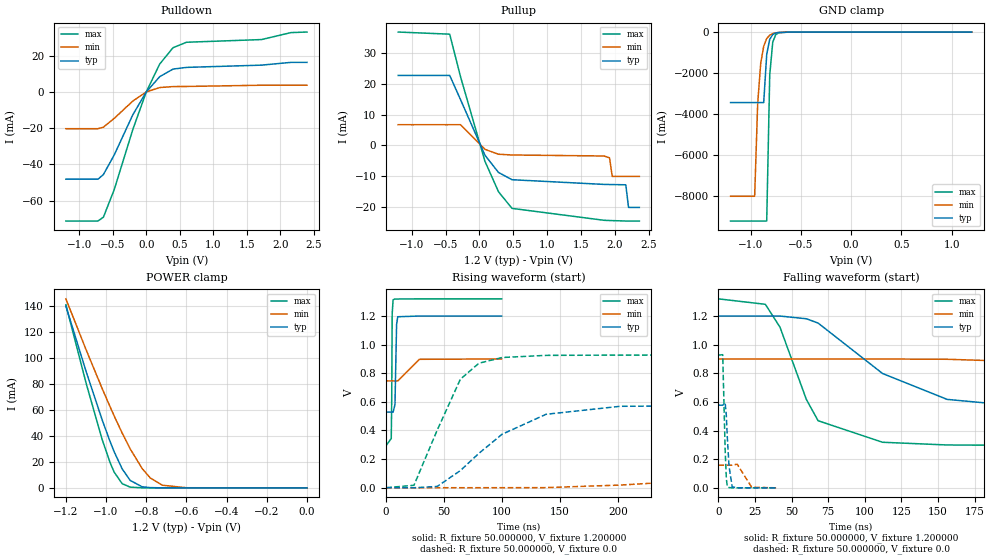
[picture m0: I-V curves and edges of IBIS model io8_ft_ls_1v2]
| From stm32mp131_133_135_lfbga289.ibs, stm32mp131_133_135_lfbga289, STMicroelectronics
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|   Model io8_ft_ls_1v2
[Model]  io8_ft_ls_1v2
Model_type I/O
Polarity   Non-Inverting
Enable   Active-Low
Vinl =   0.360000V
Vinh =   0.840000V
Vmeas =  0.600000V
Cref =   50.000000pF
Rref =   100.000000M
Vref =   0.0V
C_comp   2.961900pF   2.937700pF   2.984500pF
[Temperature Range]   25.000000   0.140000k   -40.000000
[Pullup Reference]   1.200000V   0.900000V   1.320000V
[Pulldown Reference]   0.0V   0.0V   0.0V
[POWER Clamp Reference]   1.200000V   0.900000V   1.320000V
[GND Clamp Reference]   0.0V   0.0V   0.0V
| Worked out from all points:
|   slope of the pulldown table from 0 to 0.18 V, typ, clamps not added: 23.2 ohm
|   slope of the pullup table from 0 to 0.18 V, typ, clamps not added: 28.5 ohm
|   GND clamp passes 1 mA (typ) near -0.47 V on its own axis
|   POWER clamp passes 1 mA (typ) near -0.83 V on its own axis
|   rising waveform, R_fixture 50.000000, V_fixture 1.200000: 20-80 % time 810ps typ, 2.62ns min, 429ps max; typ from 0.529 V to 1.2 V
|   rising waveform, R_fixture 50.000000, V_fixture 0.0: 20-80 % time 55.8ns typ, 161ns min, 28.4ns max; typ from 0 V to 0.577 V
|   falling waveform, R_fixture 50.000000, V_fixture 1.200000: 20-80 % time 58ns typ, 166ns min, 23.4ns max; typ from 1.2 V to 0.529 V
|   falling waveform, R_fixture 50.000000, V_fixture 0.0: 20-80 % time 2.01ns typ, 4.77ns min, 1.41ns max; typ from 0.577 V to 0 V
[Pulldown]
|Voltage   I(typ)   I(min)   I(max)
-1.2V     -48.14mA   -20.28mA   -71.24mA
-720mV    -48.14mA   -20.28mA   -71.24mA
-640mV    -45.58mA   -19.44mA   -69.11mA
-480mV    -34.9mA    -14.62mA   -54.1mA
-200mV    -12.54mA   -4.989mA   -20.65mA
0V        0A         0A         0A
200mV     8.434mA    2.44mA     15.39mA
400mV     12.64mA    2.983mA    24.45mA
600mV     13.57mA    3.041mA    27.45mA
1.72V     14.81mA    3.724mA    28.93mA
2.16V     16.34mA    3.724mA    32.78mA
2.4V      16.34mA    3.724mA    33.09mA
[Pullup]
|Voltage   I(typ)   I(min)   I(max)
-1.2V     22.63mA    6.709mA    36.64mA
-440mV    22.63mA    6.709mA    35.95mA
-280mV    14.81mA    6.709mA    22.2mA
80mV      -3.13mA    -1.249mA   -5.09mA
280mV     -8.709mA   -2.831mA   -14.93mA
480mV     -11.06mA   -3.074mA   -20.32mA
1.84V     -12.58mA   -3.4mA     -24.17mA
1.92V     -12.61mA   -4mA       -24.24mA
1.96V     -12.63mA   -10mA      -24.27mA
2.16V     -12.7mA    -10mA      -24.4mA
2.2V      -20mA      -10mA      -24.4mA
2.36V     -20mA      -10mA      -24.4mA
[GND_clamp]
|Voltage   I(typ)   I(min)   I(max)
-1.2V     -3.45A     -8.037A    -9.248A
-960mV    -3.45A     -8.037A    -9.248A
-930mV    -3.45A     -3.504A    -9.248A
-900mV    -3.45A     -1.544A    -9.248A
-870mV    -3.45A     -693.1mA   -9.248A
-840mV    -1.093A    -319.7mA   -9.248A
-810mV    -355mA     -153mA     -2.104A
-780mV    -122.1mA   -76.47mA   -492.8mA
-750mV    -46.85mA   -40.02mA   -125.6mA
-720mV    -21.41mA   -22.04mA   -38.94mA
-630mV    -6.028mA   -5.668mA   -6.589mA
1.2V      0A         44.19nA    0A
[POWER_clamp]
|Voltage   I(typ)   I(min)   I(max)
-1.2V     139.7mA    145.3mA    140.7mA
-1.1V     89.79mA    106.4mA    80.86mA
-1.02V    52.48mA    76.58mA    37.41mA
-980mV    35.57mA    62.3mA     19.38mA
-960mV    27.85mA    55.39mA    12.18mA
-920mV    14.63mA    42.15mA    3.226mA
-880mV    5.71mA     29.97mA    537.4uA
-820mV    777uA      14.76mA    28.17uA
-780mV    170.8uA    7.604mA    3.856uA
-720mV    16.71uA    2.018mA    195.3nA
-600mV    157.7nA    78.69uA    0A
0V        0A         56.62nA    0A
[Ramp]
| variable   typ   min   max
dV/dt_r  0.34638/55.73551n   95.16562m/0.16077u  0.55615/28.34400n
dV/dt_f  0.40279/57.96058n   92.02200m/0.16561u  0.61499/23.31715n
R_load = 50.000000
[Rising Waveform]
R_fixture= 50.000000
V_fixture= 1.200000
V_fixture_min= 0.900000
V_fixture_max= 1.320000
|time   V(typ)   V(min)   V(max)
0s        528.7mV    746.7mV    295mV
4.404ns   528.7mV    746.7mV    344.3mV
4.805ns   528.7mV    746.7mV    622.8mV
5.205ns   528.7mV    746.7mV    1.216V
6.006ns   528.2mV    746.7mV    1.314V
7.608ns   580.9mV    746.7mV    1.319V
9.009ns   1.141V     746.7mV    1.319V
10.01ns   1.195V     746.7mV    1.319V
28.63ns   1.2V       897.6mV    1.32V
99.7ns    1.2V       900mV      1.32V
[Rising Waveform]
R_fixture= 50.000000
V_fixture= 0.0
V_fixture_min= 0.0
V_fixture_max= 0.0
|time   V(typ)   V(min)   V(max)
0s        2.345nV    636.1nV    922.7pV
24.02ns   -141.1uV   -931.8uV   17.18mV
44.04ns   8.825mV    -31.22uV   401.7mV
64.06ns   119.6mV    -21.33uV   758.1mV
80.08ns   240.1mV    31.02uV    870.2mV
100.1ns   373.8mV    122.6uV    910mV
138.1ns   513.2mV    840.2uV    925.1mV
202.2ns   569.2mV    18.48mV    926.9mV
466.5ns   577.2mV    147.1mV    926.9mV
997ns     577.3mV    158.7mV    926.9mV
[Falling Waveform]
R_fixture= 50.000000
V_fixture= 1.200000
V_fixture_min= 0.900000
V_fixture_max= 1.320000
|time   V(typ)   V(min)   V(max)
0s        1.2V       900mV      1.32V
32.03ns   1.2V       900.3mV    1.282V
42.04ns   1.2V       900mV      1.122V
60.06ns   1.181V     900mV      617.2mV
68.07ns   1.151V     900mV      468.8mV
112.1ns   798.8mV    899.9mV    318.4mV
156.2ns   617.9mV    898.1mV    299.5mV
234.2ns   544mV      872.9mV    295.3mV
442.4ns   528.8mV    767.3mV    295mV
997ns     528.7mV    746.7mV    295mV
[Falling Waveform]
R_fixture= 50.000000
V_fixture= 0.0
V_fixture_min= 0.0
V_fixture_max= 0.0
|time   V(typ)   V(min)   V(max)
0s        577.3mV    158.7mV    926.9mV
2.883ns   577.3mV    158.7mV    930.2mV
4.565ns   592.3mV    158.7mV    263.9mV
5.365ns   503.8mV    158.7mV    65.13mV
6.006ns   356.9mV    158.7mV    8.836mV
7.207ns   150mV      158.7mV    1.805mV
9.369ns   6.488mV    158.6mV    332.5uV
12.81ns   436.3uV    165mV      88.28uV
22.66ns   4.733uV    4.383mV    25.44uV
39.88ns   2.345nV    636.1nV    922.7pV
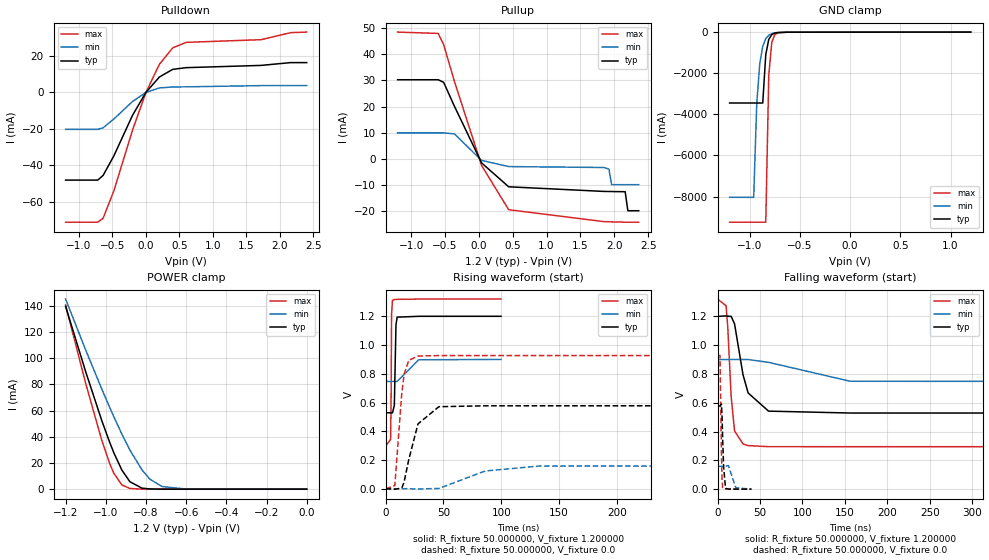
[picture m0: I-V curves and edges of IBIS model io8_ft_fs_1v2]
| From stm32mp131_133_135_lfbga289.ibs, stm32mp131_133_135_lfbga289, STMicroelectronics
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|   Model io8_ft_fs_1v2
[Model]  io8_ft_fs_1v2
Model_type I/O
Polarity   Non-Inverting
Enable   Active-Low
Vinl =   0.360000V
Vinh =   0.840000V
Vmeas =  0.600000V
Cref =   50.000000pF
Rref =   100.000000M
Vref =   0.0V
C_comp   2.961900pF   2.937700pF   2.984500pF
[Temperature Range]   25.000000   0.140000k   -40.000000
[Pullup Reference]   1.200000V   0.900000V   1.320000V
[Pulldown Reference]   0.0V   0.0V   0.0V
[POWER Clamp Reference]   1.200000V   0.900000V   1.320000V
[GND Clamp Reference]   0.0V   0.0V   0.0V
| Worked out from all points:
|   slope of the pulldown table from 0 to 0.18 V, typ, clamps not added: 23.2 ohm
|   slope of the pullup table from 0 to 0.18 V, typ, clamps not added: 28.5 ohm
|   GND clamp passes 1 mA (typ) near -0.47 V on its own axis
|   POWER clamp passes 1 mA (typ) near -0.83 V on its own axis
|   rising waveform, R_fixture 50.000000, V_fixture 1.200000: 20-80 % time 804ps typ, 2.62ns min, 429ps max; typ from 0.529 V to 1.2 V
|   rising waveform, R_fixture 50.000000, V_fixture 0.0: 20-80 % time 10.7ns typ, 29.3ns min, 5.51ns max; typ from 0 V to 0.577 V
|   falling waveform, R_fixture 50.000000, V_fixture 1.200000: 20-80 % time 13.6ns typ, 36.3ns min, 5.59ns max; typ from 1.2 V to 0.529 V
|   falling waveform, R_fixture 50.000000, V_fixture 0.0: 20-80 % time 2.02ns typ, 4.76ns min, 1.41ns max; typ from 0.577 V to 0 V
[Pulldown]
|Voltage   I(typ)   I(min)   I(max)
-1.2V     -48.14mA   -20.28mA   -71.24mA
-720mV    -48.14mA   -20.28mA   -71.24mA
-640mV    -45.58mA   -19.44mA   -69.11mA
-480mV    -34.9mA    -14.62mA   -54.1mA
-200mV    -12.54mA   -4.99mA    -20.65mA
0V        0A         0A         0A
200mV     8.434mA    2.44mA     15.39mA
400mV     12.64mA    2.983mA    24.45mA
600mV     13.57mA    3.042mA    27.45mA
1.72V     14.81mA    3.724mA    28.93mA
2.16V     16.34mA    3.724mA    32.78mA
2.4V      16.34mA    3.724mA    33.09mA
[Pullup]
|Voltage   I(typ)   I(min)   I(max)
-1.2V     30.28mA    9.902mA    48.58mA
-600mV    30.28mA    9.902mA    48.06mA
-520mV    29.3mA     9.902mA    43.76mA
-360mV    20.06mA    9.471mA    29.58mA
40mV      -1.628mA   -670.7uA   -2.623mA
440mV     -10.81mA   -3.051mA   -19.6mA
1.84V     -12.58mA   -3.4mA     -24.17mA
1.92V     -12.61mA   -4mA       -24.24mA
1.96V     -12.63mA   -10mA      -24.27mA
2.16V     -12.7mA    -10mA      -24.4mA
2.2V      -20mA      -10mA      -24.4mA
2.36V     -20mA      -10mA      -24.4mA
[GND_clamp]
|Voltage   I(typ)   I(min)   I(max)
-1.2V     -3.45A     -8.037A    -9.248A
-960mV    -3.45A     -8.037A    -9.248A
-930mV    -3.45A     -3.504A    -9.248A
-900mV    -3.45A     -1.544A    -9.248A
-870mV    -3.45A     -693.1mA   -9.248A
-840mV    -1.093A    -319.7mA   -9.248A
-810mV    -355mA     -153mA     -2.104A
-780mV    -122.1mA   -76.47mA   -492.8mA
-750mV    -46.85mA   -40.02mA   -125.6mA
-720mV    -21.41mA   -22.04mA   -38.94mA
-630mV    -6.028mA   -5.668mA   -6.589mA
1.2V      0A         44.19nA    0A
[POWER_clamp]
|Voltage   I(typ)   I(min)   I(max)
-1.2V     139.7mA    145.3mA    140.7mA
-1.1V     89.79mA    106.4mA    80.86mA
-1.02V    52.48mA    76.58mA    37.41mA
-980mV    35.57mA    62.3mA     19.38mA
-960mV    27.85mA    55.39mA    12.18mA
-920mV    14.63mA    42.15mA    3.226mA
-880mV    5.71mA     29.97mA    537.4uA
-820mV    777uA      14.76mA    28.17uA
-780mV    170.8uA    7.604mA    3.856uA
-720mV    16.71uA    2.018mA    195.3nA
-600mV    157.7nA    78.69uA    0A
0V        0A         56.62nA    0A
[Ramp]
| variable   typ   min   max
dV/dt_r  0.34636/10.60753n   95.23162m/29.26969n 0.55615/5.31109n
dV/dt_f  0.40279/13.54092n   92.01000m/36.22856n 0.61499/5.49395n
R_load = 50.000000
[Rising Waveform]
R_fixture= 50.000000
V_fixture= 1.200000
V_fixture_min= 0.900000
V_fixture_max= 1.320000
|time   V(typ)   V(min)   V(max)
0s        528.7mV    746.6mV    295mV
4.404ns   528.7mV    746.6mV    343.9mV
4.805ns   528.7mV    746.6mV    621.1mV
5.205ns   528.7mV    746.6mV    1.214V
6.006ns   528.2mV    746.6mV    1.312V
7.608ns   580.2mV    746.6mV    1.317V
9.009ns   1.14V      746.6mV    1.317V
10.01ns   1.194V     746.6mV    1.318V
28.63ns   1.2V       897.4mV    1.32V
99.7ns    1.2V       900mV      1.32V
[Rising Waveform]
R_fixture= 50.000000
V_fixture= 0.0
V_fixture_min= 0.0
V_fixture_max= 0.0
|time   V(typ)   V(min)   V(max)
0s        2.345nV    636nV      922.7pV
8.008ns   -2.94mV    635.6nV    21.45mV
14.01ns   4.201mV    699.6nV    661.9mV
16.02ns   46.31mV    -1.753uV   795.9mV
20.02ns   201.4mV    39.92uV    893.2mV
28.03ns   451.2mV    -1.963mV   923.3mV
46.05ns   571mV      2.157mV    926.8mV
86.09ns   577.1mV    123.6mV    926.9mV
132.1ns   577.2mV    157.5mV    926.9mV
997ns     577.3mV    158.7mV    926.9mV
[Falling Waveform]
R_fixture= 50.000000
V_fixture= 1.200000
V_fixture_min= 0.900000
V_fixture_max= 1.320000
|time   V(typ)   V(min)   V(max)
0s        1.2V       900mV      1.32V
10.01ns   1.203V     900mV      1.274V
12.01ns   1.201V     899.9mV    1.129V
16.02ns   1.2V       900.9mV    645.5mV
20.02ns   1.148V     900.7mV    404.1mV
30.03ns   793.9mV    900.4mV    314mV
36.04ns   668.1mV    900.1mV    302.3mV
60.06ns   541.9mV    880.7mV    295.2mV
156.2ns   528.7mV    749.3mV    295mV
997ns     528.7mV    746.6mV    295mV
[Falling Waveform]
R_fixture= 50.000000
V_fixture= 0.0
V_fixture_min= 0.0
V_fixture_max= 0.0
|time   V(typ)   V(min)   V(max)
0s        577.3mV    158.7mV    926.9mV
2.883ns   577.3mV    158.7mV    929mV
4.565ns   590.8mV    158.7mV    262.9mV
5.365ns   502mV      158.7mV    65.1mV
6.006ns   354.9mV    158.7mV    9.849mV
7.207ns   149.3mV    158.7mV    2.954mV
9.449ns   5.48mV     158.6mV    1.574mV
12.81ns   910.6uV    164.1mV    793.1uV
21.54ns   477.6uV    9.491mV    156.6uV
39.88ns   2.345nV    636nV      922.7pV
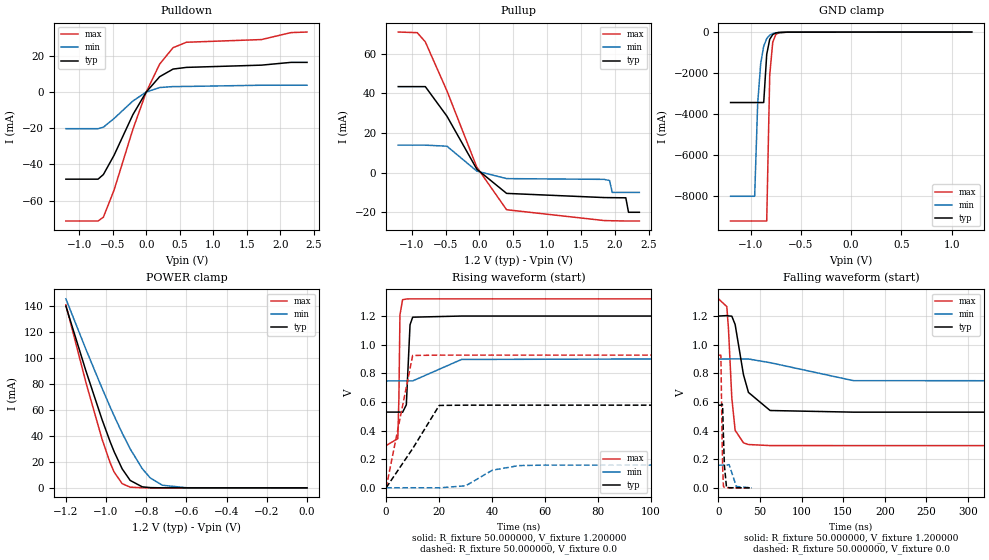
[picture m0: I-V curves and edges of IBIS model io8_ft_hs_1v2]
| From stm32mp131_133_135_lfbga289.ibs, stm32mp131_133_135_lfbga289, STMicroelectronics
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|   Model io8_ft_hs_1v2
[Model]  io8_ft_hs_1v2
Model_type I/O
Polarity   Non-Inverting
Enable   Active-Low
Vinl =   0.360000V
Vinh =   0.840000V
Vmeas =  0.600000V
Cref =   50.000000pF
Rref =   100.000000M
Vref =   0.0V
C_comp   2.961900pF   2.937700pF   2.984500pF
[Temperature Range]   25.000000   0.140000k   -40.000000
[Pullup Reference]   1.200000V   0.900000V   1.320000V
[Pulldown Reference]   0.0V   0.0V   0.0V
[POWER Clamp Reference]   1.200000V   0.900000V   1.320000V
[GND Clamp Reference]   0.0V   0.0V   0.0V
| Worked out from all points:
|   slope of the pulldown table from 0 to 0.18 V, typ, clamps not added: 23.2 ohm
|   slope of the pullup table from 0 to 0.18 V, typ, clamps not added: 28.5 ohm
|   GND clamp passes 1 mA (typ) near -0.47 V on its own axis
|   POWER clamp passes 1 mA (typ) near -0.83 V on its own axis
|   rising waveform, R_fixture 50.000000, V_fixture 1.200000: 20-80 % time 805ps typ, 2.57ns min, 432ps max; typ from 0.529 V to 1.2 V
|   rising waveform, R_fixture 50.000000, V_fixture 0.0: 20-80 % time 12ns typ, 9.76ns min, 6.02ns max; typ from 0 V to 0.577 V
|   falling waveform, R_fixture 50.000000, V_fixture 1.200000: 20-80 % time 13.8ns typ, 36.2ns min, 5.67ns max; typ from 1.2 V to 0.529 V
|   falling waveform, R_fixture 50.000000, V_fixture 0.0: 20-80 % time 2.02ns typ, 4.76ns min, 1.41ns max; typ from 0.577 V to 0 V
[Pulldown]
|Voltage   I(typ)   I(min)   I(max)
-1.2V     -48.14mA   -20.28mA   -71.24mA
-720mV    -48.14mA   -20.28mA   -71.24mA
-640mV    -45.58mA   -19.44mA   -69.11mA
-480mV    -34.9mA    -14.62mA   -54.1mA
-200mV    -12.54mA   -4.99mA    -20.65mA
0V        0A         0A         0A
200mV     8.434mA    2.44mA     15.39mA
400mV     12.64mA    2.983mA    24.45mA
600mV     13.57mA    3.042mA    27.45mA
1.72V     14.81mA    3.724mA    28.93mA
2.16V     16.34mA    3.724mA    32.78mA
2.4V      16.34mA    3.724mA    33.09mA
[Pullup]
|Voltage   I(typ)   I(min)   I(max)
-1.2V     43.36mA    13.85mA    70.88mA
-920mV    43.36mA    13.85mA    70.57mA
-800mV    43.36mA    13.85mA    65.93mA
-480mV    28.42mA    13.32mA    41.16mA
-40mV     1.753mA    765uA      2.773mA
400mV     -10.47mA   -3.023mA   -18.71mA
1.84V     -12.58mA   -3.4mA     -24.17mA
1.92V     -12.61mA   -4mA       -24.24mA
1.96V     -12.63mA   -10mA      -24.27mA
2.16V     -12.7mA    -10mA      -24.4mA
2.2V      -20mA      -10mA      -24.4mA
2.36V     -20mA      -10mA      -24.4mA
[GND_clamp]
|Voltage   I(typ)   I(min)   I(max)
-1.2V     -3.45A     -8.037A    -9.248A
-960mV    -3.45A     -8.037A    -9.248A
-930mV    -3.45A     -3.504A    -9.248A
-900mV    -3.45A     -1.544A    -9.248A
-870mV    -3.45A     -693.1mA   -9.248A
-840mV    -1.093A    -319.7mA   -9.248A
-810mV    -355mA     -153mA     -2.104A
-780mV    -122.1mA   -76.47mA   -492.8mA
-750mV    -46.85mA   -40.02mA   -125.6mA
-720mV    -21.41mA   -22.04mA   -38.94mA
-630mV    -6.028mA   -5.668mA   -6.589mA
1.2V      0A         44.19nA    0A
[POWER_clamp]
|Voltage   I(typ)   I(min)   I(max)
-1.2V     139.7mA    145.3mA    140.7mA
-1.1V     89.79mA    106.4mA    80.86mA
-1.02V    52.48mA    76.58mA    37.41mA
-980mV    35.57mA    62.3mA     19.38mA
-960mV    27.85mA    55.39mA    12.18mA
-920mV    14.63mA    42.15mA    3.226mA
-880mV    5.71mA     29.97mA    537.4uA
-820mV    777uA      14.76mA    28.17uA
-780mV    170.8uA    7.604mA    3.856uA
-720mV    16.71uA    2.018mA    195.3nA
-600mV    157.7nA    78.69uA    0A
0V        0A         56.62nA    0A
[Ramp]
| variable   typ   min   max
dV/dt_r  0.34636/3.33019n   95.23762m/8.95409n  0.55615/1.79980n
dV/dt_f  0.40279/13.72677n   92.01600m/36.09763n 0.61499/5.55050n
R_load = 50.000000
[Rising Waveform]
R_fixture= 50.000000
V_fixture= 1.200000
V_fixture_min= 0.900000
V_fixture_max= 1.320000
|time   V(typ)   V(min)   V(max)
0s        528.7mV    746.6mV    295mV
4.404ns   528.7mV    746.6mV    343.3mV
4.805ns   528.7mV    746.6mV    624.7mV
5.205ns   528.7mV    746.6mV    1.209V
6.206ns   527.4mV    746.6mV    1.314V
7.608ns   579.4mV    746.6mV    1.319V
9.009ns   1.139V     746.6mV    1.32V
10.01ns   1.192V     746.6mV    1.32V
28.43ns   1.2V       896.5mV    1.32V
99.7ns    1.2V       900mV      1.32V
[Rising Waveform]
R_fixture= 50.000000
V_fixture= 0.0
V_fixture_min= 0.0
V_fixture_max= 0.0
|time   V(typ)   V(min)   V(max)
0s        9.363nV    634.2nV    -5.299nV
10.01ns   273.7mV    634.1nV    924.5mV
20.02ns   575.3mV    -702.8uV   926.9mV
30.03ns   577.2mV    13.8mV     926.9mV
40.04ns   577.2mV    122.4mV    926.9mV
50.05ns   577.2mV    155mV      926.9mV
60.06ns   577.2mV    158.3mV    926.9mV
991ns     577.3mV    158.7mV    926.9mV
[Falling Waveform]
R_fixture= 50.000000
V_fixture= 1.200000
V_fixture_min= 0.900000
V_fixture_max= 1.320000
|time   V(typ)   V(min)   V(max)
0s        1.2V       900mV      1.32V
10.01ns   1.203V     900mV      1.266V
12.01ns   1.201V     899.9mV    1.111V
16.02ns   1.199V     900.9mV    628.2mV
20.02ns   1.141V     900.7mV    402.3mV
30.03ns   790.5mV    900.4mV    314.4mV
36.04ns   666.6mV    900.1mV    302.6mV
62.06ns   540.2mV    874.5mV    295.2mV
162.2ns   528.7mV    748.8mV    295mV
997ns     528.7mV    746.6mV    295mV
[Falling Waveform]
R_fixture= 50.000000
V_fixture= 0.0
V_fixture_min= 0.0
V_fixture_max= 0.0
|time   V(typ)   V(min)   V(max)
0s        577.3mV    158.7mV    926.9mV
2.883ns   577.3mV    158.7mV    926.2mV
4.484ns   585mV      158.7mV    282.9mV
4.965ns   574.7mV    158.7mV    149mV
5.926ns   368.9mV    158.7mV    11.45mV
7.127ns   155.5mV    158.7mV    3.08mV
9.61ns    4.03mV     158.6mV    1.538mV
12.81ns   921.9uV    162.2mV    760.2uV
21.46ns   468.3uV    9.586mV    147.5uV
39.88ns   9.363nV    634.2nV    -5.299nV
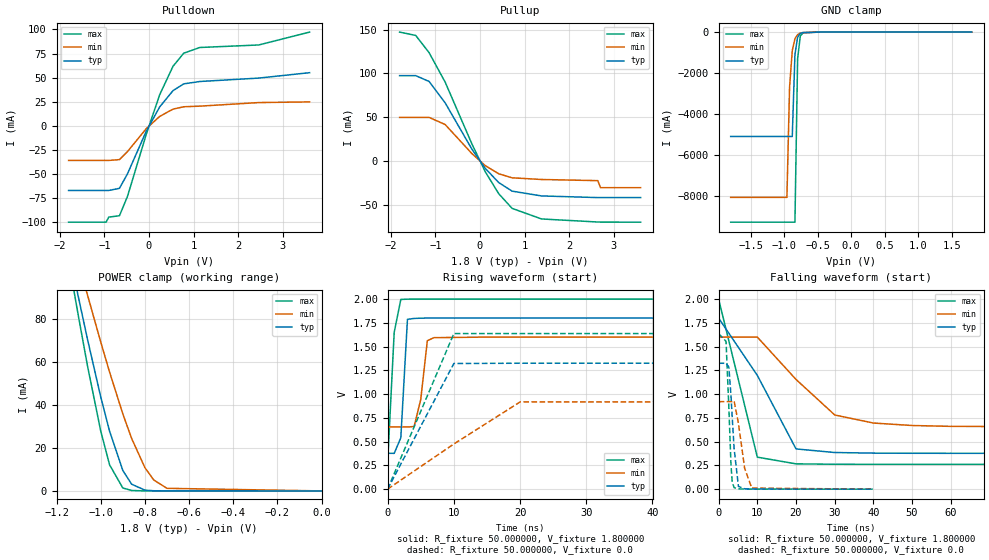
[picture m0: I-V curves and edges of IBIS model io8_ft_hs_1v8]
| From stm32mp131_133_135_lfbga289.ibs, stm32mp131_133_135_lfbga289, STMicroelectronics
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|   Model io8_ft_hs_1v8
[Model]  io8_ft_hs_1v8
Model_type I/O
Polarity   Non-Inverting
Enable   Active-Low
Vinl =   0.540000V
Vinh =   1.260000V
Vmeas =  0.900000V
Cref =   50.000000pF
Rref =   100.000000M
Vref =   0.0V
C_comp   3.181500pF   3.164300pF   3.208900pF
[Temperature Range]   25.000000   0.140000k   -40.000000
[Pullup Reference]   1.800000V   1.600000V   2.000000V
[Pulldown Reference]   0.0V   0.0V   0.0V
[POWER Clamp Reference]   1.800000V   1.600000V   2.000000V
[GND Clamp Reference]   0.0V   0.0V   0.0V
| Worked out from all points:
|   slope of the pulldown table from 0 to 0.27 V, typ, clamps not added: 12.5 ohm
|   slope of the pullup table from 0 to 0.27 V, typ, clamps not added: 16 ohm
|   GND clamp passes 1 mA (typ) near -0.47 V on its own axis
|   POWER clamp passes 1 mA (typ) near -0.83 V on its own axis
|   rising waveform, R_fixture 50.000000, V_fixture 1.800000: 20-80 % time 686ps typ, 1.1ns min, 753ps max; typ from 0.377 V to 1.8 V
|   rising waveform, R_fixture 50.000000, V_fixture 0.0: 20-80 % time 6.02ns typ, 12ns min, 6.01ns max; typ from 0 V to 1.32 V
|   falling waveform, R_fixture 50.000000, V_fixture 1.800000: 20-80 % time 12.2ns typ, 14.1ns min, 6.28ns max; typ from 1.8 V to 0.377 V
|   falling waveform, R_fixture 50.000000, V_fixture 0.0: 20-80 % time 1.22ns typ, 1.91ns min, 860ps max; typ from 1.32 V to 0 V
[Pulldown]
|Voltage   I(typ)   I(min)   I(max)
-1.8V     -67.09mA   -35.91mA   -100mA
-960mV    -67.09mA   -35.91mA   -100mA
-900mV    -67.09mA   -35.91mA   -94.73mA
-660mV    -64.86mA   -35.04mA   -93.29mA
-480mV    -49.73mA   -26.7mA    -73.15mA
-60mV     -5.61mA    -2.937mA   -8.854mA
240mV     19.58mA    9.767mA    32.18mA
540mV     36.57mA    17.36mA    61.85mA
780mV     43.58mA    19.81mA    75.41mA
1.14V     46.02mA    20.44mA    81.32mA
2.46V     49.57mA    24.16mA    83.94mA
3.6V      55.18mA    24.86mA    97.31mA
[Pullup]
|Voltage   I(typ)   I(min)   I(max)
-1.8V     97.52mA    49.96mA    147.1mA
-1.44V    97.52mA    49.96mA    143.3mA
-1.14V    90.93mA    49.96mA    123.7mA
-780mV    66.55mA    41.87mA    90.17mA
-180mV    13.76mA    8.769mA    19.71mA
120mV     -8.082mA   -4.954mA   -11.99mA
420mV     -24.19mA   -14.18mA   -36.87mA
720mV     -33.97mA   -18.78mA   -53.57mA
1.38V     -39.41mA   -20.69mA   -65.63mA
2.64V     -41.3mA    -22mA      -69.09mA
2.7V      -41.3mA    -30mA      -69.18mA
3.6V      -41.3mA    -30mA      -69.3mA
[GND_clamp]
|Voltage   I(typ)   I(min)   I(max)
-1.8V     -5.08A     -8.044A    -9.251A
-960mV    -5.08A     -8.044A    -9.251A
-920mV    -5.08A     -2.669A    -9.251A
-880mV    -5.08A     -908mA     -9.251A
-840mV    -1.096A    -323.6mA   -9.251A
-800mV    -248.9mA   -123.7mA   -1.293A
-760mV    -64.81mA   -51.32mA   -196.6mA
-720mV    -22.13mA   -23.23mA   -39.69mA
-480mV    -1.149mA   -1.898mA   -936.1uA
1.8V      0A         44.33nA    0A
[POWER_clamp]
|Voltage   I(typ)   I(min)   I(max)
-1.8V     460.5mA    392.1mA    526.9mA
-1.12V    99.56mA    114.1mA    92.51mA
-1.1V     89.79mA    106.4mA    80.86mA
-1.06V    70.71mA    91.32mA    58.34mA
-1V       43.82mA    69.37mA    27.91mA
-960mV    27.85mA    55.39mA    12.18mA
-900mV    9.544mA    35.9mA     1.368mA
-860mV    3.133mA    24.42mA    203.6uA
-800mV    367uA      10.84mA    10.43uA
-760mV    78.93uA    5.095mA    1.426uA
-700mV    7.679uA    1.212mA    72.45nA
0V        0A         59.16nA    0A
[Ramp]
| variable   typ   min   max
dV/dt_r  0.79476/1.40432n   0.55240/3.24835n   0.98226/1.21879n
dV/dt_f  0.85363/4.40732n   0.56724/10.96329n   1.04297/2.49732n
R_load = 50.000000
[Rising Waveform]
R_fixture= 50.000000
V_fixture= 1.800000
V_fixture_min= 1.600000
V_fixture_max= 2.000000
|time   V(typ)   V(min)   V(max)
0s        377.3mV    654.6mV    261.4mV
1.001ns   376.7mV    654.6mV    1.651V
2.002ns   541.1mV    654.6mV    1.996V
3.003ns   1.787V     654.4mV    1.999V
4.004ns   1.796V     658.8mV    2V
5.005ns   1.799V     941.3mV    2V
6.006ns   1.8V       1.562V     2V
7.007ns   1.8V       1.594V     2V
15.02ns   1.8V       1.6V       2V
99.1ns    1.8V       1.6V       2V
[Rising Waveform]
R_fixture= 50.000000
V_fixture= 0.0
V_fixture_min= 0.0
V_fixture_max= 0.0
|time   V(typ)   V(min)   V(max)
0s        2.004nV    378.7nV    939.1pV
10.01ns   1.322V     475.6mV    1.637V
20.02ns   1.325V     917.9mV    1.637V
991ns     1.325V     920.7mV    1.637V
[Falling Waveform]
R_fixture= 50.000000
V_fixture= 1.800000
V_fixture_min= 1.600000
V_fixture_max= 2.000000
|time   V(typ)   V(min)   V(max)
0s        1.8V       1.6V       2V
10.01ns   1.197V     1.6V       336.8mV
20.02ns   423.3mV    1.154V     266.3mV
30.03ns   385.6mV    780.4mV    262mV
40.04ns   379.2mV    695.6mV    261.5mV
50.05ns   377.6mV    669.7mV    261.4mV
60.06ns   377.3mV    660.7mV    261.4mV
100.1ns   377.3mV    654.7mV    261.4mV
991ns     377.3mV    654.6mV    261.4mV
[Falling Waveform]
R_fixture= 50.000000
V_fixture= 0.0
V_fixture_min= 0.0
V_fixture_max= 0.0
|time   V(typ)   V(min)   V(max)
0s        1.325V     920.7mV    1.637V
1.922ns   1.324V     920.7mV    1.555V
2.643ns   1.285V     920.7mV    864.4mV
3.203ns   984.3mV    920.6mV    250.4mV
3.524ns   752mV      920.6mV    74.68mV
4.004ns   430mV      928.5mV    15.65mV
5.125ns   29.04mV    693mV      2.947mV
6.727ns   3.66mV     220.1mV    1.091mV
8.569ns   1.652mV    11.47mV    601.8uV
39.88ns   2.004nV    378.7nV    939.1pV
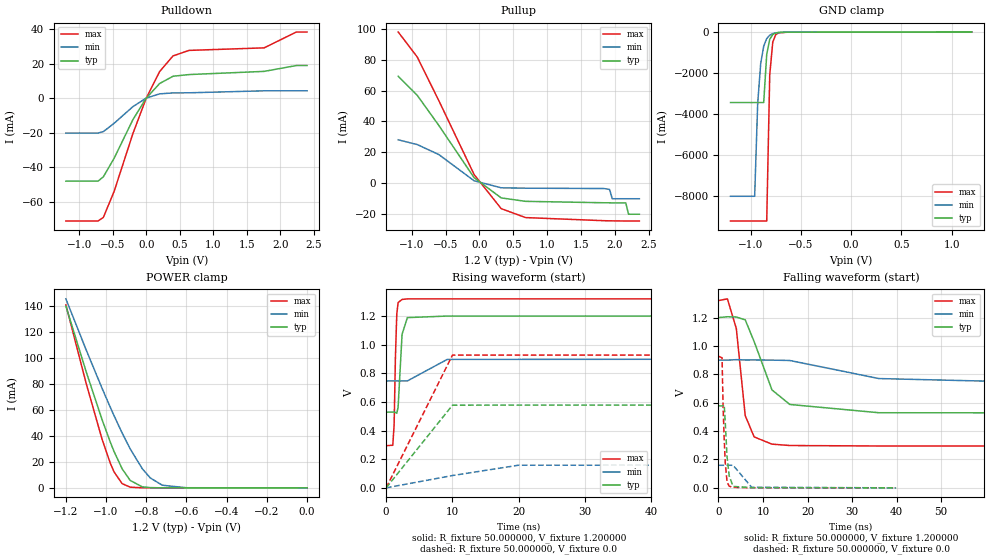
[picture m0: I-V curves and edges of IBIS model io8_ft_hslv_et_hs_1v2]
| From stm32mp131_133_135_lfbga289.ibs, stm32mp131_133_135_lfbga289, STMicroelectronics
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|   Model io8_ft_hslv_et_hs_1v2
[Model]  io8_ft_hslv_et_hs_1v2
Model_type I/O
Polarity   Non-Inverting
Enable   Active-Low
Vinl =   0.360000V
Vinh =   0.840000V
Vmeas =  0.600000V
Cref =   50.000000pF
Rref =   100.000000M
Vref =   0.0V
C_comp   2.961600pF   2.939400pF   2.982700pF
[Temperature Range]   25.000000   0.140000k   -40.000000
[Pullup Reference]   1.200000V   0.900000V   1.320000V
[Pulldown Reference]   0.0V   0.0V   0.0V
[POWER Clamp Reference]   1.200000V   0.900000V   1.320000V
[GND Clamp Reference]   0.0V   0.0V   0.0V
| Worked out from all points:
|   slope of the pulldown table from 0 to 0.18 V, typ, clamps not added: 23.2 ohm
|   slope of the pullup table from 0 to 0.18 V, typ, clamps not added: 28.5 ohm
|   GND clamp passes 1 mA (typ) near -0.47 V on its own axis
|   POWER clamp passes 1 mA (typ) near -0.83 V on its own axis
|   rising waveform, R_fixture 50.000000, V_fixture 1.200000: 20-80 % time 453ps typ, 1.1ns min, 309ps max; typ from 0.529 V to 1.2 V
|   rising waveform, R_fixture 50.000000, V_fixture 0.0: 20-80 % time 6.01ns typ, 12ns min, 6.01ns max; typ from 0 V to 0.578 V
|   falling waveform, R_fixture 50.000000, V_fixture 1.200000: 20-80 % time 5.32ns typ, 13ns min, 2.09ns max; typ from 1.2 V to 0.529 V
|   falling waveform, R_fixture 50.000000, V_fixture 0.0: 20-80 % time 725ps typ, 1.52ns min, 573ps max; typ from 0.578 V to 0 V
[Pulldown]
|Voltage   I(typ)   I(min)   I(max)
-1.2V     -48.14mA   -20.28mA   -71.24mA
-720mV    -48.14mA   -20.28mA   -71.24mA
-640mV    -45.58mA   -19.44mA   -69.11mA
-480mV    -34.9mA    -14.62mA   -54.1mA
-200mV    -12.54mA   -4.989mA   -20.65mA
0V        0A         -5pA       0A
200mV     8.434mA    2.44mA     15.39mA
400mV     12.64mA    2.983mA    24.45mA
640mV     13.62mA    3.049mA    27.62mA
1.76V     15.46mA    4.201mA    29.09mA
2.24V     18.85mA    4.201mA    38.26mA
2.4V      18.85mA    4.201mA    38.26mA
[Pullup]
|Voltage   I(typ)   I(min)   I(max)
-1.2V     69.21mA    28.12mA    97.81mA
-920mV    56.94mA    25.06mA    81.74mA
-600mV    37.38mA    18.57mA    53.39mA
-80mV     3.633mA    1.627mA    5.693mA
320mV     -9.44mA    -2.932mA   -16.39mA
680mV     -11.68mA   -3.162mA   -22.18mA
1.84V     -12.6mA    -3.4mA     -24.2mA
1.92V     -12.63mA   -4mA       -24.27mA
1.96V     -12.65mA   -10mA      -24.3mA
2.16V     -12.7mA    -10mA      -24.4mA
2.2V      -20mA      -10mA      -24.4mA
2.36V     -20mA      -10mA      -24.4mA
[GND_clamp]
|Voltage   I(typ)   I(min)   I(max)
-1.2V     -3.45A     -8.037A    -9.248A
-960mV    -3.45A     -8.037A    -9.248A
-930mV    -3.45A     -3.504A    -9.248A
-900mV    -3.45A     -1.544A    -9.248A
-870mV    -3.45A     -693.1mA   -9.248A
-840mV    -1.093A    -319.7mA   -9.248A
-810mV    -355mA     -153mA     -2.104A
-780mV    -122.1mA   -76.47mA   -492.8mA
-750mV    -46.85mA   -40.02mA   -125.6mA
-720mV    -21.41mA   -22.04mA   -38.94mA
-630mV    -6.028mA   -5.668mA   -6.589mA
1.2V      0A         44.1nA     0A
[POWER_clamp]
|Voltage   I(typ)   I(min)   I(max)
-1.2V     139.7mA    145.3mA    140.7mA
-1.1V     89.79mA    106.4mA    80.86mA
-1.02V    52.48mA    76.58mA    37.41mA
-980mV    35.57mA    62.3mA     19.38mA
-960mV    27.85mA    55.39mA    12.18mA
-920mV    14.63mA    42.15mA    3.226mA
-880mV    5.71mA     29.97mA    537.4uA
-820mV    777uA      14.76mA    28.17uA
-780mV    170.8uA    7.604mA    3.856uA
-720mV    16.71uA    2.018mA    195.3nA
-600mV    157.7nA    78.69uA    0A
0V        0A         56.62nA    0A
[Ramp]
| variable   typ   min   max
dV/dt_r  0.34679/1.24414n   95.42362m/2.80823n  0.55638/1.20868n
dV/dt_f  0.40279/5.10290n   91.98000m/12.94400n 0.61499/2.05624n
R_load = 50.000000
[Rising Waveform]
R_fixture= 50.000000
V_fixture= 1.200000
V_fixture_min= 0.900000
V_fixture_max= 1.320000
|time   V(typ)   V(min)   V(max)
0s        528.7mV    746.7mV    295mV
1.001ns   528.8mV    746.7mV    297.4mV
1.201ns   529.2mV    746.7mV    438.5mV
1.401ns   526.1mV    746.7mV    915.4mV
1.602ns   521.2mV    746.7mV    1.213V
1.802ns   562.7mV    746.7mV    1.294V
2.402ns   1.073V     746.7mV    1.316V
3.203ns   1.189V     746.8mV    1.32V
9.209ns   1.2V       897mV      1.32V
99.7ns    1.2V       900mV      1.32V
[Rising Waveform]
R_fixture= 50.000000
V_fixture= 0.0
V_fixture_min= 0.0
V_fixture_max= 0.0
|time   V(typ)   V(min)   V(max)
0s        2.355nV    640.5nV    922.8pV
10.01ns   577.3mV    85.91mV    927.2mV
20.02ns   578mV      158.4mV    927.3mV
991ns     578mV      159mV      927.3mV
[Falling Waveform]
R_fixture= 50.000000
V_fixture= 1.200000
V_fixture_min= 0.900000
V_fixture_max= 1.320000
|time   V(typ)   V(min)   V(max)
0s        1.2V       900mV      1.32V
2.002ns   1.206V     900mV      1.332V
4.004ns   1.204V     903.5mV    1.123V
6.006ns   1.184V     901.3mV    508.7mV
8.008ns   1.031V     901.5mV    358.9mV
12.01ns   690.3mV    900.3mV    308.1mV
16.02ns   587.7mV    897.7mV    298.3mV
36.04ns   529.4mV    770.3mV    295mV
66.07ns   528.7mV    747.6mV    295mV
997ns     528.7mV    746.7mV    295mV
[Falling Waveform]
R_fixture= 50.000000
V_fixture= 0.0
V_fixture_min= 0.0
V_fixture_max= 0.0
|time   V(typ)   V(min)   V(max)
0s        578mV      159mV      927.3mV
800.8ps   578mV      159mV      917mV
1.041ns   579.4mV    159.1mV    565.3mV
1.281ns   585.9mV    159.1mV    344.1mV
1.522ns   461.3mV    159.1mV    176.3mV
1.922ns   217mV      159mV      42.45mV
2.402ns   84.32mV    159.2mV    11.32mV
3.283ns   9.969mV    158.9mV    3.727mV
7.447ns   1.426mV    4.063mV    424.2uV
39.88ns   2.355nV    640.5nV    922.8pV
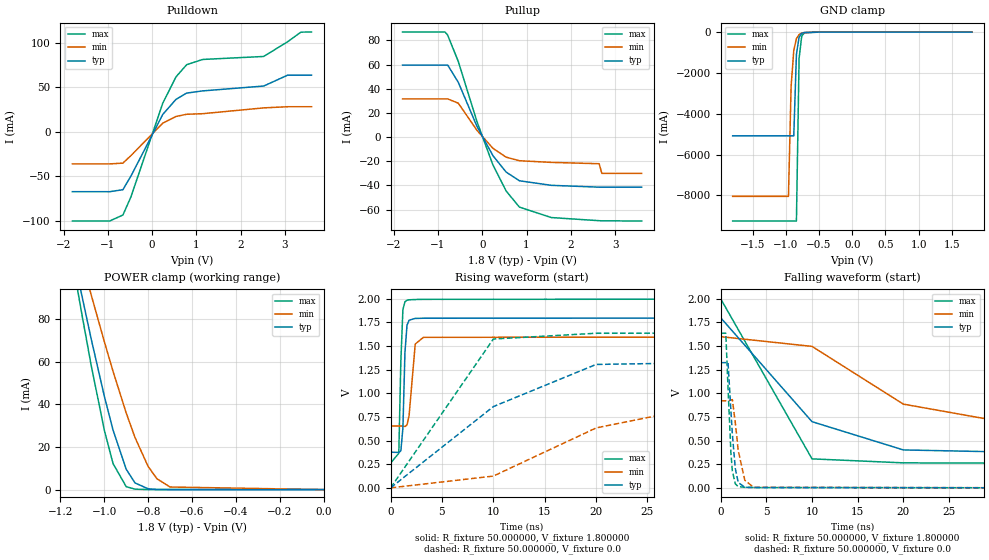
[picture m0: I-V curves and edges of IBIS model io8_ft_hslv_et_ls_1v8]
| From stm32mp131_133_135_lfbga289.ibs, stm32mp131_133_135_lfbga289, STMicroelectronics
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|   Model io8_ft_hslv_et_ls_1v8
[Model]  io8_ft_hslv_et_ls_1v8
Model_type I/O
Polarity   Non-Inverting
Enable   Active-Low
Vinl =   0.540000V
Vinh =   1.260000V
Vmeas =  0.900000V
Cref =   50.000000pF
Rref =   100.000000M
Vref =   0.0V
C_comp   3.177500pF   3.161600pF   3.207000pF
[Temperature Range]   25.000000   0.140000k   -40.000000
[Pullup Reference]   1.800000V   1.600000V   2.000000V
[Pulldown Reference]   0.0V   0.0V   0.0V
[POWER Clamp Reference]   1.800000V   1.600000V   2.000000V
[GND Clamp Reference]   0.0V   0.0V   0.0V
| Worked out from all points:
|   slope of the pulldown table from 0 to 0.27 V, typ, clamps not added: 12.5 ohm
|   slope of the pullup table from 0 to 0.27 V, typ, clamps not added: 16 ohm
|   GND clamp passes 1 mA (typ) near -0.47 V on its own axis
|   POWER clamp passes 1 mA (typ) near -0.83 V on its own axis
|   rising waveform, R_fixture 50.000000, V_fixture 1.800000: 20-80 % time 249ps typ, 396ps min, 264ps max; typ from 0.377 V to 1.8 V
|   rising waveform, R_fixture 50.000000, V_fixture 0.0: 20-80 % time 11.4ns typ, 13.5ns min, 6.24ns max; typ from 0 V to 1.32 V
|   falling waveform, R_fixture 50.000000, V_fixture 1.800000: 20-80 % time 8.7ns typ, 11.1ns min, 6.17ns max; typ from 1.8 V to 0.377 V
|   falling waveform, R_fixture 50.000000, V_fixture 0.0: 20-80 % time 543ps typ, 751ps min, 432ps max; typ from 1.32 V to 0 V
[Pulldown]
|Voltage   I(typ)   I(min)   I(max)
-1.8V     -67.09mA   -35.91mA   -100mA
-960mV    -67.09mA   -35.91mA   -100mA
-660mV    -64.86mA   -35.03mA   -93.29mA
-480mV    -49.73mA   -26.69mA   -73.15mA
240mV     19.58mA    9.766mA    32.18mA
540mV     36.57mA    17.36mA    61.85mA
780mV     43.58mA    19.8mA     75.41mA
1.14V     46.02mA    20.44mA    81.32mA
2.52V     51.5mA     26.97mA    84.69mA
3.06V     63.69mA    28.28mA    101.2mA
3.36V     63.69mA    28.28mA    112mA
3.6V      63.69mA    28.28mA    112.1mA
[Pullup]
|Voltage   I(typ)   I(min)   I(max)
-1.8V     59.6mA     31.64mA    86.95mA
-840mV    59.6mA     31.64mA    86.95mA
-780mV    59.6mA     31.64mA    84.36mA
-540mV    45.31mA    28.05mA    62.52mA
-120mV    8.966mA    5.671mA    12.94mA
240mV     -15.25mA   -9.194mA   -22.88mA
540mV     -28.92mA   -16.59mA   -44.59mA
840mV     -36.11mA   -19.53mA   -57.91mA
1.56V     -39.88mA   -20.9mA    -66.54mA
2.64V     -41.4mA    -22mA      -69.14mA
2.7V      -41.4mA    -30mA      -69.23mA
3.6V      -41.4mA    -30mA      -69.4mA
[GND_clamp]
|Voltage   I(typ)   I(min)   I(max)
-1.8V     -5.08A     -8.044A    -9.251A
-960mV    -5.08A     -8.044A    -9.251A
-920mV    -5.08A     -2.669A    -9.251A
-880mV    -5.08A     -908mA     -9.251A
-840mV    -1.096A    -323.6mA   -9.251A
-800mV    -248.9mA   -123.7mA   -1.293A
-760mV    -64.81mA   -51.32mA   -196.6mA
-720mV    -22.13mA   -23.23mA   -39.69mA
-480mV    -1.149mA   -1.898mA   -936.1uA
1.8V      0A         44.23nA    0A
[POWER_clamp]
|Voltage   I(typ)   I(min)   I(max)
-1.8V     460.5mA    392.1mA    526.9mA
-1.12V    99.56mA    114.1mA    92.51mA
-1.1V     89.79mA    106.4mA    80.86mA
-1.06V    70.71mA    91.32mA    58.34mA
-1V       43.82mA    69.37mA    27.91mA
-960mV    27.85mA    55.39mA    12.18mA
-900mV    9.544mA    35.9mA     1.368mA
-860mV    3.133mA    24.42mA    203.6uA
-800mV    367uA      10.84mA    10.43uA
-760mV    78.93uA    5.095mA    1.426uA
-700mV    7.679uA    1.212mA    72.46nA
0V        0A         59.16nA    0A
[Ramp]
| variable   typ   min   max
dV/dt_r  0.79494/5.26549n   0.55268/11.91215n   0.98232/3.18227n
dV/dt_f  0.85363/4.03858n   0.56721/9.70297n   1.04297/2.30940n
R_load = 50.000000
[Rising Waveform]
R_fixture= 50.000000
V_fixture= 1.800000
V_fixture_min= 1.600000
V_fixture_max= 2.000000
|time   V(typ)   V(min)   V(max)
0s        377.3mV    654.6mV    261.7mV
800.8ps   374.9mV    654.7mV    366mV
1.001ns   391.2mV    654.6mV    1.34V
1.201ns   633.1mV    654.6mV    1.888V
1.401ns   1.435V     648.9mV    1.969V
1.602ns   1.722V     666.6mV    1.986V
1.802ns   1.774V     763.4mV    1.99V
2.402ns   1.793V     1.522V     1.993V
3.203ns   1.795V     1.593V     1.995V
99.7ns    1.8V       1.6V       2V
[Rising Waveform]
R_fixture= 50.000000
V_fixture= 0.0
V_fixture_min= 0.0
V_fixture_max= 0.0
|time   V(typ)   V(min)   V(max)
0s        2.011nV    381.3nV    939.1pV
10.01ns   859.8mV    124.4mV    1.575V
20.02ns   1.306V     633.8mV    1.636V
30.03ns   1.323V     853.8mV    1.637V
40.04ns   1.325V     904.2mV    1.637V
60.06ns   1.325V     919.8mV    1.637V
991ns     1.325V     921.2mV    1.637V
[Falling Waveform]
R_fixture= 50.000000
V_fixture= 1.800000
V_fixture_min= 1.600000
V_fixture_max= 2.000000
|time   V(typ)   V(min)   V(max)
0s        1.8V       1.6V       2V
10.01ns   700.2mV    1.497V     306.7mV
20.02ns   401.3mV    886.1mV    264.4mV
30.03ns   381.6mV    713.9mV    261.9mV
40.04ns   378mV      673.7mV    261.7mV
60.06ns   377.3mV    656.9mV    261.7mV
991ns     377.3mV    654.6mV    261.7mV
[Falling Waveform]
R_fixture= 50.000000
V_fixture= 0.0
V_fixture_min= 0.0
V_fixture_max= 0.0
|time   V(typ)   V(min)   V(max)
0s        1.325V     921.2mV    1.637V
560.6ps   1.325V     921.2mV    1.636V
800.8ps   1.329V     921.4mV    1.065V
1.121ns   814.1mV    929.4mV    368mV
1.281ns   563.3mV    933.8mV    176.3mV
1.602ns   204.6mV    688.5mV    43.04mV
1.922ns   56.44mV    394.4mV    13.32mV
2.643ns   5.492mV    81.07mV    5.267mV
3.604ns   2.831mV    5.351mV    3.795mV
39.88ns   2.011nV    381.3nV    939.1pV
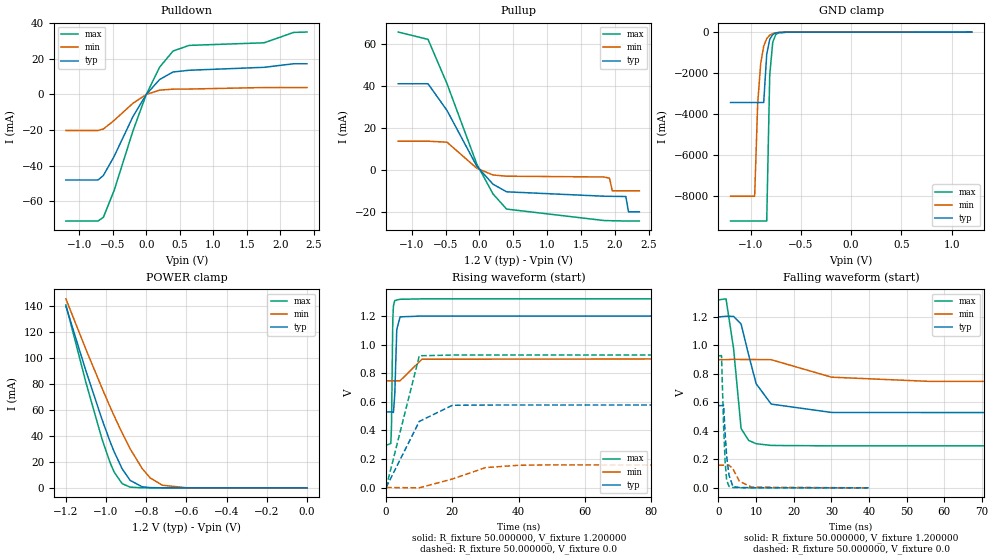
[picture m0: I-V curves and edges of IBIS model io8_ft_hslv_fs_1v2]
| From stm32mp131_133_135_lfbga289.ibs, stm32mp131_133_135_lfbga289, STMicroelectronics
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|   Model io8_ft_hslv_fs_1v2
[Model]  io8_ft_hslv_fs_1v2
Model_type I/O
Polarity   Non-Inverting
Enable   Active-Low
Vinl =   0.360000V
Vinh =   0.840000V
Vmeas =  0.600000V
Cref =   50.000000pF
Rref =   100.000000M
Vref =   0.0V
C_comp   2.940600pF   2.918400pF   2.961700pF
[Temperature Range]   25.000000   0.140000k   -40.000000
[Pullup Reference]   1.200000V   0.900000V   1.320000V
[Pulldown Reference]   0.0V   0.0V   0.0V
[POWER Clamp Reference]   1.200000V   0.900000V   1.320000V
[GND Clamp Reference]   0.0V   0.0V   0.0V
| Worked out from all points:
|   slope of the pulldown table from 0 to 0.18 V, typ, clamps not added: 23.2 ohm
|   slope of the pullup table from 0 to 0.18 V, typ, clamps not added: 28.5 ohm
|   GND clamp passes 1 mA (typ) near -0.47 V on its own axis
|   POWER clamp passes 1 mA (typ) near -0.83 V on its own axis
|   rising waveform, R_fixture 50.000000, V_fixture 1.200000: 20-80 % time 522ps typ, 1.42ns min, 325ps max; typ from 0.529 V to 1.2 V
|   rising waveform, R_fixture 50.000000, V_fixture 0.0: 20-80 % time 7.49ns typ, 13ns min, 6.04ns max; typ from 0 V to 0.577 V
|   falling waveform, R_fixture 50.000000, V_fixture 1.200000: 20-80 % time 4.68ns typ, 11.2ns min, 2.49ns max; typ from 1.2 V to 0.529 V
|   falling waveform, R_fixture 50.000000, V_fixture 0.0: 20-80 % time 1.02ns typ, 2.31ns min, 757ps max; typ from 0.577 V to 0 V
[Pulldown]
|Voltage   I(typ)   I(min)   I(max)
-1.2V     -48.14mA   -20.28mA   -71.24mA
-720mV    -48.14mA   -20.28mA   -71.24mA
-640mV    -45.58mA   -19.44mA   -69.11mA
-480mV    -34.9mA    -14.62mA   -54.1mA
-200mV    -12.54mA   -4.989mA   -20.65mA
0V        0A         -3pA       0A
200mV     8.434mA    2.44mA     15.39mA
400mV     12.64mA    2.983mA    24.45mA
640mV     13.62mA    3.049mA    27.62mA
1.76V     15.28mA    3.9mA      29.08mA
2.2V      17.28mA    3.9mA      34.92mA
2.4V      17.28mA    3.9mA      35.14mA
[Pullup]
|Voltage   I(typ)   I(min)   I(max)
-1.2V     41.06mA    13.67mA    65.73mA
-760mV    41.06mA    13.67mA    62.23mA
-480mV    28.34mA    13.19mA    41.1mA
-40mV     1.753mA    764.9uA    2.773mA
200mV     -6.867mA   -2.447mA   -11.51mA
400mV     -10.47mA   -3.022mA   -18.71mA
1.84V     -12.58mA   -3.4mA     -24.17mA
1.92V     -12.61mA   -4mA       -24.24mA
1.96V     -12.63mA   -10mA      -24.27mA
2.16V     -12.7mA    -10mA      -24.4mA
2.2V      -20mA      -10mA      -24.4mA
2.36V     -20mA      -10mA      -24.4mA
[GND_clamp]
|Voltage   I(typ)   I(min)   I(max)
-1.2V     -3.45A     -8.037A    -9.248A
-960mV    -3.45A     -8.037A    -9.248A
-930mV    -3.45A     -3.504A    -9.248A
-900mV    -3.45A     -1.544A    -9.248A
-870mV    -3.45A     -693.1mA   -9.248A
-840mV    -1.093A    -319.7mA   -9.248A
-810mV    -355mA     -153mA     -2.104A
-780mV    -122.1mA   -76.47mA   -492.8mA
-750mV    -46.85mA   -40.02mA   -125.6mA
-720mV    -21.41mA   -22.04mA   -38.94mA
-630mV    -6.028mA   -5.668mA   -6.589mA
1.2V      0A         44.19nA    0A
[POWER_clamp]
|Voltage   I(typ)   I(min)   I(max)
-1.2V     139.7mA    145.3mA    140.7mA
-1.1V     89.79mA    106.4mA    80.86mA
-1.02V    52.48mA    76.58mA    37.41mA
-980mV    35.57mA    62.3mA     19.38mA
-960mV    27.85mA    55.39mA    12.18mA
-920mV    14.63mA    42.15mA    3.226mA
-880mV    5.71mA     29.97mA    537.4uA
-820mV    777uA      14.76mA    28.17uA
-780mV    170.8uA    7.604mA    3.856uA
-720mV    16.71uA    2.018mA    195.3nA
-600mV    157.7nA    78.69uA    0A
0V        0A         56.62nA    0A
[Ramp]
| variable   typ   min   max
dV/dt_r  0.34636/3.90455n   95.21962m/9.49972n  0.55615/2.13876n
dV/dt_f  0.40279/4.42760n   91.96800m/11.14400n 0.61499/2.00778n
R_load = 50.000000
[Rising Waveform]
R_fixture= 50.000000
V_fixture= 1.200000
V_fixture_min= 0.900000
V_fixture_max= 1.320000
|time   V(typ)   V(min)   V(max)
0s        528.7mV    746.7mV    295mV
1.401ns   529mV      746.7mV    308mV
1.602ns   529mV      746.7mV    416.8mV
2.002ns   526.1mV    746.7mV    1.174V
2.202ns   524.8mV    746.7mV    1.272V
2.603ns   654.1mV    746.7mV    1.308V
3.203ns   1.105V     746.7mV    1.312V
4.204ns   1.194V     746.8mV    1.317V
10.81ns   1.2V       897.6mV    1.32V
99.7ns    1.2V       900mV      1.32V
[Rising Waveform]
R_fixture= 50.000000
V_fixture= 0.0
V_fixture_min= 0.0
V_fixture_max= 0.0
|time   V(typ)   V(min)   V(max)
0s        2.345nV    636.1nV    922.7pV
10.01ns   462.7mV    -2.394mV   921.8mV
20.02ns   575.5mV    59.79mV    926.9mV
30.03ns   577.1mV    139.4mV    926.9mV
40.04ns   577.2mV    155.7mV    926.9mV
50.05ns   577.2mV    158.3mV    926.9mV
991ns     577.3mV    158.7mV    926.9mV
[Falling Waveform]
R_fixture= 50.000000
V_fixture= 1.200000
V_fixture_min= 0.900000
V_fixture_max= 1.320000
|time   V(typ)   V(min)   V(max)
0s        1.2V       900mV      1.32V
2.002ns   1.205V     900mV      1.327V
4.004ns   1.204V     902.5mV    978.9mV
6.006ns   1.15V      901.2mV    416.7mV
8.008ns   933.6mV    901.1mV    333.1mV
10.01ns   730.8mV    901.1mV    310mV
14.01ns   588.1mV    899.8mV    297.7mV
30.03ns   529.4mV    777.1mV    295mV
56.06ns   528.7mV    747.6mV    295mV
997ns     528.7mV    746.7mV    295mV
[Falling Waveform]
R_fixture= 50.000000
V_fixture= 0.0
V_fixture_min= 0.0
V_fixture_max= 0.0
|time   V(typ)   V(min)   V(max)
0s        577.3mV    158.7mV    926.9mV
800.8ps   577.3mV    158.7mV    928.7mV
1.361ns   581.7mV    158.7mV    431.3mV
1.762ns   383.5mV    158.7mV    183.4mV
2.162ns   223.3mV    158.7mV    54.85mV
2.803ns   87.44mV    159mV      9.939mV
3.844ns   9.346mV    133.3mV    2.375mV
5.526ns   2.519mV    47.39mV    830.4uV
8.809ns   742.8uV    4.765mV    185.4uV
39.88ns   2.345nV    636.1nV    922.7pV
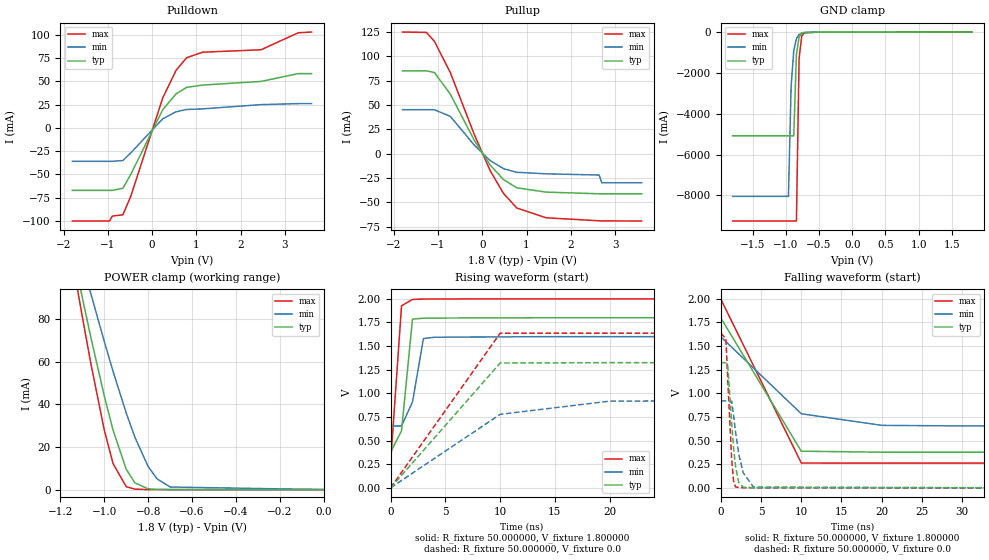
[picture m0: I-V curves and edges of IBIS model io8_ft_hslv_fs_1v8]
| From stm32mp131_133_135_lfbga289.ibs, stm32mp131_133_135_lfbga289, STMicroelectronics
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|   Model io8_ft_hslv_fs_1v8
[Model]  io8_ft_hslv_fs_1v8
Model_type I/O
Polarity   Non-Inverting
Enable   Active-Low
Vinl =   0.540000V
Vinh =   1.260000V
Vmeas =  0.900000V
Cref =   50.000000pF
Rref =   100.000000M
Vref =   0.0V
C_comp   3.156400pF   3.140600pF   3.186200pF
[Temperature Range]   25.000000   0.140000k   -40.000000
[Pullup Reference]   1.800000V   1.600000V   2.000000V
[Pulldown Reference]   0.0V   0.0V   0.0V
[POWER Clamp Reference]   1.800000V   1.600000V   2.000000V
[GND Clamp Reference]   0.0V   0.0V   0.0V
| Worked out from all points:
|   slope of the pulldown table from 0 to 0.27 V, typ, clamps not added: 12.5 ohm
|   slope of the pullup table from 0 to 0.27 V, typ, clamps not added: 16 ohm
|   GND clamp passes 1 mA (typ) near -0.47 V on its own axis
|   POWER clamp passes 1 mA (typ) near -0.83 V on its own axis
|   rising waveform, R_fixture 50.000000, V_fixture 1.800000: 20-80 % time 724ps typ, 1ns min, 627ps max; typ from 0.377 V to 1.8 V
|   rising waveform, R_fixture 50.000000, V_fixture 0.0: 20-80 % time 6.02ns typ, 7.11ns min, 6.01ns max; typ from 0 V to 1.32 V
|   falling waveform, R_fixture 50.000000, V_fixture 1.800000: 20-80 % time 6.05ns typ, 6.96ns min, 6.01ns max; typ from 1.8 V to 0.377 V
|   falling waveform, R_fixture 50.000000, V_fixture 0.0: 20-80 % time 726ps typ, 1.06ns min, 543ps max; typ from 1.32 V to 0 V
[Pulldown]
|Voltage   I(typ)   I(min)   I(max)
-1.8V     -67.09mA   -35.91mA   -100mA
-960mV    -67.09mA   -35.91mA   -100mA
-900mV    -67.09mA   -35.91mA   -94.73mA
-660mV    -64.86mA   -35.04mA   -93.29mA
-480mV    -49.73mA   -26.69mA   -73.15mA
240mV     19.58mA    9.767mA    32.18mA
540mV     36.57mA    17.36mA    61.85mA
780mV     43.58mA    19.81mA    75.41mA
1.14V     46.02mA    20.44mA    81.32mA
2.46V     49.96mA    25.03mA    83.95mA
3.3V      58.34mA    26.11mA    102.2mA
3.6V      58.34mA    26.11mA    103mA
[Pullup]
|Voltage   I(typ)   I(min)   I(max)
-1.8V     85.19mA    45.19mA    125.1mA
-1.26V    85.19mA    45.19mA    124.7mA
-1.08V    83.47mA    45.19mA    115.5mA
-720mV    61.13mA    38.31mA    83.3mA
-180mV    13.76mA    8.769mA    19.71mA
180mV     -11.78mA   -7.161mA   -17.58mA
480mV     -26.67mA   -15.47mA   -40.89mA
780mV     -35.14mA   -19.2mA    -55.89mA
1.44V     -39.57mA   -20.76mA   -65.96mA
2.64V     -41.3mA    -22mA      -69.09mA
2.7V      -41.3mA    -30mA      -69.18mA
3.6V      -41.3mA    -30mA      -69.3mA
[GND_clamp]
|Voltage   I(typ)   I(min)   I(max)
-1.8V     -5.08A     -8.044A    -9.251A
-960mV    -5.08A     -8.044A    -9.251A
-920mV    -5.08A     -2.669A    -9.251A
-880mV    -5.08A     -908mA     -9.251A
-840mV    -1.096A    -323.6mA   -9.251A
-800mV    -248.9mA   -123.7mA   -1.293A
-760mV    -64.81mA   -51.32mA   -196.6mA
-720mV    -22.13mA   -23.23mA   -39.69mA
-480mV    -1.149mA   -1.898mA   -936.1uA
1.8V      0A         44.33nA    0A
[POWER_clamp]
|Voltage   I(typ)   I(min)   I(max)
-1.8V     460.5mA    392.1mA    526.9mA
-1.12V    99.56mA    114.1mA    92.51mA
-1.1V     89.79mA    106.4mA    80.86mA
-1.06V    70.71mA    91.32mA    58.34mA
-1V       43.82mA    69.37mA    27.91mA
-960mV    27.85mA    55.39mA    12.18mA
-900mV    9.544mA    35.9mA     1.368mA
-860mV    3.133mA    24.42mA    203.6uA
-800mV    367uA      10.84mA    10.43uA
-760mV    78.93uA    5.095mA    1.426uA
-700mV    7.679uA    1.212mA    72.45nA
0V        0A         59.16nA    0A
[Ramp]
| variable   typ   min   max
dV/dt_r  0.79476/1.79277n   0.55240/4.11112n   0.98226/1.08997n
dV/dt_f  0.85364/1.78222n   0.56723/3.80370n   1.04297/1.28766n
R_load = 50.000000
[Rising Waveform]
R_fixture= 50.000000
V_fixture= 1.800000
V_fixture_min= 1.600000
V_fixture_max= 2.000000
|time   V(typ)   V(min)   V(max)
0s        377.3mV    654.6mV    261.7mV
1.001ns   604.5mV    654.6mV    1.927V
2.002ns   1.786V     908.3mV    1.994V
3.003ns   1.795V     1.58V      1.998V
4.004ns   1.797V     1.594V     1.999V
14.01ns   1.8V       1.6V       2V
99.1ns    1.8V       1.6V       2V
[Rising Waveform]
R_fixture= 50.000000
V_fixture= 0.0
V_fixture_min= 0.0
V_fixture_max= 0.0
|time   V(typ)   V(min)   V(max)
0s        2.004nV    378.7nV    939.1pV
10.01ns   1.321V     778mV      1.637V
20.02ns   1.325V     917.8mV    1.637V
30.03ns   1.325V     920.5mV    1.637V
991ns     1.325V     920.7mV    1.637V
[Falling Waveform]
R_fixture= 50.000000
V_fixture= 1.800000
V_fixture_min= 1.600000
V_fixture_max= 2.000000
|time   V(typ)   V(min)   V(max)
0s        1.8V       1.6V       2V
10.01ns   387.7mV    783.9mV    262.5mV
20.02ns   377.4mV    661.4mV    261.7mV
30.03ns   377.3mV    655mV      261.7mV
991ns     377.3mV    654.6mV    261.7mV
[Falling Waveform]
R_fixture= 50.000000
V_fixture= 0.0
V_fixture_min= 0.0
V_fixture_max= 0.0
|time   V(typ)   V(min)   V(max)
0s        1.325V     920.7mV    1.637V
640.6ps   1.324V     920.7mV    1.579V
880.9ps   1.289V     920.7mV    1.137V
1.361ns   693.8mV    916.5mV    306.3mV
1.602ns   420.6mV    766.2mV    70.58mV
1.842ns   228.8mV    595mV      9.977mV
2.242ns   53.67mV    357.9mV    3.434mV
2.803ns   6.523mV    157.4mV    1.828mV
4.084ns   1.781mV    8.054mV    847.9uV
39.88ns   2.004nV    378.7nV    939.1pV
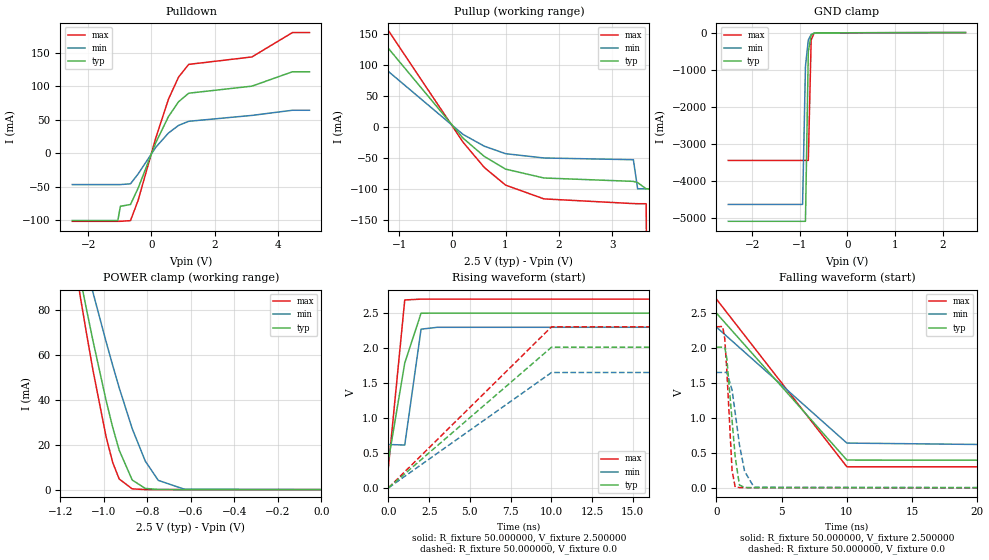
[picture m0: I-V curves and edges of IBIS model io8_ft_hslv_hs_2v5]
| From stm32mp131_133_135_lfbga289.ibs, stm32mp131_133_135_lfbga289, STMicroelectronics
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|   Model io8_ft_hslv_hs_2v5
[Model]  io8_ft_hslv_hs_2v5
Model_type I/O
Polarity   Non-Inverting
Enable   Active-Low
Vinl =   0.750000V
Vinh =   1.750000V
Vmeas =  1.250000V
Cref =   50.000000pF
Rref =   100.000000M
Vref =   0.0V
C_comp   3.247300pF   3.246200pF   3.289300pF
[Temperature Range]   25.000000   0.140000k   -40.000000
[Pullup Reference]   2.500000V   2.300000V   2.700000V
[Pulldown Reference]   0.0V   0.0V   0.0V
[POWER Clamp Reference]   2.500000V   2.300000V   2.700000V
[GND Clamp Reference]   0.0V   0.0V   0.0V
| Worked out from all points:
|   slope of the pulldown table from 0 to 0.375 V, typ, clamps not added: 9.35 ohm
|   slope of the pullup table from 0 to 0.375 V, typ, clamps not added: 11.7 ohm
|   GND clamp passes 1 mA (typ) near -0.47 V on its own axis
|   POWER clamp passes 1 mA (typ) near -0.82 V on its own axis
|   rising waveform, R_fixture 50.000000, V_fixture 2.500000: 20-80 % time 1.11ns typ, 609ps min, 604ps max; typ from 0.396 V to 2.5 V
|   rising waveform, R_fixture 50.000000, V_fixture 0.0: 20-80 % time 6.01ns typ, 6.01ns min, 6.01ns max; typ from 0 V to 2.01 V
|   falling waveform, R_fixture 50.000000, V_fixture 2.500000: 20-80 % time 6.01ns typ, 6.08ns min, 6.01ns max; typ from 2.5 V to 0.396 V
|   falling waveform, R_fixture 50.000000, V_fixture 0.0: 20-80 % time 547ps typ, 788ps min, 386ps max; typ from 2.01 V to 0 V
[Pulldown]
|Voltage   I(typ)   I(min)   I(max)
-2.5V     -100mA     -46.5mA    -101.2mA
-1.06V    -100mA     -46.5mA    -101.2mA
-980mV    -78.83mA   -46.5mA    -101.2mA
-660mV    -76.17mA   -45.35mA   -100.2mA
-420mV    -51.93mA   -30.73mA   -70.08mA
140mV     15.93mA    9.072mA    22.96mA
540mV     54.77mA    30.25mA    80.67mA
860mV     76.84mA    41.64mA    113.6mA
1.18V     89.58mA    47.74mA    132.5mA
3.18V     100.1mA    56.52mA    143.6mA
4.46V     121.5mA    64.18mA    179.9mA
5V        121.5mA    64.18mA    179.9mA
[Pullup]
|Voltage   I(typ)   I(min)   I(max)
-2.5V     230.5mA    157.1mA    272.9mA
-1.72V    176.7mA    122mA      213.1mA
-1.32V    139.3mA    98.34mA    171.2mA
200mV     -18.01mA   -12.03mA   -24.57mA
600mV     -47.71mA   -31.12mA   -65.47mA
1V        -68.18mA   -43.25mA   -94.07mA
1.72V     -82.53mA   -50.18mA   -116.3mA
3.4V      -88mA      -53mA      -123.9mA
3.48V     -90mA      -100mA     -124.1mA
3.64V     -100mA     -100mA     -124.1mA
3.72V     -100mA     -100mA     -1A
4.92V     -100mA     -100mA     -1A
[GND_clamp]
|Voltage   I(typ)   I(min)   I(max)
-2.5V     -5.082A    -4.628A    -3.442A
-940mV    -5.082A    -4.628A    -3.442A
-880mV    -5.082A    -910.9mA   -3.442A
-820mV    -518.2mA   -200mA     -3.442A
-760mV    -65.41mA   -52.42mA   -196.1mA
-700mV    -14.98mA   -16.7mA    -21.53mA
-640mV    -6.913mA   -6.897mA   -7.503mA
2.48V     0A         43.12nA    0A
[POWER_clamp]
|Voltage   I(typ)   I(min)   I(max)
-2.49V    840.6mA    685.1mA    983.2mA
-1.11V    94.66mA    110.3mA    86.66mA
-1.08V    80.16mA    98.83mA    69.45mA
-1.05V    66.06mA    87.6mA     52.92mA
-990mV    39.64mA    65.82mA    23.5mA
-960mV    27.85mA    55.39mA    12.18mA
-930mV    17.59mA    45.37mA    4.744mA
-870mV    4.273mA    27.14mA    331.7uA
-810mV    535.4uA    12.72mA    17.14uA
-750mV    53.58uA    4.101mA    867.4nA
-630mV    505.2nA    181.4uA    0A
0V        0A         61.21nA    0A
[Ramp]
| variable   typ   min   max
dV/dt_r  1.20750/0.62207n   0.99036/0.77007n   1.38252/0.69160n
dV/dt_f  1.26241/1.29366n   1.00776/1.95786n   1.43924/0.67237n
R_load = 50.000000
[Rising Waveform]
R_fixture= 50.000000
V_fixture= 2.500000
V_fixture_min= 2.300000
V_fixture_max= 2.700000
|time   V(typ)   V(min)   V(max)
0s        396mV      620.4mV    301.3mV
1.001ns   1.786V     612.4mV    2.688V
2.002ns   2.498V     2.27V      2.7V
3.003ns   2.5V       2.297V     2.7V
99.1ns    2.5V       2.3V       2.7V
[Rising Waveform]
R_fixture= 50.000000
V_fixture= 0.0
V_fixture_min= 0.0
V_fixture_max= 0.0
|time   V(typ)   V(min)   V(max)
0s        2.072nV    301.7nV    1.128nV
10.01ns   2.012V     1.65V      2.304V
20.02ns   2.012V     1.651V     2.304V
991ns     2.013V     1.651V     2.304V
[Falling Waveform]
R_fixture= 50.000000
V_fixture= 2.500000
V_fixture_min= 2.300000
V_fixture_max= 2.700000
|time   V(typ)   V(min)   V(max)
0s        2.5V       2.3V       2.7V
10.01ns   397.7mV    640.7mV    301.4mV
20.02ns   396mV      620.9mV    301.3mV
30.03ns   396mV      620.4mV    301.3mV
991ns     396mV      620.4mV    301.3mV
[Falling Waveform]
R_fixture= 50.000000
V_fixture= 0.0
V_fixture_min= 0.0
V_fixture_max= 0.0
|time   V(typ)   V(min)   V(max)
0s        2.013V     1.651V     2.304V
480.5ps   2.012V     1.651V     2.309V
640.6ps   2.01V      1.651V     2.132V
800.8ps   1.848V     1.652V     1.67V
1.201ns   960.2mV    1.398V     246mV
1.441ns   443.4mV    1.073V     10.6mV
1.762ns   40.81mV    619.7mV    3.978mV
2.162ns   5.368mV    235.6mV    2.481mV
2.883ns   2.445mV    9.297mV    1.445mV
39.88ns   2.072nV    301.7nV    1.128nV
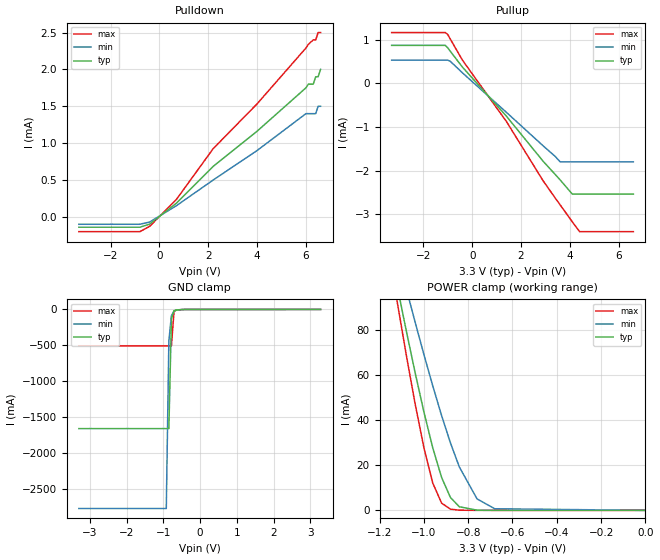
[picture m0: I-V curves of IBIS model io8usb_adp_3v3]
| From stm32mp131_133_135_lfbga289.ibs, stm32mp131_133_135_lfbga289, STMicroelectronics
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|   Model io8usb_adp_3v3
[Model]  io8usb_adp_3v3
Model_type I/O
Polarity   Non-Inverting
Enable   Active-High
Vinl =   0.990000V
Vinh =   2.310000V
Vmeas =  1.650000V
Cref =   50.000000pF
Rref =   100.000000M
Vref =   0.0V
C_comp   3.902700pF   3.901500pF   3.914800pF
[Temperature Range]   25.000000   0.140000k   -40.000000
[Pullup Reference]   3.300000V   2.700000V   3.600000V
[Pulldown Reference]   0.0V   0.0V   0.0V
[POWER Clamp Reference]   3.300000V   2.700000V   3.600000V
[GND Clamp Reference]   0.0V   0.0V   0.0V
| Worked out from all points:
|   slope of the pulldown table from 0 to 0.495 V, typ, clamps not added: 3.87 kohm
|   slope of the pullup table from 0 to 0.495 V, typ, clamps not added: 1.62 kohm
|   GND clamp passes 1 mA (typ) near -0.46 V on its own axis
|   POWER clamp passes 1 mA (typ) near -0.82 V on its own axis
[Pulldown]
|Voltage   I(typ)   I(min)   I(max)
-3.3V     -140uA     -100uA     -200uA
-800mV    -140uA     -100uA     -200uA
-400mV    -97.61uA   -69.55uA   -127.9uA
700mV     187.4uA    152.8uA    238.6uA
2.2V      684.5uA    499.8uA    924.8uA
4V        1.162mA    900uA      1.533mA
6V        1.75mA     1.4mA      2.29mA
6.1V      1.8mA      1.4mA      2.34mA
6.3V      1.8mA      1.4mA      2.4mA
6.4V      1.9mA      1.4mA      2.4mA
6.5V      1.9mA      1.5mA      2.5mA
6.6V      2mA        1.5mA      2.5mA
[Pullup]
|Voltage   I(typ)   I(min)   I(max)
-3.3V     869uA      530uA      1.163mA
-1.1V     869uA      530uA      1.163mA
-1V       811uA      530uA      1.115mA
-900mV    735.2uA    505uA      1.015mA
-400mV    370.4uA    239.5uA    529.8uA
1.4V      -753.1uA   -665.4uA   -875.1uA
2.9V      -1.784mA   -1.431mA   -2.231mA
3.4V      -2.09mA    -1.676mA   -2.63mA
3.6V      -2.213mA   -1.8mA     -2.785mA
4.1V      -2.54mA    -1.8mA     -3.175mA
4.4V      -2.54mA    -1.8mA     -3.4mA
6.6V      -2.54mA    -1.8mA     -3.4mA
[GND_clamp]
|Voltage   I(typ)   I(min)   I(max)
-3.3V     -1.662A    -2.777A    -508.4mA
-920mV    -1.662A    -2.777A    -508.4mA
-850mV    -1.662A    -441.8mA   -508.4mA
-780mV    -129mA     -87.56mA   -508.4mA
-710mV    -18.66mA   -22.27mA   -28.79mA
-640mV    -7.04mA    -7.478mA   -7.491mA
-430mV    -483.3uA   -1.241mA   -292.5uA
3.28V     0A         49.83nA    0A
[POWER_clamp]
|Voltage   I(typ)   I(min)   I(max)
-3.28V    1.28A      1.024A     1.509A
-1.12V    99.56mA    114.1mA    92.51mA
-1.08V    80.16mA    98.83mA    69.45mA
-1.04V    61.47mA    83.9mA     47.62mA
-1V       43.82mA    69.37mA    27.91mA
-960mV    27.85mA    55.39mA    12.18mA
-920mV    14.63mA    42.15mA    3.226mA
-880mV    5.71mA     29.97mA    537.4uA
-840mV    1.599mA    19.32mA    75.95uA
-760mV    78.93uA    5.095mA    1.427uA
-680mV    3.529uA    713.7uA    37.26nA
0V        0A         68.58nA    0A
[Ramp]
| variable   typ   min   max
dV/dt_r  59.05559m/1.33105n  39.05551m/2.09095n  80.42396m/1.12770n
dV/dt_f  25.26000m/1.13433n  16.80000m/1.99722n  34.98000m/1.06193n
R_load = 50.000000
|End [Model] io8usb_adp_3v3
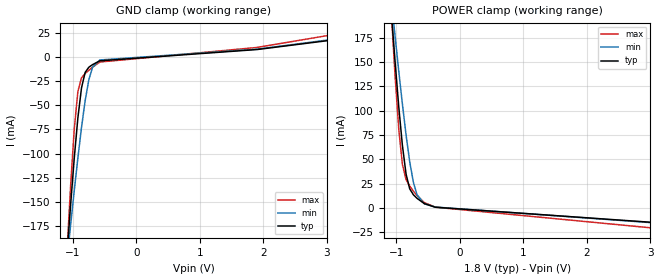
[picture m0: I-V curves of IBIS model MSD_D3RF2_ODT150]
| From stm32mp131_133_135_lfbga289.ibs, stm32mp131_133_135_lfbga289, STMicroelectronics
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[Model] MSD_D3RF2_ODT150
Model_type   Input
C_comp 2.184pF   2.120pF   2.245pF
Vinh = 1.150V
Vinl = 650.000mV
[Temperature Range]   25.000   125.000   -40.000
[Voltage Range]   1.800V   1.700V   1.900V
[GND Clamp Reference]   0.00V   0.00V   0.00V
[POWER Clamp Reference]   1.800V   1.700V   1.900V
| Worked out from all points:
|   GND clamp passes 1 mA (typ) near -0.44 V on its own axis
|   POWER clamp passes 1 mA (typ) near -0.42 V on its own axis
[GND Clamp]
-1.785V   -886mA     -673.5mA   -1.188A
-1.094V   -205.6mA   -211.1mA   -203.8mA
-1.036V   -153.7mA   -174.5mA   -134.3mA
-978.8mV  -105.4mA   -138.9mA   -75.53mA
-921.2mV  -63.28mA   -104.7mA   -35.78mA
-863.6mV  -31.98mA   -72.96mA   -21.63mA
-806.1mV  -16.04mA   -45.17mA   -17.21mA
-748.5mV  -10.72mA   -23.73mA   -13.87mA
-690.9mV  -8.073mA   -10.94mA   -10.78mA
-575.8mV  -4.082mA   -3.213mA   -5.354mA
1.9V      7.59mA     7.98mA     9.75mA
3.57V     21.4mA     22.17mA    28.24mA
[Power Clamp]
-1.77V    862mA      669.2mA    1.131A
-1.079V   199.9mA    212.7mA    199.2mA
-1.021V   150.1mA    176.3mA    135.7mA
-963.6mV  104.2mA    140.8mA    81.44mA
-906.1mV  64.44mA    106.8mA    44.73mA
-848.5mV  34.81mA    75.15mA    29.16mA
-790.9mV  19.59mA    47.54mA    22.5mA
-733.3mV  13.54mA    26.36mA    17.28mA
-675.8mV  9.828mA    13.43mA    12.69mA
-560.6mV  4.37mA     4.255mA    5.461mA
-387.9mV  658.6uA    871.8uA    714.1uA
3.585V    -17.41mA   -17.91mA   -24.11mA
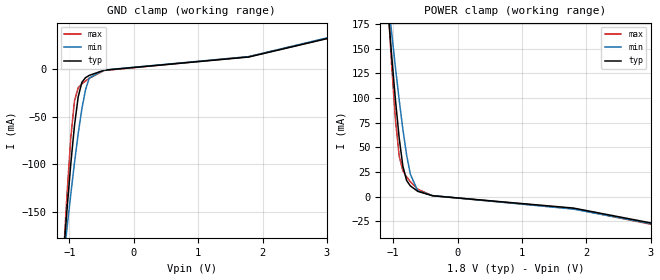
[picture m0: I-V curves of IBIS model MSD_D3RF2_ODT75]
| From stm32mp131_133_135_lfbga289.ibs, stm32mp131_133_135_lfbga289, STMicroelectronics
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[Model] MSD_D3RF2_ODT75
Model_type   Input
C_comp 2.159pF   2.096pF   2.219pF
Vinh = 1.150V
Vinl = 650.000mV
[Temperature Range]   25.000   125.000   -40.000
[Voltage Range]   1.800V   1.700V   1.900V
[GND Clamp Reference]   0.00V   0.00V   0.00V
[POWER Clamp Reference]   1.800V   1.700V   1.900V
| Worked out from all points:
|   GND clamp passes 1 mA (typ) near -0.47 V on its own axis
|   POWER clamp passes 1 mA (typ) near -0.41 V on its own axis
[GND Clamp]
-1.785V   -871.6mA   -659.5mA   -1.177A
-1.094V   -197.4mA   -202.5mA   -198.6mA
-1.036V   -146.7mA   -166.5mA   -130.3mA
-978.8mV  -99.68mA   -131.6mA   -72.47mA
-921.2mV  -59.18mA   -98.39mA   -33.21mA
-863.6mV  -28.96mA   -67.74mA   -19.37mA
-806.1mV  -13.58mA   -41.25mA   -15.21mA
-748.5mV  -8.619mA   -21.05mA   -12.13mA
-690.9mV  -6.301mA   -9.112mA   -9.288mA
-460.6mV  -827.3uA   -671.7uA   -1.158mA
1.785V    13.02mA    13.44mA    13.36mA
3.57V     41.43mA    42.41mA    41.61mA
[Power Clamp]
-1.77V    842.9mA    650.5mA    1.117A
-1.079V   189.4mA    200.6mA    193.7mA
-1.021V   141.4mA    165.1mA    131mA
-963.6mV  97.56mA    130.6mA    77.34mA
-906.1mV  59.35mA    97.94mA    41.2mA
-848.5mV  30.74mA    67.95mA    26.18mA
-790.9mV  16.29mA    42.22mA    19.99mA
-733.3mV  10.89mA    22.79mA    15.22mA
-618.2mV  5.338mA    5.765mA    7.499mA
-387.9mV  848.6uA    1.035mA    831.1uA
1.8V      -11.65mA   -12.68mA   -12.23mA
3.585V    -34.02mA   -34.69mA   -35.71mA
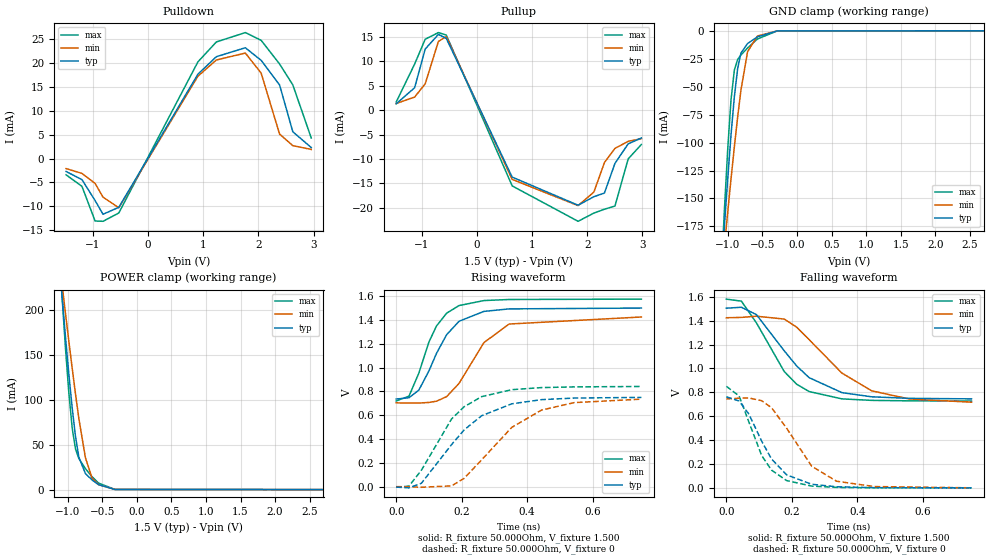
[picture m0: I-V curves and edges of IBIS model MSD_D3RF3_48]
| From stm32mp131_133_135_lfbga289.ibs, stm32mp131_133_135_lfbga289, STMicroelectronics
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[Model] MSD_D3RF3_48
Model_type   I/O
C_comp 2.240pF   2.160pF   2.357pF
Vinh = 925.000mV
Vinl = 575.000mV
Vmeas = 750.000mV
Vref = 750.000mV
[Model Spec]
Vinh   925.000mV   888.000mV   963.000mV
Vinl   575.000mV   538.000mV   613.000mV
Vmeas   750.000mV   713.000mV   788.000mV
Vref   750.000mV   713.000mV   788.000mV
[Temperature Range]   25.000   125.000   -40.000
[Voltage Range]   1.500V   1.425V   1.575V
[GND Clamp Reference]   0.00V   0.00V   0.00V
[Pulldown Reference]   0.00V   0.00V   0.00V
[POWER Clamp Reference]   1.500V   1.425V   1.575V
[Pullup Reference]   1.500V   1.425V   1.575V
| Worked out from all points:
|   slope of the pulldown table from 0 to 0.225 V, typ, clamps not added: 44.1 ohm
|   slope of the pullup table from 0 to 0.225 V, typ, clamps not added: 37.5 ohm
|   GND clamp passes 1 mA (typ) near -0.40 V on its own axis
|   POWER clamp passes 1 mA (typ) near -0.41 V on its own axis
|   rising waveform, R_fixture 50.000Ohm, V_fixture 1.500: 20-80 % time 88.8ps typ, 105ps min, 74.8ps max; typ from 0.736 V to 1.5 V
|   rising waveform, R_fixture 50.000Ohm, V_fixture 0: 20-80 % time 147ps typ, 164ps min, 126ps max; typ from -0.003 V to 0.75 V
|   falling waveform, R_fixture 50.000Ohm, V_fixture 1.500: 20-80 % time 143ps typ, 168ps min, 116ps max; typ from 1.5 V to 0.745 V
|   falling waveform, R_fixture 50.000Ohm, V_fixture 0: 20-80 % time 94.9ps typ, 112ps min, 78.4ps max; typ from 0.762 V to 0 V
[GND Clamp]
-1.48V    -593.9mA   -479.7mA   -763.1mA
-1.098V   -218.2mA   -223.3mA   -220.2mA
-1.05V    -174.1mA   -192.4mA   -159.6mA
-1.002V   -131.9mA   -161.9mA   -105.2mA
-954.6mV  -92.83mA   -132.3mA   -61.52mA
-906.8mV  -59.01mA   -103.9mA   -35.13mA
-859.1mV  -33.79mA   -77.16mA   -25.62mA
-811.4mV  -19.9mA    -53.07mA   -21.61mA
-715.9mV  -11.4mA    -18.73mA   -15.39mA
-572.7mV  -5.41mA    -4.631mA   -7.313mA
-286.4mV  -67.53uA   -115uA     -52.79uA
2.959V    27.81nA    447.4nA    3.163nA
[Power Clamp]
-1.459V   577.6mA    479.2mA    722.9mA
-1.077V   211mA      225.5mA    210.2mA
-1.03V    168.2mA    194.7mA    155.6mA
-981.8mV  127.5mA    164.3mA    106.7mA
-934.1mV  90.48mA    134.7mA    68.25mA
-886.4mV  59mA       106.2mA    45.16mA
-838.6mV  36.16mA    79.4mA     34.6mA
-743.2mV  17.85mA    35.54mA    23.3mA
-647.7mV  10.74mA    12.83mA    14.33mA
-552.3mV  5.472mA    5.424mA    7.214mA
-313.6mV  99.23uA    231.1uA    112.6uA
2.98V     -43.92nA   -827nA     -4.179nA
[Pulldown]
-1.48V    -2.7mA     -2.1mA     -3.4mA
-1.193V   -4.4mA     -3.1mA     -5.8mA
-954.6mV  -8.77mA    -5.2mA     -13.05mA
-811.4mV  -11.64mA   -8.06mA    -13.11mA
-525mV    -10.19mA   -10.28mA   -11.37mA
906.8mV   17.62mA    17.2mA     20.19mA
1.241V    21.28mA    20.59mA    24.36mA
1.766V    23.15mA    22.04mA    26.32mA
2.052V    20.52mA    17.85mA    24.7mA
2.386V    15.37mA    5.1mA      19.75mA
2.625V    5.6mA      2.7mA      15.4mA
2.959V    2.3mA      1.9mA      4.3mA
[Pullup]
-1.459V   1.3mA      1.357mA    1.671mA
-1.125V   4.6mA      2.686mA    9.443mA
-934.1mV  12.52mA    5.386mA    14.53mA
-695.5mV  15.51mA    14.06mA    15.89mA
-552.3mV  14.7mA     15.08mA    15.38mA
640.9mV   -13.71mA   -14.18mA   -15.51mA
1.834V    -19.47mA   -19.55mA   -22.76mA
2.12V     -17.72mA   -16.78mA   -21.08mA
2.311V    -16.98mA   -10.74mA   -20.29mA
2.502V    -10.9mA    -7.829mA   -19.63mA
2.741V    -6.9mA     -6.386mA   -9.986mA
2.98V     -5.7mA     -5.843mA   -7.029mA
[Ramp]
R_load=50.000Ohm
dV/dt_r   452.340mV/118.000ps  436.349mV/136.000ps  507.300mV/101.000ps
dV/dt_f   452.340mV/119.000ps  436.319mV/142.500ps  507.300mV/97.500ps
[Rising waveform]
R_fixture=50.000Ohm
V_fixture=1.500
V_fixture_min=1.425
V_fixture_max=1.575
0s        736mV      704.2mV    720mV
39ps      747.1mV    702.1mV    760.3mV
69ps      810.5mV    702.3mV    952.7mV
100ps     972.5mV    707.5mV    1.215V
123ps     1.119V     717.9mV    1.349V
154ps     1.276V     756.3mV    1.457V
192ps     1.389V     867.7mV    1.521V
268ps     1.472V     1.21V      1.563V
345ps     1.493V     1.366V     1.572V
749ps     1.5V       1.425V     1.575V
[Rising waveform]
R_fixture=50.000Ohm
V_fixture=0
0s        -3.363mV   687.5uV    -4.135mV
39ps      -9.696mV   -900.1uV   4.885mV
77ps      28.92mV    -4.775mV   138.7mV
169ps     352.9mV    6.854mV    568.2mV
207ps     475.4mV    68.99mV    670.6mV
261ps     596mV      225.6mV    756.3mV
353ps     695.9mV    498.1mV    814.7mV
444ps     731mV      643.5mV    832.2mV
544ps     744.4mV    706.1mV    838.2mV
749ps     749.9mV    735.2mV    841.5mV
[Falling waveform]
R_fixture=50.000Ohm
V_fixture=1.500
V_fixture_min=1.425
V_fixture_max=1.575
0s        1.504V     1.424V     1.58V
46ps      1.512V     1.427V     1.563V
92ps      1.45V      1.437V     1.381V
177ps     1.147V     1.413V     973.5mV
215ps     1.02V      1.345V     867.5mV
253ps     922.5mV    1.241V     806.3mV
353ps     797.4mV    961mV      745mV
444ps     762.3mV    812.5mV    732.4mV
559ps     749.3mV    743.9mV    728.5mV
749ps     745.1mV    717.3mV    726.7mV
[Falling waveform]
R_fixture=50.000Ohm
V_fixture=0
0s        762.4mV    744.6mV    850.2mV
39ps      727.3mV    751mV      769.6mV
69ps      616.8mV    752.3mV    550.4mV
108ps     391mV      729.8mV    270.6mV
138ps     242mV      671.4mV    148.9mV
184ps     109.4mV    500.1mV    60.98mV
261ps     30mV       180.5mV    14.76mV
337ps     9.138mV    55.31mV    3.746mV
452ps     1.61mV     10.97mV    580.1uV
749ps     44.65uV    315.2uV    25.64uV
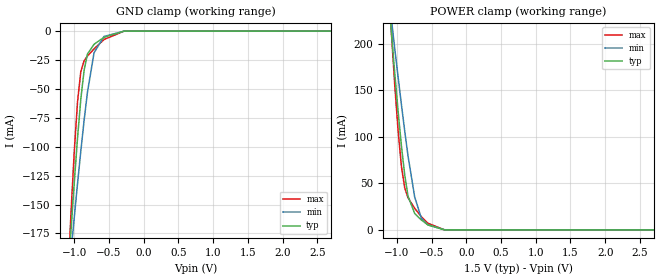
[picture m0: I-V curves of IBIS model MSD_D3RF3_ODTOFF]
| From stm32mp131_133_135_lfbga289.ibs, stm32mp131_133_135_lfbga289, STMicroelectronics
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[Model] MSD_D3RF3_ODTOFF
Model_type   Input
C_comp 2.240pF   2.160pF   2.357pF
Vinh = 925.000mV
Vinl = 575.000mV
[Temperature Range]   25.000   125.000   -40.000
[Voltage Range]   1.500V   1.425V   1.575V
[GND Clamp Reference]   0.00V   0.00V   0.00V
[POWER Clamp Reference]   1.500V   1.425V   1.575V
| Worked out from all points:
|   GND clamp passes 1 mA (typ) near -0.40 V on its own axis
|   POWER clamp passes 1 mA (typ) near -0.41 V on its own axis
[GND Clamp]
-1.48V    -593.9mA   -479.7mA   -763.1mA
-1.098V   -218.2mA   -223.3mA   -220.2mA
-1.05V    -174.1mA   -192.4mA   -159.6mA
-1.002V   -131.9mA   -161.9mA   -105.2mA
-954.6mV  -92.83mA   -132.3mA   -61.52mA
-906.8mV  -59.01mA   -103.9mA   -35.13mA
-859.1mV  -33.79mA   -77.16mA   -25.62mA
-811.4mV  -19.9mA    -53.07mA   -21.61mA
-715.9mV  -11.4mA    -18.73mA   -15.39mA
-572.7mV  -5.41mA    -4.631mA   -7.313mA
-286.4mV  -67.53uA   -115uA     -52.79uA
2.959V    27.81nA    447.4nA    3.16nA
[Power Clamp]
-1.459V   577.6mA    479.2mA    722.9mA
-1.077V   211mA      225.5mA    210.2mA
-1.03V    168.2mA    194.7mA    155.6mA
-981.8mV  127.5mA    164.3mA    106.7mA
-934.1mV  90.48mA    134.7mA    68.25mA
-886.4mV  59mA       106.2mA    45.16mA
-838.6mV  36.16mA    79.4mA     34.6mA
-743.2mV  17.85mA    35.54mA    23.3mA
-647.7mV  10.74mA    12.83mA    14.33mA
-552.3mV  5.472mA    5.424mA    7.214mA
-313.6mV  99.23uA    231.1uA    112.6uA
2.98V     -43.92nA   -827.1nA   -4.177nA
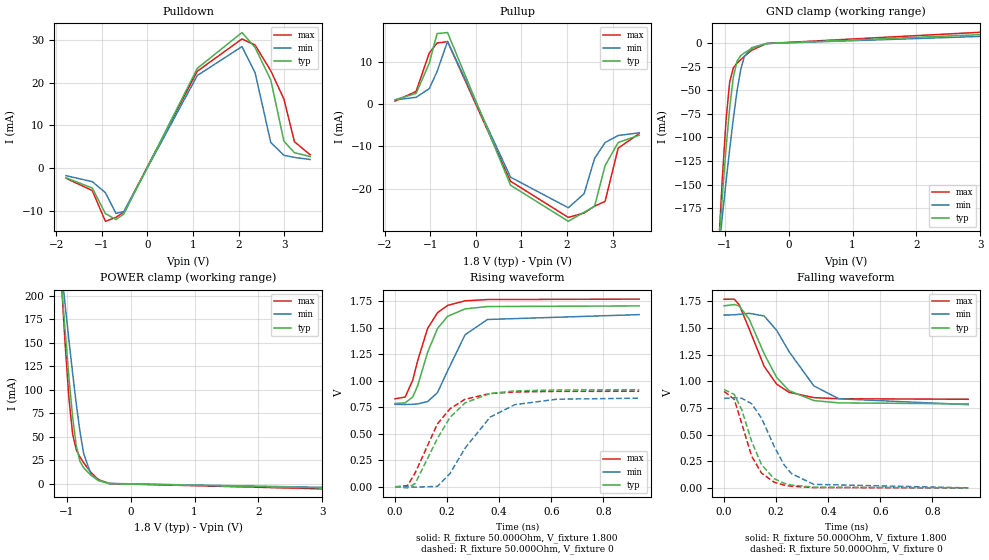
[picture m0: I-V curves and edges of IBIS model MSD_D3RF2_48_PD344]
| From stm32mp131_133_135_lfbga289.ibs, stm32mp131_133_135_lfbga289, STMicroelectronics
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[Model] MSD_D3RF2_48_PD344
Model_type   I/O
C_comp 2.313pF   2.232pF   2.432pF
Vinh = 1.150V
Vinl = 650.000mV
Vmeas = 900.000mV
Vref = 900.000mV
[Model Spec]
Vinh   1.150V   1.100V   1.200V
Vinl   650.000mV   600.000mV   700.000mV
Vmeas   900.000mV   850.000mV   950.000mV
Vref   900.000mV   850.000mV   950.000mV
[Temperature Range]   25.000   125.000   -40.000
[Voltage Range]   1.800V   1.700V   1.900V
[GND Clamp Reference]   0.00V   0.00V   0.00V
[Pulldown Reference]   0.00V   0.00V   0.00V
[POWER Clamp Reference]   1.800V   1.700V   1.900V
[Pullup Reference]   1.800V   1.700V   1.900V
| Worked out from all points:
|   slope of the pulldown table from 0 to 0.27 V, typ, clamps not added: 41 ohm
|   slope of the pullup table from 0 to 0.27 V, typ, clamps not added: 32.3 ohm
|   GND clamp passes 1 mA (typ) near -0.41 V on its own axis
|   POWER clamp passes 1 mA (typ) near -0.41 V on its own axis
|   rising waveform, R_fixture 50.000Ohm, V_fixture 1.800: 20-80 % time 81.5ps typ, 99.9ps min, 74.8ps max; typ from 0.784 V to 1.7 V
|   rising waveform, R_fixture 50.000Ohm, V_fixture 0: 20-80 % time 127ps typ, 150ps min, 119ps max; typ from -0.002 V to 0.914 V
|   falling waveform, R_fixture 50.000Ohm, V_fixture 1.800: 20-80 % time 115ps typ, 141ps min, 102ps max; typ from 1.71 V to 0.788 V
|   falling waveform, R_fixture 50.000Ohm, V_fixture 0: 20-80 % time 85.3ps typ, 106ps min, 76.4ps max; typ from 0.923 V to 0 V
[GND Clamp]
-1.785V   -901.2mA   -688.6mA   -1.21A
-1.094V   -214.7mA   -220.8mA   -215.3mA
-1.036V   -161.8mA   -183.6mA   -143.3mA
-978.8mV  -112.1mA   -147.2mA   -82.01mA
-921.2mV  -68.48mA   -112.4mA   -40.94mA
-863.6mV  -35.72mA   -79.61mA   -26.14mA
-806.1mV  -18.98mA   -50.62mA   -21.23mA
-748.5mV  -13.21mA   -27.8mA    -17.43mA
-690.9mV  -10.21mA   -13.8mA    -13.87mA
-575.8mV  -5.52mA    -4.739mA   -7.464mA
-345.4mV  -312.6uA   -378.8uA   -329uA
3.57V     10.68mA    8.508mA    13.66mA
[Power Clamp]
-1.77V    882.5mA    689.6mA    1.159A
-1.079V   212.4mA    226.4mA    212.1mA
-1.021V   160.9mA    189.3mA    146.7mA
-963.6mV  112.9mA    152.9mA    90.87mA
-906.1mV  71.13mA    117.8mA    52.88mA
-848.5mV  39.99mA    84.73mA    36.14mA
-790.9mV  23.76mA    55.38mA    28.45mA
-733.3mV  16.95mA    32.18mA    22.29mA
-618.2mV  8.932mA    9.702mA    11.91mA
-503mV    3.404mA    3.492mA    4.434mA
-330.3mV  151.6uA    319.4uA    178.5uA
3.585V    -5.406mA   -4.594mA   -6.496mA
[Pulldown]
-1.785V   -2.3mA     -1.8mA     -2.4mA
-1.209V   -4.7mA     -3.2mA     -5.3mA
-921.2mV  -10.71mA   -5.8mA     -12.52mA
-690.9mV  -12.11mA   -10.65mA   -11.59mA
-518.2mV  -10.81mA   -10.24mA   -10.35mA
1.094V    23.43mA    21.74mA    22.75mA
2.073V    31.84mA    28.54mA    30.34mA
2.361V    28.33mA    22.42mA    28.91mA
2.706V    20.69mA    6mA        22.85mA
2.994V    6.3mA      3mA        16.2mA
3.224V    3.6mA      2.5mA      6.2mA
3.57V     2.7mA      2mA        3.1mA
[Pullup]
-1.77V    1mA        973.7uA    673.7uA
-1.309V   2.5mA      1.574mA    2.963mA
-1.021V   9.6mA      3.616mA    12.02mA
-848.5mV  16.65mA    7.666mA    14.42mA
-618.2mV  16.89mA    14.81mA    14.74mA
763.6mV   -19.22mA   -17.31mA   -18.28mA
2.03V     -27.75mA   -24.55mA   -26.83mA
2.376V    -25.6mA    -21.23mA   -25.8mA
2.606V    -24.21mA   -12.89mA   -24.15mA
2.836V    -14.6mA    -9.132mA   -23.06mA
3.124V    -9.1mA     -7.453mA   -10.44mA
3.585V    -7.4mA     -6.826mA   -7mA
[Ramp]
R_load=50.000Ohm
dV/dt_r   549.090mV/104.500ps  503.159mV/126.000ps  550.830mV/98.000ps
dV/dt_f   549.090mV/100.000ps  503.159mV/124.000ps  550.830mV/89.500ps
[Rising waveform]
R_fixture=50.000Ohm
V_fixture=1.800
V_fixture_min=1.700
V_fixture_max=1.900
0s        784.1mV    775.7mV    828.3mV
39ps      790.4mV    774.9mV    845.4mV
68ps      845.8mV    776.7mV    1.005V
87ps      952.8mV    780.6mV    1.189V
125ps     1.266V     802.2mV    1.491V
163ps     1.491V     886.6mV    1.64V
202ps     1.606V     1.093V     1.709V
269ps     1.676V     1.432V     1.752V
355ps     1.698V     1.576V     1.764V
938ps     1.704V     1.622V     1.768V
[Rising waveform]
R_fixture=50.000Ohm
V_fixture=0
0s        -1.683mV   581.1uV    -1.622mV
48ps      -10.96mV   -1.132mV   10.5mV
77ps      29.02mV    -4.326mV   128.8mV
163ps     455.7mV    3.251mV    593.2mV
211ps     653mV      124.1mV    734.4mV
269ps     790.2mV    364mV      824.5mV
365ps     878.5mV    655.2mV    877.7mV
460ps     903mV      773.3mV    892.8mV
623ps     912mV      825.1mV    898.5mV
938ps     914.4mV    834.2mV    899.6mV
[Falling waveform]
R_fixture=50.000Ohm
V_fixture=1.800
V_fixture_min=1.700
V_fixture_max=1.900
0s        1.708V     1.621V     1.77V
39ps      1.72V      1.624V     1.771V
58ps      1.707V     1.628V     1.719V
96ps      1.585V     1.638V     1.494V
154ps     1.258V     1.613V     1.14V
202ps     1.036V     1.478V     973.2mV
250ps     911.5mV    1.277V     896.3mV
345ps     819mV      956.5mV    846.6mV
441ps     797.5mV    835.7mV    836.4mV
938ps     788.1mV    780.5mV    831.3mV
[Falling waveform]
R_fixture=50.000Ohm
V_fixture=0
0s        922.7mV    839.5mV    905mV
39ps      877.1mV    845.2mV    831.3mV
68ps      732mV      840.7mV    603mV
106ps     435.8mV    789.1mV    296.5mV
144ps     217mV      654mV      137.9mV
192ps     87.07mV    391.6mV    53.75mV
230ps     43.41mV    217.9mV    25.97mV
259ps     26.08mV    133.6mV    15.04mV
345ps     6.166mV    32.64mV    3.094mV
938ps     2.43uV     28.08uV    0V
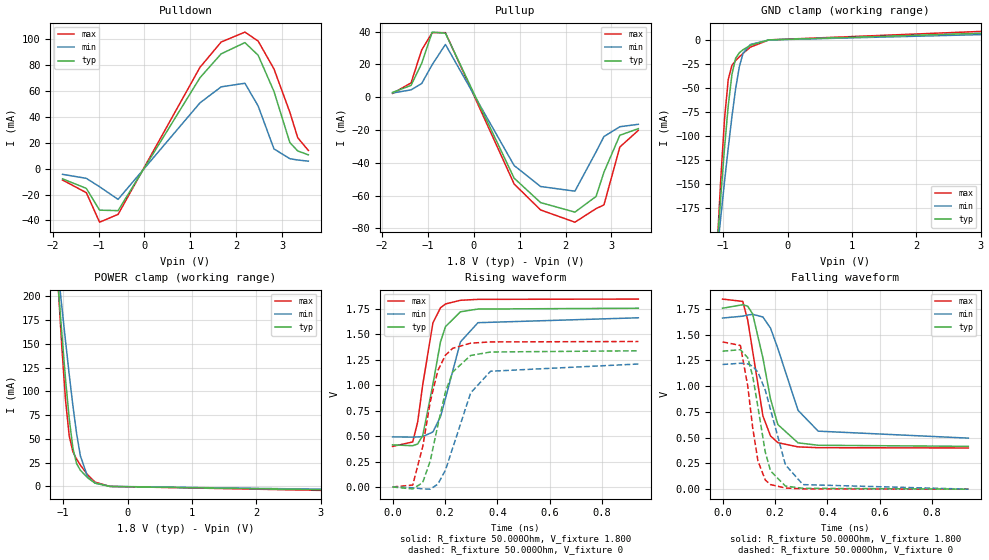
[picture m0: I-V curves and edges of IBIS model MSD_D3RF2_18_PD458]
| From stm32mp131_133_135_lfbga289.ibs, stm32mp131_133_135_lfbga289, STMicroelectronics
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[Model] MSD_D3RF2_18_PD458
Model_type   I/O
C_comp 2.372pF   2.291pF   2.493pF
Vinh = 1.150V
Vinl = 650.000mV
Vmeas = 900.000mV
Vref = 900.000mV
[Model Spec]
Vinh   1.150V   1.100V   1.200V
Vinl   650.000mV   600.000mV   700.000mV
Vmeas   900.000mV   850.000mV   950.000mV
Vref   900.000mV   850.000mV   950.000mV
[Temperature Range]   25.000   125.000   -40.000
[Voltage Range]   1.800V   1.700V   1.900V
[GND Clamp Reference]   0.00V   0.00V   0.00V
[Pulldown Reference]   0.00V   0.00V   0.00V
[POWER Clamp Reference]   1.800V   1.700V   1.900V
[Pullup Reference]   1.800V   1.700V   1.900V
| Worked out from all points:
|   slope of the pulldown table from 0 to 0.27 V, typ, clamps not added: 15.3 ohm
|   slope of the pullup table from 0 to 0.27 V, typ, clamps not added: 14.6 ohm
|   GND clamp passes 1 mA (typ) near -0.40 V on its own axis
|   POWER clamp passes 1 mA (typ) near -0.41 V on its own axis
|   rising waveform, R_fixture 50.000Ohm, V_fixture 1.800: 20-80 % time 57ps typ, 72.6ps min, 49.8ps max; typ from 0.415 V to 1.76 V
|   rising waveform, R_fixture 50.000Ohm, V_fixture 0: 20-80 % time 74.6ps typ, 94ps min, 65.8ps max; typ from 0.001 V to 1.34 V
|   falling waveform, R_fixture 50.000Ohm, V_fixture 1.800: 20-80 % time 65.1ps typ, 92.7ps min, 54.6ps max; typ from 1.76 V to 0.416 V
|   falling waveform, R_fixture 50.000Ohm, V_fixture 0: 20-80 % time 54.9ps typ, 77ps min, 45.7ps max; typ from 1.34 V to 0 V
[GND Clamp]
-1.785V   -902mA     -689.4mA   -1.211A
-1.094V   -215mA     -221.2mA   -215.8mA
-1.036V   -162.1mA   -183.9mA   -143.8mA
-978.8mV  -112.5mA   -147.5mA   -82.44mA
-921.2mV  -68.78mA   -112.6mA   -41.33mA
-863.6mV  -35.99mA   -79.83mA   -26.49mA
-806.1mV  -19.21mA   -50.81mA   -21.54mA
-748.5mV  -13.41mA   -27.96mA   -17.69mA
-690.9mV  -10.37mA   -13.94mA   -14.08mA
-575.8mV  -5.623mA   -4.825mA   -7.6mA
-287.9mV  -74.28uA   -124.4uA   -59.6uA
3.57V     8.01mA     6.376mA    10.24mA
[Power Clamp]
-1.77V    883.4mA    690.5mA    1.16A
-1.079V   212.7mA    226.7mA    212.7mA
-1.021V   161.3mA    189.6mA    147.2mA
-963.6mV  113.3mA    153.2mA    91.32mA
-906.1mV  71.44mA    118mA      53.27mA
-848.5mV  40.26mA    84.97mA    36.49mA
-790.9mV  24mA       55.59mA    28.76mA
-733.3mV  17.15mA    32.36mA    22.54mA
-618.2mV  9.062mA    9.82mA     12.07mA
-503mV    3.471mA    3.563mA    4.523mA
-272.7mV  29uA       101.1uA    30.42uA
3.585V    -4.055mA   -3.446mA   -4.875mA
[Pulldown]
-1.785V   -7.9mA     -4.4mA     -8.8mA
-1.267V   -15.3mA    -7.5mA     -18.6mA
-978.8mV  -32.1mA    -14mA      -41.43mA
-575.8mV  -32.49mA   -23.76mA   -35.4mA
1.209V    70.38mA    50.93mA    78.43mA
1.67V     88.85mA    63.32mA    97.99mA
2.188V    97.56mA    66.1mA     105.7mA
2.476V    87.8mA     48.52mA    98.76mA
2.821V    59.8mA     15.3mA     77.2mA
3.167V    20.2mA     7.7mA      43.7mA
3.339V    13.7mA     6.7mA      23.9mA
3.57V     10.7mA     5.8mA      14.1mA
[Pullup]
-1.77V    2.9mA      2.547mA    2.253mA
-1.367V   7.2mA      4.468mA    8.716mA
-1.136V   20.6mA     8.305mA    28.74mA
-906.1mV  39.68mA    19.85mA    39.39mA
-618.2mV  38.98mA    32.14mA    39.33mA
878.8mV   -49.38mA   -41.66mA   -52.89mA
1.455V    -64.25mA   -54.44mA   -68.74mA
2.203V    -70.07mA   -57.29mA   -76.2mA
2.664V    -60.5mA    -33.33mA   -67.94mA
2.836V    -45.7mA    -23.98mA   -65.64mA
3.182V    -23.2mA    -18.01mA   -30.38mA
3.585V    -19.2mA    -16.53mA   -20.22mA
[Ramp]
R_load=50.000Ohm
dV/dt_r   804.420mV/66.500ps  713.159mV/84.000ps  862.980mV/58.500ps
dV/dt_f   804.420mV/61.000ps  713.159mV/85.500ps  862.980mV/51.500ps
[Rising waveform]
R_fixture=50.000Ohm
V_fixture=1.800
V_fixture_min=1.700
V_fixture_max=1.900
0s        414.8mV    492.8mV    399.6mV
77ps      406.3mV    491.1mV    443.6mV
96ps      423.7mV    492.3mV    641.8mV
115ps     506.2mV    496.1mV    1.003V
154ps     1.01V      541.3mV    1.613V
183ps     1.427V     691.5mV    1.761V
202ps     1.576V     871.4mV    1.799V
259ps     1.722V     1.426V     1.835V
326ps     1.749V     1.615V     1.844V
938ps     1.757V     1.663V     1.847V
[Rising waveform]
R_fixture=50.000Ohm
V_fixture=0
0s        1.117mV    984.1uV    967.1uV
77ps      -18.12mV   -6.45mV    20.21mV
115ps     43.96mV    -17.88mV   396.8mV
144ps     258.8mV    -20.4mV    839.7mV
173ps     610.1mV    29.43mV    1.146V
202ps     937.7mV    167.8mV    1.296V
230ps     1.132V     387.8mV    1.364V
298ps     1.293V     925.1mV    1.414V
374ps     1.327V     1.138V     1.426V
938ps     1.339V     1.209V     1.43V
[Falling waveform]
R_fixture=50.000Ohm
V_fixture=1.800
V_fixture_min=1.700
V_fixture_max=1.900
0s        1.756V     1.661V     1.845V
77ps      1.79V      1.679V     1.822V
96ps      1.776V     1.69V      1.641V
115ps     1.699V     1.697V     1.337V
154ps     1.273V     1.671V     710.4mV
183ps     875mV      1.563V     517.1mV
211ps     627mV      1.365V     451mV
288ps     449.5mV    765.2mV    410.5mV
365ps     426.1mV    563mV      402.5mV
938ps     415.5mV    495.4mV    399.8mV
[Falling waveform]
R_fixture=50.000Ohm
V_fixture=0
0s        1.339V     1.21V      1.429V
68ps      1.354V     1.222V     1.395V
96ps      1.276V     1.216V     1.002V
115ps     1.097V     1.193V     596.2mV
135ps     796.1mV    1.135V     274.2mV
163ps     360.4mV    960.8mV    88.86mV
183ps     177.1mV    773.1mV    44.57mV
240ps     29.71mV    235.7mV    11.09mV
307ps     8.543mV    44.17mV    2.935mV
938ps     1.826uV    24.95uV    0V
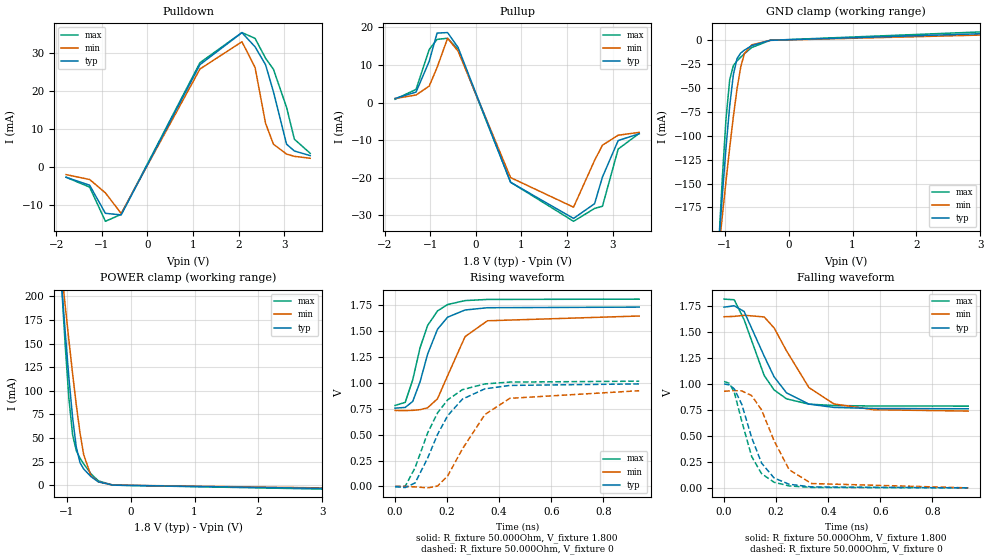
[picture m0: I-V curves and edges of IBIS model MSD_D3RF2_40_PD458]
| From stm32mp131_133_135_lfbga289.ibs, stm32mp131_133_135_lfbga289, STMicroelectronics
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[Model] MSD_D3RF2_40_PD458
Model_type   I/O
C_comp 2.372pF   2.291pF   2.493pF
Vinh = 1.150V
Vinl = 650.000mV
Vmeas = 900.000mV
Vref = 900.000mV
[Model Spec]
Vinh   1.150V   1.100V   1.200V
Vinl   650.000mV   600.000mV   700.000mV
Vmeas   900.000mV   850.000mV   950.000mV
Vref   900.000mV   850.000mV   950.000mV
[Temperature Range]   25.000   125.000   -40.000
[Voltage Range]   1.800V   1.700V   1.900V
[GND Clamp Reference]   0.00V   0.00V   0.00V
[Pulldown Reference]   0.00V   0.00V   0.00V
[POWER Clamp Reference]   1.800V   1.700V   1.900V
[Pullup Reference]   1.800V   1.700V   1.900V
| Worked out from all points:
|   slope of the pulldown table from 0 to 0.27 V, typ, clamps not added: 37.2 ohm
|   slope of the pullup table from 0 to 0.27 V, typ, clamps not added: 29.4 ohm
|   GND clamp passes 1 mA (typ) near -0.40 V on its own axis
|   POWER clamp passes 1 mA (typ) near -0.41 V on its own axis
|   rising waveform, R_fixture 50.000Ohm, V_fixture 1.800: 20-80 % time 78.8ps typ, 96.6ps min, 71.2ps max; typ from 0.756 V to 1.73 V
|   rising waveform, R_fixture 50.000Ohm, V_fixture 0: 20-80 % time 124ps typ, 142ps min, 113ps max; typ from -0.002 V to 0.99 V
|   falling waveform, R_fixture 50.000Ohm, V_fixture 1.800: 20-80 % time 114ps typ, 134ps min, 97.9ps max; typ from 1.74 V to 0.76 V
|   falling waveform, R_fixture 50.000Ohm, V_fixture 0: 20-80 % time 85ps typ, 101ps min, 73.3ps max; typ from 0.998 V to 0 V
[GND Clamp]
-1.785V   -902mA     -689.4mA   -1.211A
-1.094V   -215mA     -221.2mA   -215.8mA
-1.036V   -162.1mA   -183.9mA   -143.8mA
-978.8mV  -112.5mA   -147.5mA   -82.44mA
-921.2mV  -68.78mA   -112.6mA   -41.33mA
-863.6mV  -35.99mA   -79.83mA   -26.49mA
-806.1mV  -19.21mA   -50.81mA   -21.54mA
-748.5mV  -13.41mA   -27.96mA   -17.69mA
-690.9mV  -10.37mA   -13.94mA   -14.08mA
-575.8mV  -5.623mA   -4.825mA   -7.6mA
-287.9mV  -74.28uA   -124.4uA   -59.6uA
3.57V     8.01mA     6.376mA    10.24mA
[Power Clamp]
-1.77V    883.4mA    690.5mA    1.16A
-1.079V   212.7mA    226.7mA    212.7mA
-1.021V   161.3mA    189.6mA    147.2mA
-963.6mV  113.3mA    153.2mA    91.32mA
-906.1mV  71.44mA    118mA      53.27mA
-848.5mV  40.26mA    84.97mA    36.49mA
-790.9mV  24mA       55.59mA    28.76mA
-733.3mV  17.15mA    32.36mA    22.54mA
-618.2mV  9.062mA    9.82mA     12.07mA
-503mV    3.471mA    3.563mA    4.523mA
-272.7mV  29uA       101.1uA    30.42uA
3.585V    -4.055mA   -3.446mA   -4.875mA
[Pulldown]
-1.785V   -2.7mA     -2mA       -2.7mA
-1.267V   -4.8mA     -3.3mA     -5.3mA
-921.2mV  -12.19mA   -6.8mA     -14.29mA
-575.8mV  -12.6mA    -12.24mA   -12.47mA
1.152V    26.93mA    25.78mA    27.43mA
2.073V    35.35mA    32.95mA    35.37mA
2.361V    31.62mA    26.21mA    33.85mA
2.591V    26.91mA    11.5mA     28.62mA
2.764V    19.8mA     6mA        25.71mA
3.052V    6mA        3.4mA      15.7mA
3.224V    4.2mA      2.8mA      7.3mA
3.57V     3mA        2.3mA      3.6mA
[Pullup]
-1.77V    1.1mA      1.074mA    873.7uA
-1.309V   2.8mA      2.021mA    3.516mA
-1.021V   11mA       4.389mA    14.14mA
-848.5mV  18.5mA     9.339mA    16.82mA
-618.2mV  18.64mA    17.11mA    17.13mA
-387.9mV  14.68mA    13.71mA    14.13mA
763.6mV   -21.21mA   -19.96mA   -21.19mA
2.145V    -30.84mA   -27.84mA   -31.6mA
2.606V    -26.92mA   -15.4mA    -28.18mA
2.779V    -19.8mA    -11.34mA   -27.59mA
3.124V    -10.1mA    -8.679mA   -12.36mA
3.585V    -8.3mA     -7.926mA   -8.2mA
[Ramp]
R_load=50.000Ohm
dV/dt_r   588.420mV/102.000ps  549.869mV/120.000ps  611.520mV/93.000ps
dV/dt_f   588.420mV/99.500ps  549.869mV/118.500ps  611.520mV/86.500ps
[Rising waveform]
R_fixture=50.000Ohm
V_fixture=1.800
V_fixture_min=1.700
V_fixture_max=1.900
0s        755.6mV    733.1mV    781.7mV
39ps      762.2mV    732.4mV    811.3mV
68ps      820.9mV    734.1mV    1.03V
96ps      1.009V     740.6mV    1.338V
125ps     1.276V     758.9mV    1.553V
163ps     1.517V     845.6mV    1.694V
202ps     1.634V     1.069V     1.756V
269ps     1.703V     1.446V     1.794V
355ps     1.725V     1.599V     1.805V
938ps     1.731V     1.645V     1.808V
[Rising waveform]
R_fixture=50.000Ohm
V_fixture=0
0s        -2.078mV   648.8uV    -2.628mV
39ps      -11.37mV   -518uV     1.164mV
77ps      33.32mV    -4.628mV   180.2mV
125ps     272.2mV    -14.14mV   514.8mV
163ps     500.6mV    2.898mV    709mV
202ps     682.5mV    100.4mV    835.1mV
259ps     843mV      362.8mV    934.2mV
345ps     941.9mV    693.6mV    989.4mV
441ps     974.8mV    850.3mV    1.007V
938ps     989.7mV    923.8mV    1.016V
[Falling waveform]
R_fixture=50.000Ohm
V_fixture=1.800
V_fixture_min=1.700
V_fixture_max=1.900
0s        1.736V     1.644V     1.813V
39ps      1.749V     1.647V     1.807V
77ps      1.694V     1.658V     1.615V
154ps     1.266V     1.642V     1.08V
192ps     1.067V     1.537V     941.3mV
240ps     912.4mV    1.316V     855.1mV
326ps     804.4mV    963.3mV    804.1mV
422ps     772.7mV    806.2mV    791.2mV
575ps     762.6mV    750.4mV    786.2mV
938ps     759.7mV    737.7mV    785.3mV
[Falling waveform]
R_fixture=50.000Ohm
V_fixture=0
0s        997.8mV    928mV      1.022V
20ps      989.6mV    931.1mV    1.005V
39ps      952mV      933.7mV    920.8mV
68ps      802.2mV    931.5mV    639.9mV
106ps     482.8mV    886.1mV    301.4mV
144ps     238.1mV    749mV      136.4mV
192ps     95.31mV    453.2mV    53.72mV
250ps     34.53mV    174.4mV    18.63mV
336ps     8.87mV     41.54mV    4.122mV
938ps     17.76uV    45.91uV    -1.231uV
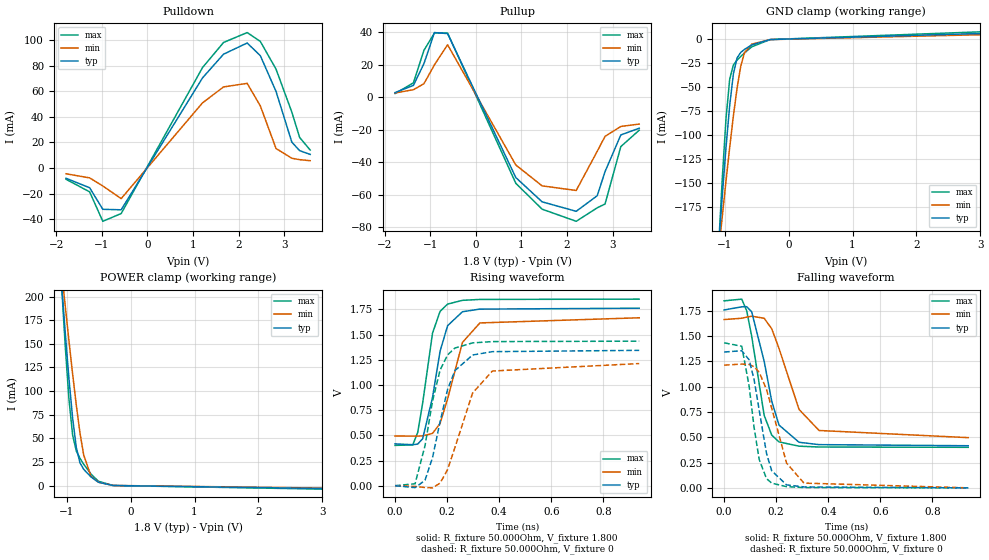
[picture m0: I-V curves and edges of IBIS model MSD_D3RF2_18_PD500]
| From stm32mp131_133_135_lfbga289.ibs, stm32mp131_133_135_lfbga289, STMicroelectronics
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[Model] MSD_D3RF2_18_PD500
Model_type   I/O
C_comp 2.389pF   2.307pF   2.511pF
Vinh = 1.150V
Vinl = 650.000mV
Vmeas = 900.000mV
Vref = 900.000mV
[Model Spec]
Vinh   1.150V   1.100V   1.200V
Vinl   650.000mV   600.000mV   700.000mV
Vmeas   900.000mV   850.000mV   950.000mV
Vref   900.000mV   850.000mV   950.000mV
[Temperature Range]   25.000   125.000   -40.000
[Voltage Range]   1.800V   1.700V   1.900V
[GND Clamp Reference]   0.00V   0.00V   0.00V
[Pulldown Reference]   0.00V   0.00V   0.00V
[POWER Clamp Reference]   1.800V   1.700V   1.900V
[Pullup Reference]   1.800V   1.700V   1.900V
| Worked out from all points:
|   slope of the pulldown table from 0 to 0.27 V, typ, clamps not added: 15.3 ohm
|   slope of the pullup table from 0 to 0.27 V, typ, clamps not added: 14.6 ohm
|   GND clamp passes 1 mA (typ) near -0.40 V on its own axis
|   POWER clamp passes 1 mA (typ) near -0.41 V on its own axis
|   rising waveform, R_fixture 50.000Ohm, V_fixture 1.800: 20-80 % time 57.5ps typ, 72.8ps min, 49.9ps max; typ from 0.416 V to 1.76 V
|   rising waveform, R_fixture 50.000Ohm, V_fixture 0: 20-80 % time 75ps typ, 94.3ps min, 66ps max; typ from 0.001 V to 1.34 V
|   falling waveform, R_fixture 50.000Ohm, V_fixture 1.800: 20-80 % time 65.4ps typ, 93ps min, 54.9ps max; typ from 1.76 V to 0.416 V
|   falling waveform, R_fixture 50.000Ohm, V_fixture 0: 20-80 % time 55.2ps typ, 77.2ps min, 45.9ps max; typ from 1.34 V to 0 V
[GND Clamp]
-1.785V   -902.3mA   -689.6mA   -1.211A
-1.094V   -215.1mA   -221.3mA   -215.9mA
-1.036V   -162.2mA   -184mA     -144mA
-978.8mV  -112.6mA   -147.7mA   -82.55mA
-921.2mV  -68.85mA   -112.7mA   -41.43mA
-863.6mV  -36.05mA   -79.88mA   -26.58mA
-806.1mV  -19.27mA   -50.85mA   -21.61mA
-748.5mV  -13.46mA   -28mA      -17.75mA
-690.9mV  -10.41mA   -13.96mA   -14.14mA
-575.8mV  -5.648mA   -4.846mA   -7.634mA
-287.9mV  -74.98uA   -125.3uA   -60.3uA
3.57V     7.346mA    5.855mA    9.39mA
[Power Clamp]
-1.77V    883.7mA    690.7mA    1.16A
-1.079V   212.9mA    226.9mA    212.8mA
-1.021V   161.3mA    189.7mA    147.3mA
-963.6mV  113.3mA    153.3mA    91.41mA
-906.1mV  71.51mA    118.1mA    53.37mA
-848.5mV  40.33mA    85.03mA    36.57mA
-790.9mV  24.05mA    55.63mA    28.83mA
-733.3mV  17.2mA     32.4mA     22.61mA
-618.2mV  9.094mA    9.85mA     12.12mA
-503mV    3.487mA    3.577mA    4.547mA
-272.7mV  29uA       100.4uA    30.26uA
3.585V    -3.718mA   -3.159mA   -4.469mA
[Pulldown]
-1.785V   -7.9mA     -4.4mA     -8.7mA
-1.267V   -15.3mA    -7.6mA     -18.5mA
-978.8mV  -32.1mA    -13.9mA    -41.45mA
-575.8mV  -32.49mA   -23.76mA   -35.41mA
1.209V    70.38mA    50.93mA    78.43mA
1.67V     88.85mA    63.32mA    97.99mA
2.188V    97.56mA    66.1mA     105.7mA
2.476V    87.72mA    48.54mA    98.81mA
2.821V    59.8mA     15.3mA     77.17mA
3.167V    20.3mA     7.7mA      43.7mA
3.339V    13.6mA     6.6mA      23.9mA
3.57V     10.7mA     5.8mA      14.1mA
[Pullup]
-1.77V    2.8mA      2.547mA    2.153mA
-1.367V   7.2mA      4.542mA    8.789mA
-1.136V   20.6mA     8.232mA    28.74mA
-906.1mV  39.61mA    19.82mA    39.37mA
-618.2mV  38.98mA    32.14mA    39.32mA
878.8mV   -49.37mA   -41.65mA   -52.89mA
1.455V    -64.25mA   -54.45mA   -68.75mA
2.203V    -70.07mA   -57.29mA   -76.2mA
2.664V    -60.51mA   -33.26mA   -67.94mA
2.836V    -45.7mA    -24.05mA   -65.58mA
3.182V    -23.2mA    -18.01mA   -30.35mA
3.585V    -19.1mA    -16.53mA   -20.3mA
[Ramp]
R_load=50.000Ohm
dV/dt_r   806.160mV/66.500ps  714.509mV/84.000ps  865.200mV/58.500ps
dV/dt_f   806.160mV/61.000ps  714.509mV/86.000ps  865.200mV/51.000ps
[Rising waveform]
R_fixture=50.000Ohm
V_fixture=1.800
V_fixture_min=1.700
V_fixture_max=1.900
0s        415.6mV    494mV      400.6mV
68ps      407.3mV    492.2mV    405mV
87ps      413.6mV    492.6mV    528.4mV
106ps     466.1mV    494.8mV    818.7mV
144ps     877mV      519.6mV    1.514V
173ps     1.335V     618.1mV    1.73V
202ps     1.588V     862.5mV    1.802V
259ps     1.726V     1.422V     1.839V
326ps     1.752V     1.615V     1.848V
938ps     1.761V     1.666V     1.851V
[Rising waveform]
R_fixture=50.000Ohm
V_fixture=0
0s        1.094mV    993.7uV    967.6uV
77ps      -18.75mV   -6.223mV   20.2mV
115ps     53.92mV    -17.53mV   396.9mV
144ps     279.7mV    -20.7mV    840.2mV
173ps     635.5mV    26.26mV    1.147V
202ps     957mV      161.3mV    1.298V
230ps     1.142V     378.9mV    1.366V
298ps     1.297V     920.6mV    1.417V
374ps     1.33V      1.138V     1.43V
938ps     1.343V     1.212V     1.434V
[Falling waveform]
R_fixture=50.000Ohm
V_fixture=1.800
V_fixture_min=1.700
V_fixture_max=1.900
0s        1.759V     1.664V     1.849V
68ps      1.79V      1.677V     1.866V
87ps      1.791V     1.688V     1.75V
106ps     1.741V     1.697V     1.5V
154ps     1.252V     1.677V     717.6mV
183ps     857.8mV    1.573V     521.7mV
211ps     621.2mV    1.379V     454.4mV
288ps     450.6mV    775.6mV    412.2mV
365ps     427.4mV    567.2mV    403.8mV
938ps     416.5mV    496.5mV    400.9mV
[Falling waveform]
R_fixture=50.000Ohm
V_fixture=0
0s        1.343V     1.213V     1.434V
68ps      1.356V     1.224V     1.4V
96ps      1.267V     1.22V      1.009V
115ps     1.075V     1.198V     602.8mV
135ps     768mV      1.143V     279.2mV
163ps     341mV      973.3mV    91.87mV
183ps     168.6mV    787.8mV    46.7mV
240ps     29.77mV    245.3mV    11.99mV
307ps     8.948mV    46.89mV    3.275mV
938ps     2.334uV    30.04uV    0V
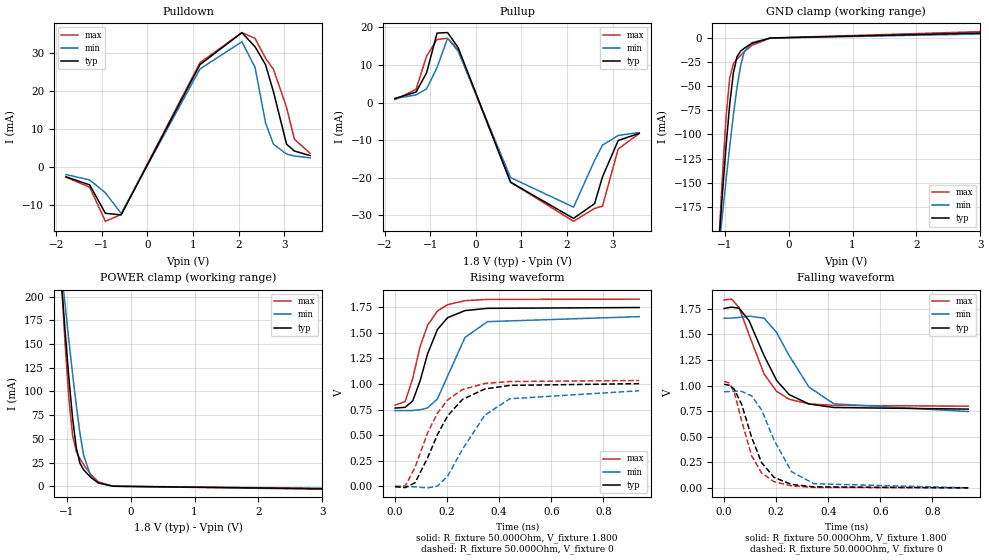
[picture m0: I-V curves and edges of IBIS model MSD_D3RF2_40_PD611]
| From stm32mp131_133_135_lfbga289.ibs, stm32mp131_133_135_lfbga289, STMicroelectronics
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[Model] MSD_D3RF2_40_PD611
Model_type   I/O
C_comp 2.419pF   2.337pF   2.541pF
Vinh = 1.150V
Vinl = 650.000mV
Vmeas = 900.000mV
Vref = 900.000mV
[Model Spec]
Vinh   1.150V   1.100V   1.200V
Vinl   650.000mV   600.000mV   700.000mV
Vmeas   900.000mV   850.000mV   950.000mV
Vref   900.000mV   850.000mV   950.000mV
[Temperature Range]   25.000   125.000   -40.000
[Voltage Range]   1.800V   1.700V   1.900V
[GND Clamp Reference]   0.00V   0.00V   0.00V
[Pulldown Reference]   0.00V   0.00V   0.00V
[POWER Clamp Reference]   1.800V   1.700V   1.900V
[Pullup Reference]   1.800V   1.700V   1.900V
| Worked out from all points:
|   slope of the pulldown table from 0 to 0.27 V, typ, clamps not added: 37.2 ohm
|   slope of the pullup table from 0 to 0.27 V, typ, clamps not added: 29.4 ohm
|   GND clamp passes 1 mA (typ) near -0.40 V on its own axis
|   POWER clamp passes 1 mA (typ) near -0.41 V on its own axis
|   rising waveform, R_fixture 50.000Ohm, V_fixture 1.800: 20-80 % time 79.5ps typ, 97.4ps min, 72.1ps max; typ from 0.765 V to 1.75 V
|   rising waveform, R_fixture 50.000Ohm, V_fixture 0: 20-80 % time 126ps typ, 144ps min, 116ps max; typ from -0.002 V to 1 V
|   falling waveform, R_fixture 50.000Ohm, V_fixture 1.800: 20-80 % time 117ps typ, 137ps min, 101ps max; typ from 1.75 V to 0.77 V
|   falling waveform, R_fixture 50.000Ohm, V_fixture 0: 20-80 % time 86.6ps typ, 103ps min, 75.3ps max; typ from 1.01 V to 0 V
[GND Clamp]
-1.785V   -902.8mA   -690.1mA   -1.212A
-1.094V   -215.3mA   -221.5mA   -216.2mA
-1.036V   -162.4mA   -184.2mA   -144.2mA
-978.8mV  -112.7mA   -147.8mA   -82.77mA
-921.2mV  -69.01mA   -112.7mA   -41.62mA
-863.6mV  -36.19mA   -80mA      -26.75mA
-806.1mV  -19.39mA   -50.94mA   -21.76mA
-748.5mV  -13.55mA   -28.08mA   -17.89mA
-690.9mV  -10.49mA   -14.03mA   -14.25mA
-575.8mV  -5.7mA     -4.889mA   -7.701mA
-287.9mV  -76.48uA   -127.3uA   -62uA
3.57V     6.005mA    4.786mA    7.679mA
[Power Clamp]
-1.77V    884.1mA    691.1mA    1.161A
-1.079V   213.2mA    227.1mA    213.1mA
-1.021V   161.5mA    189.8mA    147.5mA
-963.6mV  113.5mA    153.4mA    91.67mA
-906.1mV  71.67mA    118.2mA    53.57mA
-848.5mV  40.47mA    85.14mA    36.75mA
-790.9mV  24.17mA    55.75mA    28.98mA
-733.3mV  17.3mA     32.49mA    22.73mA
-618.2mV  9.163mA    9.916mA    12.2mA
-503mV    3.524mA    3.614mA    4.591mA
-272.7mV  32uA       104.5uA    32.1uA
3.585V    -3.042mA   -2.585mA   -3.657mA
[Pulldown]
-1.785V   -2.6mA     -2mA       -2.7mA
-1.267V   -4.7mA     -3.4mA     -5.3mA
-921.2mV  -12.19mA   -6.8mA     -14.29mA
-575.8mV  -12.6mA    -12.24mA   -12.47mA
1.152V    26.93mA    25.78mA    27.43mA
2.073V    35.36mA    32.95mA    35.37mA
2.361V    31.62mA    26.21mA    33.85mA
2.591V    26.91mA    11.6mA     28.61mA
2.764V    19.8mA     6mA        25.7mA
3.052V    6mA        3.4mA      15.7mA
3.224V    4.2mA      2.9mA      7.3mA
3.57V     3mA        2.4mA      3.6mA
[Pullup]
-1.77V    1.1mA      1.074mA    800uA
-1.309V   2.8mA      2.047mA    3.516mA
-1.079V   7.9mA      3.642mA    12.35mA
-848.5mV  18.5mA     9.339mA    16.82mA
-618.2mV  18.64mA    17.11mA    17.13mA
-387.9mV  14.68mA    13.71mA    14.14mA
763.6mV   -21.21mA   -19.96mA   -21.19mA
2.145V    -30.84mA   -27.84mA   -31.61mA
2.606V    -26.91mA   -15.4mA    -28.18mA
2.779V    -19.8mA    -11.34mA   -27.6mA
3.124V    -10.1mA    -8.753mA   -12.36mA
3.585V    -8.2mA     -7.974mA   -8.247mA
[Ramp]
R_load=50.000Ohm
dV/dt_r   594.840mV/103.500ps  554.759mV/121.000ps  620.220mV/95.000ps
dV/dt_f   594.840mV/102.500ps  554.759mV/121.000ps  620.220mV/88.500ps
[Rising waveform]
R_fixture=50.000Ohm
V_fixture=1.800
V_fixture_min=1.700
V_fixture_max=1.900
0s        765.4mV    740.9mV    794.4mV
39ps      772.8mV    740.2mV    828.8mV
68ps      836.2mV    741.9mV    1.057V
96ps      1.03V      748.6mV    1.364V
125ps     1.296V     767.4mV    1.575V
163ps     1.534V     855.3mV    1.714V
202ps     1.649V     1.08V      1.776V
269ps     1.718V     1.456V     1.815V
355ps     1.74V      1.61V      1.827V
938ps     1.748V     1.659V     1.83V
[Rising waveform]
R_fixture=50.000Ohm
V_fixture=0
0s        -2.222mV   650.8uV    -2.862mV
39ps      -11.59mV   -515.2uV   3.374mV
77ps      36.21mV    -4.627mV   187.2mV
125ps     278.8mV    -14.15mV   522.6mV
163ps     507.1mV    2.861mV    717mV
202ps     689.3mV    100.4mV    844.8mV
259ps     850.7mV    363.2mV    946.5mV
345ps     952.1mV    696.4mV    1.006V
441ps     987.1mV    856.3mV    1.025V
938ps     1.004V     934.6mV    1.035V
[Falling waveform]
R_fixture=50.000Ohm
V_fixture=1.800
V_fixture_min=1.700
V_fixture_max=1.900
0s        1.753V     1.657V     1.836V
29ps      1.766V     1.659V     1.844V
58ps      1.755V     1.665V     1.76V
96ps      1.633V     1.678V     1.496V
154ps     1.29V      1.658V     1.111V
202ps     1.049V     1.517V     942.8mV
250ps     911.7mV    1.292V     866mV
326ps     819.3mV    984.9mV    820.5mV
422ps     784.9mV    820.9mV    805.3mV
938ps     769.5mV    745.7mV    798.1mV
[Falling waveform]
R_fixture=50.000Ohm
V_fixture=0
0s        1.012V     938.7mV    1.041V
20ps      1.003V     941.8mV    1.024V
39ps      964.8mV    944.5mV    935.7mV
68ps      812.5mV    942.5mV    651.7mV
106ps     492.2mV    898.1mV    313.1mV
144ps     247.5mV    762.5mV    146mV
192ps     102.3mV    467.2mV    60.22mV
259ps     33.83mV    158.6mV    19.02mV
345ps     9.484mV    40.55mV    4.615mV
938ps     -8.116uV   50.5uV     6.367uV
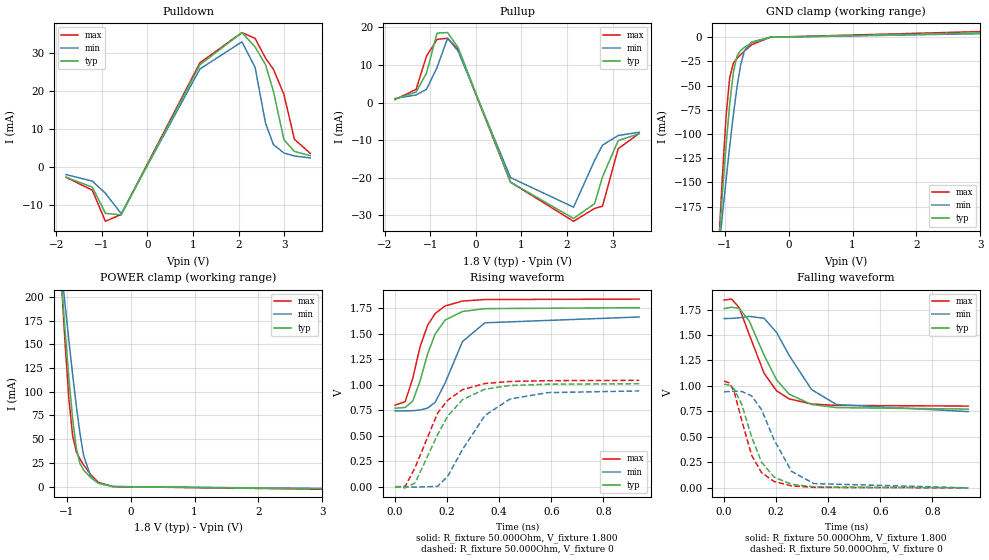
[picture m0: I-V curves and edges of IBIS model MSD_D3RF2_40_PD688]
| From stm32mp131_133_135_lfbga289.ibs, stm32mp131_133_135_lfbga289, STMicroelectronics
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[Model] MSD_D3RF2_40_PD688
Model_type   I/O
C_comp 2.432pF   2.349pF   2.554pF
Vinh = 1.150V
Vinl = 650.000mV
Vmeas = 900.000mV
Vref = 900.000mV
[Model Spec]
Vinh   1.150V   1.100V   1.200V
Vinl   650.000mV   600.000mV   700.000mV
Vmeas   900.000mV   850.000mV   950.000mV
Vref   900.000mV   850.000mV   950.000mV
[Temperature Range]   25.000   125.000   -40.000
[Voltage Range]   1.800V   1.700V   1.900V
[GND Clamp Reference]   0.00V   0.00V   0.00V
[Pulldown Reference]   0.00V   0.00V   0.00V
[POWER Clamp Reference]   1.800V   1.700V   1.900V
[Pullup Reference]   1.800V   1.700V   1.900V
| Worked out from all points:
|   slope of the pulldown table from 0 to 0.27 V, typ, clamps not added: 37.2 ohm
|   slope of the pullup table from 0 to 0.27 V, typ, clamps not added: 29.4 ohm
|   GND clamp passes 1 mA (typ) near -0.40 V on its own axis
|   POWER clamp passes 1 mA (typ) near -0.41 V on its own axis
|   rising waveform, R_fixture 50.000Ohm, V_fixture 1.800: 20-80 % time 79.8ps typ, 97.7ps min, 72.6ps max; typ from 0.769 V to 1.75 V
|   rising waveform, R_fixture 50.000Ohm, V_fixture 0: 20-80 % time 127ps typ, 144ps min, 117ps max; typ from -0.002 V to 1.01 V
|   falling waveform, R_fixture 50.000Ohm, V_fixture 1.800: 20-80 % time 118ps typ, 138ps min, 102ps max; typ from 1.76 V to 0.773 V
|   falling waveform, R_fixture 50.000Ohm, V_fixture 0: 20-80 % time 87.3ps typ, 104ps min, 76ps max; typ from 1.02 V to 0 V
[GND Clamp]
-1.785V   -902.9mA   -690.2mA   -1.212A
-1.094V   -215.4mA   -221.6mA   -216.3mA
-1.036V   -162.5mA   -184.2mA   -144.3mA
-978.8mV  -112.8mA   -147.8mA   -82.88mA
-921.2mV  -69.08mA   -112.8mA   -41.72mA
-863.6mV  -36.25mA   -80.05mA   -26.83mA
-806.1mV  -19.45mA   -51mA      -21.84mA
-748.5mV  -13.61mA   -28.13mA   -17.96mA
-690.9mV  -10.53mA   -14.07mA   -14.3mA
-575.8mV  -5.725mA   -4.911mA   -7.736mA
-287.9mV  -77.18uA   -128.3uA   -62.8uA
3.57V     5.336mA    4.258mA    6.829mA
[Power Clamp]
-1.77V    884.4mA    691.3mA    1.161A
-1.079V   213.2mA    227.2mA    213.2mA
-1.021V   161.7mA    189.9mA    147.7mA
-963.6mV  113.6mA    153.5mA    91.76mA
-906.1mV  71.75mA    118.3mA    53.67mA
-848.5mV  40.54mA    85.21mA    36.83mA
-790.9mV  24.24mA    55.8mA     29.06mA
-733.3mV  17.36mA    32.54mA    22.8mA
-618.2mV  9.196mA    9.941mA    12.25mA
-503mV    3.543mA    3.631mA    4.61mA
-272.7mV  33uA       105.9uA    31.94uA
3.585V    -2.704mA   -2.298mA   -3.251mA
[Pulldown]
-1.785V   -2.7mA     -2mA       -2.7mA
-1.209V   -5.3mA     -3.7mA     -6.1mA
-921.2mV  -12.19mA   -6.9mA     -14.28mA
-575.8mV  -12.6mA    -12.25mA   -12.47mA
1.152V    26.92mA    25.79mA    27.43mA
2.073V    35.36mA    32.94mA    35.37mA
2.361V    31.62mA    26.22mA    33.85mA
2.591V    26.91mA    11.5mA     28.62mA
2.764V    19.9mA     5.9mA      25.7mA
2.994V    7.2mA      3.7mA      19.1mA
3.224V    4.1mA      2.9mA      7.3mA
3.57V     3mA        2.4mA      3.6mA
[Pullup]
-1.77V    1mA        1.1mA      800uA
-1.309V   2.8mA      2.021mA    3.516mA
-1.079V   7.9mA      3.568mA    12.4mA
-848.5mV  18.49mA    9.346mA    16.82mA
-618.2mV  18.64mA    17.12mA    17.12mA
-387.9mV  14.68mA    13.72mA    14.14mA
763.6mV   -21.2mA    -19.96mA   -21.19mA
2.145V    -30.84mA   -27.84mA   -31.6mA
2.606V    -26.91mA   -15.4mA    -28.18mA
2.779V    -19.8mA    -11.34mA   -27.59mA
3.124V    -10.1mA    -8.753mA   -12.28mA
3.585V    -8.3mA     -7.9mA     -8.2mA
[Ramp]
R_load=50.000Ohm
dV/dt_r   597.000mV/104.000ps  556.439mV/121.500ps  623.160mV/95.500ps
dV/dt_f   597.000mV/102.500ps  556.439mV/121.500ps  623.160mV/90.000ps
[Rising waveform]
R_fixture=50.000Ohm
V_fixture=1.800
V_fixture_min=1.700
V_fixture_max=1.900
0s        768.7mV    743.6mV    798.8mV
39ps      776.3mV    742.8mV    833.4mV
68ps      839.9mV    744.6mV    1.062V
96ps      1.034V     751.3mV    1.37V
125ps     1.301V     770.2mV    1.581V
154ps     1.496V     826.3mV    1.697V
192ps     1.632V     1.015V     1.771V
259ps     1.717V     1.422V     1.819V
345ps     1.745V     1.606V     1.834V
938ps     1.754V     1.663V     1.838V
[Rising waveform]
R_fixture=50.000Ohm
V_fixture=0
0s        -2.222mV   651.5uV    -2.862mV
39ps      -11.6mV    -514.1uV   3.367mV
77ps      36.2mV     -4.627mV   187.2mV
163ps     507.6mV    2.847mV    718.6mV
202ps     690.4mV    100.4mV    847.5mV
259ps     852.8mV    363.4mV    950.7mV
345ps     955.6mV    697.4mV    1.011V
441ps     991.3mV    858.5mV    1.031V
585ps     1.004V     921.7mV    1.039V
938ps     1.009V     938.2mV    1.042V
[Falling waveform]
R_fixture=50.000Ohm
V_fixture=1.800
V_fixture_min=1.700
V_fixture_max=1.900
0s        1.759V     1.662V     1.843V
29ps      1.772V     1.663V     1.852V
58ps      1.761V     1.669V     1.769V
96ps      1.641V     1.683V     1.509V
154ps     1.3V       1.664V     1.123V
202ps     1.059V     1.524V     951.5mV
250ps     919.1mV    1.3V       873.2mV
336ps     818.7mV    964.9mV    823mV
432ps     787.4mV    817.7mV    809.2mV
938ps     772.9mV    748.4mV    802.5mV
[Falling waveform]
R_fixture=50.000Ohm
V_fixture=0
0s        1.017V     942.4mV    1.048V
20ps      1.008V     945.5mV    1.03V
39ps      970.1mV    948.1mV    943mV
68ps      818.4mV    946.2mV    659.4mV
106ps     498.1mV    902.2mV    319.2mV
144ps     252mV      767.1mV    150.1mV
192ps     105.2mV    472.2mV    62.52mV
259ps     35.19mV    162.3mV    20.01mV
345ps     9.966mV    42.1mV     4.94mV
938ps     -8.778uV   62.32uV    5.678uV
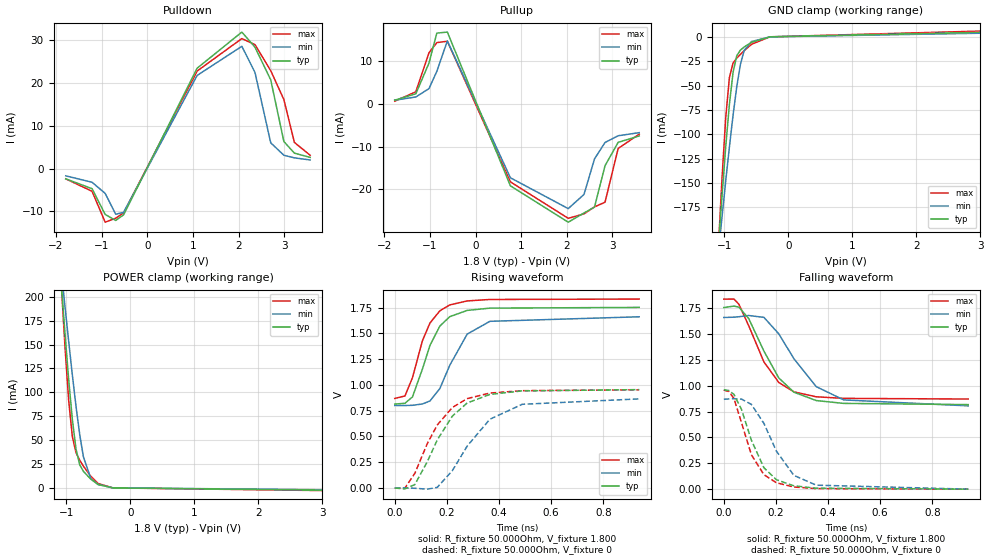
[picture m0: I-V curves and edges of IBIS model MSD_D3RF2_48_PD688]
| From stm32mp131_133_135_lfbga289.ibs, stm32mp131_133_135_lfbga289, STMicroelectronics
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[Model] MSD_D3RF2_48_PD688
Model_type   I/O
C_comp 2.432pF   2.349pF   2.554pF
Vinh = 1.150V
Vinl = 650.000mV
Vmeas = 900.000mV
Vref = 900.000mV
[Model Spec]
Vinh   1.150V   1.100V   1.200V
Vinl   650.000mV   600.000mV   700.000mV
Vmeas   900.000mV   850.000mV   950.000mV
Vref   900.000mV   850.000mV   950.000mV
[Temperature Range]   25.000   125.000   -40.000
[Voltage Range]   1.800V   1.700V   1.900V
[GND Clamp Reference]   0.00V   0.00V   0.00V
[Pulldown Reference]   0.00V   0.00V   0.00V
[POWER Clamp Reference]   1.800V   1.700V   1.900V
[Pullup Reference]   1.800V   1.700V   1.900V
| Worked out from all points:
|   slope of the pulldown table from 0 to 0.27 V, typ, clamps not added: 41 ohm
|   slope of the pullup table from 0 to 0.27 V, typ, clamps not added: 32.3 ohm
|   GND clamp passes 1 mA (typ) near -0.40 V on its own axis
|   POWER clamp passes 1 mA (typ) near -0.41 V on its own axis
|   rising waveform, R_fixture 50.000Ohm, V_fixture 1.800: 20-80 % time 83.5ps typ, 102ps min, 77.7ps max; typ from 0.813 V to 1.75 V
|   rising waveform, R_fixture 50.000Ohm, V_fixture 0: 20-80 % time 133ps typ, 156ps min, 127ps max; typ from -0.002 V to 0.953 V
|   falling waveform, R_fixture 50.000Ohm, V_fixture 1.800: 20-80 % time 123ps typ, 148ps min, 113ps max; typ from 1.75 V to 0.817 V
|   falling waveform, R_fixture 50.000Ohm, V_fixture 0: 20-80 % time 90.2ps typ, 110ps min, 82.1ps max; typ from 0.961 V to 0 V
[GND Clamp]
-1.785V   -902.9mA   -690.2mA   -1.212A
-1.094V   -215.4mA   -221.6mA   -216.3mA
-1.036V   -162.5mA   -184.2mA   -144.3mA
-978.8mV  -112.8mA   -147.8mA   -82.88mA
-921.2mV  -69.08mA   -112.8mA   -41.72mA
-863.6mV  -36.25mA   -80.05mA   -26.83mA
-806.1mV  -19.45mA   -51mA      -21.84mA
-748.5mV  -13.61mA   -28.13mA   -17.96mA
-690.9mV  -10.53mA   -14.07mA   -14.3mA
-575.8mV  -5.725mA   -4.911mA   -7.736mA
-287.9mV  -77.18uA   -128.3uA   -62.8uA
3.57V     5.336mA    4.258mA    6.829mA
[Power Clamp]
-1.77V    884.4mA    691.3mA    1.161A
-1.079V   213.2mA    227.2mA    213.2mA
-1.021V   161.7mA    189.9mA    147.7mA
-963.6mV  113.6mA    153.5mA    91.76mA
-906.1mV  71.75mA    118.3mA    53.67mA
-848.5mV  40.54mA    85.21mA    36.83mA
-790.9mV  24.24mA    55.8mA     29.06mA
-733.3mV  17.36mA    32.54mA    22.8mA
-618.2mV  9.196mA    9.941mA    12.25mA
-503mV    3.543mA    3.631mA    4.61mA
-272.7mV  33uA       105.9uA    31.94uA
3.585V    -2.704mA   -2.298mA   -3.251mA
[Pulldown]
-1.785V   -2.4mA     -1.7mA     -2.4mA
-1.209V   -4.7mA     -3.2mA     -5.3mA
-921.2mV  -10.71mA   -5.8mA     -12.52mA
-690.9mV  -12.11mA   -10.66mA   -11.59mA
-518.2mV  -10.81mA   -10.23mA   -10.35mA
1.094V    23.43mA    21.74mA    22.76mA
2.073V    31.85mA    28.53mA    30.34mA
2.361V    28.32mA    22.42mA    28.91mA
2.706V    20.7mA     6mA        22.85mA
2.994V    6.3mA      3.1mA      16.1mA
3.224V    3.6mA      2.5mA      6.1mA
3.57V     2.6mA      2mA        3.1mA
[Pullup]
-1.77V    900uA      900uA      673.7uA
-1.309V   2.4mA      1.647mA    2.863mA
-1.021V   9.6mA      3.616mA    12.02mA
-848.5mV  16.65mA    7.674mA    14.42mA
-618.2mV  16.89mA    14.82mA    14.74mA
763.6mV   -19.21mA   -17.32mA   -18.28mA
2.03V     -27.75mA   -24.56mA   -26.84mA
2.376V    -25.59mA   -21.23mA   -25.8mA
2.606V    -24.2mA    -12.89mA   -24.15mA
2.836V    -14.5mA    -9.032mA   -23.07mA
3.124V    -9mA       -7.453mA   -10.44mA
3.585V    -7.5mA     -6.726mA   -7.074mA
[Ramp]
R_load=50.000Ohm
dV/dt_r   566.190mV/109.000ps  516.359mV/129.500ps  573.900mV/103.500ps
dV/dt_f   566.190mV/107.000ps  516.359mV/130.000ps  573.900mV/97.500ps
[Rising waveform]
R_fixture=50.000Ohm
V_fixture=1.800
V_fixture_min=1.700
V_fixture_max=1.900
0s        812.9mV    799.5mV    867.6mV
39ps      820.6mV    798.8mV    891.4mV
68ps      882.2mV    800.9mV    1.069V
106ps     1.152V     813.7mV    1.427V
135ps     1.382V     842.6mV    1.599V
173ps     1.57V      963.7mV    1.718V
211ps     1.661V     1.189V     1.775V
278ps     1.722V     1.492V     1.814V
365ps     1.744V     1.616V     1.828V
938ps     1.751V     1.66V      1.832V
[Rising waveform]
R_fixture=50.000Ohm
V_fixture=0
0s        -1.816mV   577.3uV    -1.965mV
39ps      -10.62mV   -570.2uV   -1.59mV
77ps      31.62mV    -4.463mV   140.1mV
125ps     254.6mV    -13.05mV   430.3mV
163ps     464.1mV    4.539mV    610mV
221ps     696.1mV    166.4mV    779.9mV
278ps     823.7mV    405.7mV    865.8mV
365ps     906.5mV    665.7mV    919.9mV
489ps     940.7mV    810.6mV    942.9mV
938ps     953.1mV    863.1mV    951.1mV
[Falling waveform]
R_fixture=50.000Ohm
V_fixture=1.800
V_fixture_min=1.700
V_fixture_max=1.900
0s        1.755V     1.659V     1.836V
39ps      1.769V     1.662V     1.837V
58ps      1.759V     1.666V     1.787V
96ps      1.647V     1.678V     1.577V
154ps     1.334V     1.66V      1.23V
211ps     1.075V     1.501V     1.031V
269ps     937mV      1.261V     940.3mV
355ps     856.1mV    990.5mV    892.5mV
460ps     828.8mV    862.5mV    877.4mV
938ps     817.1mV    805mV      870.9mV
[Falling waveform]
R_fixture=50.000Ohm
V_fixture=0
0s        961.1mV    868.8mV    956.5mV
20ps      952.9mV    872mV      943mV
39ps      915.8mV    874.3mV    876.1mV
68ps      770.3mV    870mV      642mV
106ps     472.6mV    819.1mV    332.1mV
154ps     206.9mV    635.4mV    139.7mV
202ps     91.16mV    367.3mV    61.75mV
269ps     32.18mV    132.9mV    20.84mV
355ps     9.412mV    38.44mV    5.484mV
938ps     -10.08uV   75.71uV    -20.42uV
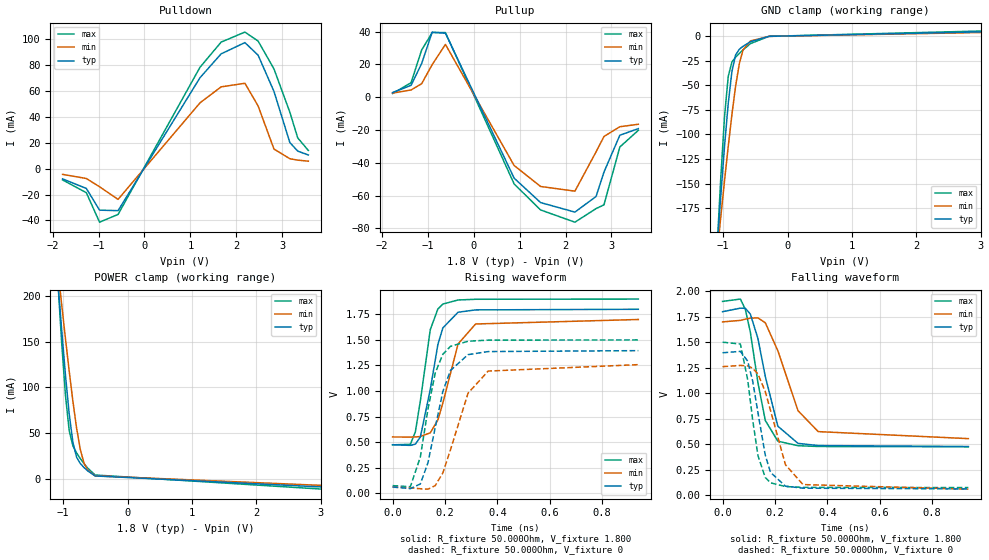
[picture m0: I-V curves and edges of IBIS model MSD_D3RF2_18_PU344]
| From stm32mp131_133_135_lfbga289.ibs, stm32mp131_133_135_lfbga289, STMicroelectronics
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[Model] MSD_D3RF2_18_PU344
Model_type   I/O
C_comp 2.316pF   2.235pF   2.435pF
Vinh = 1.150V
Vinl = 650.000mV
Vmeas = 900.000mV
Vref = 900.000mV
[Model Spec]
Vinh   1.150V   1.100V   1.200V
Vinl   650.000mV   600.000mV   700.000mV
Vmeas   900.000mV   850.000mV   950.000mV
Vref   900.000mV   850.000mV   950.000mV
[Temperature Range]   25.000   125.000   -40.000
[Voltage Range]   1.800V   1.700V   1.900V
[GND Clamp Reference]   0.00V   0.00V   0.00V
[Pulldown Reference]   0.00V   0.00V   0.00V
[POWER Clamp Reference]   1.800V   1.700V   1.900V
[Pullup Reference]   1.800V   1.700V   1.900V
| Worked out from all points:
|   slope of the pulldown table from 0 to 0.27 V, typ, clamps not added: 15.3 ohm
|   slope of the pullup table from 0 to 0.27 V, typ, clamps not added: 14.6 ohm
|   GND clamp passes 1 mA (typ) near -0.41 V on its own axis
|   POWER clamp passes 1 mA (typ) near -0.41 V on its own axis
|   rising waveform, R_fixture 50.000Ohm, V_fixture 1.800: 20-80 % time 55ps typ, 70.6ps min, 47.3ps max; typ from 0.474 V to 1.8 V
|   rising waveform, R_fixture 50.000Ohm, V_fixture 0: 20-80 % time 70.4ps typ, 89.8ps min, 61.3ps max; typ from 0.06 V to 1.4 V
|   falling waveform, R_fixture 50.000Ohm, V_fixture 1.800: 20-80 % time 65.8ps typ, 93.1ps min, 55.7ps max; typ from 1.8 V to 0.475 V
|   falling waveform, R_fixture 50.000Ohm, V_fixture 0: 20-80 % time 55.5ps typ, 77.4ps min, 46.5ps max; typ from 1.4 V to 0.06 V
[GND Clamp]
-1.785V   -901.1mA   -688.6mA   -1.21A
-1.094V   -214.7mA   -220.8mA   -215.3mA
-1.036V   -161.7mA   -183.5mA   -143.3mA
-978.8mV  -112.2mA   -147.2mA   -81.99mA
-921.2mV  -68.46mA   -112.3mA   -40.92mA
-863.6mV  -35.71mA   -79.59mA   -26.13mA
-806.1mV  -18.97mA   -50.59mA   -21.23mA
-748.5mV  -13.2mA    -27.78mA   -17.42mA
-690.9mV  -10.2mA    -13.78mA   -13.86mA
-575.8mV  -5.513mA   -4.723mA   -7.459mA
-287.9mV  -68.99uA   -116uA     -52.99uA
3.57V     5.268mA    4.537mA    6.293mA
[Power Clamp]
-1.77V    882.6mA    689.9mA    1.159A
-1.079V   212.4mA    226.5mA    212.1mA
-1.021V   160.9mA    189.3mA    146.7mA
-963.6mV  112.9mA    152.9mA    90.9mA
-906.1mV  71.15mA    117.8mA    52.89mA
-848.5mV  40.01mA    84.77mA    36.16mA
-790.9mV  23.78mA    55.42mA    28.47mA
-733.3mV  16.97mA    32.21mA    22.3mA
-675.8mV  12.59mA    17.37mA    16.79mA
-618.2mV  8.95mA     9.729mA    11.92mA
-503mV    3.412mA    3.511mA    4.443mA
3.585V    -10.57mA   -8.572mA   -13.43mA
[Pulldown]
-1.785V   -7.9mA     -4.4mA     -8.7mA
-1.267V   -15.3mA    -7.6mA     -18.6mA
-978.8mV  -32.1mA    -14mA      -41.42mA
-575.8mV  -32.49mA   -23.76mA   -35.4mA
1.209V    70.38mA    50.93mA    78.44mA
1.67V     88.85mA    63.31mA    97.95mA
2.188V    97.57mA    66.1mA     105.7mA
2.476V    87.8mA     48.51mA    98.73mA
2.821V    59.8mA     15.2mA     77.22mA
3.167V    20.2mA     7.7mA      43.7mA
3.339V    13.6mA     6.6mA      23.8mA
3.57V     10.6mA     5.8mA      14.1mA
[Pullup]
-1.77V    2.8mA      2.474mA    2.179mA
-1.367V   7.2mA      4.368mA    8.789mA
-1.136V   20.5mA     8.205mA    28.74mA
-906.1mV  39.65mA    19.85mA    39.33mA
-618.2mV  38.98mA    32.13mA    39.33mA
878.8mV   -49.38mA   -41.66mA   -52.89mA
1.455V    -64.25mA   -54.44mA   -68.74mA
2.203V    -70.07mA   -57.29mA   -76.21mA
2.664V    -60.53mA   -33.33mA   -67.93mA
2.836V    -45.7mA    -23.98mA   -65.63mA
3.182V    -23.2mA    -18.03mA   -30.38mA
3.585V    -19.2mA    -16.53mA   -20.22mA
[Ramp]
R_load=50.000Ohm
dV/dt_r   797.940mV/63.000ps  704.436mV/80.500ps  856.173mV/55.000ps
dV/dt_f   797.940mV/61.000ps  704.436mV/86.000ps  856.173mV/52.000ps
[Rising waveform]
R_fixture=50.000Ohm
V_fixture=1.800
V_fixture_min=1.700
V_fixture_max=1.900
0s        474.1mV    549.8mV    472.9mV
68ps      467.5mV    548.8mV    477.9mV
87ps      479.5mV    550.2mV    600.4mV
106ps     548.7mV    554.2mV    901.8mV
144ps     1.016V     590.7mV    1.601V
173ps     1.456V     716.5mV    1.803V
192ps     1.618V     882.9mV    1.851V
250ps     1.771V     1.461V     1.891V
317ps     1.794V     1.656V     1.898V
938ps     1.8V       1.7V       1.9V
[Rising waveform]
R_fixture=50.000Ohm
V_fixture=0
0s        60.38mV    57.89mV    73.51mV
68ps      44.28mV    52.25mV    63.02mV
106ps     90.18mV    42.97mV    353.9mV
135ps     296.4mV    38.84mV    821.5mV
163ps     645.6mV    74.32mV    1.178V
192ps     996.5mV    198.4mV    1.36V
221ps     1.201V     423.8mV    1.437V
288ps     1.356V     978.3mV    1.487V
365ps     1.386V     1.195V     1.498V
938ps     1.395V     1.258V     1.5V
[Falling waveform]
R_fixture=50.000Ohm
V_fixture=1.800
V_fixture_min=1.700
V_fixture_max=1.900
0s        1.798V     1.698V     1.899V
68ps      1.833V     1.713V     1.922V
87ps      1.831V     1.725V     1.821V
106ps     1.775V     1.735V     1.597V
135ps     1.535V     1.737V     1.102V
163ps     1.164V     1.69V      731.8mV
211ps     674.8mV    1.415V     527.8mV
288ps     506.5mV    827mV      483.6mV
365ps     485mV      621.8mV    475.9mV
938ps     475.4mV    553mV      473.3mV
[Falling waveform]
R_fixture=50.000Ohm
V_fixture=0
0s        1.395V     1.259V     1.499V
68ps      1.409V     1.271V     1.481V
96ps      1.313V     1.266V     1.13V
115ps     1.117V     1.244V     734.3mV
135ps     809.4mV    1.187V     387.3mV
163ps     390.8mV    1.015V     171.9mV
183ps     222.4mV    829mV      119.5mV
240ps     86.82mV    297.1mV    83.04mV
307ps     66.97mV    102.3mV    75.25mV
938ps     59.6mV     57.29mV    72.69mV
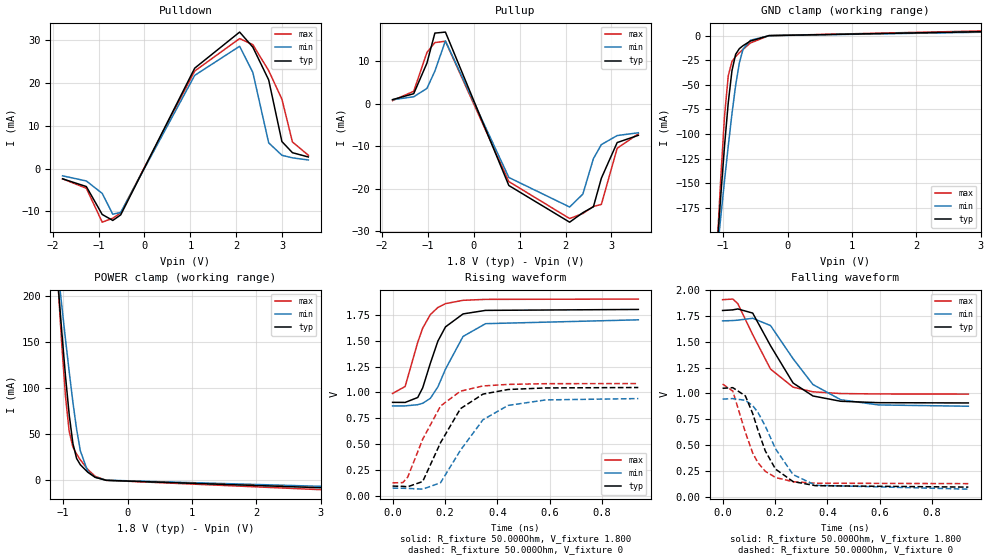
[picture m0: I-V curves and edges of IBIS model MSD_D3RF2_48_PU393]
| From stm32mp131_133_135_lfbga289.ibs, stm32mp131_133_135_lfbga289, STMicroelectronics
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[Model] MSD_D3RF2_48_PU393
Model_type   I/O
C_comp 2.345pF   2.264pF   2.466pF
Vinh = 1.150V
Vinl = 650.000mV
Vmeas = 900.000mV
Vref = 900.000mV
[Model Spec]
Vinh   1.150V   1.100V   1.200V
Vinl   650.000mV   600.000mV   700.000mV
Vmeas   900.000mV   850.000mV   950.000mV
Vref   900.000mV   850.000mV   950.000mV
[Temperature Range]   25.000   125.000   -40.000
[Voltage Range]   1.800V   1.700V   1.900V
[GND Clamp Reference]   0.00V   0.00V   0.00V
[Pulldown Reference]   0.00V   0.00V   0.00V
[POWER Clamp Reference]   1.800V   1.700V   1.900V
[Pullup Reference]   1.800V   1.700V   1.900V
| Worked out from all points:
|   slope of the pulldown table from 0 to 0.27 V, typ, clamps not added: 41 ohm
|   slope of the pullup table from 0 to 0.27 V, typ, clamps not added: 32.3 ohm
|   GND clamp passes 1 mA (typ) near -0.41 V on its own axis
|   POWER clamp passes 1 mA (typ) near -0.41 V on its own axis
|   rising waveform, R_fixture 50.000Ohm, V_fixture 1.800: 20-80 % time 78.8ps typ, 97.9ps min, 71.5ps max; typ from 0.905 V to 1.8 V
|   rising waveform, R_fixture 50.000Ohm, V_fixture 0: 20-80 % time 119ps typ, 143ps min, 111ps max; typ from 0.099 V to 1.05 V
|   falling waveform, R_fixture 50.000Ohm, V_fixture 1.800: 20-80 % time 122ps typ, 147ps min, 113ps max; typ from 1.8 V to 0.909 V
|   falling waveform, R_fixture 50.000Ohm, V_fixture 0: 20-80 % time 89.6ps typ, 110ps min, 80.7ps max; typ from 1.05 V to 0.098 V
[GND Clamp]
-1.785V   -901.6mA   -689mA     -1.21A
-1.094V   -214.8mA   -221mA     -215.5mA
-1.036V   -162mA     -183.8mA   -143.6mA
-978.8mV  -112.3mA   -147.4mA   -82.21mA
-921.2mV  -68.61mA   -112.4mA   -41.12mA
-863.6mV  -35.84mA   -79.69mA   -26.31mA
-806.1mV  -19.09mA   -50.68mA   -21.38mA
-748.5mV  -13.3mA    -27.86mA   -17.56mA
-690.9mV  -10.28mA   -13.84mA   -13.97mA
-575.8mV  -5.56mA    -4.768mA   -7.53mA
-287.9mV  -69.99uA   -117uA     -56.99uA
3.57V     4.61mA     3.97mA     5.507mA
[Power Clamp]
-1.77V    883mA      690.2mA    1.159A
-1.079V   212.6mA    226.6mA    212.4mA
-1.021V   161mA      189.5mA    146.9mA
-963.6mV  113.1mA    153.1mA    91.15mA
-906.1mV  71.31mA    117.9mA    53.09mA
-848.5mV  40.15mA    84.87mA    36.33mA
-790.9mV  23.9mA     55.52mA    28.61mA
-733.3mV  17.07mA    32.3mA     22.42mA
-618.2mV  9.01mA     9.784mA    12.01mA
-503mV    3.446mA    3.544mA    4.486mA
-330.3mV  160.6uA    336.1uA    187.2uA
3.585V    -9.248mA   -7.505mA   -11.75mA
[Pulldown]
-1.785V   -2.4mA     -1.7mA     -2.4mA
-1.267V   -4.2mA     -2.9mA     -4.6mA
-921.2mV  -10.72mA   -5.8mA     -12.52mA
-690.9mV  -12.11mA   -10.66mA   -11.59mA
-518.2mV  -10.81mA   -10.23mA   -10.35mA
1.094V    23.43mA    21.75mA    22.76mA
2.073V    31.85mA    28.54mA    30.34mA
2.361V    28.33mA    22.42mA    28.91mA
2.706V    20.69mA    6mA        22.85mA
2.994V    6.3mA      3.1mA      16.2mA
3.224V    3.7mA      2.5mA      6.2mA
3.57V     2.7mA      2mA        3.1mA
[Pullup]
-1.77V    1mA        973.7uA    773.7uA
-1.309V   2.4mA      1.674mA    2.963mA
-1.021V   9.6mA      3.642mA    12.09mA
-848.5mV  16.65mA    7.7mA      14.42mA
-618.2mV  16.89mA    14.82mA    14.74mA
763.6mV   -19.21mA   -17.32mA   -18.28mA
2.088V    -27.84mA   -24.27mA   -26.98mA
2.376V    -25.6mA    -21.23mA   -25.8mA
2.606V    -24.21mA   -12.89mA   -24.14mA
2.779V    -17.5mA    -9.584mA   -23.66mA
3.124V    -9.1mA     -7.453mA   -10.44mA
3.585V    -7.4mA     -6.8mA     -7.047mA
[Ramp]
R_load=50.000Ohm
dV/dt_r   552.645mV/100.000ps  506.274mV/121.000ps  558.120mV/91.500ps
dV/dt_f   552.645mV/106.500ps  506.274mV/129.500ps  558.120mV/97.500ps
[Rising waveform]
R_fixture=50.000Ohm
V_fixture=1.800
V_fixture_min=1.700
V_fixture_max=1.900
0s        905.1mV    871.1mV    990.6mV
48ps      904.3mV    870.9mV    1.058V
96ps      951.9mV    882.6mV    1.483V
115ps     1.045V     896.2mV    1.62V
144ps     1.28V      943.4mV    1.75V
173ps     1.495V     1.054V     1.819V
202ps     1.632V     1.225V     1.856V
269ps     1.757V     1.54V      1.888V
355ps     1.791V     1.663V     1.897V
938ps     1.8V       1.7V       1.9V
[Rising waveform]
R_fixture=50.000Ohm
V_fixture=0
0s        98.65mV    78.78mV    129.6mV
39ps      95.85mV    77.66mV    132mV
58ps      92.24mV    76.3mV     185.9mV
115ps     142.5mV    68.85mV    550.3mV
183ps     516.2mV    130.6mV    869.3mV
259ps     844mV      443.3mV    1.013V
345ps     984.5mV    737.6mV    1.063V
441ps     1.029V     875.7mV    1.078V
585ps     1.044V     928.7mV    1.085V
938ps     1.048V     941.4mV    1.086V
[Falling waveform]
R_fixture=50.000Ohm
V_fixture=1.800
V_fixture_min=1.700
V_fixture_max=1.900
0s        1.799V     1.699V     1.903V
39ps      1.805V     1.702V     1.909V
58ps      1.814V     1.706V     1.866V
115ps     1.774V     1.724V     1.566V
183ps     1.46V      1.654V     1.235V
269ps     1.101V     1.335V     1.061V
345ps     975.9mV    1.086V     1.016V
451ps     924.9mV    939.7mV    999.3mV
595ps     911.4mV    889.6mV    995.1mV
938ps     908.6mV    877mV      994.3mV
[Falling waveform]
R_fixture=50.000Ohm
V_fixture=0
0s        1.05V      945.5mV    1.091V
39ps      1.056V     950.7mV    1.023V
87ps      976.9mV    934.2mV    626.4mV
115ps     806.7mV    882.7mV    426.3mV
135ps     647.9mV    817.7mV    333.3mV
163ps     447mV      686.2mV    251mV
202ps     271.9mV    467.8mV    191mV
269ps     151.7mV    218.6mV    150.3mV
355ps     112mV      116.2mV    136mV
938ps     98.28mV    78.56mV    131.7mV
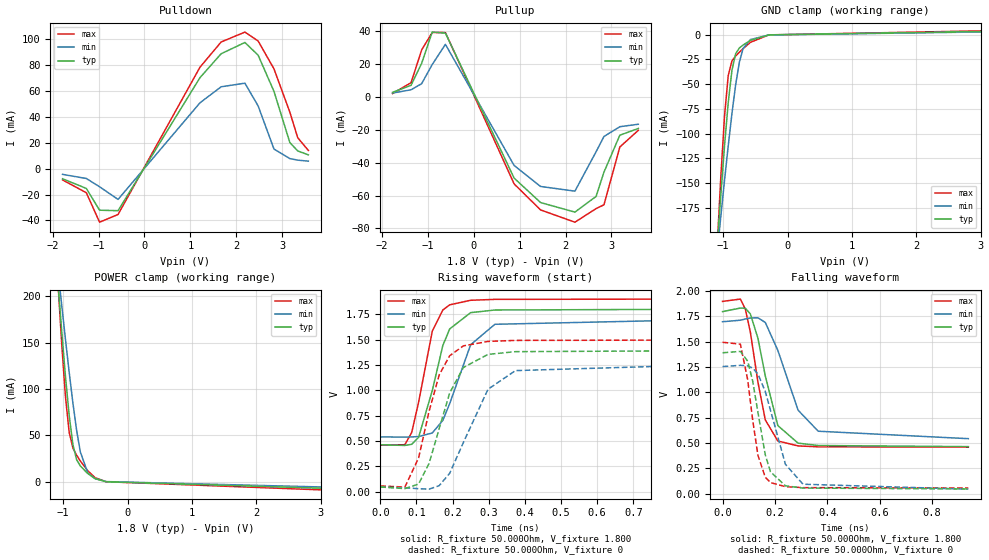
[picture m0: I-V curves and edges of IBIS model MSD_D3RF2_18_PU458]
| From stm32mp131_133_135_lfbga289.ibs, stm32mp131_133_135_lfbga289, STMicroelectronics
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[Model] MSD_D3RF2_18_PU458
Model_type   I/O
C_comp 2.374pF   2.292pF   2.496pF
Vinh = 1.150V
Vinl = 650.000mV
Vmeas = 900.000mV
Vref = 900.000mV
[Model Spec]
Vinh   1.150V   1.100V   1.200V
Vinl   650.000mV   600.000mV   700.000mV
Vmeas   900.000mV   850.000mV   950.000mV
Vref   900.000mV   850.000mV   950.000mV
[Temperature Range]   25.000   125.000   -40.000
[Voltage Range]   1.800V   1.700V   1.900V
[GND Clamp Reference]   0.00V   0.00V   0.00V
[Pulldown Reference]   0.00V   0.00V   0.00V
[POWER Clamp Reference]   1.800V   1.700V   1.900V
[Pullup Reference]   1.800V   1.700V   1.900V
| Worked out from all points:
|   slope of the pulldown table from 0 to 0.27 V, typ, clamps not added: 15.3 ohm
|   slope of the pullup table from 0 to 0.27 V, typ, clamps not added: 14.6 ohm
|   GND clamp passes 1 mA (typ) near -0.40 V on its own axis
|   POWER clamp passes 1 mA (typ) near -0.41 V on its own axis
|   rising waveform, R_fixture 50.000Ohm, V_fixture 1.800: 20-80 % time 55.7ps typ, 71.5ps min, 48.2ps max; typ from 0.462 V to 1.8 V
|   rising waveform, R_fixture 50.000Ohm, V_fixture 0: 20-80 % time 71.9ps typ, 91.3ps min, 63.1ps max; typ from 0.046 V to 1.39 V
|   falling waveform, R_fixture 50.000Ohm, V_fixture 1.800: 20-80 % time 66.4ps typ, 94.1ps min, 56.2ps max; typ from 1.8 V to 0.464 V
|   falling waveform, R_fixture 50.000Ohm, V_fixture 0: 20-80 % time 55.9ps typ, 78ps min, 47.1ps max; typ from 1.39 V to 0.045 V
[GND Clamp]
-1.785V   -902.1mA   -689.3mA   -1.211A
-1.094V   -215mA     -221.2mA   -215.8mA
-1.036V   -162.1mA   -183.9mA   -143.7mA
-978.8mV  -112.5mA   -147.5mA   -82.43mA
-921.2mV  -68.76mA   -112.6mA   -41.32mA
-863.6mV  -35.98mA   -79.81mA   -26.48mA
-806.1mV  -19.2mA    -50.78mA   -21.53mA
-748.5mV  -13.39mA   -27.95mA   -17.68mA
-690.9mV  -10.36mA   -13.92mA   -14.07mA
-575.8mV  -5.615mA   -4.814mA   -7.598mA
-287.9mV  -70.99uA   -120uA     -56.99uA
3.57V     3.952mA    3.403mA    4.721mA
[Power Clamp]
-1.77V    883.4mA    690.7mA    1.16A
-1.079V   212.8mA    226.9mA    212.7mA
-1.021V   161.2mA    189.6mA    147.2mA
-963.6mV  113.2mA    153.2mA    91.32mA
-906.1mV  71.46mA    118mA      53.29mA
-848.5mV  40.28mA    85mA       36.5mA
-790.9mV  24.01mA    55.62mA    28.77mA
-733.3mV  17.16mA    32.39mA    22.55mA
-618.2mV  9.07mA     9.843mA    12.09mA
-503mV    3.48mA     3.576mA    4.528mA
-330.3mV  164.3uA    342.2uA    191.7uA
3.585V    -7.932mA   -6.431mA   -10.07mA
[Pulldown]
-1.785V   -7.8mA     -4.4mA     -8.7mA
-1.267V   -15.3mA    -7.6mA     -18.6mA
-978.8mV  -32.1mA    -14mA      -41.38mA
-575.8mV  -32.49mA   -23.76mA   -35.4mA
1.209V    70.38mA    50.93mA    78.43mA
1.67V     88.85mA    63.31mA    97.95mA
2.188V    97.57mA    66.1mA     105.6mA
2.476V    87.74mA    48.5mA     98.73mA
2.821V    59.8mA     15.2mA     77.18mA
3.167V    20.2mA     7.8mA      43.7mA
3.339V    13.7mA     6.6mA      23.9mA
3.57V     10.7mA     5.8mA      14.1mA
[Pullup]
-1.77V    2.9mA      2.474mA    2.153mA
-1.367V   7.2mA      4.468mA    8.789mA
-1.136V   20.6mA     8.205mA    28.74mA
-906.1mV  39.62mA    19.85mA    39.38mA
-618.2mV  38.99mA    32.14mA    39.32mA
878.8mV   -49.37mA   -41.66mA   -52.88mA
1.455V    -64.25mA   -54.44mA   -68.74mA
2.203V    -70.07mA   -57.29mA   -76.21mA
2.664V    -60.52mA   -33.33mA   -67.93mA
2.836V    -45.7mA    -23.98mA   -65.61mA
3.182V    -23.2mA    -18.03mA   -30.38mA
3.585V    -19.1mA    -16.53mA   -20.22mA
[Ramp]
R_load=50.000Ohm
dV/dt_r   804.708mV/65.000ps  710.673mV/82.000ps  864.573mV/56.500ps
dV/dt_f   804.708mV/61.500ps  710.673mV/87.000ps  864.573mV/51.500ps
[Rising waveform]
R_fixture=50.000Ohm
V_fixture=1.800
V_fixture_min=1.700
V_fixture_max=1.900
0s        462.4mV    539.3mV    458.2mV
68ps      455.4mV    538.1mV    462.5mV
87ps      467mV      539.4mV    583.5mV
106ps     535.4mV    543.2mV    881mV
144ps     998.7mV    578.6mV    1.585V
173ps     1.441V     702.6mV    1.792V
192ps     1.605V     867.6mV    1.843V
250ps     1.766V     1.449V     1.888V
317ps     1.792V     1.651V     1.897V
938ps     1.8V       1.7V       1.9V
[Rising waveform]
R_fixture=50.000Ohm
V_fixture=0
0s        45.88mV    43.99mV    55.86mV
68ps      29.51mV    38.24mV    44.84mV
106ps     74.43mV    28.62mV    331.2mV
135ps     277.8mV    23.93mV    791.6mV
163ps     621.7mV    58.5mV     1.151V
192ps     973.1mV    180.5mV    1.341V
230ps     1.225V     484.9mV    1.438V
298ps     1.354V     1.01V      1.482V
374ps     1.381V     1.194V     1.492V
938ps     1.391V     1.254V     1.496V
[Falling waveform]
R_fixture=50.000Ohm
V_fixture=1.800
V_fixture_min=1.700
V_fixture_max=1.900
0s        1.798V     1.698V     1.899V
68ps      1.833V     1.713V     1.922V
87ps      1.831V     1.725V     1.821V
106ps     1.775V     1.735V     1.597V
135ps     1.535V     1.737V     1.101V
163ps     1.164V     1.691V     728mV
211ps     671.5mV    1.415V     519.4mV
288ps     498.4mV    824.7mV    470.9mV
365ps     474.7mV    615.9mV    461.8mV
938ps     463.7mV    542.4mV    458.6mV
[Falling waveform]
R_fixture=50.000Ohm
V_fixture=0
0s        1.391V     1.255V     1.495V
68ps      1.405V     1.267V     1.476V
96ps      1.308V     1.262V     1.123V
115ps     1.111V     1.24V      725.8mV
135ps     802.2mV    1.182V     378.3mV
163ps     382.8mV    1.009V     161mV
183ps     214.4mV    821.7mV    108.1mV
240ps     76.28mV    288.5mV    67.94mV
307ps     54.17mV    92.26mV    58.44mV
938ps     45.05mV    43.31mV    54.99mV
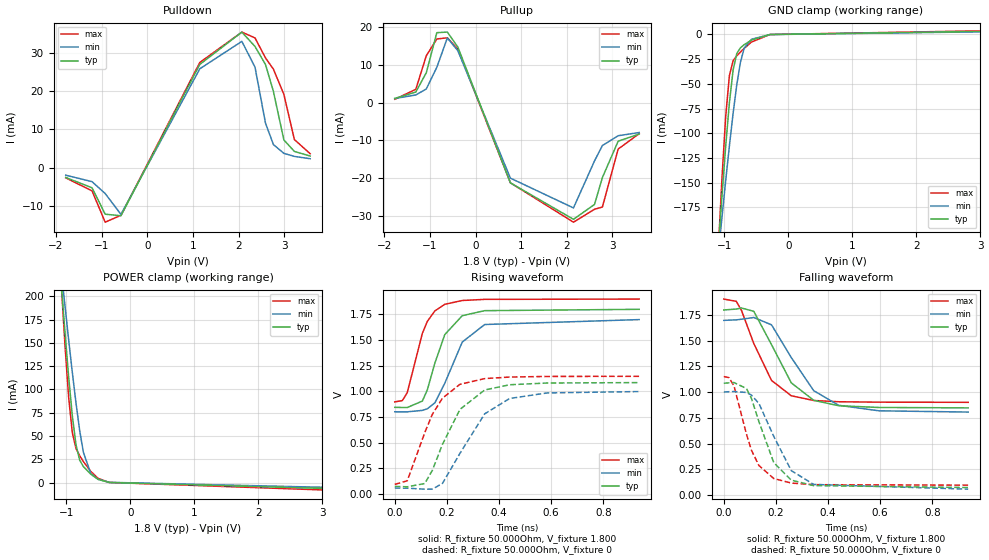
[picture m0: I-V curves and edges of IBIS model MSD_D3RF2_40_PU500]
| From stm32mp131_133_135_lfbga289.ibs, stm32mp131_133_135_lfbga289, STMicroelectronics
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[Model] MSD_D3RF2_40_PU500
Model_type   I/O
C_comp 2.391pF   2.309pF   2.512pF
Vinh = 1.150V
Vinl = 650.000mV
Vmeas = 900.000mV
Vref = 900.000mV
[Model Spec]
Vinh   1.150V   1.100V   1.200V
Vinl   650.000mV   600.000mV   700.000mV
Vmeas   900.000mV   850.000mV   950.000mV
Vref   900.000mV   850.000mV   950.000mV
[Temperature Range]   25.000   125.000   -40.000
[Voltage Range]   1.800V   1.700V   1.900V
[GND Clamp Reference]   0.00V   0.00V   0.00V
[Pulldown Reference]   0.00V   0.00V   0.00V
[POWER Clamp Reference]   1.800V   1.700V   1.900V
[Pullup Reference]   1.800V   1.700V   1.900V
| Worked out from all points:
|   slope of the pulldown table from 0 to 0.27 V, typ, clamps not added: 37.2 ohm
|   slope of the pullup table from 0 to 0.27 V, typ, clamps not added: 29.4 ohm
|   GND clamp passes 1 mA (typ) near -0.40 V on its own axis
|   POWER clamp passes 1 mA (typ) near -0.41 V on its own axis
|   rising waveform, R_fixture 50.000Ohm, V_fixture 1.800: 20-80 % time 76.7ps typ, 94.6ps min, 68.5ps max; typ from 0.845 V to 1.8 V
|   rising waveform, R_fixture 50.000Ohm, V_fixture 0: 20-80 % time 117ps typ, 136ps min, 106ps max; typ from 0.075 V to 1.09 V
|   falling waveform, R_fixture 50.000Ohm, V_fixture 1.800: 20-80 % time 119ps typ, 139ps min, 105ps max; typ from 1.8 V to 0.848 V
|   falling waveform, R_fixture 50.000Ohm, V_fixture 0: 20-80 % time 87.6ps typ, 104ps min, 76.6ps max; typ from 1.09 V to 0.074 V
[GND Clamp]
-1.785V   -902.2mA   -689.6mA   -1.211A
-1.094V   -215.1mA   -221.3mA   -215.9mA
-1.036V   -162.2mA   -184mA     -143.9mA
-978.8mV  -112.6mA   -147.6mA   -82.55mA
-921.2mV  -68.85mA   -112.6mA   -41.42mA
-863.6mV  -36.04mA   -79.87mA   -26.57mA
-806.1mV  -19.26mA   -50.83mA   -21.61mA
-748.5mV  -13.45mA   -27.99mA   -17.76mA
-690.9mV  -10.4mA    -13.95mA   -14.13mA
-575.8mV  -5.644mA   -4.836mA   -7.63mA
-287.9mV  -71.99uA   -121uA     -59.99uA
3.57V     3.622mA    3.119mA    4.327mA
[Power Clamp]
-1.77V    883.7mA    690.8mA    1.16A
-1.079V   212.9mA    226.9mA    212.8mA
-1.021V   161.4mA    189.7mA    147.3mA
-963.6mV  113.3mA    153.2mA    91.44mA
-906.1mV  71.54mA    118.1mA    53.38mA
-848.5mV  40.35mA    85.05mA    36.59mA
-790.9mV  24.07mA    55.67mA    28.84mA
-733.3mV  17.21mA    32.43mA    22.61mA
-618.2mV  9.105mA    9.871mA    12.13mA
-503mV    3.496mA    3.593mA    4.55mA
-330.3mV  166.1uA    345.1uA    193.6uA
3.585V    -7.27mA    -5.895mA   -9.227mA
[Pulldown]
-1.785V   -2.6mA     -2mA       -2.7mA
-1.209V   -5.3mA     -3.7mA     -6.1mA
-921.2mV  -12.19mA   -6.8mA     -14.28mA
-575.8mV  -12.6mA    -12.24mA   -12.47mA
1.152V    26.93mA    25.78mA    27.43mA
2.073V    35.36mA    32.95mA    35.37mA
2.361V    31.62mA    26.22mA    33.85mA
2.591V    26.91mA    11.6mA     28.62mA
2.764V    19.9mA     6mA        25.7mA
2.994V    7.2mA      3.7mA      19.1mA
3.224V    4.2mA      2.9mA      7.3mA
3.57V     3mA        2.3mA      3.6mA
[Pullup]
-1.77V    1.1mA      1.074mA    873.7uA
-1.309V   2.8mA      2.021mA    3.516mA
-1.079V   7.9mA      3.616mA    12.4mA
-848.5mV  18.49mA    9.339mA    16.82mA
-618.2mV  18.64mA    17.11mA    17.13mA
-387.9mV  14.68mA    13.71mA    14.14mA
763.6mV   -21.21mA   -19.96mA   -21.19mA
2.145V    -30.84mA   -27.83mA   -31.6mA
2.606V    -26.91mA   -15.41mA   -28.18mA
2.779V    -19.8mA    -11.34mA   -27.59mA
3.124V    -10.2mA    -8.753mA   -12.28mA
3.585V    -8.3mA     -7.9mA     -8.2mA
[Ramp]
R_load=50.000Ohm
dV/dt_r   589.380mV/97.500ps  550.491mV/116.000ps  614.469mV/88.000ps
dV/dt_f   589.380mV/104.000ps  550.491mV/122.500ps  614.469mV/91.000ps
[Rising waveform]
R_fixture=50.000Ohm
V_fixture=1.800
V_fixture_min=1.700
V_fixture_max=1.900
0s        845.1mV    801.7mV    897.9mV
29ps      843.5mV    800.8mV    910.6mV
48ps      843.4mV    801.1mV    988.8mV
106ps     906.2mV    815.4mV    1.567V
125ps     1.016V     831mV      1.683V
154ps     1.277V     889.2mV    1.785V
192ps     1.554V     1.08V      1.849V
259ps     1.738V     1.481V     1.886V
345ps     1.787V     1.652V     1.897V
938ps     1.8V       1.7V       1.9V
[Rising waveform]
R_fixture=50.000Ohm
V_fixture=0
0s        74.51mV    58.55mV    94.15mV
48ps      70.66mV    56.95mV    129.3mV
115ps     102.7mV    47.56mV    597.3mV
144ps     229.5mV    47.92mV    775.7mV
183ps     483.6mV    103.1mV    934.7mV
250ps     824.8mV    395.8mV    1.069V
345ps     1.014V     781.5mV    1.125V
441ps     1.065V     931.4mV    1.14V
585ps     1.082V     985.4mV    1.146V
938ps     1.086V     998.8mV    1.147V
[Falling waveform]
R_fixture=50.000Ohm
V_fixture=1.800
V_fixture_min=1.700
V_fixture_max=1.900
0s        1.799V     1.698V     1.905V
48ps      1.808V     1.703V     1.883V
68ps      1.818V     1.709V     1.794V
115ps     1.786V     1.726V     1.474V
183ps     1.463V     1.655V     1.115V
259ps     1.091V     1.337V     965.7mV
345ps     921.6mV    1.015V     919.7mV
441ps     868.6mV    872.8mV    907.5mV
595ps     851.9mV    819.5mV    903.3mV
938ps     847.9mV    807.2mV    901.9mV
[Falling waveform]
R_fixture=50.000Ohm
V_fixture=0
0s        1.087V     1.002V     1.153V
20ps      1.091V     1.005V     1.141V
39ps      1.094V     1.007V     1.062V
87ps      1.036V     997.4mV    592mV
106ps     940.6mV    972.3mV    436.6mV
135ps     712.4mV    890.3mV    287.2mV
192ps     314.8mV    569.8mV    161.5mV
259ps     145.8mV    238.5mV    117.2mV
345ps     92.5mV     104mV      101.8mV
938ps     74.02mV    58.19mV    97.08mV
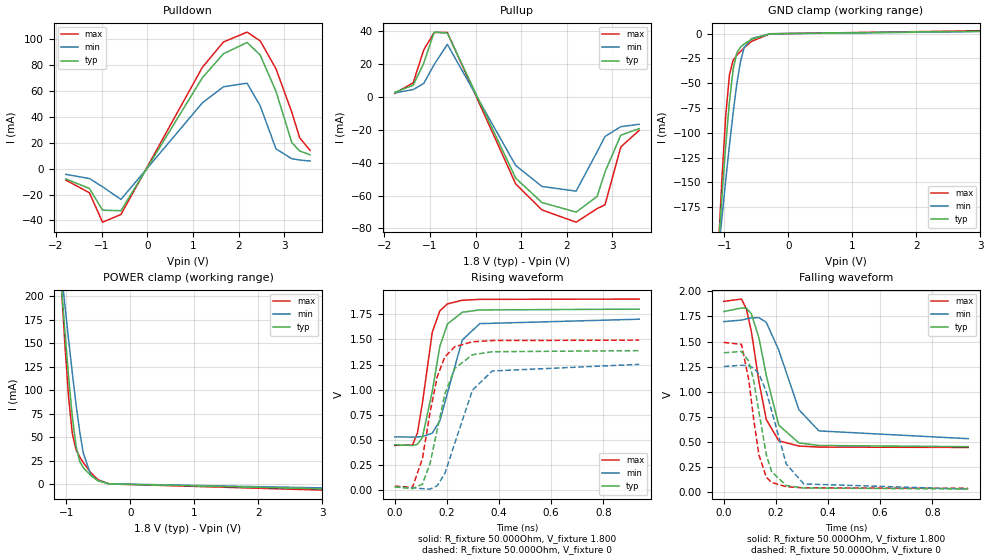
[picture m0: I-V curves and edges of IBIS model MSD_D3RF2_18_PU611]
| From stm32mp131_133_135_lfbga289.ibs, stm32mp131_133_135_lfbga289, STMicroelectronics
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[Model] MSD_D3RF2_18_PU611
Model_type   I/O
C_comp 2.420pF   2.338pF   2.542pF
Vinh = 1.150V
Vinl = 650.000mV
Vmeas = 900.000mV
Vref = 900.000mV
[Model Spec]
Vinh   1.150V   1.100V   1.200V
Vinl   650.000mV   600.000mV   700.000mV
Vmeas   900.000mV   850.000mV   950.000mV
Vref   900.000mV   850.000mV   950.000mV
[Temperature Range]   25.000   125.000   -40.000
[Voltage Range]   1.800V   1.700V   1.900V
[GND Clamp Reference]   0.00V   0.00V   0.00V
[Pulldown Reference]   0.00V   0.00V   0.00V
[POWER Clamp Reference]   1.800V   1.700V   1.900V
[Pullup Reference]   1.800V   1.700V   1.900V
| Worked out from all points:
|   slope of the pulldown table from 0 to 0.27 V, typ, clamps not added: 15.3 ohm
|   slope of the pullup table from 0 to 0.27 V, typ, clamps not added: 14.6 ohm
|   GND clamp passes 1 mA (typ) near -0.40 V on its own axis
|   POWER clamp passes 1 mA (typ) near -0.41 V on its own axis
|   rising waveform, R_fixture 50.000Ohm, V_fixture 1.800: 20-80 % time 56.2ps typ, 72.1ps min, 48.9ps max; typ from 0.454 V to 1.8 V
|   rising waveform, R_fixture 50.000Ohm, V_fixture 0: 20-80 % time 73.2ps typ, 92.9ps min, 64.2ps max; typ from 0.035 V to 1.39 V
|   falling waveform, R_fixture 50.000Ohm, V_fixture 1.800: 20-80 % time 67ps typ, 95ps min, 56.7ps max; typ from 1.8 V to 0.455 V
|   falling waveform, R_fixture 50.000Ohm, V_fixture 0: 20-80 % time 56.2ps typ, 78.5ps min, 47.5ps max; typ from 1.39 V to 0.034 V
[GND Clamp]
-1.785V   -902.7mA   -689.9mA   -1.212A
-1.094V   -215.4mA   -221.4mA   -216.2mA
-1.036V   -162.5mA   -184.1mA   -144.1mA
-978.8mV  -112.8mA   -147.7mA   -82.76mA
-921.2mV  -69mA      -112.8mA   -41.61mA
-863.6mV  -36.18mA   -79.97mA   -26.74mA
-806.1mV  -19.38mA   -50.93mA   -21.76mA
-748.5mV  -13.55mA   -28.08mA   -17.89mA
-690.9mV  -10.49mA   -14.02mA   -14.25mA
-575.8mV  -5.695mA   -4.879mA   -7.699mA
-287.9mV  -74.99uA   -123uA     -60.99uA
3.57V     2.964mA    2.553mA    3.541mA
[Power Clamp]
-1.77V    884.1mA    691.2mA    1.161A
-1.079V   213.1mA    227.1mA    213mA
-1.021V   161.6mA    189.9mA    147.5mA
-963.6mV  113.5mA    153.4mA    91.69mA
-906.1mV  71.69mA    118.2mA    53.58mA
-848.5mV  40.49mA    85.18mA    36.76mA
-790.9mV  24.18mA    55.77mA    28.99mA
-733.3mV  17.31mA    32.52mA    22.74mA
-618.2mV  9.175mA    9.93mA     12.21mA
-503mV    3.531mA    3.626mA    4.592mA
-330.3mV  169.7uA    350.8uA    198.1uA
3.585V    -5.947mA   -4.827mA   -7.552mA
[Pulldown]
-1.785V   -7.9mA     -4.4mA     -8.8mA
-1.267V   -15.3mA    -7.6mA     -18.6mA
-978.8mV  -32.1mA    -14mA      -41.37mA
-575.8mV  -32.5mA    -23.76mA   -35.41mA
1.209V    70.38mA    50.93mA    78.43mA
1.67V     88.85mA    63.32mA    97.95mA
2.188V    97.57mA    66.1mA     105.6mA
2.476V    87.8mA     48.51mA    98.74mA
2.821V    59.8mA     15.3mA     77.23mA
3.167V    20.2mA     7.7mA      43.7mA
3.339V    13.7mA     6.7mA      23.9mA
3.57V     10.7mA     5.9mA      14.1mA
[Pullup]
-1.77V    2.9mA      2.574mA    2.179mA
-1.367V   7.2mA      4.568mA    8.716mA
-1.136V   20.6mA     8.279mA    28.69mA
-906.1mV  39.59mA    19.85mA    39.37mA
-618.2mV  38.98mA    32.14mA    39.33mA
878.8mV   -49.37mA   -41.65mA   -52.89mA
1.455V    -64.25mA   -54.44mA   -68.74mA
2.203V    -70.07mA   -57.29mA   -76.21mA
2.664V    -60.5mA    -33.33mA   -67.93mA
2.836V    -45.6mA    -23.98mA   -65.6mA
3.182V    -23.2mA    -18.03mA   -30.38mA
3.585V    -19.2mA    -16.55mA   -20.27mA
[Ramp]
R_load=50.000Ohm
dV/dt_r   809.829mV/65.000ps  715.395mV/83.000ps  870.957mV/57.000ps
dV/dt_f   809.829mV/62.500ps  715.395mV/87.500ps  870.957mV/52.500ps
[Rising waveform]
R_fixture=50.000Ohm
V_fixture=1.800
V_fixture_min=1.700
V_fixture_max=1.900
0s        453.5mV    531.3mV    447mV
68ps      446.3mV    530mV      450.7mV
87ps      457.5mV    531.2mV    570.7mV
106ps     525.4mV    534.8mV    865.3mV
144ps     985.2mV    569.5mV    1.572V
173ps     1.43V      692mV      1.783V
202ps     1.652V     964.2mV    1.852V
259ps     1.769V     1.493V     1.888V
326ps     1.792V     1.656V     1.897V
938ps     1.8V       1.7V       1.9V
[Rising waveform]
R_fixture=50.000Ohm
V_fixture=0
0s        34.86mV    33.41mV    42.41mV
68ps      18.27mV    27.59mV    30.99mV
106ps     62.45mV    17.71mV    314mV
135ps     263.6mV    12.6mV     767.9mV
163ps     603.5mV    46.48mV    1.13V
192ps     954.7mV    167mV      1.324V
230ps     1.21V      467.8mV    1.427V
298ps     1.347V     995.3mV    1.476V
374ps     1.377V     1.186V     1.488V
938ps     1.388V     1.252V     1.492V
[Falling waveform]
R_fixture=50.000Ohm
V_fixture=1.800
V_fixture_min=1.700
V_fixture_max=1.900
0s        1.798V     1.698V     1.899V
68ps      1.833V     1.713V     1.922V
87ps      1.831V     1.725V     1.821V
106ps     1.775V     1.735V     1.597V
135ps     1.535V     1.737V     1.1V
163ps     1.163V     1.691V     725.3mV
211ps     669mV      1.415V     513.1mV
288ps     492.5mV    823.1mV    461.3mV
365ps     467mV      611.6mV    451.1mV
938ps     454.7mV    534.4mV    447.4mV
[Falling waveform]
R_fixture=50.000Ohm
V_fixture=0
0s        1.388V     1.252V     1.491V
68ps      1.401V     1.264V     1.472V
96ps      1.305V     1.259V     1.118V
115ps     1.107V     1.236V     719.3mV
135ps     796.8mV    1.178V     371.5mV
163ps     377mV      1.004V     153.3mV
183ps     208.3mV    816.2mV    99.29mV
240ps     68.4mV     282mV      56.62mV
307ps     44.58mV    84.64mV    45.76mV
938ps     33.97mV    32.68mV    41.51mV
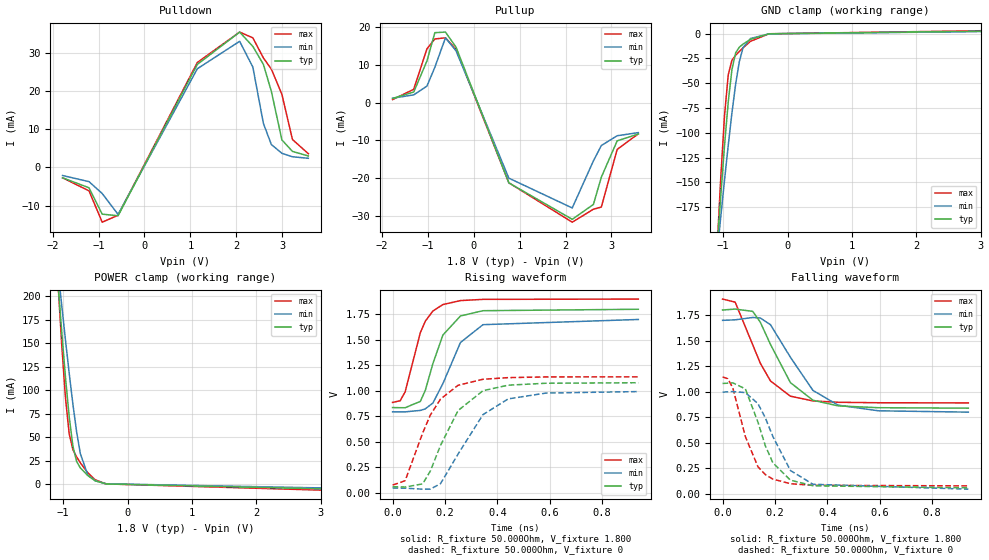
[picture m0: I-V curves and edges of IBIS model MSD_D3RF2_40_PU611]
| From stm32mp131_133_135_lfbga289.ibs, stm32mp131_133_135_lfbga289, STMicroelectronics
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[Model] MSD_D3RF2_40_PU611
Model_type   I/O
C_comp 2.420pF   2.338pF   2.542pF
Vinh = 1.150V
Vinl = 650.000mV
Vmeas = 900.000mV
Vref = 900.000mV
[Model Spec]
Vinh   1.150V   1.100V   1.200V
Vinl   650.000mV   600.000mV   700.000mV
Vmeas   900.000mV   850.000mV   950.000mV
Vref   900.000mV   850.000mV   950.000mV
[Temperature Range]   25.000   125.000   -40.000
[Voltage Range]   1.800V   1.700V   1.900V
[GND Clamp Reference]   0.00V   0.00V   0.00V
[Pulldown Reference]   0.00V   0.00V   0.00V
[POWER Clamp Reference]   1.800V   1.700V   1.900V
[Pullup Reference]   1.800V   1.700V   1.900V
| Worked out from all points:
|   slope of the pulldown table from 0 to 0.27 V, typ, clamps not added: 37.2 ohm
|   slope of the pullup table from 0 to 0.27 V, typ, clamps not added: 29.4 ohm
|   GND clamp passes 1 mA (typ) near -0.40 V on its own axis
|   POWER clamp passes 1 mA (typ) near -0.41 V on its own axis
|   rising waveform, R_fixture 50.000Ohm, V_fixture 1.800: 20-80 % time 77.6ps typ, 95.6ps min, 69.6ps max; typ from 0.837 V to 1.8 V
|   rising waveform, R_fixture 50.000Ohm, V_fixture 0: 20-80 % time 120ps typ, 139ps min, 109ps max; typ from 0.061 V to 1.08 V
|   falling waveform, R_fixture 50.000Ohm, V_fixture 1.800: 20-80 % time 120ps typ, 140ps min, 106ps max; typ from 1.8 V to 0.84 V
|   falling waveform, R_fixture 50.000Ohm, V_fixture 0: 20-80 % time 88.4ps typ, 105ps min, 77.3ps max; typ from 1.08 V to 0.061 V
[GND Clamp]
-1.785V   -902.7mA   -689.9mA   -1.212A
-1.094V   -215.4mA   -221.4mA   -216.2mA
-1.036V   -162.5mA   -184.1mA   -144.1mA
-978.8mV  -112.8mA   -147.7mA   -82.76mA
-921.2mV  -69mA      -112.8mA   -41.61mA
-863.6mV  -36.18mA   -79.97mA   -26.74mA
-806.1mV  -19.38mA   -50.93mA   -21.76mA
-748.5mV  -13.55mA   -28.08mA   -17.89mA
-690.9mV  -10.49mA   -14.02mA   -14.25mA
-575.8mV  -5.695mA   -4.879mA   -7.699mA
-287.9mV  -74.99uA   -123uA     -60.99uA
3.57V     2.964mA    2.553mA    3.541mA
[Power Clamp]
-1.77V    884.1mA    691.2mA    1.161A
-1.079V   213.1mA    227.1mA    213mA
-1.021V   161.6mA    189.9mA    147.5mA
-963.6mV  113.5mA    153.4mA    91.69mA
-906.1mV  71.69mA    118.2mA    53.58mA
-848.5mV  40.49mA    85.18mA    36.76mA
-790.9mV  24.18mA    55.77mA    28.99mA
-733.3mV  17.31mA    32.52mA    22.74mA
-618.2mV  9.175mA    9.93mA     12.21mA
-503mV    3.531mA    3.626mA    4.592mA
-330.3mV  169.7uA    350.8uA    198.1uA
3.585V    -5.947mA   -4.827mA   -7.552mA
[Pulldown]
-1.785V   -2.7mA     -2.1mA     -2.7mA
-1.209V   -5.3mA     -3.7mA     -6.1mA
-921.2mV  -12.19mA   -6.8mA     -14.29mA
-575.8mV  -12.61mA   -12.25mA   -12.47mA
1.152V    26.93mA    25.79mA    27.43mA
2.073V    35.36mA    32.95mA    35.36mA
2.361V    31.62mA    26.22mA    33.86mA
2.591V    26.91mA    11.5mA     28.61mA
2.764V    19.9mA     6mA        25.7mA
2.994V    7.2mA      3.7mA      19.1mA
3.224V    4.2mA      2.8mA      7.3mA
3.57V     3mA        2.4mA      3.6mA
[Pullup]
-1.77V    1.1mA      1.174mA    800uA
-1.309V   2.8mA      2.047mA    3.516mA
-1.021V   11mA       4.363mA    14.22mA
-848.5mV  18.49mA    9.339mA    16.82mA
-618.2mV  18.64mA    17.11mA    17.13mA
-387.9mV  14.68mA    13.71mA    14.13mA
763.6mV   -21.21mA   -19.96mA   -21.19mA
2.145V    -30.84mA   -27.84mA   -31.6mA
2.606V    -26.91mA   -15.4mA    -28.17mA
2.779V    -19.7mA    -11.34mA   -27.6mA
3.124V    -10.1mA    -8.753mA   -12.36mA
3.585V    -8.3mA     -7.926mA   -8.247mA
[Ramp]
R_load=50.000Ohm
dV/dt_r   593.835mV/99.500ps  553.971mV/118.000ps  620.223mV/90.000ps
dV/dt_f   593.835mV/105.500ps  553.971mV/122.500ps  620.223mV/91.500ps
[Rising waveform]
R_fixture=50.000Ohm
V_fixture=1.800
V_fixture_min=1.700
V_fixture_max=1.900
0s        836.9mV    795.3mV    887mV
29ps      835.3mV    794.4mV    903.5mV
48ps      835.2mV    794.7mV    990.7mV
106ps     897mV      808.7mV    1.571V
125ps     1.006V     824.1mV    1.683V
154ps     1.268V     881.6mV    1.783V
192ps     1.547V     1.071V     1.846V
259ps     1.734V     1.474V     1.885V
345ps     1.786V     1.649V     1.897V
938ps     1.8V       1.7V       1.9V
[Rising waveform]
R_fixture=50.000Ohm
V_fixture=0
0s        61.49mV    48.29mV    76.73mV
48ps      57.63mV    46.68mV    119.6mV
115ps     88.94mV    37.02mV    588mV
144ps     214.3mV    37.03mV    762.2mV
183ps     465.5mV    91.26mV    920mV
250ps     807.1mV    380.7mV    1.055V
345ps     1.002V     767.3mV    1.114V
441ps     1.056V     921.5mV    1.13V
585ps     1.075V     978.7mV    1.137V
938ps     1.08V      993.5mV    1.138V
[Falling waveform]
R_fixture=50.000Ohm
V_fixture=1.800
V_fixture_min=1.700
V_fixture_max=1.900
0s        1.799V     1.698V     1.906V
48ps      1.808V     1.703V     1.876V
115ps     1.786V     1.726V     1.46V
144ps     1.68V      1.721V     1.279V
183ps     1.462V     1.655V     1.105V
259ps     1.089V     1.337V     956.8mV
345ps     916.9mV    1.013V     910.2mV
441ps     861.9mV    869mV      897.1mV
595ps     844.1mV    813.9mV    892.5mV
938ps     839.6mV    800.8mV    891mV
[Falling waveform]
R_fixture=50.000Ohm
V_fixture=0
0s        1.081V     996.6mV    1.145V
20ps      1.084V     999.4mV    1.127V
39ps      1.087V     1.002V     1.039V
87ps      1.028V     992mV      561.5mV
135ps     703.5mV    883.8mV    267.3mV
163ps     473.7mV    746.4mV    190.7mV
192ps     305.8mV    562mV      146.1mV
259ps     135.8mV    230.7mV    101.3mV
345ps     80.93mV    95.64mV    85.29mV
938ps     60.98mV    47.9mV     80.07mV
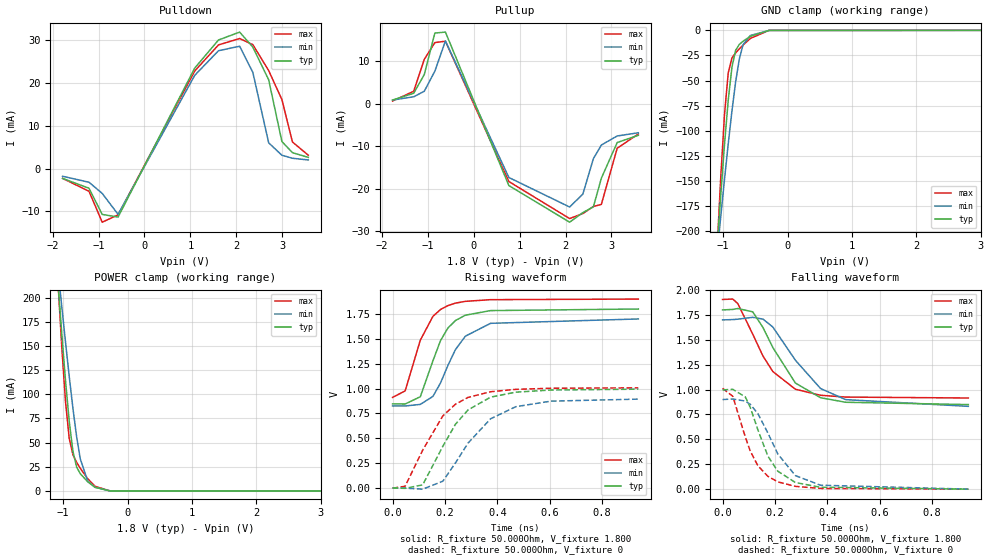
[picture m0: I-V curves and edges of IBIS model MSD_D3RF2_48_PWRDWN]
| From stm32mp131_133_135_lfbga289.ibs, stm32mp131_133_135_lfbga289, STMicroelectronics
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[Model] MSD_D3RF2_48_PWRDWN
Model_type   I/O
C_comp 2.550pF   2.465pF   2.675pF
Vinh = 1.150V
Vinl = 650.000mV
Vmeas = 900.000mV
Vref = 900.000mV
[Model Spec]
Vinh   1.150V   1.100V   1.200V
Vinl   650.000mV   600.000mV   700.000mV
Vmeas   900.000mV   850.000mV   950.000mV
Vref   900.000mV   850.000mV   950.000mV
[Temperature Range]   25.000   125.000   -40.000
[Voltage Range]   1.800V   1.700V   1.900V
[GND Clamp Reference]   0.00V   0.00V   0.00V
[Pulldown Reference]   0.00V   0.00V   0.00V
[POWER Clamp Reference]   1.800V   1.700V   1.900V
[Pullup Reference]   1.800V   1.700V   1.900V
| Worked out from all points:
|   slope of the pulldown table from 0 to 0.27 V, typ, clamps not added: 41 ohm
|   slope of the pullup table from 0 to 0.27 V, typ, clamps not added: 32.3 ohm
|   GND clamp passes 1 mA (typ) near -0.40 V on its own axis
|   POWER clamp passes 1 mA (typ) near -0.40 V on its own axis
|   rising waveform, R_fixture 50.000Ohm, V_fixture 1.800: 20-80 % time 85.9ps typ, 105ps min, 81.1ps max; typ from 0.846 V to 1.8 V
|   rising waveform, R_fixture 50.000Ohm, V_fixture 0: 20-80 % time 139ps typ, 162ps min, 136ps max; typ from 0.001 V to 0.994 V
|   falling waveform, R_fixture 50.000Ohm, V_fixture 1.800: 20-80 % time 132ps typ, 157ps min, 125ps max; typ from 1.8 V to 0.849 V
|   falling waveform, R_fixture 50.000Ohm, V_fixture 0: 20-80 % time 95.6ps typ, 115ps min, 88.4ps max; typ from 0.996 V to 0 V
[GND Clamp]
-1.785V   -904.7mA   -691.7mA   -1.214A
-1.094V   -216.3mA   -222.2mA   -217.4mA
-1.036V   -163.3mA   -184.8mA   -145.2mA
-978.8mV  -113.5mA   -148.4mA   -83.76mA
-921.2mV  -69.69mA   -113.3mA   -42.51mA
-863.6mV  -36.79mA   -80.49mA   -27.53mA
-806.1mV  -19.91mA   -51.37mA   -22.45mA
-748.5mV  -14mA      -28.45mA   -18.47mA
-690.9mV  -10.87mA   -14.34mA   -14.73mA
-575.8mV  -5.929mA   -5.08mA    -8.007mA
-287.9mV  -82.85uA   -135.6uA   -69.2uA
3.57V     41.7nA     685.7nA    4.362nA
[Power Clamp]
-1.77V    886.2mA    693mA      1.163A
-1.079V   214.1mA    227.9mA    214.3mA
-1.021V   162.4mA    190.6mA    148.6mA
-963.6mV  114.3mA    154.1mA    92.64mA
-906.1mV  72.38mA    118.8mA    54.46mA
-848.5mV  41.09mA    85.68mA    37.53mA
-790.9mV  24.71mA    56.22mA    29.66mA
-733.3mV  17.76mA    32.9mA     23.31mA
-618.2mV  9.462mA    10.19mA    12.58mA
-503mV    3.682mA    3.772mA    4.784mA
-272.7mV  36.6uA     118.7uA    36.53uA
3.585V    -62.58nA   -1.1uA     -6.985nA
[Pulldown]
-1.785V   -2.3mA     -1.8mA     -2.3mA
-1.209V   -4.6mA     -3.2mA     -5.3mA
-921.2mV  -10.71mA   -5.8mA     -12.52mA
-575.8mV  -11.32mA   -10.69mA   -10.82mA
1.094V    23.43mA    21.74mA    22.76mA
1.612V    29.99mA    27.49mA    28.84mA
2.073V    31.84mA    28.54mA    30.34mA
2.361V    28.33mA    22.42mA    28.91mA
2.706V    20.7mA     6mA        22.85mA
2.994V    6.3mA      3.1mA      16.1mA
3.224V    3.7mA      2.4mA      6.2mA
3.57V     2.6mA      2mA        3.1mA
[Pullup]
-1.77V    900uA      900uA      673.7uA
-1.309V   2.5mA      1.674mA    2.963mA
-1.079V   6.9mA      2.968mA    10.47mA
-848.5mV  16.66mA    7.7mA      14.42mA
-618.2mV  16.89mA    14.81mA    14.74mA
763.6mV   -19.22mA   -17.32mA   -18.27mA
2.088V    -27.84mA   -24.27mA   -26.99mA
2.376V    -25.59mA   -21.23mA   -25.8mA
2.606V    -24.21mA   -12.89mA   -24.15mA
2.779V    -17.5mA    -9.684mA   -23.66mA
3.124V    -9.1mA     -7.553mA   -10.44mA
3.585V    -7.4mA     -6.8mA     -7.074mA
[Ramp]
R_load=50.000Ohm
dV/dt_r   583.800mV/114.000ps  529.888mV/134.500ps  597.810mV/109.000ps
dV/dt_f   583.800mV/114.500ps  529.888mV/136.500ps  597.810mV/107.500ps
[Rising waveform]
R_fixture=50.000Ohm
V_fixture=1.800
V_fixture_min=1.700
V_fixture_max=1.900
0s        845.9mV    824.9mV    911.4mV
48ps      844.5mV    824.7mV    976.2mV
106ps     917.9mV    840.8mV    1.487V
154ps     1.279V     921.2mV    1.726V
183ps     1.482V     1.056V     1.795V
211ps     1.608V     1.231V     1.834V
240ps     1.684V     1.392V     1.859V
278ps     1.738V     1.527V     1.877V
374ps     1.784V     1.656V     1.894V
938ps     1.8V       1.7V       1.9V
[Rising waveform]
R_fixture=50.000Ohm
V_fixture=0
0s        651.6uV    581.3uV    -2.133mV
48ps      -3.541mV   -1.296mV   18.01mV
115ps     31.56mV    -11.78mV   381mV
192ps     420mV      68.54mV    725.8mV
240ps     641mV      252.4mV    842.4mV
288ps     785.1mV    451.2mV    910.9mV
374ps     913.4mV    695.8mV    968mV
470ps     963.8mV    817.4mV    992mV
604ps     985.2mV    873.5mV    1.003V
938ps     993.9mV    893.7mV    1.007V
[Falling waveform]
R_fixture=50.000Ohm
V_fixture=1.800
V_fixture_min=1.700
V_fixture_max=1.900
0s        1.799V     1.699V     1.904V
39ps      1.804V     1.702V     1.908V
58ps      1.813V     1.706V     1.863V
115ps     1.78V      1.725V     1.557V
154ps     1.624V     1.707V     1.337V
192ps     1.421V     1.627V     1.18V
278ps     1.065V     1.294V     1.003V
374ps     917.8mV    1.01V      942.3mV
470ps     872.2mV    898.6mV    924.2mV
938ps     848.9mV    831.2mV    915mV
[Falling waveform]
R_fixture=50.000Ohm
V_fixture=0
0s        996.3mV    899.6mV    1.012V
39ps      1.002V     905mV      932mV
87ps      925.1mV    884.2mV    521.9mV
106ps     819.1mV    850.7mV    380mV
135ps     593.8mV    757.4mV    234.6mV
173ps     331.3mV    563.3mV    128.9mV
211ps     179.9mV    352.1mV    73.18mV
278ps     66.92mV    136.1mV    27.99mV
374ps     18.99mV    39.68mV    7.366mV
938ps     -2.041uV   123.4uV    19.72uV
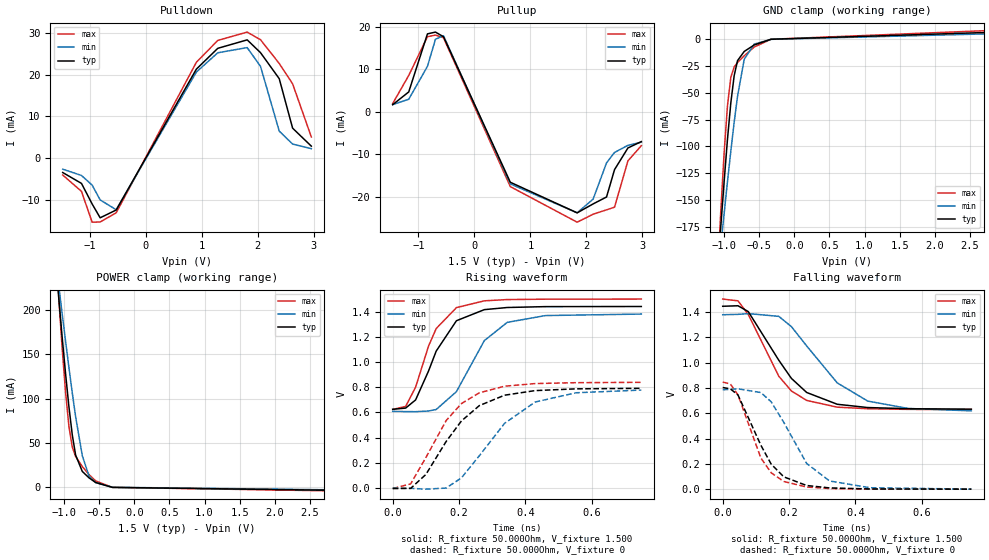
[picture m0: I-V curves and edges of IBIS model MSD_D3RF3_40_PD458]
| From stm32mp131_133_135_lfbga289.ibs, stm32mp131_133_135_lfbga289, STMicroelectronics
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[Model] MSD_D3RF3_40_PD458
Model_type   I/O
C_comp 2.385pF   2.303pF   2.507pF
Vinh = 925.000mV
Vinl = 575.000mV
Vmeas = 750.000mV
Vref = 750.000mV
[Model Spec]
Vinh   925.000mV   888.000mV   963.000mV
Vinl   575.000mV   538.000mV   613.000mV
Vmeas   750.000mV   713.000mV   788.000mV
Vref   750.000mV   713.000mV   788.000mV
[Temperature Range]   25.000   125.000   -40.000
[Voltage Range]   1.500V   1.425V   1.575V
[GND Clamp Reference]   0.00V   0.00V   0.00V
[Pulldown Reference]   0.00V   0.00V   0.00V
[POWER Clamp Reference]   1.500V   1.425V   1.575V
[Pullup Reference]   1.500V   1.425V   1.575V
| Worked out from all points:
|   slope of the pulldown table from 0 to 0.225 V, typ, clamps not added: 36.6 ohm
|   slope of the pullup table from 0 to 0.225 V, typ, clamps not added: 31.2 ohm
|   GND clamp passes 1 mA (typ) near -0.40 V on its own axis
|   POWER clamp passes 1 mA (typ) near -0.41 V on its own axis
|   rising waveform, R_fixture 50.000Ohm, V_fixture 1.500: 20-80 % time 85.9ps typ, 103ps min, 76.1ps max; typ from 0.625 V to 1.44 V
|   rising waveform, R_fixture 50.000Ohm, V_fixture 0: 20-80 % time 137ps typ, 154ps min, 122ps max; typ from -0.004 V to 0.792 V
|   falling waveform, R_fixture 50.000Ohm, V_fixture 1.500: 20-80 % time 126ps typ, 152ps min, 109ps max; typ from 1.45 V to 0.633 V
|   falling waveform, R_fixture 50.000Ohm, V_fixture 0: 20-80 % time 88.8ps typ, 106ps min, 77ps max; typ from 0.804 V to 0 V
[GND Clamp]
-1.48V    -594.6mA   -480.3mA   -764mA
-1.098V   -218.6mA   -223.7mA   -220.8mA
-1.05V    -174.4mA   -192.7mA   -160.1mA
-1.002V   -132.3mA   -162.2mA   -105.6mA
-954.6mV  -93.15mA   -132.6mA   -61.94mA
-906.8mV  -59.31mA   -104.2mA   -35.51mA
-859.1mV  -34.06mA   -77.39mA   -25.96mA
-811.4mV  -20.13mA   -53.27mA   -21.92mA
-715.9mV  -11.58mA   -18.88mA   -15.63mA
-572.7mV  -5.513mA   -4.72mA    -7.447mA
-334.1mV  -249.6uA   -317.8uA   -254.1uA
2.959V    6.512mA    5.126mA    8.372mA
[Power Clamp]
-1.459V   578.2mA    479.5mA    723.7mA
-1.077V   211.3mA    225.7mA    210.8mA
-1.03V    168.5mA    194.9mA    156mA
-981.8mV  127.8mA    164.6mA    107.1mA
-934.1mV  90.77mA    134.9mA    68.64mA
-886.4mV  59.26mA    106.4mA    45.51mA
-838.6mV  36.4mA     79.58mA    34.92mA
-743.2mV  18.03mA    35.67mA    23.54mA
-647.7mV  10.86mA    12.93mA    14.5mA
-552.3mV  5.551mA    5.488mA    7.32mA
-313.6mV  97.21uA    230.9uA    114.2uA
2.98V     -3.313mA   -2.778mA   -4.023mA
[Pulldown]
-1.48V    -3.4mA     -2.6mA     -4mA
-1.145V   -6mA       -4.1mA     -7.9mA
-954.6mV  -10.91mA   -6.4mA     -15.27mA
-811.4mV  -14.22mA   -9.94mA    -15.22mA
-525mV    -12.36mA   -12.3mA    -13.03mA
906.8mV   21.31mA    20.61mA    22.95mA
1.289V    26.28mA    25.22mA    28.17mA
1.814V    28.3mA     26.45mA    30.16mA
2.052V    25.24mA    21.96mA    28.33mA
2.386V    19.03mA    6.5mA      22.66mA
2.625V    7.2mA      3.4mA      17.8mA
2.959V    2.9mA      2.3mA      5.1mA
[Pullup]
-1.459V   1.7mA      1.714mA    1.971mA
-1.173V   4.7mA      2.971mA    8.571mA
-838.6mV  18.38mA    10.73mA    17.71mA
-695.5mV  18.8mA     17.12mA    18.09mA
-552.3mV  17.7mA     17.94mA    17.47mA
640.9mV   -16.58mA   -16.97mA   -17.61mA
1.834V    -23.79mA   -23.78mA   -25.99mA
2.12V     -21.68mA   -20.55mA   -24.11mA
2.359V    -20.05mA   -12.01mA   -23.08mA
2.502V    -13.6mA    -9.557mA   -22.45mA
2.741V    -8.5mA     -7.886mA   -11.54mA
2.98V     -7mA       -7.143mA   -7.971mA
[Ramp]
R_load=50.000Ohm
dV/dt_r   480.660mV/112.000ps  464.519mV/129.500ps  512.850mV/99.500ps
dV/dt_f   480.660mV/108.000ps  464.519mV/131.000ps  512.850mV/93.500ps
[Rising waveform]
R_fixture=50.000Ohm
V_fixture=1.500
V_fixture_min=1.425
V_fixture_max=1.575
0s        624.9mV    608.9mV    624mV
39ps      634.7mV    606.7mV    647.8mV
69ps      699.6mV    606.2mV    800.7mV
108ps     929.3mV    611.5mV    1.127V
131ps     1.087V     623.3mV    1.266V
192ps     1.328V     765.1mV    1.432V
276ps     1.416V     1.17V      1.486V
345ps     1.433V     1.315V     1.496V
460ps     1.44V      1.369V     1.499V
749ps     1.441V     1.381V     1.5V
[Rising waveform]
R_fixture=50.000Ohm
V_fixture=0
0s        -4.122mV   752.5uV    -3.718mV
54ps      -2.762mV   -2.226mV   32.83mV
100ps     107.9mV    -8.948mV   242.1mV
161ps     369.7mV    -76.28uV   535.7mV
207ps     532.2mV    80.56mV    670.1mV
261ps     654.3mV    256.3mV    756mV
337ps     736.9mV    513.5mV    808.3mV
429ps     773.4mV    682.7mV    829.2mV
552ps     787.3mV    756.2mV    836.3mV
749ps     791.5mV    777.8mV    839.1mV
[Falling waveform]
R_fixture=50.000Ohm
V_fixture=1.500
V_fixture_min=1.425
V_fixture_max=1.575
0s        1.447V     1.38V      1.504V
46ps      1.451V     1.383V     1.49V
77ps      1.405V     1.389V     1.382V
169ps     1.02V      1.367V     893.4mV
207ps     876.3mV    1.286V     776.9mV
253ps     765mV      1.133V     702mV
345ps     671.7mV    841mV      648.8mV
437ps     645.7mV    696.8mV    636.3mV
559ps     636.5mV    638.6mV    631.3mV
749ps     632.9mV    619.5mV    629.8mV
[Falling waveform]
R_fixture=50.000Ohm
V_fixture=0
0s        804.1mV    786.1mV    847.5mV
23ps      793.6mV    789.8mV    832.1mV
46ps      745.2mV    793.6mV    745.9mV
115ps     347.3mV    764.4mV    246.3mV
146ps     198.3mV    691.2mV    129.8mV
184ps     97.42mV    528.3mV    60.88mV
253ps     28.99mV    203mV      16.95mV
322ps     9.955mV    64.81mV    5.027mV
444ps     1.705mV    11.36mV    702.4uV
749ps     53.48uV    351.7uV    30.12uV
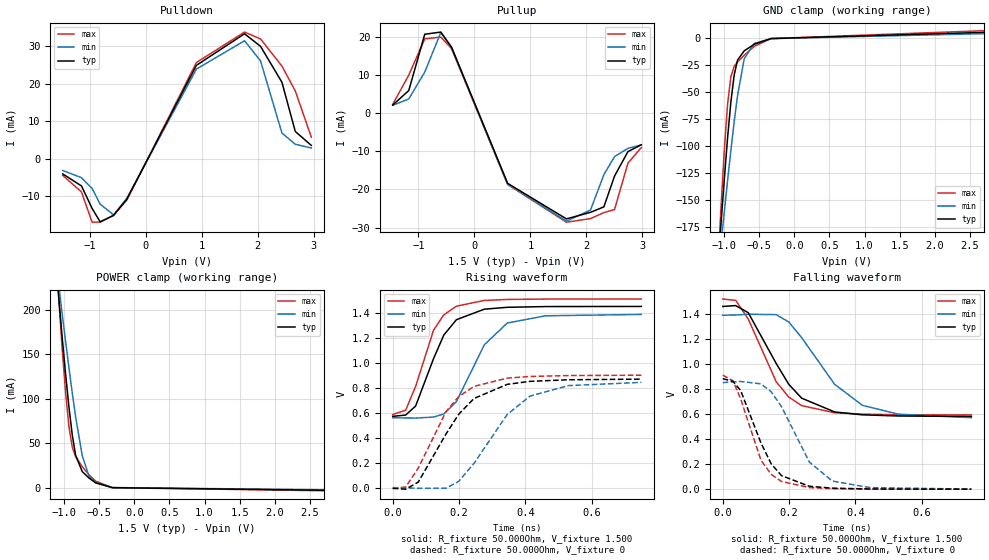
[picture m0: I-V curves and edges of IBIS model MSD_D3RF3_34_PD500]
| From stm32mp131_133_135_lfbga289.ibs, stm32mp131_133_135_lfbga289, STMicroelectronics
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[Model] MSD_D3RF3_34_PD500
Model_type   I/O
C_comp 2.402pF   2.320pF   2.524pF
Vinh = 925.000mV
Vinl = 575.000mV
Vmeas = 750.000mV
Vref = 750.000mV
[Model Spec]
Vinh   925.000mV   888.000mV   963.000mV
Vinl   575.000mV   538.000mV   613.000mV
Vmeas   750.000mV   713.000mV   788.000mV
Vref   750.000mV   713.000mV   788.000mV
[Temperature Range]   25.000   125.000   -40.000
[Voltage Range]   1.500V   1.425V   1.575V
[GND Clamp Reference]   0.00V   0.00V   0.00V
[Pulldown Reference]   0.00V   0.00V   0.00V
[POWER Clamp Reference]   1.500V   1.425V   1.575V
[Pullup Reference]   1.500V   1.425V   1.575V
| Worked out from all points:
|   slope of the pulldown table from 0 to 0.225 V, typ, clamps not added: 31.5 ohm
|   slope of the pullup table from 0 to 0.225 V, typ, clamps not added: 26.9 ohm
|   GND clamp passes 1 mA (typ) near -0.40 V on its own axis
|   POWER clamp passes 1 mA (typ) near -0.41 V on its own axis
|   rising waveform, R_fixture 50.000Ohm, V_fixture 1.500: 20-80 % time 81.3ps typ, 97.3ps min, 72.3ps max; typ from 0.571 V to 1.45 V
|   rising waveform, R_fixture 50.000Ohm, V_fixture 0: 20-80 % time 127ps typ, 142ps min, 115ps max; typ from -0.005 V to 0.869 V
|   falling waveform, R_fixture 50.000Ohm, V_fixture 1.500: 20-80 % time 117ps typ, 145ps min, 102ps max; typ from 1.46 V to 0.579 V
|   falling waveform, R_fixture 50.000Ohm, V_fixture 0: 20-80 % time 84.1ps typ, 103ps min, 73.3ps max; typ from 0.881 V to 0 V
[GND Clamp]
-1.48V    -594.8mA   -480.4mA   -764.2mA
-1.098V   -218.7mA   -223.8mA   -220.9mA
-1.05V    -174.5mA   -192.8mA   -160.2mA
-1.002V   -132.3mA   -162.4mA   -105.8mA
-954.6mV  -93.23mA   -132.6mA   -62.04mA
-906.8mV  -59.38mA   -104.2mA   -35.61mA
-859.1mV  -34.13mA   -77.43mA   -26.05mA
-811.4mV  -20.2mA    -53.31mA   -21.99mA
-715.9mV  -11.62mA   -18.92mA   -15.69mA
-572.7mV  -5.538mA   -4.741mA   -7.48mA
-334.1mV  -251.7uA   -319.9uA   -256.8uA
2.959V    5.967mA    4.7mA      7.668mA
[Power Clamp]
-1.459V   578.3mA    479.7mA    723.9mA
-1.077V   211.5mA    225.8mA    210.9mA
-1.03V    168.6mA    195mA      156.1mA
-981.8mV  128mA      164.6mA    107.2mA
-934.1mV  90.86mA    134.9mA    68.75mA
-886.4mV  59.34mA    106.4mA    45.62mA
-838.6mV  36.47mA    79.64mA    35mA
-743.2mV  18.09mA    35.72mA    23.61mA
-647.7mV  10.91mA    12.96mA    14.55mA
-552.3mV  5.576mA    5.511mA    7.355mA
-313.6mV  99.81uA    233.7uA    118uA
2.98V     -3.037mA   -2.547mA   -3.688mA
[Pulldown]
-1.48V    -4mA       -3.1mA     -4.4mA
-1.145V   -7.2mA     -5mA       -8.8mA
-954.6mV  -13.21mA   -7.9mA     -16.87mA
-811.4mV  -16.78mA   -12.05mA   -16.85mA
-572.7mV  -15.07mA   -14.91mA   -15.04mA
-334.1mV  -10.72mA   -10.48mA   -10.95mA
906.8mV   24.93mA    23.93mA    25.68mA
1.766V    33.35mA    31.49mA    33.8mA
2.052V    30.01mA    26.14mA    31.98mA
2.434V    20.43mA    6.9mA      24.74mA
2.673V    7.3mA      3.9mA      18.1mA
2.959V    3.6mA      2.9mA      5.8mA
[Pullup]
-1.459V   2.1mA      2.057mA    2.271mA
-1.173V   5.9mA      3.686mA    9.943mA
-886.4mV  20.67mA    10.76mA    19.45mA
-600mV    21.23mA    21.13mA    19.92mA
-409.1mV  17.29mA    17.18mA    16.91mA
593.2mV   -18.41mA   -18.64mA   -18.71mA
1.643V    -27.73mA   -28.33mA   -28.59mA
2.073V    -26mA      -25.4mA    -27.65mA
2.311V    -24.58mA   -16.14mA   -26.08mA
2.502V    -16.5mA    -11.4mA    -25.27mA
2.741V    -10.1mA    -9.229mA   -13.11mA
2.98V     -8.3mA     -8.343mA   -9.029mA
[Ramp]
R_load=50.000Ohm
dV/dt_r   522.570mV/104.500ps  500.909mV/121.000ps  545.730mV/93.500ps
dV/dt_f   522.570mV/101.000ps  500.909mV/126.000ps  545.730mV/88.500ps
[Rising waveform]
R_fixture=50.000Ohm
V_fixture=1.500
V_fixture_min=1.425
V_fixture_max=1.575
0s        571.1mV    560.4mV    585.6mV
39ps      581.6mV    558.2mV    620.2mV
69ps      653.7mV    557.4mV    810.7mV
123ps     1.033V     565.4mV    1.261V
154ps     1.222V     590.4mV    1.384V
192ps     1.345V     689.8mV    1.453V
276ps     1.429V     1.144V     1.499V
345ps     1.444V     1.318V     1.507V
460ps     1.45V      1.376V     1.51V
749ps     1.451V     1.387V     1.51V
[Rising waveform]
R_fixture=50.000Ohm
V_fixture=0
0s        -4.988mV   862.6uV    -4.846mV
39ps      -11.59mV   -714.8uV   5.714mV
77ps      45.07mV    -4.814mV   157.3mV
161ps     432mV      -4.376mV   610.9mV
199ps     588.7mV    51.35mV    729.6mV
245ps     714.3mV    195.2mV    811.1mV
345ps     827.4mV    586.2mV    877.2mV
414ps     851.3mV    733.5mV    890.3mV
529ps     864.1mV    817.2mV    897.7mV
749ps     869.2mV    843.3mV    900.6mV
[Falling waveform]
R_fixture=50.000Ohm
V_fixture=1.500
V_fixture_min=1.425
V_fixture_max=1.575
0s        1.457V     1.387V     1.516V
39ps      1.464V     1.389V     1.506V
77ps      1.407V     1.395V     1.356V
161ps     1.003V     1.392V     857.5mV
199ps     836.3mV    1.333V     734.2mV
238ps     725.5mV    1.208V     666.3mV
337ps     615.9mV    836.9mV    609.3mV
421ps     592.8mV    668.3mV    598.3mV
529ps     583.7mV    598mV      593.6mV
749ps     579.4mV    570.4mV    592.1mV
[Falling waveform]
R_fixture=50.000Ohm
V_fixture=0
0s        881.4mV    850mV      909.6mV
31ps      859.6mV    854.9mV    864.3mV
54ps      787.3mV    858.7mV    720.6mV
115ps     370mV      839.9mV    232.1mV
146ps     202.3mV    777.2mV    118mV
177ps     108.1mV    658.2mV    61.65mV
261ps     23.22mV    216.5mV    12.83mV
330ps     8.091mV    64.96mV    3.843mV
444ps     1.602mV    12.25mV    607.3uV
749ps     49.07uV    402.5uV    25.71uV
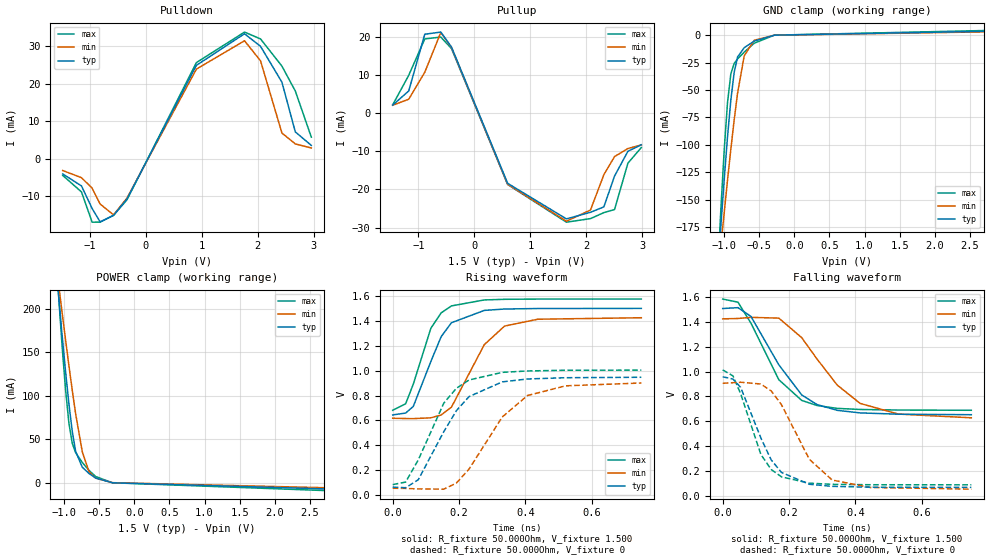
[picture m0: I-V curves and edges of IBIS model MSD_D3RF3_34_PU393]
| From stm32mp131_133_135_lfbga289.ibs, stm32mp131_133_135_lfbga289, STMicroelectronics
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[Model] MSD_D3RF3_34_PU393
Model_type   I/O
C_comp 2.359pF   2.276pF   2.481pF
Vinh = 925.000mV
Vinl = 575.000mV
Vmeas = 750.000mV
Vref = 750.000mV
[Model Spec]
Vinh   925.000mV   888.000mV   963.000mV
Vinl   575.000mV   538.000mV   613.000mV
Vmeas   750.000mV   713.000mV   788.000mV
Vref   750.000mV   713.000mV   788.000mV
[Temperature Range]   25.000   125.000   -40.000
[Voltage Range]   1.500V   1.425V   1.575V
[GND Clamp Reference]   0.00V   0.00V   0.00V
[Pulldown Reference]   0.00V   0.00V   0.00V
[POWER Clamp Reference]   1.500V   1.425V   1.575V
[Pullup Reference]   1.500V   1.425V   1.575V
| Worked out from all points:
|   slope of the pulldown table from 0 to 0.225 V, typ, clamps not added: 31.5 ohm
|   slope of the pullup table from 0 to 0.225 V, typ, clamps not added: 26.9 ohm
|   GND clamp passes 1 mA (typ) near -0.40 V on its own axis
|   POWER clamp passes 1 mA (typ) near -0.41 V on its own axis
|   rising waveform, R_fixture 50.000Ohm, V_fixture 1.500: 20-80 % time 77.7ps typ, 95.5ps min, 68.3ps max; typ from 0.644 V to 1.5 V
|   rising waveform, R_fixture 50.000Ohm, V_fixture 0: 20-80 % time 116ps typ, 134ps min, 103ps max; typ from 0.064 V to 0.947 V
|   falling waveform, R_fixture 50.000Ohm, V_fixture 1.500: 20-80 % time 121ps typ, 148ps min, 107ps max; typ from 1.51 V to 0.653 V
|   falling waveform, R_fixture 50.000Ohm, V_fixture 0: 20-80 % time 85.8ps typ, 105ps min, 74.7ps max; typ from 0.958 V to 0.069 V
[GND Clamp]
-1.48V    -594.2mA   -479.9mA   -763.5mA
-1.098V   -218.3mA   -223.5mA   -220.5mA
-1.05V    -174.3mA   -192.5mA   -159.8mA
-1.002V   -132.1mA   -162.1mA   -105.4mA
-954.6mV  -92.96mA   -132.4mA   -61.7mA
-906.8mV  -59.13mA   -103.9mA   -35.31mA
-859.1mV  -33.9mA    -77.24mA   -25.77mA
-811.4mV  -19.99mA   -53.14mA   -21.74mA
-715.9mV  -11.47mA   -18.78mA   -15.5mA
-572.7mV  -5.45mA    -4.659mA   -7.371mA
-286.4mV  -66.01uA   -113.6uA   -51.62uA
2.959V    3.738mA    3.188mA    4.51mA
[Power Clamp]
-1.459V   578mA      479.5mA    723.4mA
-1.077V   211.2mA    225.7mA    210.5mA
-1.03V    168.4mA    194.9mA    155.8mA
-981.8mV  127.8mA    164.4mA    106.9mA
-934.1mV  90.66mA    134.8mA    68.47mA
-886.4mV  59.16mA    106.3mA    45.36mA
-838.6mV  36.3mA     79.53mA    34.78mA
-743.2mV  17.97mA    35.64mA    23.43mA
-647.7mV  10.82mA    12.9mA     14.42mA
-552.3mV  5.524mA    5.475mA    7.277mA
-313.6mV  104.1uA    239.3uA    117uA
2.98V     -7.53mA    -6.065mA   -9.612mA
[Pulldown]
-1.48V    -4mA       -3.1mA     -4.4mA
-1.145V   -7.2mA     -5mA       -8.8mA
-954.6mV  -13.23mA   -7.8mA     -16.87mA
-811.4mV  -16.78mA   -12.04mA   -16.85mA
-572.7mV  -15.06mA   -14.91mA   -15.03mA
-334.1mV  -10.72mA   -10.48mA   -10.94mA
906.8mV   24.93mA    23.93mA    25.67mA
1.766V    33.35mA    31.49mA    33.8mA
2.052V    30.01mA    26.15mA    31.98mA
2.434V    20.45mA    6.9mA      24.73mA
2.673V    7.2mA      4mA        18.1mA
2.959V    3.6mA      2.9mA      5.8mA
[Pullup]
-1.459V   2.1mA      2.057mA    2.171mA
-1.173V   5.8mA      3.643mA    9.9mA
-886.4mV  20.67mA    10.7mA     19.44mA
-600mV    21.23mA    21.13mA    19.92mA
-409.1mV  17.29mA    17.18mA    16.91mA
593.2mV   -18.4mA    -18.64mA   -18.71mA
1.643V    -27.73mA   -28.33mA   -28.59mA
2.073V    -25.99mA   -25.39mA   -27.65mA
2.311V    -24.58mA   -16.14mA   -26.08mA
2.502V    -16.5mA    -11.4mA    -25.27mA
2.741V    -10mA      -9.286mA   -13.11mA
2.98V     -8.3mA     -8.343mA   -9.029mA
[Ramp]
R_load=50.000Ohm
dV/dt_r   517.623mV/97.000ps  495.300mV/116.000ps  540.243mV/85.500ps
dV/dt_f   517.623mV/103.500ps  495.300mV/127.500ps  540.243mV/91.000ps
[Rising waveform]
R_fixture=50.000Ohm
V_fixture=1.500
V_fixture_min=1.425
V_fixture_max=1.575
0s        644.1mV    617.3mV    681.6mV
39ps      659mV      615mV      733.7mV
62ps      712.5mV    614.3mV    891.4mV
115ps     1.074V     620.9mV    1.341V
146ps     1.273V     643.4mV    1.464V
177ps     1.385V     706.7mV    1.52V
276ps     1.484V     1.209V     1.568V
337ps     1.495V     1.358V     1.573V
437ps     1.499V     1.413V     1.575V
749ps     1.5V       1.425V     1.575V
[Rising waveform]
R_fixture=50.000Ohm
V_fixture=0
0s        63.76mV    54.98mV    84.17mV
39ps      59.22mV    53.36mV    104.5mV
77ps      123.2mV    49.51mV    282.3mV
154ps     510.1mV    47.56mV    739mV
192ps     678.8mV    97.22mV    858.4mV
230ps     791.2mV    209.3mV    924.8mV
330ps     909.6mV    627.4mV    986mV
406ps     932.9mV    800mV      997.3mV
521ps     943mV      877.9mV    1.003V
749ps     946.7mV    900.6mV    1.004V
[Falling waveform]
R_fixture=50.000Ohm
V_fixture=1.500
V_fixture_min=1.425
V_fixture_max=1.575
0s        1.506V     1.423V     1.582V
46ps      1.513V     1.426V     1.557V
85ps      1.443V     1.435V     1.389V
169ps     1.054V     1.429V     934.5mV
238ps     811.9mV    1.272V     767.8mV
284ps     734.7mV    1.101V     727mV
345ps     688.3mV    891.1mV    704mV
414ps     667.6mV    743.9mV    695.1mV
529ps     657.2mV    658.2mV    690.6mV
749ps     653.1mV    628.2mV    688.6mV
[Falling waveform]
R_fixture=50.000Ohm
V_fixture=0
0s        957.8mV    905.7mV    1.013V
31ps      939.5mV    910.1mV    964.7mV
54ps      872.6mV    913.8mV    821.6mV
115ps     466mV      899.6mV    333.8mV
146ps     290.4mV    844mV      213.3mV
177ps     189.3mV    733.4mV    153.9mV
261ps     94.22mV    294.9mV    103.1mV
330ps     77.8mV     128.2mV    93.81mV
444ps     70.86mV    68.6mV     90.55mV
749ps     69.24mV    54.99mV    90.02mV
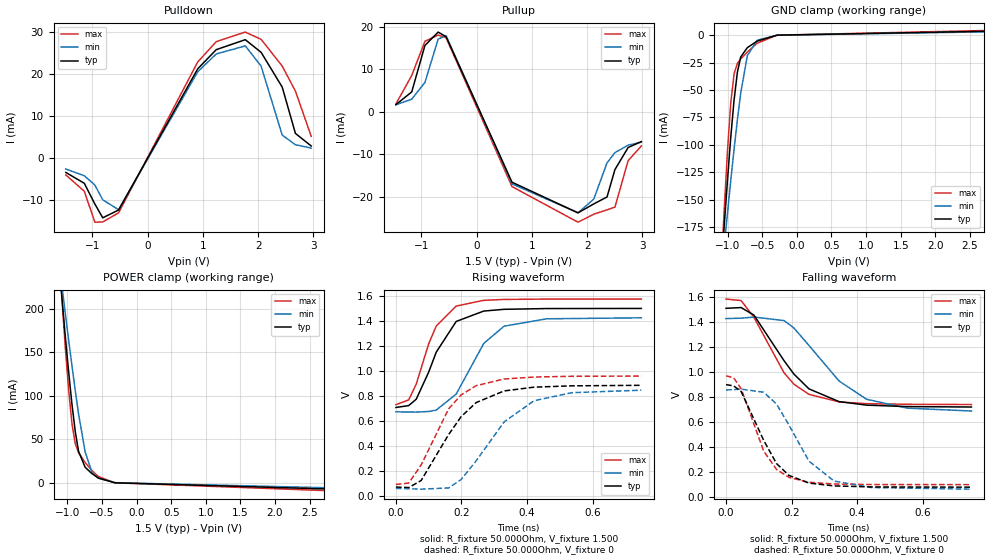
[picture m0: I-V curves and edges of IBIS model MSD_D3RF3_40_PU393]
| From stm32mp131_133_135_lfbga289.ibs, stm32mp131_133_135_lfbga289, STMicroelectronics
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[Model] MSD_D3RF3_40_PU393
Model_type   I/O
C_comp 2.359pF   2.276pF   2.481pF
Vinh = 925.000mV
Vinl = 575.000mV
Vmeas = 750.000mV
Vref = 750.000mV
[Model Spec]
Vinh   925.000mV   888.000mV   963.000mV
Vinl   575.000mV   538.000mV   613.000mV
Vmeas   750.000mV   713.000mV   788.000mV
Vref   750.000mV   713.000mV   788.000mV
[Temperature Range]   25.000   125.000   -40.000
[Voltage Range]   1.500V   1.425V   1.575V
[GND Clamp Reference]   0.00V   0.00V   0.00V
[Pulldown Reference]   0.00V   0.00V   0.00V
[POWER Clamp Reference]   1.500V   1.425V   1.575V
[Pullup Reference]   1.500V   1.425V   1.575V
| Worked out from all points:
|   slope of the pulldown table from 0 to 0.225 V, typ, clamps not added: 36.6 ohm
|   slope of the pullup table from 0 to 0.225 V, typ, clamps not added: 31.2 ohm
|   GND clamp passes 1 mA (typ) near -0.40 V on its own axis
|   POWER clamp passes 1 mA (typ) near -0.41 V on its own axis
|   rising waveform, R_fixture 50.000Ohm, V_fixture 1.500: 20-80 % time 82.2ps typ, 99.8ps min, 71.7ps max; typ from 0.707 V to 1.5 V
|   rising waveform, R_fixture 50.000Ohm, V_fixture 0: 20-80 % time 126ps typ, 144ps min, 110ps max; typ from 0.071 V to 0.885 V
|   falling waveform, R_fixture 50.000Ohm, V_fixture 1.500: 20-80 % time 132ps typ, 157ps min, 115ps max; typ from 1.51 V to 0.717 V
|   falling waveform, R_fixture 50.000Ohm, V_fixture 0: 20-80 % time 91.2ps typ, 109ps min, 79.7ps max; typ from 0.896 V to 0.076 V
[GND Clamp]
-1.48V    -594.2mA   -479.9mA   -763.5mA
-1.098V   -218.3mA   -223.5mA   -220.5mA
-1.05V    -174.3mA   -192.5mA   -159.8mA
-1.002V   -132.1mA   -162.1mA   -105.4mA
-954.6mV  -92.96mA   -132.4mA   -61.7mA
-906.8mV  -59.13mA   -103.9mA   -35.31mA
-859.1mV  -33.9mA    -77.24mA   -25.77mA
-811.4mV  -19.99mA   -53.14mA   -21.74mA
-715.9mV  -11.47mA   -18.78mA   -15.5mA
-572.7mV  -5.45mA    -4.659mA   -7.371mA
-286.4mV  -66.01uA   -113.6uA   -51.62uA
2.959V    3.738mA    3.188mA    4.51mA
[Power Clamp]
-1.459V   578mA      479.5mA    723.4mA
-1.077V   211.2mA    225.7mA    210.5mA
-1.03V    168.4mA    194.9mA    155.8mA
-981.8mV  127.8mA    164.4mA    106.9mA
-934.1mV  90.66mA    134.8mA    68.47mA
-886.4mV  59.16mA    106.3mA    45.36mA
-838.6mV  36.3mA     79.53mA    34.78mA
-743.2mV  17.97mA    35.64mA    23.43mA
-647.7mV  10.82mA    12.9mA     14.42mA
-552.3mV  5.524mA    5.475mA    7.277mA
-313.6mV  104.1uA    239.3uA    117uA
2.98V     -7.53mA    -6.065mA   -9.612mA
[Pulldown]
-1.48V    -3.4mA     -2.6mA     -4mA
-1.145V   -6mA       -4.2mA     -7.9mA
-954.6mV  -10.93mA   -6.4mA     -15.27mA
-811.4mV  -14.23mA   -9.94mA    -15.22mA
-525mV    -12.36mA   -12.3mA    -13.03mA
906.8mV   21.31mA    20.61mA    22.95mA
1.241V    25.87mA    24.84mA    27.78mA
1.766V    28.25mA    26.77mA    30.06mA
2.052V    25.24mA    21.96mA    28.34mA
2.434V    16.95mA    5.5mA      21.96mA
2.673V    5.9mA      3.2mA      16mA
2.959V    2.9mA      2.4mA      5.2mA
[Pullup]
-1.459V   1.7mA      1.657mA    1.871mA
-1.173V   4.7mA      2.986mA    8.571mA
-934.1mV  15.65mA    6.943mA    16.63mA
-695.5mV  18.79mA    17.13mA    18.09mA
-552.3mV  17.7mA     17.94mA    17.47mA
640.9mV   -16.58mA   -16.97mA   -17.61mA
1.834V    -23.79mA   -23.78mA   -25.99mA
2.12V     -21.68mA   -20.55mA   -24.11mA
2.359V    -20.05mA   -12.01mA   -23.08mA
2.502V    -13.6mA    -9.614mA   -22.45mA
2.741V    -8.4mA     -7.843mA   -11.5mA
2.98V     -7mA       -7.143mA   -8.029mA
[Ramp]
R_load=50.000Ohm
dV/dt_r   478.326mV/104.500ps  460.707mV/122.500ps  510.582mV/91.000ps
dV/dt_f   478.326mV/111.500ps  460.707mV/135.500ps  510.582mV/98.000ps
[Rising waveform]
R_fixture=50.000Ohm
V_fixture=1.500
V_fixture_min=1.425
V_fixture_max=1.575
0s        707.4mV    672.9mV    729.7mV
39ps      722.5mV    670.6mV    768mV
62ps      773.7mV    670.4mV    894.7mV
100ps     990.6mV    675.4mV    1.217V
123ps     1.15V      686.4mV    1.359V
184ps     1.396V     814.7mV    1.519V
268ps     1.479V     1.22V      1.565V
330ps     1.493V     1.358V     1.572V
460ps     1.499V     1.417V     1.575V
749ps     1.5V       1.425V     1.575V
[Rising waveform]
R_fixture=50.000Ohm
V_fixture=0
0s        70.75mV    59.44mV    91.27mV
39ps      66.56mV    57.66mV    102.5mV
77ps      123mV      53.67mV    247.2mV
161ps     491.4mV    63.58mV    697mV
199ps     633.9mV    130.6mV    808mV
245ps     746.7mV    281mV      882mV
330ps     839.8mV    591.2mV    935.4mV
421ps     869.9mV    760.7mV    950.9mV
536ps     880.5mV    825.7mV    957mV
749ps     884.8mV    845.7mV    958.8mV
[Falling waveform]
R_fixture=50.000Ohm
V_fixture=1.500
V_fixture_min=1.425
V_fixture_max=1.575
0s        1.506V     1.424V     1.58V
46ps      1.512V     1.427V     1.568V
85ps      1.452V     1.436V     1.434V
177ps     1.087V     1.408V     990.3mV
207ps     980.5mV    1.349V     899.4mV
253ps     861.8mV    1.209V     817.8mV
345ps     759.6mV    924.4mV    757.6mV
429ps     731.7mV    778.6mV    743.4mV
552ps     720.1mV    707.8mV    738.4mV
749ps     716.6mV    684.5mV    736.5mV
[Falling waveform]
R_fixture=50.000Ohm
V_fixture=0
0s        895.6mV    852.5mV    966.3mV
23ps      885.8mV    855.9mV    950.8mV
46ps      841mV      859.5mV    863.6mV
115ps     449.3mV    834.8mV    363.5mV
154ps     264.4mV    740.9mV    217.7mV
192ps     169.5mV    572.3mV    153.6mV
253ps     108.2mV    283.8mV    114.9mV
330ps     85.65mV    123.8mV    100.8mV
444ps     77.47mV    72.66mV    96.61mV
749ps     75.53mV    59.58mV    95.88mV
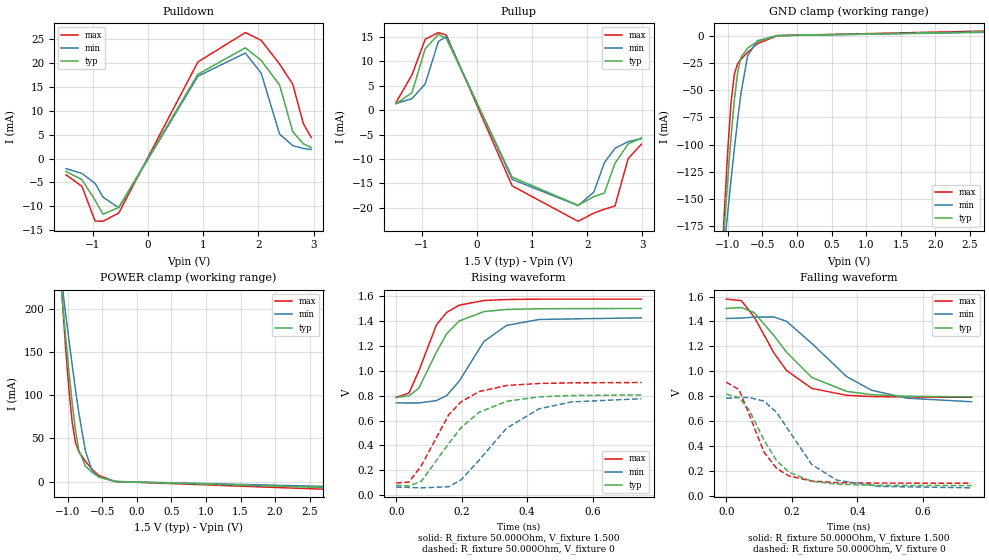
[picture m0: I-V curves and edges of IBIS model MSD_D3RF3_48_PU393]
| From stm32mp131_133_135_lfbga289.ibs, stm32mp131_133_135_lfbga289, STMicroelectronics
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[Model] MSD_D3RF3_48_PU393
Model_type   I/O
C_comp 2.359pF   2.276pF   2.481pF
Vinh = 925.000mV
Vinl = 575.000mV
Vmeas = 750.000mV
Vref = 750.000mV
[Model Spec]
Vinh   925.000mV   888.000mV   963.000mV
Vinl   575.000mV   538.000mV   613.000mV
Vmeas   750.000mV   713.000mV   788.000mV
Vref   750.000mV   713.000mV   788.000mV
[Temperature Range]   25.000   125.000   -40.000
[Voltage Range]   1.500V   1.425V   1.575V
[GND Clamp Reference]   0.00V   0.00V   0.00V
[Pulldown Reference]   0.00V   0.00V   0.00V
[POWER Clamp Reference]   1.500V   1.425V   1.575V
[Pullup Reference]   1.500V   1.425V   1.575V
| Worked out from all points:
|   slope of the pulldown table from 0 to 0.225 V, typ, clamps not added: 44.1 ohm
|   slope of the pullup table from 0 to 0.225 V, typ, clamps not added: 37.5 ohm
|   GND clamp passes 1 mA (typ) near -0.40 V on its own axis
|   POWER clamp passes 1 mA (typ) near -0.41 V on its own axis
|   rising waveform, R_fixture 50.000Ohm, V_fixture 1.500: 20-80 % time 88.8ps typ, 106ps min, 73.7ps max; typ from 0.786 V to 1.5 V
|   rising waveform, R_fixture 50.000Ohm, V_fixture 0: 20-80 % time 136ps typ, 156ps min, 115ps max; typ from 0.08 V to 0.806 V
|   falling waveform, R_fixture 50.000Ohm, V_fixture 1.500: 20-80 % time 146ps typ, 172ps min, 118ps max; typ from 1.5 V to 0.795 V
|   falling waveform, R_fixture 50.000Ohm, V_fixture 0: 20-80 % time 98.7ps typ, 117ps min, 81.1ps max; typ from 0.817 V to 0.083 V
[GND Clamp]
-1.48V    -594.2mA   -479.9mA   -763.5mA
-1.098V   -218.3mA   -223.5mA   -220.5mA
-1.05V    -174.3mA   -192.5mA   -159.8mA
-1.002V   -132.1mA   -162.1mA   -105.4mA
-954.6mV  -92.96mA   -132.4mA   -61.7mA
-906.8mV  -59.13mA   -103.9mA   -35.31mA
-859.1mV  -33.9mA    -77.24mA   -25.77mA
-811.4mV  -19.99mA   -53.14mA   -21.74mA
-715.9mV  -11.47mA   -18.78mA   -15.5mA
-572.7mV  -5.45mA    -4.659mA   -7.371mA
-286.4mV  -66.01uA   -113.6uA   -51.62uA
2.959V    3.738mA    3.188mA    4.51mA
[Power Clamp]
-1.459V   578mA      479.5mA    723.4mA
-1.077V   211.2mA    225.7mA    210.5mA
-1.03V    168.4mA    194.9mA    155.8mA
-981.8mV  127.8mA    164.4mA    106.9mA
-934.1mV  90.66mA    134.8mA    68.47mA
-886.4mV  59.16mA    106.3mA    45.36mA
-838.6mV  36.3mA     79.53mA    34.78mA
-743.2mV  17.97mA    35.64mA    23.43mA
-647.7mV  10.82mA    12.9mA     14.42mA
-552.3mV  5.524mA    5.475mA    7.277mA
-313.6mV  104.1uA    239.3uA    117uA
2.98V     -7.53mA    -6.065mA   -9.612mA
[Pulldown]
-1.48V    -2.7mA     -2.1mA     -3.4mA
-1.193V   -4.4mA     -3.1mA     -5.8mA
-954.6mV  -8.73mA    -5.2mA     -13.05mA
-811.4mV  -11.64mA   -8.07mA    -13.11mA
-525mV    -10.19mA   -10.29mA   -11.37mA
906.8mV   17.62mA    17.2mA     20.18mA
1.766V    23.14mA    22.04mA    26.32mA
2.052V    20.52mA    17.86mA    24.7mA
2.386V    15.37mA    5.1mA      19.75mA
2.625V    5.6mA      2.7mA      15.5mA
2.816V    3.1mA      2.1mA      7.3mA
2.959V    2.3mA      1.9mA      4.4mA
[Pullup]
-1.459V   1.3mA      1.357mA    1.629mA
-1.173V   3.6mA      2.371mA    7.243mA
-934.1mV  12.55mA    5.372mA    14.52mA
-695.5mV  15.51mA    14.06mA    15.89mA
-552.3mV  14.69mA    15.08mA    15.38mA
640.9mV   -13.71mA   -14.18mA   -15.51mA
1.834V    -19.47mA   -19.55mA   -22.76mA
2.12V     -17.72mA   -16.78mA   -21.08mA
2.311V    -16.99mA   -10.74mA   -20.29mA
2.502V    -10.9mA    -7.814mA   -19.63mA
2.741V    -6.9mA     -6.443mA   -9.928mA
2.98V     -5.7mA     -5.843mA   -6.971mA
[Ramp]
R_load=50.000Ohm
dV/dt_r   429.093mV/112.500ps  417.111mV/132.500ps  475.890mV/95.500ps
dV/dt_f   429.093mV/122.500ps  417.078mV/146.500ps  475.890mV/100.500ps
[Rising waveform]
R_fixture=50.000Ohm
V_fixture=1.500
V_fixture_min=1.425
V_fixture_max=1.575
0s        786.1mV    742.7mV    785.8mV
39ps      798.2mV    740.7mV    821.2mV
69ps      860mV      741.4mV    998.1mV
123ps     1.15V      760.6mV    1.369V
154ps     1.296V     800.2mV    1.468V
192ps     1.399V     914.6mV    1.526V
268ps     1.475V     1.235V     1.564V
337ps     1.492V     1.364V     1.572V
437ps     1.498V     1.412V     1.575V
749ps     1.5V       1.425V     1.575V
[Rising waveform]
R_fixture=50.000Ohm
V_fixture=0
0s        79.94mV    65.05mV    99.18mV
39ps      75.28mV    63.42mV    106.1mV
77ps      114.1mV    59.94mV    238.8mV
161ps     417.6mV    69.04mV    648.9mV
199ps     545.2mV    126.2mV    752.2mV
253ps     666.5mV    282mV      832.6mV
337ps     755mV      538.2mV    881.6mV
437ps     790.5mV    695.2mV    898mV
536ps     801.2mV    750mV      903.1mV
749ps     806mV      775.6mV    905.7mV
[Falling waveform]
R_fixture=50.000Ohm
V_fixture=1.500
V_fixture_min=1.425
V_fixture_max=1.575
0s        1.504V     1.424V     1.579V
46ps      1.512V     1.427V     1.567V
85ps      1.471V     1.435V     1.436V
146ps     1.285V     1.436V     1.145V
184ps     1.153V     1.401V     1.007V
261ps     950.9mV    1.224V     863.2mV
368ps     838.9mV    956.7mV    807.6mV
444ps     813.1mV    848.1mV    797.9mV
552ps     799.9mV    784.6mV    793.8mV
749ps     794.9mV    755.9mV    792.6mV
[Falling waveform]
R_fixture=50.000Ohm
V_fixture=0
0s        816.8mV    783.8mV    913mV
39ps      789.8mV    789.5mV    852.5mV
69ps      693.9mV    790.9mV    659.1mV
115ps     448.7mV    760.6mV    352.3mV
154ps     281.9mV    670.1mV    220.2mV
192ps     189.3mV    520.5mV    160.7mV
261ps     118.7mV    253.2mV    120.2mV
337ps     95.01mV    127.3mV    107.5mV
467ps     85.21mV    76.74mV    103.4mV
749ps     83.37mV    65.38mV    102.8mV
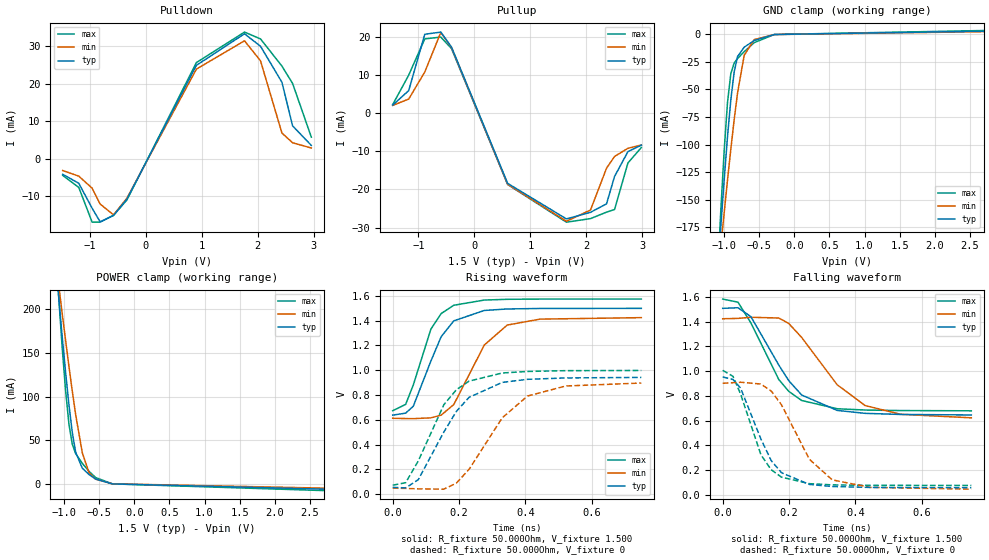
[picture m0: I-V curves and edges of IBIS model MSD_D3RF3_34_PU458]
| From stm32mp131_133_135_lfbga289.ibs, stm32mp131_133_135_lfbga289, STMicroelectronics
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[Model] MSD_D3RF3_34_PU458
Model_type   I/O
C_comp 2.387pF   2.305pF   2.510pF
Vinh = 925.000mV
Vinl = 575.000mV
Vmeas = 750.000mV
Vref = 750.000mV
[Model Spec]
Vinh   925.000mV   888.000mV   963.000mV
Vinl   575.000mV   538.000mV   613.000mV
Vmeas   750.000mV   713.000mV   788.000mV
Vref   750.000mV   713.000mV   788.000mV
[Temperature Range]   25.000   125.000   -40.000
[Voltage Range]   1.500V   1.425V   1.575V
[GND Clamp Reference]   0.00V   0.00V   0.00V
[Pulldown Reference]   0.00V   0.00V   0.00V
[POWER Clamp Reference]   1.500V   1.425V   1.575V
[Pullup Reference]   1.500V   1.425V   1.575V
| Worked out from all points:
|   slope of the pulldown table from 0 to 0.225 V, typ, clamps not added: 31.5 ohm
|   slope of the pullup table from 0 to 0.225 V, typ, clamps not added: 26.9 ohm
|   GND clamp passes 1 mA (typ) near -0.40 V on its own axis
|   POWER clamp passes 1 mA (typ) near -0.41 V on its own axis
|   rising waveform, R_fixture 50.000Ohm, V_fixture 1.500: 20-80 % time 78.5ps typ, 96ps min, 69.1ps max; typ from 0.638 V to 1.5 V
|   rising waveform, R_fixture 50.000Ohm, V_fixture 0: 20-80 % time 118ps typ, 136ps min, 105ps max; typ from 0.054 V to 0.942 V
|   falling waveform, R_fixture 50.000Ohm, V_fixture 1.500: 20-80 % time 122ps typ, 148ps min, 108ps max; typ from 1.51 V to 0.646 V
|   falling waveform, R_fixture 50.000Ohm, V_fixture 0: 20-80 % time 86.2ps typ, 105ps min, 75.3ps max; typ from 0.953 V to 0.06 V
[GND Clamp]
-1.48V    -594.4mA   -480.1mA   -764mA
-1.098V   -218.6mA   -223.6mA   -220.7mA
-1.05V    -174.5mA   -192.7mA   -160.1mA
-1.002V   -132.2mA   -162.2mA   -105.7mA
-954.6mV  -93.12mA   -132.5mA   -61.92mA
-906.8mV  -59.28mA   -104.1mA   -35.5mA
-859.1mV  -34.03mA   -77.35mA   -25.95mA
-811.4mV  -20.11mA   -53.24mA   -21.91mA
-715.9mV  -11.56mA   -18.86mA   -15.62mA
-572.7mV  -5.498mA   -4.705mA   -7.443mA
-286.4mV  -67.01uA   -116.4uA   -54.62uA
2.959V    3.204mA    2.733mA    3.866mA
[Power Clamp]
-1.459V   578.3mA    479.7mA    723.8mA
-1.077V   211.4mA    225.9mA    210.8mA
-1.03V    168.5mA    195mA      156.1mA
-981.8mV  127.9mA    164.6mA    107.2mA
-934.1mV  90.82mA    134.9mA    68.67mA
-886.4mV  59.31mA    106.4mA    45.54mA
-838.6mV  36.44mA    79.64mA    34.94mA
-743.2mV  18.07mA    35.72mA    23.56mA
-647.7mV  10.89mA    12.97mA    14.52mA
-552.3mV  5.57mA     5.518mA    7.336mA
-313.6mV  106.2uA    243.6uA    119.9uA
2.98V     -6.459mA   -5.197mA   -8.237mA
[Pulldown]
-1.48V    -4.1mA     -3.1mA     -4.4mA
-1.193V   -6.5mA     -4.6mA     -7.6mA
-954.6mV  -13.15mA   -7.8mA     -16.87mA
-811.4mV  -16.78mA   -12.04mA   -16.84mA
-572.7mV  -15.07mA   -14.91mA   -15.03mA
-334.1mV  -10.73mA   -10.48mA   -10.95mA
906.8mV   24.93mA    23.93mA    25.67mA
1.766V    33.35mA    31.48mA    33.8mA
2.052V    30.02mA    26.14mA    31.98mA
2.434V    20.43mA    6.9mA      24.74mA
2.625V    8.8mA      4.3mA      20.1mA
2.959V    3.6mA      2.9mA      5.8mA
[Pullup]
-1.459V   2.1mA      2.014mA    2.229mA
-1.173V   5.9mA      3.686mA    9.957mA
-886.4mV  20.66mA    10.76mA    19.45mA
-600mV    21.23mA    21.13mA    19.92mA
-409.1mV  17.29mA    17.18mA    16.91mA
593.2mV   -18.41mA   -18.64mA   -18.71mA
1.643V    -27.73mA   -28.34mA   -28.59mA
2.073V    -26mA      -25.4mA    -27.65mA
2.359V    -23.78mA   -14.44mA   -25.96mA
2.502V    -16.6mA    -11.36mA   -25.27mA
2.741V    -10.1mA    -9.229mA   -13.07mA
2.98V     -8.4mA     -8.343mA   -9.029mA
[Ramp]
R_load=50.000Ohm
dV/dt_r   521.085mV/98.500ps  498.138mV/117.000ps  544.713mV/87.500ps
dV/dt_f   521.085mV/104.500ps  498.138mV/129.000ps  544.713mV/91.500ps
[Rising waveform]
R_fixture=50.000Ohm
V_fixture=1.500
V_fixture_min=1.425
V_fixture_max=1.575
0s        637.6mV    612.2mV    673mV
39ps      653.6mV    609.9mV    724.5mV
62ps      709.3mV    609.2mV    881.1mV
115ps     1.074V     615.6mV    1.332V
146ps     1.271V     637.8mV    1.458V
184ps     1.399V     722.9mV    1.525V
276ps     1.483V     1.204V     1.567V
345ps     1.495V     1.365V     1.573V
444ps     1.499V     1.413V     1.575V
749ps     1.5V       1.425V     1.575V
[Rising waveform]
R_fixture=50.000Ohm
V_fixture=0
0s        54.02mV    47.48mV    71.88mV
39ps      49.99mV    45.86mV    91.81mV
77ps      116.1mV    41.97mV    267.4mV
154ps     501mV      39.63mV    721.6mV
192ps     668.5mV    88.8mV     843.3mV
230ps     781mV      199.9mV    912.3mV
330ps     902mV      616mV      977.9mV
406ps     926.8mV    791.6mV    990.4mV
521ps     937.9mV    872.8mV    996.7mV
749ps     942.2mV    896.9mV    998.2mV
[Falling waveform]
R_fixture=50.000Ohm
V_fixture=1.500
V_fixture_min=1.425
V_fixture_max=1.575
0s        1.507V     1.423V     1.582V
46ps      1.512V     1.426V     1.557V
85ps      1.44V      1.435V     1.389V
169ps     1.049V     1.429V     932.3mV
199ps     923.1mV    1.385V     837mV
238ps     807.3mV    1.272V     763.1mV
345ps     683.1mV    889.9mV    696.7mV
429ps     659.4mV    722.5mV    686.1mV
536ps     650.6mV    651.9mV    682mV
749ps     646.5mV    623.3mV    680mV
[Falling waveform]
R_fixture=50.000Ohm
V_fixture=0
0s        953.3mV    902.4mV    1.007V
31ps      933mV      906.8mV    958.2mV
54ps      863mV      910.5mV    814.3mV
115ps     452.4mV    896.1mV    325.5mV
146ps     279.1mV    840.1mV    204.6mV
177ps     180.1mV    728.8mV    144.5mV
261ps     85.75mV    289.3mV    91.95mV
330ps     68.87mV    122.4mV    81.99mV
444ps     61.49mV    61.76mV    78.31mV
749ps     59.71mV    47.46mV    77.68mV
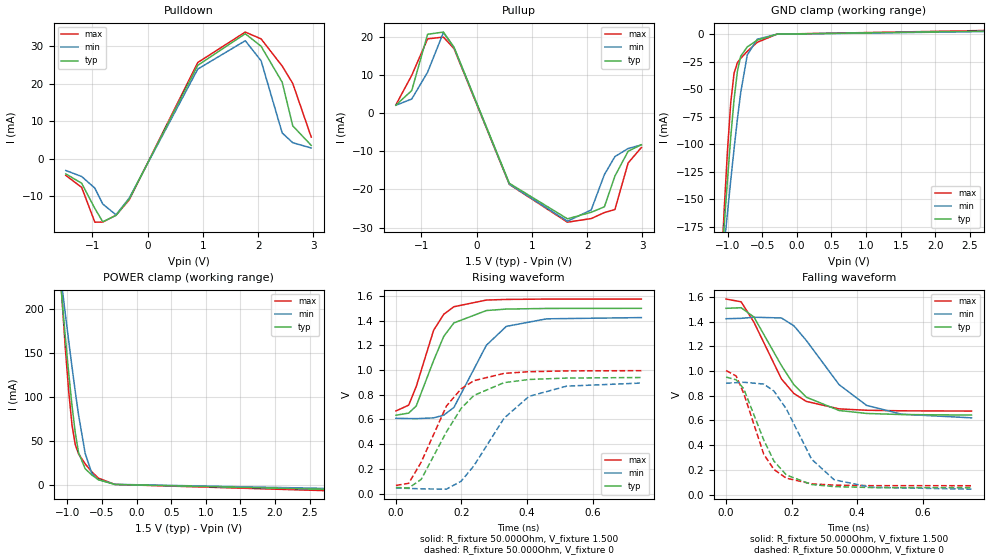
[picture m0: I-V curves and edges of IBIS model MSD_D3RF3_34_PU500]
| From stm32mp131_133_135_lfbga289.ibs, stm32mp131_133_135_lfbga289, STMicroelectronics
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[Model] MSD_D3RF3_34_PU500
Model_type   I/O
C_comp 2.404pF   2.322pF   2.527pF
Vinh = 925.000mV
Vinl = 575.000mV
Vmeas = 750.000mV
Vref = 750.000mV
[Model Spec]
Vinh   925.000mV   888.000mV   963.000mV
Vinl   575.000mV   538.000mV   613.000mV
Vmeas   750.000mV   713.000mV   788.000mV
Vref   750.000mV   713.000mV   788.000mV
[Temperature Range]   25.000   125.000   -40.000
[Voltage Range]   1.500V   1.425V   1.575V
[GND Clamp Reference]   0.00V   0.00V   0.00V
[Pulldown Reference]   0.00V   0.00V   0.00V
[POWER Clamp Reference]   1.500V   1.425V   1.575V
[Pullup Reference]   1.500V   1.425V   1.575V
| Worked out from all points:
|   slope of the pulldown table from 0 to 0.225 V, typ, clamps not added: 31.5 ohm
|   slope of the pullup table from 0 to 0.225 V, typ, clamps not added: 26.9 ohm
|   GND clamp passes 1 mA (typ) near -0.40 V on its own axis
|   POWER clamp passes 1 mA (typ) near -0.41 V on its own axis
|   rising waveform, R_fixture 50.000Ohm, V_fixture 1.500: 20-80 % time 78.8ps typ, 96.5ps min, 69.6ps max; typ from 0.634 V to 1.5 V
|   rising waveform, R_fixture 50.000Ohm, V_fixture 0: 20-80 % time 119ps typ, 136ps min, 106ps max; typ from 0.049 V to 0.94 V
|   falling waveform, R_fixture 50.000Ohm, V_fixture 1.500: 20-80 % time 123ps typ, 149ps min, 108ps max; typ from 1.51 V to 0.643 V
|   falling waveform, R_fixture 50.000Ohm, V_fixture 0: 20-80 % time 86.5ps typ, 106ps min, 75.5ps max; typ from 0.951 V to 0.055 V
[GND Clamp]
-1.48V    -594.7mA   -480.3mA   -764.2mA
-1.098V   -218.6mA   -223.8mA   -220.9mA
-1.05V    -174.5mA   -192.7mA   -160.2mA
-1.002V   -132.3mA   -162.3mA   -105.8mA
-954.6mV  -93.21mA   -132.7mA   -62.02mA
-906.8mV  -59.35mA   -104.2mA   -35.59mA
-859.1mV  -34.1mA    -77.4mA    -26.03mA
-811.4mV  -20.17mA   -53.28mA   -21.97mA
-715.9mV  -11.61mA   -18.89mA   -15.68mA
-572.7mV  -5.526mA   -4.722mA   -7.477mA
-286.4mV  -67.61uA   -115uA     -54.41uA
2.959V    2.938mA    2.505mA    3.545mA
[Power Clamp]
-1.459V   578.5mA    479.9mA    724mA
-1.077V   211.5mA    225.9mA    210.9mA
-1.03V    168.6mA    195.1mA    156.2mA
-981.8mV  128mA      164.7mA    107.3mA
-934.1mV  90.9mA     135mA      68.78mA
-886.4mV  59.39mA    106.5mA    45.64mA
-838.6mV  36.5mA     79.7mA     35.03mA
-743.2mV  18.11mA    35.77mA    23.62mA
-647.7mV  10.93mA    13mA       14.56mA
-552.3mV  5.593mA    5.539mA    7.365mA
-313.6mV  107.3uA    245.7uA    121uA
2.98V     -5.92mA    -4.774mA   -7.555mA
[Pulldown]
-1.48V    -4mA       -3.1mA     -4.4mA
-1.193V   -6.5mA     -4.7mA     -7.6mA
-954.6mV  -13.21mA   -7.8mA     -16.88mA
-811.4mV  -16.78mA   -12.04mA   -16.85mA
-572.7mV  -15.07mA   -14.91mA   -15.03mA
-334.1mV  -10.73mA   -10.49mA   -10.95mA
906.8mV   24.93mA    23.93mA    25.68mA
1.766V    33.35mA    31.49mA    33.79mA
2.052V    30.02mA    26.15mA    31.98mA
2.434V    20.42mA    6.9mA      24.73mA
2.625V    8.8mA      4.3mA      20.1mA
2.959V    3.6mA      2.9mA      5.8mA
[Pullup]
-1.459V   2.1mA      2.057mA    2.171mA
-1.173V   5.9mA      3.686mA    9.9mA
-886.4mV  20.66mA    10.7mA     19.45mA
-600mV    21.23mA    21.13mA    19.92mA
-409.1mV  17.28mA    17.18mA    16.91mA
593.2mV   -18.41mA   -18.64mA   -18.71mA
1.643V    -27.72mA   -28.34mA   -28.6mA
2.073V    -26mA      -25.39mA   -27.65mA
2.311V    -24.58mA   -16.14mA   -26.08mA
2.502V    -16.5mA    -11.4mA    -25.27mA
2.741V    -10mA      -9.286mA   -13.07mA
2.98V     -8.3mA     -8.343mA   -9.029mA
[Ramp]
R_load=50.000Ohm
dV/dt_r   522.828mV/99.000ps  499.551mV/117.500ps  546.999mV/88.500ps
dV/dt_f   522.828mV/105.000ps  499.551mV/129.500ps  546.999mV/92.500ps
[Rising waveform]
R_fixture=50.000Ohm
V_fixture=1.500
V_fixture_min=1.425
V_fixture_max=1.575
0s        634.3mV    609.7mV    668.7mV
39ps      651.6mV    607.4mV    716.1mV
62ps      709.7mV    606.6mV    867mV
115ps     1.077V     612.9mV    1.322V
146ps     1.273V     635mV      1.452V
177ps     1.382V     697.6mV    1.513V
276ps     1.482V     1.201V     1.567V
337ps     1.494V     1.354V     1.572V
460ps     1.499V     1.415V     1.575V
749ps     1.5V       1.425V     1.575V
[Rising waveform]
R_fixture=50.000Ohm
V_fixture=0
0s        49mV       43.69mV    65.95mV
39ps      45.58mV    42.08mV    83.25mV
77ps      114.1mV    38.18mV    253.6mV
154ps     499mV      35.64mV    708.3mV
199ps     690mV      99.88mV    848.6mV
238ps     794.8mV    225.1mV    914.2mV
330ps     898.4mV    610.3mV    973.3mV
406ps     923.8mV    786.9mV    986.7mV
521ps     935.3mV    869.9mV    993.4mV
749ps     939.8mV    895mV      995.2mV
[Falling waveform]
R_fixture=50.000Ohm
V_fixture=1.500
V_fixture_min=1.425
V_fixture_max=1.575
0s        1.507V     1.423V     1.582V
46ps      1.512V     1.426V     1.56V
85ps      1.437V     1.435V     1.395V
169ps     1.044V     1.429V     935.7mV
207ps     888.9mV    1.366V     818mV
245ps     787.8mV    1.247V     753.8mV
345ps     680.3mV    889.4mV    693.3mV
429ps     656.4mV    721.3mV    682.1mV
536ps     647.5mV    650.1mV    677.7mV
749ps     643.2mV    620.9mV    675.7mV
[Falling waveform]
R_fixture=50.000Ohm
V_fixture=0
0s        951mV      900.7mV    1.004V
31ps      928.3mV    905.2mV    958.9mV
54ps      856mV      908.8mV    818.6mV
115ps     442mV      894.3mV    326.4mV
146ps     271.8mV    838.1mV    203.2mV
184ps     158.5mV    693mV      132.5mV
261ps     81.36mV    286.5mV    86.71mV
330ps     64.38mV    119.5mV    76.17mV
444ps     56.8mV     58.37mV    72.21mV
749ps     54.9mV     43.69mV    71.5mV
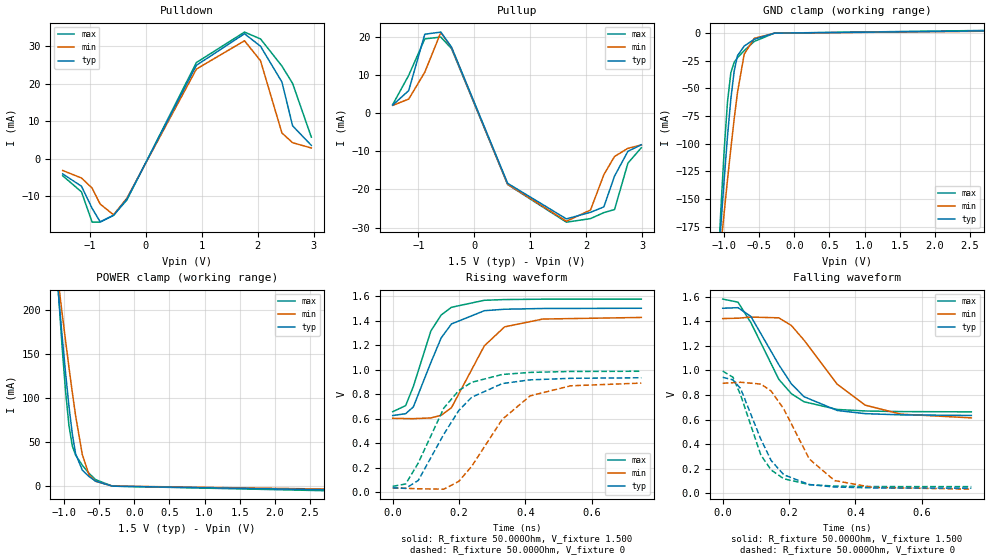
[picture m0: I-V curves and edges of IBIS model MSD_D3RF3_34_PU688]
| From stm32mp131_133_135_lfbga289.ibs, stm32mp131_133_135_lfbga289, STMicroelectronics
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[Model] MSD_D3RF3_34_PU688
Model_type   I/O
C_comp 2.446pF   2.363pF   2.570pF
Vinh = 925.000mV
Vinl = 575.000mV
Vmeas = 750.000mV
Vref = 750.000mV
[Model Spec]
Vinh   925.000mV   888.000mV   963.000mV
Vinl   575.000mV   538.000mV   613.000mV
Vmeas   750.000mV   713.000mV   788.000mV
Vref   750.000mV   713.000mV   788.000mV
[Temperature Range]   25.000   125.000   -40.000
[Voltage Range]   1.500V   1.425V   1.575V
[GND Clamp Reference]   0.00V   0.00V   0.00V
[Pulldown Reference]   0.00V   0.00V   0.00V
[POWER Clamp Reference]   1.500V   1.425V   1.575V
[Pullup Reference]   1.500V   1.425V   1.575V
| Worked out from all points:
|   slope of the pulldown table from 0 to 0.225 V, typ, clamps not added: 31.5 ohm
|   slope of the pullup table from 0 to 0.225 V, typ, clamps not added: 26.9 ohm
|   GND clamp passes 1 mA (typ) near -0.40 V on its own axis
|   POWER clamp passes 1 mA (typ) near -0.41 V on its own axis
|   rising waveform, R_fixture 50.000Ohm, V_fixture 1.500: 20-80 % time 80.1ps typ, 97.5ps min, 71.1ps max; typ from 0.624 V to 1.5 V
|   rising waveform, R_fixture 50.000Ohm, V_fixture 0: 20-80 % time 123ps typ, 139ps min, 111ps max; typ from 0.035 V to 0.933 V
|   falling waveform, R_fixture 50.000Ohm, V_fixture 1.500: 20-80 % time 124ps typ, 150ps min, 110ps max; typ from 1.51 V to 0.633 V
|   falling waveform, R_fixture 50.000Ohm, V_fixture 0: 20-80 % time 87.6ps typ, 106ps min, 77.1ps max; typ from 0.944 V to 0.04 V
[GND Clamp]
-1.48V    -595.2mA   -480.7mA   -764.8mA
-1.098V   -219mA     -224mA     -221.3mA
-1.05V    -174.8mA   -193mA     -160.7mA
-1.002V   -132.6mA   -162.5mA   -106.1mA
-954.6mV  -93.46mA   -132.8mA   -62.34mA
-906.8mV  -59.58mA   -104.4mA   -35.89mA
-859.1mV  -34.31mA   -77.57mA   -26.3mA
-811.4mV  -20.36mA   -53.44mA   -22.21mA
-715.9mV  -11.74mA   -19.01mA   -15.85mA
-572.7mV  -5.607mA   -4.792mA   -7.572mA
-286.4mV  -72.41uA   -119.8uA   -57.21uA
2.959V    2.137mA    1.823mA    2.578mA
[Power Clamp]
-1.459V   579mA      480.3mA    724.6mA
-1.077V   211.8mA    226.2mA    211.3mA
-1.03V    169mA      195.3mA    156.5mA
-981.8mV  128.3mA    164.9mA    107.6mA
-934.1mV  91.14mA    135.2mA    69.08mA
-886.4mV  59.6mA     106.7mA    45.92mA
-838.6mV  36.69mA    79.86mA    35.27mA
-743.2mV  18.26mA    35.9mA     23.82mA
-647.7mV  11.03mA    13.1mA     14.7mA
-552.3mV  5.662mA    5.603mA    7.453mA
-313.6mV  110.5uA    252uA      124.9uA
2.98V     -4.304mA   -3.47mA    -5.498mA
[Pulldown]
-1.48V    -4mA       -3.1mA     -4.5mA
-1.145V   -7.3mA     -5.1mA     -8.8mA
-954.6mV  -13.19mA   -7.8mA     -16.88mA
-811.4mV  -16.78mA   -12.04mA   -16.85mA
-572.7mV  -15.06mA   -14.9mA    -15.04mA
-334.1mV  -10.73mA   -10.48mA   -10.95mA
906.8mV   24.93mA    23.93mA    25.67mA
1.766V    33.35mA    31.48mA    33.79mA
2.052V    30.02mA    26.15mA    31.97mA
2.434V    20.49mA    6.9mA      24.74mA
2.625V    8.8mA      4.3mA      20.1mA
2.959V    3.6mA      2.9mA      5.8mA
[Pullup]
-1.459V   2.1mA      2.014mA    2.229mA
-1.173V   5.9mA      3.686mA    9.9mA
-886.4mV  20.67mA    10.71mA    19.45mA
-600mV    21.23mA    21.13mA    19.92mA
-409.1mV  17.29mA    17.18mA    16.91mA
593.2mV   -18.4mA    -18.64mA   -18.71mA
1.643V    -27.73mA   -28.34mA   -28.59mA
2.073V    -25.99mA   -25.39mA   -27.65mA
2.311V    -24.58mA   -16.14mA   -26.08mA
2.502V    -16.5mA    -11.36mA   -25.27mA
2.741V    -10mA      -9.229mA   -13.11mA
2.98V     -8.3mA     -8.343mA   -9.071mA
[Ramp]
R_load=50.000Ohm
dV/dt_r   528.111mV/102.000ps  503.793mV/119.500ps  553.875mV/91.000ps
dV/dt_f   528.111mV/106.500ps  503.793mV/130.000ps  553.875mV/94.000ps
[Rising waveform]
R_fixture=50.000Ohm
V_fixture=1.500
V_fixture_min=1.425
V_fixture_max=1.575
0s        624.3mV    601.9mV    655.5mV
39ps      639.6mV    599.6mV    705.5mV
62ps      694.3mV    598.9mV    860mV
115ps     1.057V     604.9mV    1.315V
146ps     1.258V     626.5mV    1.445V
177ps     1.372V     688.4mV    1.508V
276ps     1.48V      1.193V     1.565V
337ps     1.492V     1.348V     1.571V
452ps     1.498V     1.412V     1.574V
749ps     1.5V       1.425V     1.575V
[Rising waveform]
R_fixture=50.000Ohm
V_fixture=0
0s        34.66mV    32.24mV    46.76mV
39ps      30.17mV    30.64mV    65.87mV
77ps      94.93mV    26.68mV    237.3mV
154ps     472mV      23.55mV    685.6mV
199ps     665.3mV    86.84mV    828.3mV
238ps     773.6mV    210.3mV    895.8mV
330ps     885.5mV    593.2mV    959.7mV
414ps     915.5mV    784.8mV    976.4mV
536ps     928.2mV    867.1mV    984.1mV
749ps     932.7mV    889.4mV    985.9mV
[Falling waveform]
R_fixture=50.000Ohm
V_fixture=1.500
V_fixture_min=1.425
V_fixture_max=1.575
0s        1.507V     1.423V     1.582V
46ps      1.512V     1.426V     1.557V
85ps      1.44V      1.435V     1.389V
169ps     1.047V     1.429V     927.9mV
207ps     890.2mV    1.366V     810.2mV
245ps     785.9mV    1.247V     744.8mV
345ps     673.6mV    887.7mV    682mV
429ps     647.9mV    717.4mV    669.7mV
536ps     638mV      644mV      664.7mV
749ps     633.2mV    613.4mV    662.5mV
[Falling waveform]
R_fixture=50.000Ohm
V_fixture=0
0s        944.1mV    895.6mV    994.7mV
31ps      923.1mV    900.1mV    944.8mV
54ps      852.1mV    903.8mV    799.1mV
115ps     438.5mV    888.9mV    309.7mV
146ps     265.7mV    832mV      188.5mV
184ps     149.7mV    685.8mV    117mV
261ps     69.38mV    277.9mV    69.32mV
337ps     49.97mV    102.3mV    57.3mV
452ps     42.27mV    46.25mV    53.36mV
749ps     40.31mV    32.2mV     52.58mV
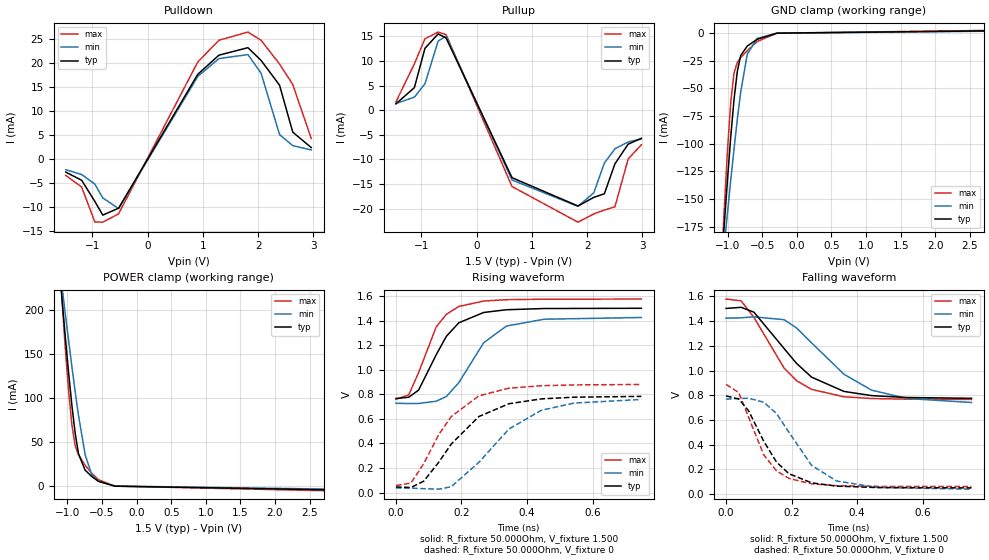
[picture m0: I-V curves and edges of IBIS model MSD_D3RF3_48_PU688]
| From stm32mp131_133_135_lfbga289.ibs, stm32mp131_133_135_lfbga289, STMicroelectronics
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[Model] MSD_D3RF3_48_PU688
Model_type   I/O
C_comp 2.446pF   2.363pF   2.570pF
Vinh = 925.000mV
Vinl = 575.000mV
Vmeas = 750.000mV
Vref = 750.000mV
[Model Spec]
Vinh   925.000mV   888.000mV   963.000mV
Vinl   575.000mV   538.000mV   613.000mV
Vmeas   750.000mV   713.000mV   788.000mV
Vref   750.000mV   713.000mV   788.000mV
[Temperature Range]   25.000   125.000   -40.000
[Voltage Range]   1.500V   1.425V   1.575V
[GND Clamp Reference]   0.00V   0.00V   0.00V
[Pulldown Reference]   0.00V   0.00V   0.00V
[POWER Clamp Reference]   1.500V   1.425V   1.575V
[Pullup Reference]   1.500V   1.425V   1.575V
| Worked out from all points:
|   slope of the pulldown table from 0 to 0.225 V, typ, clamps not added: 44.1 ohm
|   slope of the pullup table from 0 to 0.225 V, typ, clamps not added: 37.5 ohm
|   GND clamp passes 1 mA (typ) near -0.40 V on its own axis
|   POWER clamp passes 1 mA (typ) near -0.41 V on its own axis
|   rising waveform, R_fixture 50.000Ohm, V_fixture 1.500: 20-80 % time 92.1ps typ, 109ps min, 77.5ps max; typ from 0.766 V to 1.5 V
|   rising waveform, R_fixture 50.000Ohm, V_fixture 0: 20-80 % time 146ps typ, 164ps min, 125ps max; typ from 0.046 V to 0.783 V
|   falling waveform, R_fixture 50.000Ohm, V_fixture 1.500: 20-80 % time 150ps typ, 175ps min, 122ps max; typ from 1.5 V to 0.775 V
|   falling waveform, R_fixture 50.000Ohm, V_fixture 0: 20-80 % time 101ps typ, 118ps min, 83.5ps max; typ from 0.794 V to 0.049 V
[GND Clamp]
-1.48V    -595.2mA   -480.7mA   -764.8mA
-1.098V   -219mA     -224mA     -221.3mA
-1.05V    -174.8mA   -193mA     -160.7mA
-1.002V   -132.6mA   -162.5mA   -106.1mA
-954.6mV  -93.46mA   -132.8mA   -62.34mA
-906.8mV  -59.58mA   -104.4mA   -35.89mA
-859.1mV  -34.31mA   -77.57mA   -26.3mA
-811.4mV  -20.36mA   -53.44mA   -22.21mA
-715.9mV  -11.74mA   -19.01mA   -15.85mA
-572.7mV  -5.607mA   -4.792mA   -7.572mA
-286.4mV  -72.41uA   -119.8uA   -57.21uA
2.959V    2.137mA    1.823mA    2.578mA
[Power Clamp]
-1.459V   579mA      480.3mA    724.6mA
-1.077V   211.8mA    226.2mA    211.3mA
-1.03V    169mA      195.3mA    156.5mA
-981.8mV  128.3mA    164.9mA    107.6mA
-934.1mV  91.14mA    135.2mA    69.08mA
-886.4mV  59.6mA     106.7mA    45.92mA
-838.6mV  36.69mA    79.86mA    35.27mA
-743.2mV  18.26mA    35.9mA     23.82mA
-647.7mV  11.03mA    13.1mA     14.7mA
-552.3mV  5.662mA    5.603mA    7.453mA
-313.6mV  110.5uA    252uA      124.9uA
2.98V     -4.304mA   -3.47mA    -5.498mA
[Pulldown]
-1.48V    -2.7mA     -2.2mA     -3.4mA
-1.193V   -4.4mA     -3.2mA     -5.8mA
-954.6mV  -8.79mA    -5.2mA     -13.05mA
-811.4mV  -11.64mA   -8.06mA    -13.11mA
-525mV    -10.2mA    -10.28mA   -11.37mA
906.8mV   17.62mA    17.19mA    20.18mA
1.289V    21.6mA     20.89mA    24.7mA
1.814V    23.16mA    21.73mA    26.4mA
2.052V    20.52mA    17.85mA    24.7mA
2.386V    15.37mA    5.1mA      19.76mA
2.625V    5.6mA      2.8mA      15.5mA
2.959V    2.4mA      1.9mA      4.3mA
[Pullup]
-1.459V   1.3mA      1.357mA    1.686mA
-1.125V   4.6mA      2.671mA    9.443mA
-934.1mV  12.59mA    5.372mA    14.53mA
-695.5mV  15.52mA    14.06mA    15.89mA
-552.3mV  14.7mA     15.08mA    15.38mA
640.9mV   -13.71mA   -14.18mA   -15.51mA
1.834V    -19.47mA   -19.54mA   -22.76mA
2.12V     -17.71mA   -16.78mA   -21.08mA
2.311V    -16.98mA   -10.74mA   -20.29mA
2.502V    -10.9mA    -7.829mA   -19.63mA
2.741V    -6.9mA     -6.443mA   -9.928mA
2.98V     -5.7mA     -5.843mA   -7.014mA
[Ramp]
R_load=50.000Ohm
dV/dt_r   438.927mV/120.000ps  425.253mV/138.000ps  489.093mV/102.500ps
dV/dt_f   438.927mV/126.000ps  425.223mV/149.500ps  489.093mV/103.500ps
[Rising waveform]
R_fixture=50.000Ohm
V_fixture=1.500
V_fixture_min=1.425
V_fixture_max=1.575
0s        765.5mV    726.7mV    758.8mV
39ps      776mV      724.7mV    795.6mV
69ps      833.4mV    725.3mV    974.7mV
123ps     1.122V     743.5mV    1.349V
154ps     1.272V     782mV      1.451V
192ps     1.382V     894.9mV    1.515V
268ps     1.466V     1.22V      1.559V
337ps     1.488V     1.355V     1.57V
452ps     1.498V     1.411V     1.574V
749ps     1.5V       1.425V     1.575V
[Rising waveform]
R_fixture=50.000Ohm
V_fixture=0
0s        45.55mV    38.08mV    56.49mV
46ps      41.32mV    35.97mV    77.89mV
85ps      93.17mV    31.82mV    236.2mV
131ps     248mV      27.73mV    473.8mV
169ps     395.6mV    48.08mV    619.1mV
253ps     618.7mV    245.8mV    787.5mV
345ps     723.1mV    517.6mV    849.6mV
444ps     762.6mV    670.2mV    869.6mV
544ps     776.4mV    728.6mV    876.1mV
749ps     782.9mV    757.9mV    879.9mV
[Falling waveform]
R_fixture=50.000Ohm
V_fixture=1.500
V_fixture_min=1.425
V_fixture_max=1.575
0s        1.503V     1.424V     1.579V
46ps      1.512V     1.427V     1.565V
85ps      1.473V     1.435V     1.431V
177ps     1.179V     1.412V     1.02V
215ps     1.058V     1.345V     917.9mV
261ps     946.2mV    1.224V     847mV
360ps     830.5mV    969.5mV    786.9mV
444ps     796.7mV    840.8mV    773mV
552ps     781mV      773.3mV    767.8mV
749ps     774.7mV    740.8mV    765.7mV
[Falling waveform]
R_fixture=50.000Ohm
V_fixture=0
0s        794.4mV    767.7mV    887.6mV
39ps      768.3mV    773.5mV    820.5mV
69ps      673mV      774.8mV    620.5mV
115ps     426.4mV    743.4mV    316.3mV
154ps     257.9mV    650.9mV    186.2mV
192ps     163.6mV    499.3mV    125.6mV
261ps     89.71mV    231.6mV    81.65mV
337ps     63.19mV    104.9mV    66.68mV
460ps     51.55mV    52.65mV    61.29mV
749ps     48.75mV    38.39mV    60.25mV
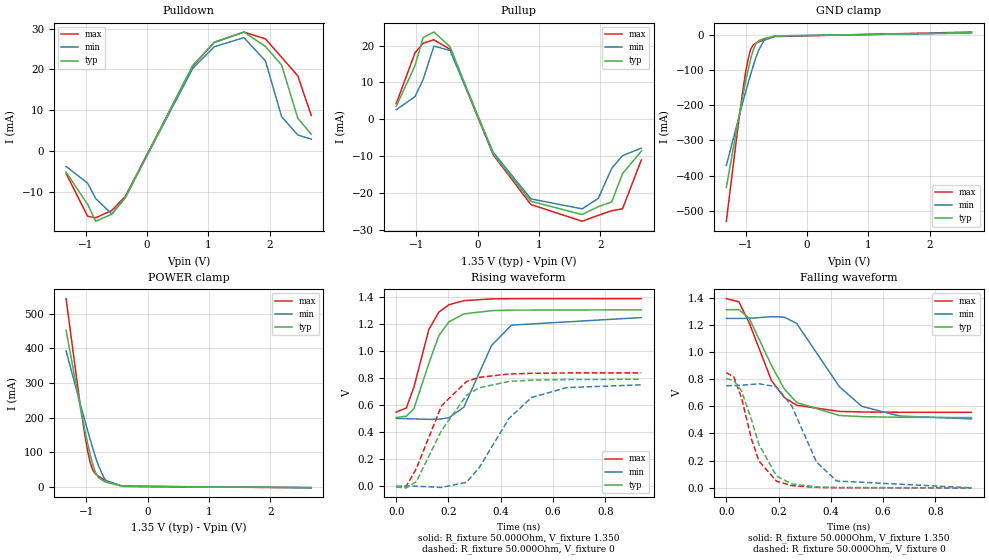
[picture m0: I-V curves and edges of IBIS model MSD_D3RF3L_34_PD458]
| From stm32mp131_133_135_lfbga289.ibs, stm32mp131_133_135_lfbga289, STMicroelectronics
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[Model] MSD_D3RF3L_34_PD458
Model_type   I/O
C_comp 2.393pF   2.308pF   2.516pF
Vinh = 810.000mV
Vinl = 540.000mV
Vmeas = 675.000mV
Vref = 675.000mV
[Model Spec]
Vinh   810.000mV   777.000mV   860.000mV
Vinl   540.000mV   507.000mV   590.000mV
Vmeas   675.000mV   642.000mV   725.000mV
Vref   675.000mV   642.000mV   725.000mV
[Receiver Thresholds]
Vth   =  0.675V
Vth_min  =  0.6615V
Vth_max  =  0.6885V
Vinh_ac  =  0.160V
Vinh_dc  =  0.090V
Vinl_ac  = -0.160V
Vinl_dc  = -0.090V
Tslew_ac =  5.000ns |Not specified, so set to high value
Threshold_sensitivity = 0.50
Reference_supply Pullup_ref
[Temperature Range]   25.000   125.000   -40.000
[Voltage Range]   1.350V   1.283V   1.450V
[GND Clamp Reference]   0.00V   0.00V   0.00V
[Pulldown Reference]   0.00V   0.00V   0.00V
[POWER Clamp Reference]   1.350V   1.283V   1.450V
[Pullup Reference]   1.350V   1.283V   1.450V
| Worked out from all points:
|   slope of the pulldown table from 0 to 0.203 V, typ, clamps not added: 31 ohm
|   slope of the pullup table from 0 to 0.203 V, typ, clamps not added: 26.2 ohm
|   GND clamp passes 1 mA (typ) near -0.40 V on its own axis
|   POWER clamp passes 1 mA (typ) near -0.41 V on its own axis
|   rising waveform, R_fixture 50.000Ohm, V_fixture 1.350: 20-80 % time 83.7ps typ, 105ps min, 74ps max; typ from 0.507 V to 1.3 V
|   rising waveform, R_fixture 50.000Ohm, V_fixture 0: 20-80 % time 132ps typ, 156ps min, 116ps max; typ from -0.006 V to 0.79 V
|   falling waveform, R_fixture 50.000Ohm, V_fixture 1.350: 20-80 % time 128ps typ, 160ps min, 109ps max; typ from 1.31 V to 0.517 V
|   falling waveform, R_fixture 50.000Ohm, V_fixture 0: 20-80 % time 88.1ps typ, 108ps min, 76.3ps max; typ from 0.804 V to 0 V
[GND Clamp]
-1.318V   -433.4mA   -370.8mA   -529.5mA
-1.142V   -261.1mA   -253.1mA   -280.7mA
-1.055V   -178.6mA   -195.6mA   -165.7mA
-1.011V   -139.5mA   -167.5mA   -114.5mA
-966.7mV  -102.7mA   -140mA     -71.69mA
-922.7mV  -69.83mA   -113.5mA   -42.04mA
-878.8mV  -43.2mA    -88.17mA   -28.64mA
-834.9mV  -25.59mA   -64.74mA   -23.69mA
-790.9mV  -17.08mA   -44.07mA   -20.49mA
-703mV    -10.94mA   -16.13mA   -14.83mA
-527.3mV  -3.964mA   -3.359mA   -5.286mA
2.68V     5.803mA    4.518mA    7.521mA
[Power Clamp]
-1.33V    452.5mA    393mA      544.4mA
-1.111V   242.2mA    247.4mA    251.2mA
-1.023V   162.6mA    190.5mA    148.3mA
-978.8mV  125.4mA    162.5mA    103.8mA
-934.9mV  91.31mA    135.3mA    68.32mA
-890.9mV  61.93mA    108.9mA    46.71mA
-847mV    39.6mA     84.01mA    36.22mA
-803mV    26.26mA    61.23mA    30.15mA
-715.1mV  15.61mA    26.48mA    20.68mA
-671.2mV  12.4mA     16.4mA     16.54mA
-407.6mV  894uA      1.169mA    1.092mA
2.668V    -2.917mA   -2.431mA   -3.468mA
[Pulldown]
-1.318V   -5.2mA     -3.8mA     -5.5mA
-966.7mV  -13.1mA    -7.9mA     -16.02mA
-834.9mV  -17.24mA   -11.68mA   -16.39mA
-571.2mV  -15.5mA    -15.46mA   -14.56mA
-351.5mV  -11.48mA   -11.33mA   -11.11mA
747mV     20.95mA    20.22mA    20.78mA
1.098V    26.62mA    25.53mA    26.62mA
1.582V    29.14mA    27.77mA    29.12mA
1.933V    25.61mA    22.08mA    27.47mA
2.197V    21.04mA    8.4mA      22.95mA
2.461V    8mA        3.9mA      18.4mA
2.68V     4.1mA      2.9mA      8.7mA
[Pullup]
-1.33V    3.5mA      2.605mA    4.252mA
-1.023V   14.6mA     6.177mA    18.04mA
-890.9mV  22.16mA    10.8mA     20.65mA
-715.1mV  23.67mA    19.86mA    21.56mA
-451.5mV  19.67mA    18.67mA    18.99mA
251.5mV   -9.374mA   -8.925mA   -9.6mA
866.7mV   -22.22mA   -21.57mA   -23.09mA
1.702V    -25.8mA    -24.26mA   -27.63mA
1.965V    -23.67mA   -21.43mA   -26.01mA
2.185V    -22.4mA    -13.26mA   -24.77mA
2.361V    -14.7mA    -9.838mA   -24.24mA
2.668V    -8.6mA     -7.795mA   -10.98mA
[Ramp]
R_load=50.000Ohm
dV/dt_r   473.100mV/108.000ps  448.409mV/131.500ps  500.790mV/95.500ps
dV/dt_f   473.100mV/108.000ps  448.409mV/136.000ps  500.790mV/93.000ps
[Rising waveform]
R_fixture=50.000Ohm
V_fixture=1.350
V_fixture_min=1.283
V_fixture_max=1.450
0s        507.3mV    501.5mV    548.1mV
39ps      518mV      499.5mV    579.1mV
68ps      574.7mV    497.8mV    734.6mV
125ps     908.7mV    494.6mV    1.159V
163ps     1.113V     495.5mV    1.287V
202ps     1.216V     506mV      1.342V
259ps     1.274V     584.9mV    1.372V
365ps     1.298V     1.041V     1.385V
441ps     1.302V     1.191V     1.386V
938ps     1.304V     1.247V     1.387V
[Rising waveform]
R_fixture=50.000Ohm
V_fixture=0
0s        -6.202mV   878.3uV    -5.494mV
39ps      -11.77mV   964.8uV    1.576mV
77ps      33.84mV    332.3uV    130.2mV
173ps     411.1mV    -9.093mV   593.6mV
269ps     672.6mV    29.28mV    774.4mV
317ps     727.4mV    136.1mV    804.9mV
432ps     775.1mV    502.5mV    829.8mV
518ps     784.3mV    656.2mV    834.7mV
652ps     788.7mV    729.1mV    837.4mV
938ps     790.5mV    749.6mV    838mV
[Falling waveform]
R_fixture=50.000Ohm
V_fixture=1.350
V_fixture_min=1.283
V_fixture_max=1.450
0s        1.31V      1.246V     1.392V
48ps      1.311V     1.246V     1.369V
87ps      1.249V     1.247V     1.216V
173ps     899.6mV    1.259V     788.1mV
221ps     729.4mV    1.256V     665.9mV
269ps     628.1mV    1.21V      607.6mV
432ps     532.4mV    745.4mV    562.1mV
518ps     523.8mV    599.8mV    558mV
662ps     518.9mV    528.5mV    556mV
938ps     517.2mV    506.9mV    555.6mV
[Falling waveform]
R_fixture=50.000Ohm
V_fixture=0
0s        804.3mV    751mV      847.4mV
29ps      788.8mV    752.2mV    815.6mV
58ps      713.2mV    755mV      663.2mV
96ps      501.8mV    760.8mV    359.4mV
125ps     318mV      765.3mV    196.3mV
192ps     86.5mV     743.6mV    48.67mV
250ps     29.05mV    603.2mV    16.47mV
345ps     6.713mV    189.9mV    3.123mV
422ps     2.314mV    50.33mV    828.5uV
938ps     9.541uV    146uV      5.773uV
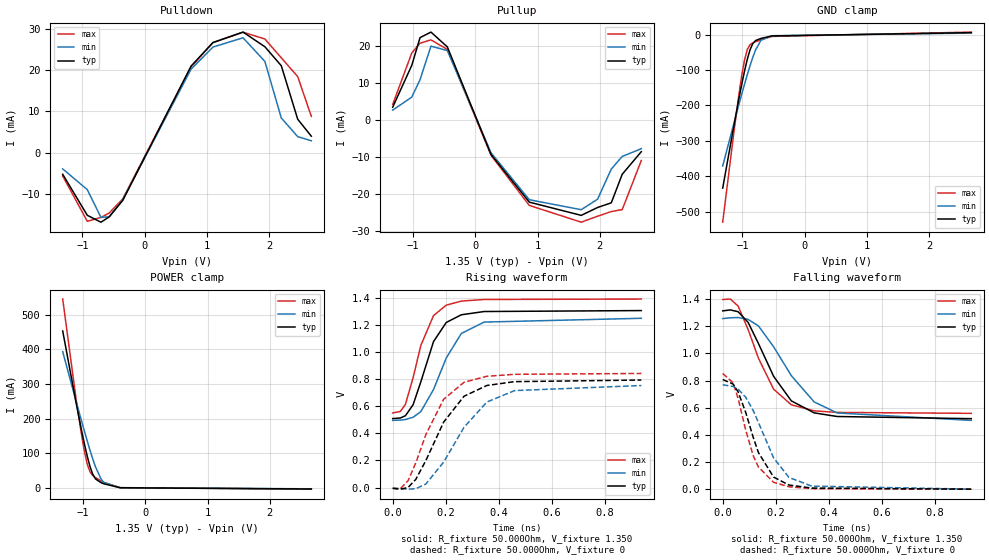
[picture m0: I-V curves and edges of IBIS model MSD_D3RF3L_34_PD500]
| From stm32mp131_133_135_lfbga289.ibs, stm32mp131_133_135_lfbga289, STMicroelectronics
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[Model] MSD_D3RF3L_34_PD500
Model_type   I/O
C_comp 2.410pF   2.326pF   2.533pF
Vinh = 810.000mV
Vinl = 540.000mV
Vmeas = 675.000mV
Vref = 675.000mV
[Model Spec]
Vinh   810.000mV   777.000mV   860.000mV
Vinl   540.000mV   507.000mV   590.000mV
Vmeas   675.000mV   642.000mV   725.000mV
Vref   675.000mV   642.000mV   725.000mV
[Receiver Thresholds]
Vth   =  0.675V
Vth_min  =  0.6615V
Vth_max  =  0.6885V
Vinh_ac  =  0.160V
Vinh_dc  =  0.090V
Vinl_ac  = -0.160V
Vinl_dc  = -0.090V
Tslew_ac =  5.000ns |Not specified, so set to high value
Threshold_sensitivity = 0.50
Reference_supply Pullup_ref
[Temperature Range]   25.000   125.000   -40.000
[Voltage Range]   1.350V   1.283V   1.450V
[GND Clamp Reference]   0.00V   0.00V   0.00V
[Pulldown Reference]   0.00V   0.00V   0.00V
[POWER Clamp Reference]   1.350V   1.283V   1.450V
[Pullup Reference]   1.350V   1.283V   1.450V
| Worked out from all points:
|   slope of the pulldown table from 0 to 0.203 V, typ, clamps not added: 31 ohm
|   slope of the pullup table from 0 to 0.203 V, typ, clamps not added: 26.2 ohm
|   GND clamp passes 1 mA (typ) near -0.40 V on its own axis
|   POWER clamp passes 1 mA (typ) near -0.41 V on its own axis
|   rising waveform, R_fixture 50.000Ohm, V_fixture 1.350: 20-80 % time 83.7ps typ, 106ps min, 74.1ps max; typ from 0.509 V to 1.31 V
|   rising waveform, R_fixture 50.000Ohm, V_fixture 0: 20-80 % time 133ps typ, 157ps min, 117ps max; typ from -0.006 V to 0.794 V
|   falling waveform, R_fixture 50.000Ohm, V_fixture 1.350: 20-80 % time 129ps typ, 163ps min, 110ps max; typ from 1.31 V to 0.519 V
|   falling waveform, R_fixture 50.000Ohm, V_fixture 0: 20-80 % time 88.6ps typ, 111ps min, 76.8ps max; typ from 0.808 V to 0 V
[GND Clamp]
-1.318V   -433.5mA   -370.9mA   -529.7mA
-1.142V   -261.2mA   -253.2mA   -280.9mA
-1.055V   -178.7mA   -195.7mA   -165.8mA
-1.011V   -139.6mA   -167.6mA   -114.7mA
-966.7mV  -102.7mA   -140.1mA   -71.8mA
-922.7mV  -69.9mA    -113.5mA   -42.14mA
-878.8mV  -43.27mA   -88.23mA   -28.74mA
-834.9mV  -25.65mA   -64.79mA   -23.77mA
-790.9mV  -17.14mA   -44.12mA   -20.57mA
-703mV    -10.99mA   -16.17mA   -14.89mA
-527.3mV  -3.983mA   -3.376mA   -5.312mA
2.68V     5.315mA    4.144mA    6.889mA
[Power Clamp]
-1.33V    452.7mA    393.1mA    544.7mA
-1.111V   242.2mA    247.6mA    251.3mA
-1.023V   162.6mA    190.6mA    148.4mA
-978.8mV  125.5mA    162.7mA    103.9mA
-934.9mV  91.39mA    135.4mA    68.44mA
-890.9mV  62.01mA    109mA      46.81mA
-847mV    39.69mA    84.09mA    36.32mA
-803mV    26.33mA    61.28mA    30.23mA
-715.1mV  15.66mA    26.52mA    20.75mA
-671.2mV  12.45mA    16.44mA    16.6mA
-407.6mV  904uA      1.178mA    1.103mA
2.668V    -2.674mA   -2.229mA   -3.179mA
[Pulldown]
-1.318V   -5.2mA     -3.9mA     -5.6mA
-922.7mV  -15.11mA   -8.9mA     -16.55mA
-703mV    -16.77mA   -15.62mA   -15.62mA
-571.2mV  -15.5mA    -15.46mA   -14.56mA
-351.5mV  -11.48mA   -11.33mA   -11.11mA
747mV     20.94mA    20.22mA    20.78mA
1.098V    26.62mA    25.53mA    26.62mA
1.582V    29.15mA    27.77mA    29.12mA
1.933V    25.61mA    22.07mA    27.48mA
2.197V    21.03mA    8.4mA      22.94mA
2.461V    8.1mA      3.9mA      18.4mA
2.68V     4mA        2.9mA      8.8mA
[Pullup]
-1.33V    3.4mA      2.605mA    4.152mA
-1.023V   14.7mA     6.125mA    18.04mA
-890.9mV  22.16mA    10.8mA     20.66mA
-715.1mV  23.66mA    19.86mA    21.56mA
-451.5mV  19.66mA    18.67mA    18.99mA
251.5mV   -9.374mA   -8.925mA   -9.6mA
866.7mV   -22.22mA   -21.57mA   -23.1mA
1.702V    -25.79mA   -24.26mA   -27.63mA
1.965V    -23.66mA   -21.42mA   -26.01mA
2.185V    -22.41mA   -13.3mA    -24.76mA
2.361V    -14.7mA    -9.89mA    -24.24mA
2.668V    -8.6mA     -7.795mA   -10.98mA
[Ramp]
R_load=50.000Ohm
dV/dt_r   474.660mV/108.500ps  449.579mV/131.500ps  502.920mV/96.000ps
dV/dt_f   474.660mV/109.000ps  449.579mV/136.500ps  502.920mV/94.000ps
[Rising waveform]
R_fixture=50.000Ohm
V_fixture=1.350
V_fixture_min=1.283
V_fixture_max=1.450
0s        509.3mV    496mV      550.9mV
29ps      513.6mV    498mV      562.1mV
48ps      530.5mV    502.3mV    614.3mV
77ps      611.8mV    519.2mV    811.5mV
106ps     780.1mV    560.7mV    1.049V
154ps     1.078V     723.5mV    1.27V
202ps     1.219V     956.9mV    1.347V
259ps     1.276V     1.138V     1.377V
345ps     1.3V       1.222V     1.389V
938ps     1.307V     1.25V      1.392V
[Rising waveform]
R_fixture=50.000Ohm
V_fixture=0
0s        -6.201mV   -4.709mV   -5.494mV
29ps      -12.04mV   -8.805mV   -8.389mV
58ps      163.9uV    -12.11mV   50.62mV
87ps      60.05mV    -8.686mV   181.6mV
125ps     199.2mV    25.88mV    390.9mV
192ps     482.6mV    187.4mV    651.5mV
269ps     674mV      444.7mV    777.2mV
355ps     753.7mV    631.1mV    821.6mV
460ps     782.1mV    716mV      836.2mV
938ps     793.9mV    753.4mV    842.6mV
[Falling waveform]
R_fixture=50.000Ohm
V_fixture=1.350
V_fixture_min=1.283
V_fixture_max=1.450
0s        1.313V     1.256V     1.397V
29ps      1.32V      1.262V     1.4V
58ps      1.307V     1.264V     1.349V
96ps      1.228V     1.25V      1.175V
135ps     1.072V     1.202V     963.5mV
192ps     831.2mV    1.049V     736.5mV
259ps     650.1mV    835.6mV    621.3mV
345ps     561.9mV    642.4mV    576.9mV
432ps     535.1mV    561.2mV    565.2mV
938ps     519.2mV    506.5mV    558.4mV
[Falling waveform]
R_fixture=50.000Ohm
V_fixture=0
0s        807.6mV    768.9mV    852mV
39ps      774.5mV    756.5mV    783.8mV
58ps      717.1mV    736.3mV    668.8mV
87ps      564mV      676.4mV    433.4mV
115ps     382.2mV    579.1mV    247.4mV
135ps     268.8mV    490.4mV    162.3mV
192ps     88.92mV    230.2mV    50.79mV
250ps     30.39mV    86.24mV    17.56mV
336ps     8.189mV    22.49mV    4.022mV
938ps     -1.69uV    41.44uV    6.577uV
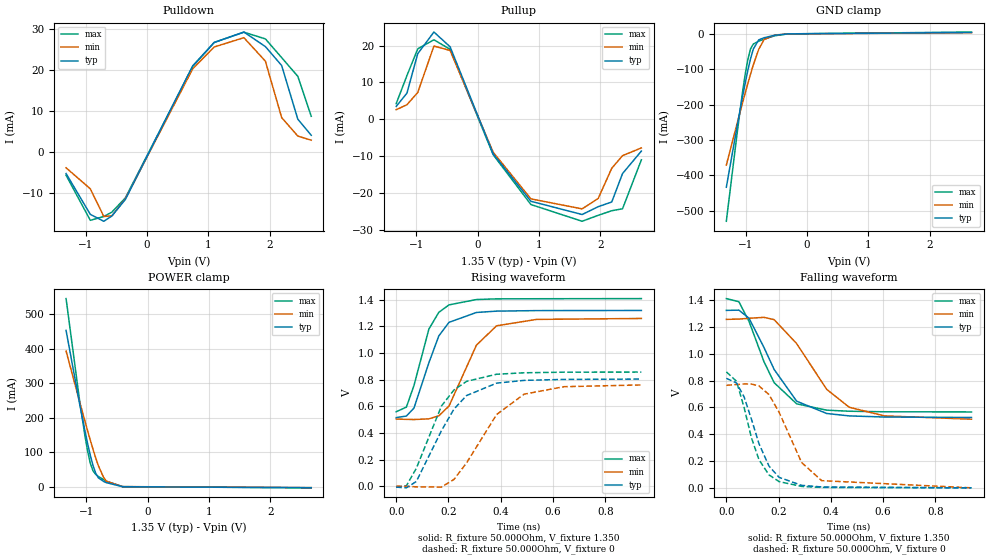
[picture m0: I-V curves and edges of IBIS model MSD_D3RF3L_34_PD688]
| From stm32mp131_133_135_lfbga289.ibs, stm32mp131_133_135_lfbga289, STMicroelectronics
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[Model] MSD_D3RF3L_34_PD688
Model_type   I/O
C_comp 2.452pF   2.367pF   2.576pF
Vinh = 810.000mV
Vinl = 540.000mV
Vmeas = 675.000mV
Vref = 675.000mV
[Model Spec]
Vinh   810.000mV   777.000mV   860.000mV
Vinl   540.000mV   507.000mV   590.000mV
Vmeas   675.000mV   642.000mV   725.000mV
Vref   675.000mV   642.000mV   725.000mV
[Receiver Thresholds]
Vth   =  0.675V
Vth_min  =  0.6615V
Vth_max  =  0.6885V
Vinh_ac  =  0.160V
Vinh_dc  =  0.090V
Vinl_ac  = -0.160V
Vinl_dc  = -0.090V
Tslew_ac =  5.000ns |Not specified, so set to high value
Threshold_sensitivity = 0.50
Reference_supply Pullup_ref
[Temperature Range]   25.000   125.000   -40.000
[Voltage Range]   1.350V   1.283V   1.450V
[GND Clamp Reference]   0.00V   0.00V   0.00V
[Pulldown Reference]   0.00V   0.00V   0.00V
[POWER Clamp Reference]   1.350V   1.283V   1.450V
[Pullup Reference]   1.350V   1.283V   1.450V
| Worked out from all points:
|   slope of the pulldown table from 0 to 0.203 V, typ, clamps not added: 31 ohm
|   slope of the pullup table from 0 to 0.203 V, typ, clamps not added: 26.2 ohm
|   GND clamp passes 1 mA (typ) near -0.40 V on its own axis
|   POWER clamp passes 1 mA (typ) near -0.41 V on its own axis
|   rising waveform, R_fixture 50.000Ohm, V_fixture 1.350: 20-80 % time 84.6ps typ, 106ps min, 75.1ps max; typ from 0.515 V to 1.32 V
|   rising waveform, R_fixture 50.000Ohm, V_fixture 0: 20-80 % time 134ps typ, 158ps min, 119ps max; typ from -0.006 V to 0.804 V
|   falling waveform, R_fixture 50.000Ohm, V_fixture 1.350: 20-80 % time 132ps typ, 164ps min, 113ps max; typ from 1.32 V to 0.525 V
|   falling waveform, R_fixture 50.000Ohm, V_fixture 0: 20-80 % time 90.2ps typ, 111ps min, 78.6ps max; typ from 0.818 V to 0 V
[GND Clamp]
-1.318V   -434mA     -371.3mA   -530.2mA
-1.142V   -261.5mA   -253.5mA   -281.3mA
-1.055V   -179mA     -196mA     -166.2mA
-1.011V   -139.8mA   -167.8mA   -115.1mA
-966.7mV  -103mA     -140.4mA   -72.11mA
-922.7mV  -70.13mA   -113.7mA   -42.44mA
-878.8mV  -43.47mA   -88.39mA   -29mA
-790.9mV  -17.29mA   -44.25mA   -20.79mA
-703mV    -11.11mA   -16.27mA   -15.06mA
-527.3mV  -4.042mA   -3.425mA   -5.39mA
-307.6mV  -133.2uA   -195.4uA   -121.4uA
2.68V     3.865mA    3.009mA    5.016mA
[Power Clamp]
-1.33V    453.1mA    393.5mA    545.2mA
-1.111V   242.6mA    247.9mA    251.8mA
-1.023V   163mA      190.9mA    148.8mA
-978.8mV  125.7mA    162.9mA    104.3mA
-934.9mV  91.65mA    135.6mA    68.75mA
-890.9mV  62.25mA    109.3mA    47.1mA
-847mV    39.9mA     84.29mA    36.58mA
-803mV    26.52mA    61.46mA    30.46mA
-715.1mV  15.81mA    26.66mA    20.93mA
-671.2mV  12.58mA    16.56mA    16.75mA
-407.6mV  927uA      1.209mA    1.127mA
2.668V    -1.945mA   -1.621mA   -2.312mA
[Pulldown]
-1.318V   -5.2mA     -3.8mA     -5.6mA
-922.7mV  -15.11mA   -8.9mA     -16.55mA
-703mV    -16.78mA   -15.62mA   -15.62mA
-571.2mV  -15.5mA    -15.46mA   -14.56mA
-351.5mV  -11.48mA   -11.33mA   -11.11mA
747mV     20.95mA    20.23mA    20.78mA
1.098V    26.63mA    25.53mA    26.63mA
1.582V    29.15mA    27.78mA    29.12mA
1.933V    25.61mA    22.07mA    27.48mA
2.197V    21.04mA    8.4mA      22.95mA
2.461V    8mA        3.9mA      18.4mA
2.68V     4.1mA      2.9mA      8.7mA
[Pullup]
-1.33V    3.5mA      2.605mA    4.252mA
-1.155V   7.1mA      3.962mA    11.86mA
-978.8mV  17.8mA     7.282mA    19.11mA
-715.1mV  23.66mA    19.86mA    21.56mA
-451.5mV  19.67mA    18.67mA    18.99mA
251.5mV   -9.374mA   -8.925mA   -9.6mA
866.7mV   -22.21mA   -21.56mA   -23.09mA
1.702V    -25.8mA    -24.27mA   -27.63mA
1.965V    -23.67mA   -21.43mA   -26.01mA
2.185V    -22.4mA    -13.26mA   -24.77mA
2.361V    -14.7mA    -9.838mA   -24.24mA
2.668V    -8.6mA     -7.748mA   -10.98mA
[Ramp]
R_load=50.000Ohm
dV/dt_r   479.400mV/110.000ps  453.119mV/133.000ps  509.280mV/97.000ps
dV/dt_f   479.400mV/111.500ps  453.119mV/139.000ps  509.280mV/96.000ps
[Rising waveform]
R_fixture=50.000Ohm
V_fixture=1.350
V_fixture_min=1.283
V_fixture_max=1.450
0s        515.3mV    504.4mV    559.2mV
39ps      527mV      502mV      594.1mV
68ps      586.7mV    500.8mV    756.2mV
125ps     926.6mV    505.8mV    1.179V
163ps     1.128V     528.5mV    1.305V
202ps     1.23V      601.8mV    1.361V
307ps     1.304V     1.059V     1.401V
384ps     1.314V     1.204V     1.406V
537ps     1.318V     1.252V     1.407V
938ps     1.319V     1.259V     1.408V
[Rising waveform]
R_fixture=50.000Ohm
V_fixture=0
0s        -6.425mV   755.1uV    -5.776mV
39ps      -11.69mV   -719uV     3.316mV
77ps      36.08mV    -4.229mV   135.1mV
173ps     416.6mV    -5.985mV   601.7mV
221ps     579.3mV    51.31mV    722.9mV
269ps     680.3mV    175mV      787.1mV
384ps     773.9mV    538mV      840.5mV
489ps     794.5mV    690.8mV    851.5mV
642ps     801.9mV    747.1mV    856mV
938ps     804.2mV    760.3mV    856.8mV
[Falling waveform]
R_fixture=50.000Ohm
V_fixture=1.350
V_fixture_min=1.283
V_fixture_max=1.450
0s        1.325V     1.258V     1.413V
48ps      1.327V     1.26V      1.39V
87ps      1.266V     1.266V     1.242V
144ps     1.048V     1.273V     942mV
183ps     883.8mV    1.256V     785.1mV
269ps     647.2mV    1.077V     627.3mV
384ps     555.1mV    735.5mV    580mV
470ps     537.2mV    601.9mV    572mV
604ps     528.8mV    537.3mV    567.9mV
938ps     525.3mV    512.5mV    566.8mV
[Falling waveform]
R_fixture=50.000Ohm
V_fixture=0
0s        817.7mV    765.4mV    866.1mV
39ps      783.1mV    771.4mV    795.5mV
68ps      679.3mV    775.7mV    599.6mV
96ps      512.9mV    775.1mV    374.3mV
125ps     329.1mV    760.5mV    209.4mV
163ps     163mV      696.9mV    96.96mV
202ps     78.12mV    563.8mV    46.35mV
288ps     18.62mV    189.1mV    10.67mV
365ps     6.379mV    53.51mV    3.025mV
938ps     10.44uV    101uV      -2.578uV
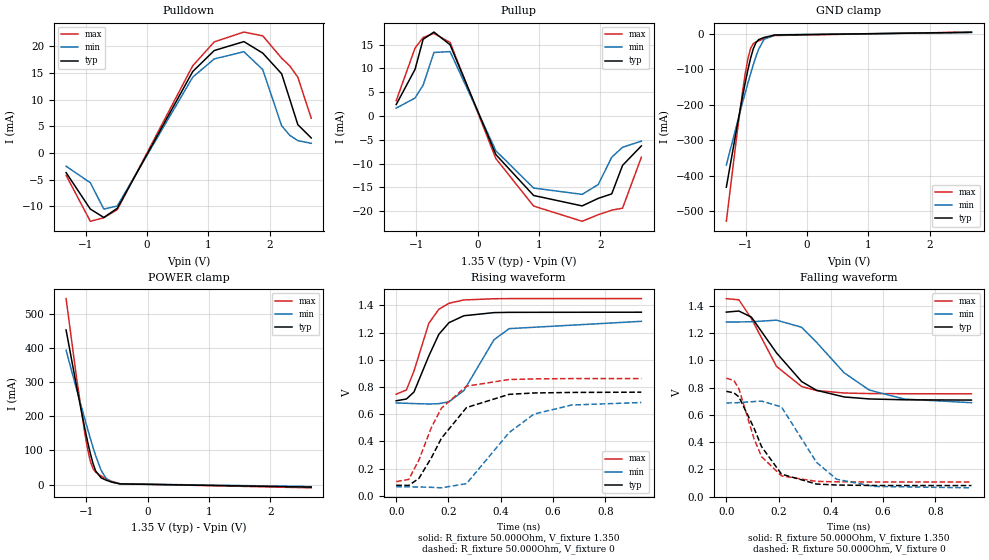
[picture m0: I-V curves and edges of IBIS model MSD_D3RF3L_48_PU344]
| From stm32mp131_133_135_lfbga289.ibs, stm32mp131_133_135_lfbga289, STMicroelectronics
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[Model] MSD_D3RF3L_48_PU344
Model_type   I/O
C_comp 2.337pF   2.253pF   2.460pF
Vinh = 810.000mV
Vinl = 540.000mV
Vmeas = 675.000mV
Vref = 675.000mV
[Model Spec]
Vinh   810.000mV   777.000mV   860.000mV
Vinl   540.000mV   507.000mV   590.000mV
Vmeas   675.000mV   642.000mV   725.000mV
Vref   675.000mV   642.000mV   725.000mV
[Receiver Thresholds]
Vth   =  0.675V
Vth_min  =  0.6615V
Vth_max  =  0.6885V
Vinh_ac  =  0.160V
Vinh_dc  =  0.090V
Vinl_ac  = -0.160V
Vinl_dc  = -0.090V
Tslew_ac =  5.000ns |Not specified, so set to high value
Threshold_sensitivity = 0.50
Reference_supply Pullup_ref
[Temperature Range]   25.000   125.000   -40.000
[Voltage Range]   1.350V   1.283V   1.450V
[GND Clamp Reference]   0.00V   0.00V   0.00V
[Pulldown Reference]   0.00V   0.00V   0.00V
[POWER Clamp Reference]   1.350V   1.283V   1.450V
[Pullup Reference]   1.350V   1.283V   1.450V
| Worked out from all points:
|   slope of the pulldown table from 0 to 0.203 V, typ, clamps not added: 42.2 ohm
|   slope of the pullup table from 0 to 0.203 V, typ, clamps not added: 34.5 ohm
|   GND clamp passes 1 mA (typ) near -0.41 V on its own axis
|   POWER clamp passes 1 mA (typ) near -0.41 V on its own axis
|   rising waveform, R_fixture 50.000Ohm, V_fixture 1.350: 20-80 % time 89.2ps typ, 113ps min, 73.7ps max; typ from 0.699 V to 1.35 V
|   rising waveform, R_fixture 50.000Ohm, V_fixture 0: 20-80 % time 137ps typ, 169ps min, 114ps max; typ from 0.077 V to 0.762 V
|   falling waveform, R_fixture 50.000Ohm, V_fixture 1.350: 20-80 % time 158ps typ, 190ps min, 125ps max; typ from 1.35 V to 0.709 V
|   falling waveform, R_fixture 50.000Ohm, V_fixture 0: 20-80 % time 103ps typ, 122ps min, 84.1ps max; typ from 0.773 V to 0.082 V
[GND Clamp]
-1.318V   -432.7mA   -370.2mA   -528.8mA
-1.142V   -260.6mA   -252.7mA   -280.1mA
-1.055V   -178.2mA   -195.2mA   -165.1mA
-1.011V   -139mA     -167.2mA   -114.1mA
-966.7mV  -102.3mA   -139.7mA   -71.22mA
-922.7mV  -69.47mA   -113.2mA   -41.62mA
-878.8mV  -42.87mA   -87.88mA   -28.25mA
-834.9mV  -25.29mA   -64.47mA   -23.34mA
-790.9mV  -16.82mA   -43.84mA   -20.18mA
-703mV    -10.74mA   -15.95mA   -14.58mA
-527.3mV  -3.867mA   -3.267mA   -5.173mA
2.68V     3.846mA    3.267mA    4.549mA
[Power Clamp]
-1.33V    452.1mA    392.8mA    543.8mA
-1.155V   283.1mA    276.1mA    306.4mA
-1.023V   162.2mA    190.3mA    147.9mA
-978.8mV  125.1mA    162.4mA    103.4mA
-934.9mV  91.05mA    135.1mA    67.96mA
-890.9mV  61.71mA    108.8mA    46.37mA
-847mV    39.4mA     83.89mA    35.92mA
-759.1mV  19.48mA    41.52mA    24.95mA
-671.2mV  12.28mA    16.32mA    16.36mA
-583.3mV  7.022mA    7.054mA    9.286mA
-451.5mV  1.801mA    2.042mA    2.252mA
2.668V    -7.581mA   -6.072mA   -9.749mA
[Pulldown]
-1.318V   -3.7mA     -2.5mA     -4.2mA
-922.7mV  -10.54mA   -5.6mA     -12.83mA
-703mV    -12.11mA   -10.54mA   -12.17mA
-483.3mV  -10.4mA    -9.967mA   -10.65mA
747mV     15.26mA    14.2mA     16.34mA
1.098V    19.2mA     17.63mA    20.82mA
1.582V    20.88mA    18.98mA    22.67mA
1.889V    18.72mA    15.63mA    21.96mA
2.197V    14.84mA    5.1mA      17.77mA
2.329V    10.1mA     3.3mA      16.33mA
2.461V    5.3mA      2.3mA      14.2mA
2.68V     2.8mA      1.8mA      6.5mA
[Pullup]
-1.33V    2.4mA      1.652mA    3.207mA
-1.023V   9.8mA      3.767mA    14.27mA
-890.9mV  16.12mA    6.487mA    16.51mA
-715.1mV  17.65mA    13.35mA    17.35mA
-451.5mV  14.98mA    13.54mA    15.46mA
295.4mV   -8.125mA   -7.33mA    -8.961mA
910.6mV   -16.72mA   -15.16mA   -18.95mA
1.702V    -18.92mA   -16.49mA   -22.15mA
1.965V    -17.33mA   -14.42mA   -20.77mA
2.185V    -16.38mA   -8.675mA   -19.82mA
2.361V    -10.4mA    -6.59mA    -19.39mA
2.668V    -6.3mA     -5.3mA     -8.693mA
[Ramp]
R_load=50.000Ohm
dV/dt_r   396.390mV/113.000ps  366.051mV/142.000ps  434.790mV/94.000ps
dV/dt_f   396.390mV/131.000ps  366.021mV/158.500ps  434.790mV/105.000ps
[Rising waveform]
R_fixture=50.000Ohm
V_fixture=1.350
V_fixture_min=1.283
V_fixture_max=1.450
0s        698.7mV    682.8mV    747.2mV
39ps      711.7mV    680.2mV    778.2mV
68ps      763.2mV    678mV      917.7mV
125ps     1.029V     674.9mV    1.269V
163ps     1.187V     677.3mV    1.371V
202ps     1.273V     691.6mV    1.416V
259ps     1.324V     773.8mV    1.44V
374ps     1.347V     1.147V     1.449V
432ps     1.349V     1.229V     1.45V
938ps     1.35V      1.283V     1.45V
[Rising waveform]
R_fixture=50.000Ohm
V_fixture=0
0s        77.11mV    65.59mV    104.2mV
48ps      76.05mV    65.49mV    120mV
87ps      128.2mV    64.71mV    263.6mV
135ps     281.3mV    61.99mV    504.5mV
173ps     422.9mV    58.35mV    644.4mV
269ps     648.8mV    89.39mV    805.9mV
432ps     745.9mV    464.9mV    854.8mV
527ps     756mV      600.4mV    859.6mV
671ps     760mV      667.4mV    861.8mV
938ps     761.8mV    686mV      862.2mV
[Falling waveform]
R_fixture=50.000Ohm
V_fixture=1.350
V_fixture_min=1.283
V_fixture_max=1.450
0s        1.354V     1.282V     1.453V
48ps      1.362V     1.282V     1.444V
96ps      1.317V     1.283V     1.306V
192ps     1.055V     1.295V     955.7mV
288ps     844.8mV    1.243V     808.3mV
345ps     780.6mV    1.133V     779.1mV
451ps     731.7mV    908.5mV    760.6mV
547ps     717.2mV    782.4mV    756.7mV
681ps     711mV      716.3mV    755.4mV
938ps     709mV      689.7mV    754.9mV
[Falling waveform]
R_fixture=50.000Ohm
V_fixture=0
0s        773mV      687.7mV    869.6mV
29ps      761.9mV    688.8mV    852.2mV
48ps      732.6mV    690.3mV    791.9mV
106ps     503.2mV    698.1mV    425.4mV
135ps     366.6mV    701.3mV    293.4mV
211ps     165.9mV    658.9mV    153.1mV
345ps     93.15mV    252.6mV    112.7mV
422ps     85.91mV    128.3mV    109.4mV
566ps     82.48mV    75.77mV    108.4mV
938ps     81.91mV    65.38mV    108.2mV
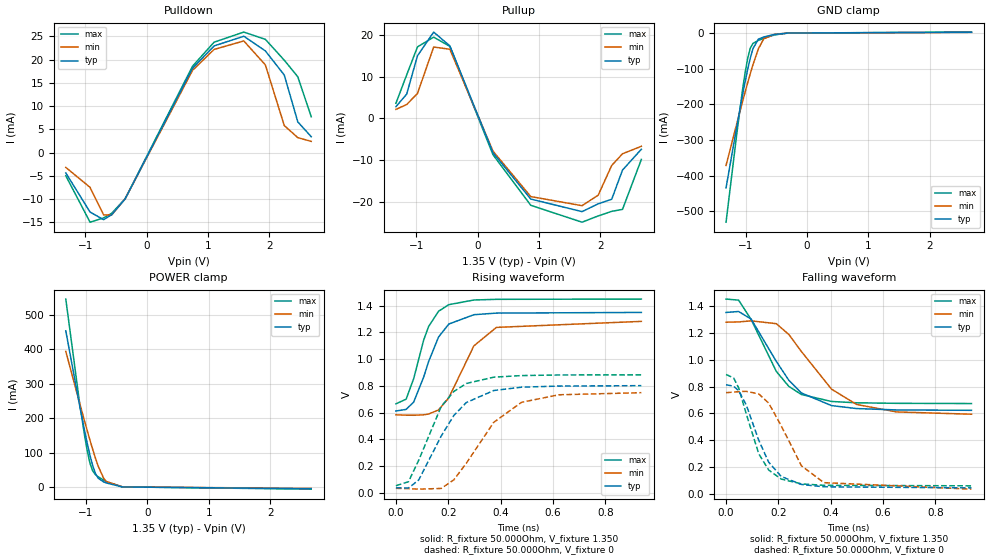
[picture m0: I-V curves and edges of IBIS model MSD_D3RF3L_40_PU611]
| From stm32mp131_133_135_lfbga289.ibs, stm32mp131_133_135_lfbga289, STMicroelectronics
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[Model] MSD_D3RF3L_40_PU611
Model_type   I/O
C_comp 2.442pF   2.357pF   2.567pF
Vinh = 810.000mV
Vinl = 540.000mV
Vmeas = 675.000mV
Vref = 675.000mV
[Model Spec]
Vinh   810.000mV   777.000mV   860.000mV
Vinl   540.000mV   507.000mV   590.000mV
Vmeas   675.000mV   642.000mV   725.000mV
Vref   675.000mV   642.000mV   725.000mV
[Receiver Thresholds]
Vth   =  0.675V
Vth_min  =  0.6615V
Vth_max  =  0.6885V
Vinh_ac  =  0.160V
Vinh_dc  =  0.090V
Vinl_ac  = -0.160V
Vinl_dc  = -0.090V
Tslew_ac =  5.000ns |Not specified, so set to high value
Threshold_sensitivity = 0.50
Reference_supply Pullup_ref
[Temperature Range]   25.000   125.000   -40.000
[Voltage Range]   1.350V   1.283V   1.450V
[GND Clamp Reference]   0.00V   0.00V   0.00V
[Pulldown Reference]   0.00V   0.00V   0.00V
[POWER Clamp Reference]   1.350V   1.283V   1.450V
[Pullup Reference]   1.350V   1.283V   1.450V
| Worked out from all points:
|   slope of the pulldown table from 0 to 0.203 V, typ, clamps not added: 35.7 ohm
|   slope of the pullup table from 0 to 0.203 V, typ, clamps not added: 29.7 ohm
|   GND clamp passes 1 mA (typ) near -0.40 V on its own axis
|   POWER clamp passes 1 mA (typ) near -0.41 V on its own axis
|   rising waveform, R_fixture 50.000Ohm, V_fixture 1.350: 20-80 % time 87.3ps typ, 109ps min, 74.3ps max; typ from 0.612 V to 1.35 V
|   rising waveform, R_fixture 50.000Ohm, V_fixture 0: 20-80 % time 137ps typ, 163ps min, 117ps max; typ from 0.038 V to 0.802 V
|   falling waveform, R_fixture 50.000Ohm, V_fixture 1.350: 20-80 % time 148ps typ, 177ps min, 129ps max; typ from 1.35 V to 0.623 V
|   falling waveform, R_fixture 50.000Ohm, V_fixture 0: 20-80 % time 98.3ps typ, 116ps min, 85.3ps max; typ from 0.814 V to 0.043 V
[GND Clamp]
-1.318V   -433.7mA   -371.1mA   -530mA
-1.142V   -261.4mA   -253.3mA   -281.2mA
-1.055V   -178.9mA   -195.8mA   -166mA
-1.011V   -139.7mA   -167.7mA   -114.9mA
-966.7mV  -102.9mA   -140.2mA   -71.99mA
-922.7mV  -70.02mA   -113.6mA   -42.32mA
-878.8mV  -43.37mA   -88.29mA   -28.9mA
-790.9mV  -17.22mA   -44.18mA   -20.7mA
-703mV    -11.06mA   -16.21mA   -14.99mA
-527.3mV  -4.011mA   -3.391mA   -5.355mA
-307.6mV  -127.4uA   -187.4uA   -115uA
2.68V     2.164mA    1.839mA    2.56mA
[Power Clamp]
-1.33V    453.1mA    393.6mA    545.2mA
-1.111V   242.6mA    247.9mA    251.6mA
-1.023V   162.8mA    190.9mA    148.7mA
-978.8mV  125.7mA    162.9mA    104.2mA
-934.9mV  91.62mA    135.6mA    68.68mA
-890.9mV  62.22mA    109.2mA    47.04mA
-847mV    39.86mA    84.29mA    36.52mA
-803mV    26.49mA    61.46mA    30.42mA
-715.1mV  15.8mA     26.67mA    20.89mA
-671.2mV  12.56mA    16.56mA    16.71mA
-407.6mV  931.1uA    1.216mA    1.127mA
2.668V    -4.266mA   -3.419mA   -5.488mA
[Pulldown]
-1.318V   -4.4mA     -3.2mA     -5mA
-922.7mV  -12.81mA   -7.5mA     -14.99mA
-703mV    -14.45mA   -13.41mA   -14.07mA
-571.2mV  -13.38mA   -13.44mA   -13.08mA
-351.5mV  -9.985mA   -9.958mA   -9.95mA
747mV     18.14mA    17.69mA    18.58mA
1.098V    22.94mA    22.18mA    23.74mA
1.582V    25.02mA    24.01mA    25.91mA
1.933V    21.86mA    18.84mA    24.35mA
2.241V    16.67mA    5.8mA      19.86mA
2.461V    6.6mA      3.2mA      16.3mA
2.68V     3.4mA      2.4mA      7.7mA
[Pullup]
-1.33V    2.8mA      2.152mA    3.607mA
-1.155V   5.8mA      3.31mA     10.41mA
-978.8mV  15mA       5.977mA    17.13mA
-715.1mV  20.68mA    17.1mA     19.47mA
-451.5mV  17.37mA    16.56mA    17.25mA
251.5mV   -8.25mA    -7.87mA    -8.719mA
866.7mV   -19.34mA   -18.75mA   -20.84mA
1.702V    -22.36mA   -20.93mA   -24.89mA
1.965V    -20.49mA   -18.41mA   -23.39mA
2.185V    -19.39mA   -11.29mA   -22.29mA
2.361V    -12.4mA    -8.49mA    -21.82mA
2.668V    -7.4mA     -6.7mA     -9.848mA
[Ramp]
R_load=50.000Ohm
dV/dt_r   445.986mV/112.500ps  422.916mV/137.000ps  480.276mV/96.000ps
dV/dt_f   445.986mV/124.000ps  422.916mV/148.000ps  480.276mV/107.000ps
[Rising waveform]
R_fixture=50.000Ohm
V_fixture=1.350
V_fixture_min=1.283
V_fixture_max=1.450
0s        612.2mV    583.8mV    665.8mV
39ps      624.4mV    581.2mV    700.9mV
68ps      679.4mV    580.5mV    855.3mV
106ps     865.7mV    583.9mV    1.143V
125ps     983mV      589.7mV    1.245V
163ps     1.166V     620.3mV    1.359V
202ps     1.263V     711mV      1.408V
298ps     1.333V     1.1V       1.443V
384ps     1.345V     1.238V     1.448V
938ps     1.35V      1.283V     1.45V
[Rising waveform]
R_fixture=50.000Ohm
V_fixture=0
0s        37.51mV    33.66mV    53.09mV
48ps      36.12mV    31.4mV     83.21mV
87ps      95.81mV    27.43mV    243.5mV
173ps     424.6mV    32.93mV    646.1mV
221ps     578.2mV    96.75mV    758.1mV
269ps     675.8mV    221.4mV    818.2mV
374ps     765.8mV    527.9mV    865.5mV
480ps     790.5mV    677.4mV    877.5mV
623ps     798.9mV    733.7mV    882mV
938ps     802mV      749.5mV    882.9mV
[Falling waveform]
R_fixture=50.000Ohm
V_fixture=1.350
V_fixture_min=1.283
V_fixture_max=1.450
0s        1.355V     1.282V     1.455V
48ps      1.362V     1.284V     1.447V
96ps      1.305V     1.292V     1.302V
192ps     989mV      1.271V     914.3mV
240ps     847.6mV    1.19V      801.8mV
288ps     752.9mV    1.063V     741.3mV
403ps     658.4mV    781.5mV    689.2mV
499ps     636.1mV    666.7mV    679.3mV
652ps     625.9mV    610.9mV    675.3mV
938ps     623mV      593.9mV    673.8mV
[Falling waveform]
R_fixture=50.000Ohm
V_fixture=0
0s        814.5mV    755.1mV    891.3mV
29ps      803.1mV    759.4mV    865.1mV
48ps      770.2mV    762.5mV    792.1mV
77ps      664.4mV    765.1mV    598.1mV
125ps     399mV      745.7mV    297.8mV
163ps     235.3mV    677.1mV    176.3mV
211ps     128.1mV    506.9mV    108.9mV
288ps     68.59mV    208.6mV    72.87mV
374ps     51.07mV    82.15mV    62.13mV
938ps     43.01mV    33.42mV    58.39mV
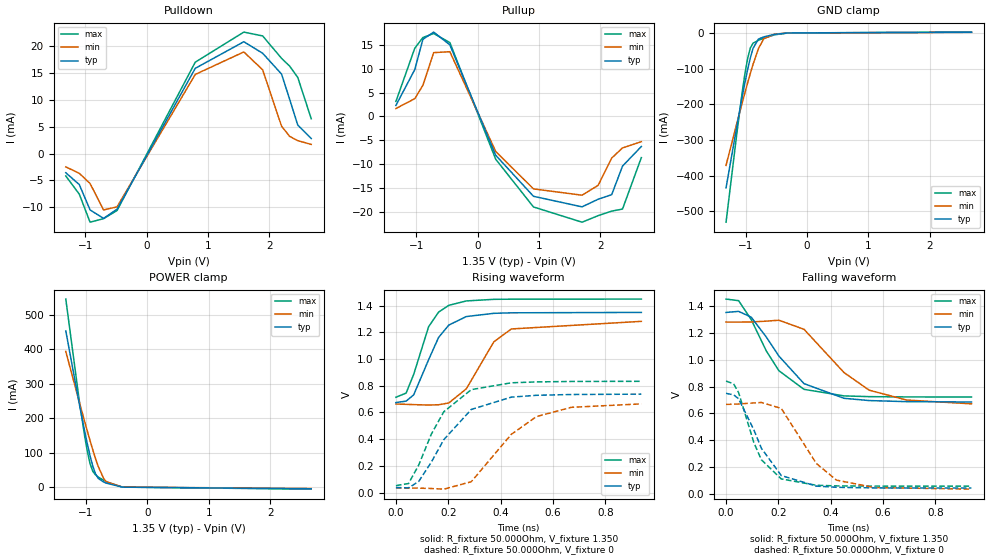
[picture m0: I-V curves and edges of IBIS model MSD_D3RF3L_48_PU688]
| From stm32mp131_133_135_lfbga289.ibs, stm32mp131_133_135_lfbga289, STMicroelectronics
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[Model] MSD_D3RF3L_48_PU688
Model_type   I/O
C_comp 2.455pF   2.369pF   2.579pF
Vinh = 810.000mV
Vinl = 540.000mV
Vmeas = 675.000mV
Vref = 675.000mV
[Model Spec]
Vinh   810.000mV   777.000mV   860.000mV
Vinl   540.000mV   507.000mV   590.000mV
Vmeas   675.000mV   642.000mV   725.000mV
Vref   675.000mV   642.000mV   725.000mV
[Receiver Thresholds]
Vth   =  0.675V
Vth_min  =  0.6615V
Vth_max  =  0.6885V
Vinh_ac  =  0.160V
Vinh_dc  =  0.090V
Vinl_ac  = -0.160V
Vinl_dc  = -0.090V
Tslew_ac =  5.000ns |Not specified, so set to high value
Threshold_sensitivity = 0.50
Reference_supply Pullup_ref
[Temperature Range]   25.000   125.000   -40.000
[Voltage Range]   1.350V   1.283V   1.450V
[GND Clamp Reference]   0.00V   0.00V   0.00V
[Pulldown Reference]   0.00V   0.00V   0.00V
[POWER Clamp Reference]   1.350V   1.283V   1.450V
[Pullup Reference]   1.350V   1.283V   1.450V
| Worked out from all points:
|   slope of the pulldown table from 0 to 0.203 V, typ, clamps not added: 42.2 ohm
|   slope of the pullup table from 0 to 0.203 V, typ, clamps not added: 34.5 ohm
|   GND clamp passes 1 mA (typ) near -0.40 V on its own axis
|   POWER clamp passes 1 mA (typ) near -0.41 V on its own axis
|   rising waveform, R_fixture 50.000Ohm, V_fixture 1.350: 20-80 % time 92.8ps typ, 116ps min, 78.3ps max; typ from 0.674 V to 1.35 V
|   rising waveform, R_fixture 50.000Ohm, V_fixture 0: 20-80 % time 149ps typ, 180ps min, 127ps max; typ from 0.038 V to 0.738 V
|   falling waveform, R_fixture 50.000Ohm, V_fixture 1.350: 20-80 % time 163ps typ, 195ps min, 131ps max; typ from 1.35 V to 0.685 V
|   falling waveform, R_fixture 50.000Ohm, V_fixture 0: 20-80 % time 106ps typ, 124ps min, 87.7ps max; typ from 0.749 V to 0.042 V
[GND Clamp]
-1.318V   -433.9mA   -371.1mA   -530.2mA
-1.142V   -261.5mA   -253.4mA   -281.4mA
-1.055V   -179mA     -195.9mA   -166.2mA
-1.011V   -139.7mA   -167.8mA   -115mA
-966.7mV  -103mA     -140.2mA   -72.1mA
-922.7mV  -70.1mA    -113.7mA   -42.42mA
-878.8mV  -43.45mA   -88.35mA   -28.99mA
-790.9mV  -17.28mA   -44.22mA   -20.77mA
-703mV    -11.1mA    -16.24mA   -15.04mA
-527.3mV  -4.032mA   -3.409mA   -5.385mA
-307.6mV  -129uA     -188.8uA   -119.4uA
2.68V     1.923mA    1.635mA    2.275mA
[Power Clamp]
-1.33V    453.3mA    393.7mA    545.4mA
-1.111V   242.7mA    248mA      251.8mA
-1.023V   163mA      191mA      148.9mA
-978.8mV  125.8mA    163mA      104.3mA
-934.9mV  91.7mA     135.6mA    68.79mA
-890.9mV  62.29mA    109.3mA    47.13mA
-847mV    39.94mA    84.35mA    36.61mA
-803mV    26.56mA    61.51mA    30.49mA
-715.1mV  15.84mA    26.7mA     20.95mA
-671.2mV  12.6mA     16.6mA     16.77mA
-407.6mV  937.9uA    1.223mA    1.135mA
2.668V    -3.791mA   -3.04mA    -4.872mA
[Pulldown]
-1.318V   -3.6mA     -2.5mA     -4.2mA
-1.098V   -5.8mA     -3.7mA     -7.6mA
-922.7mV  -10.54mA   -5.6mA     -12.83mA
-703mV    -12.12mA   -10.54mA   -12.17mA
-483.3mV  -10.4mA    -9.967mA   -10.65mA
790.9mV   15.91mA    14.77mA    17.06mA
1.582V    20.88mA    18.97mA    22.68mA
1.889V    18.72mA    15.63mA    21.96mA
2.197V    14.83mA    5.1mA      17.77mA
2.329V    10.1mA     3.2mA      16.32mA
2.461V    5.3mA      2.4mA      14.2mA
2.68V     2.8mA      1.7mA      6.5mA
[Pullup]
-1.33V    2.3mA      1.652mA    3.135mA
-1.023V   9.8mA      3.715mA    14.27mA
-890.9mV  16.12mA    6.508mA    16.51mA
-715.1mV  17.65mA    13.35mA    17.35mA
-451.5mV  14.98mA    13.54mA    15.46mA
295.4mV   -8.125mA   -7.329mA   -8.964mA
910.6mV   -16.72mA   -15.17mA   -18.95mA
1.702V    -18.93mA   -16.49mA   -22.14mA
1.965V    -17.33mA   -14.42mA   -20.77mA
2.185V    -16.38mA   -8.718mA   -19.82mA
2.361V    -10.4mA    -6.595mA   -19.39mA
2.668V    -6.3mA     -5.295mA   -8.621mA
[Ramp]
R_load=50.000Ohm
dV/dt_r   408.555mV/121.000ps  375.246mV/149.500ps  451.890mV/102.500ps
dV/dt_f   408.555mV/135.000ps  375.213mV/162.500ps  451.890mV/109.500ps
[Rising waveform]
R_fixture=50.000Ohm
V_fixture=1.350
V_fixture_min=1.283
V_fixture_max=1.450
0s        674.2mV    663.6mV    714.2mV
39ps      685.4mV    661.1mV    745.5mV
68ps      732.6mV    659mV      886.1mV
125ps     995.9mV    655.8mV    1.243V
163ps     1.162V     657.9mV    1.352V
202ps     1.255V     671.4mV    1.403V
269ps     1.319V     777.3mV    1.436V
374ps     1.343V     1.129V     1.448V
441ps     1.347V     1.226V     1.449V
938ps     1.35V      1.283V     1.45V
[Rising waveform]
R_fixture=50.000Ohm
V_fixture=0
0s        37.61mV    33.86mV    51.84mV
48ps      35.16mV    33.87mV    67.52mV
87ps      83.03mV    33.16mV    205.4mV
135ps     226.8mV    30.4mV     436.8mV
183ps     396.5mV    25.47mV    605.6mV
288ps     622.9mV    81.25mV    771.4mV
441ps     715.2mV    436.4mV    822.6mV
537ps     728.9mV    569.3mV    829.2mV
671ps     734.8mV    638.9mV    832.6mV
938ps     737.5mV    664.5mV    833.6mV
[Falling waveform]
R_fixture=50.000Ohm
V_fixture=1.350
V_fixture_min=1.283
V_fixture_max=1.450
0s        1.354V     1.282V     1.454V
48ps      1.362V     1.282V     1.442V
96ps      1.319V     1.283V     1.301V
154ps     1.17V      1.289V     1.066V
202ps     1.028V     1.296V     918.5mV
298ps     822mV      1.228V     779.4mV
451ps     712.5mV    904.6mV    730.5mV
547ps     695.6mV    773.1mV    724.9mV
690ps     687.5mV    699.6mV    722.8mV
938ps     684.8mV    671.2mV    721.9mV
[Falling waveform]
R_fixture=50.000Ohm
V_fixture=0
0s        749.4mV    667.2mV    841.4mV
29ps      738.4mV    668.3mV    820.3mV
48ps      708.9mV    669.9mV    755.3mV
106ps     477.9mV    678mV      383.1mV
135ps     339.6mV    681.3mV    253.2mV
211ps     135.4mV    637.1mV    110.1mV
345ps     56.49mV    225.7mV    62.73mV
422ps     47.51mV    101.2mV    58.01mV
566ps     42.94mV    45.73mV    56.23mV
938ps     42.08mV    33.58mV    55.89mV
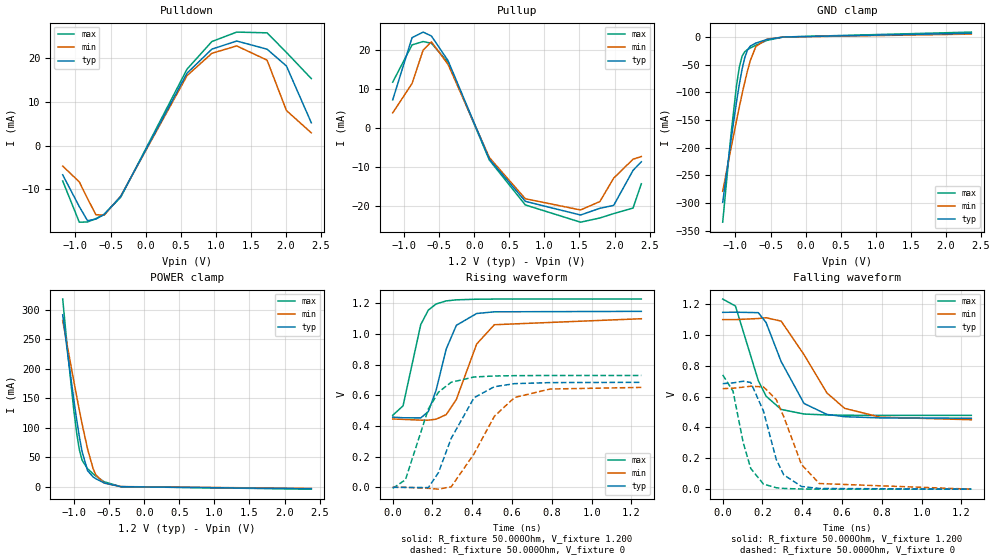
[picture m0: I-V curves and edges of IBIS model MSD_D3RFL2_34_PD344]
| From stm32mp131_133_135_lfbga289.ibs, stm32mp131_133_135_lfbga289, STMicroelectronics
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[Model] MSD_D3RFL2_34_PD344
Model_type   I/O
C_comp 2.341pF   2.257pF   2.465pF
Vinh = 820.000mV
Vinl = 380.000mV
Vmeas = 600.000mV
Vref = 600.000mV
[Model Spec]
Vinh   820.000mV   790.000mV   870.000mV
Vinl   380.000mV   350.000mV   430.000mV
Vmeas   600.000mV   570.000mV   650.000mV
Vref   600.000mV   570.000mV   650.000mV
[Receiver Thresholds]
Vth   =  0.600V
Vth_min  =  0.5880V
Vth_max  =  0.6120V
Vinh_ac  =  0.220V
Vinh_dc  =  0.130V
Vinl_ac  = -0.220V
Vinl_dc  = -0.130V
Tslew_ac =  5.000ns |Not specified, so set to high value
[Temperature Range]   25.000   125.000   -40.000
[Voltage Range]   1.200V   1.140V   1.300V
[GND Clamp Reference]   0.00V   0.00V   0.00V
[Pulldown Reference]   0.00V   0.00V   0.00V
[POWER Clamp Reference]   1.200V   1.140V   1.300V
[Pullup Reference]   1.200V   1.140V   1.300V
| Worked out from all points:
|   slope of the pulldown table from 0 to 0.18 V, typ, clamps not added: 31.3 ohm
|   slope of the pullup table from 0 to 0.18 V, typ, clamps not added: 26.5 ohm
|   GND clamp passes 1 mA (typ) near -0.40 V on its own axis
|   POWER clamp passes 1 mA (typ) near -0.42 V on its own axis
|   rising waveform, R_fixture 50.000Ohm, V_fixture 1.200: 20-80 % time 89.5ps typ, 116ps min, 76.4ps max; typ from 0.458 V to 1.15 V
|   rising waveform, R_fixture 50.000Ohm, V_fixture 0: 20-80 % time 141ps typ, 173ps min, 120ps max; typ from 0.001 V to 0.684 V
|   falling waveform, R_fixture 50.000Ohm, V_fixture 1.200: 20-80 % time 139ps typ, 186ps min, 113ps max; typ from 1.15 V to 0.459 V
|   falling waveform, R_fixture 50.000Ohm, V_fixture 0: 20-80 % time 91.5ps typ, 118ps min, 77.6ps max; typ from 0.683 V to 0 V
[GND Clamp]
-1.182V   -298.7mA   -278.9mA   -334.7mA
-1.064V   -186.5mA   -201.2mA   -176.5mA
-984.9mV  -117.2mA   -151.1mA   -87.71mA
-945.5mV  -85.91mA   -126.8mA   -54.95mA
-906.1mV  -58.56mA   -103.4mA   -34.88mA
-866.7mV  -37.08mA   -81.29mA   -26.52mA
-827.3mV  -23.32mA   -60.76mA   -22.77mA
-787.9mV  -16.51mA   -42.62mA   -20mA
-709.1mV  -11.08mA   -17.24mA   -14.98mA
-551.5mV  -4.681mA   -3.974mA   -6.287mA
-315.1mV  -154.2uA   -220.1uA   -140.9uA
2.364V    6.653mA    5.111mA    8.718mA
[Power Clamp]
-1.164V   291.4mA    281.7mA    318.1mA
-1.085V   217.8mA    230mA      219mA
-1.006V   147.7mA    179.3mA    130.2mA
-966.7mV  115.2mA    154.5mA    92.47mA
-927.3mV  85.46mA    130.3mA    63.19mA
-887.9mV  59.77mA    106.8mA    45.13mA
-809.1mV  27.31mA    63.82mA    30.53mA
-730.3mV  16.63mA    30.75mA    21.92mA
-690.9mV  13.57mA    19.97mA    18.11mA
-572.7mV  6.421mA    6.328mA    8.512mA
-336.4mV  165.6uA    318.9uA    193uA
2.382V    -3.424mA   -2.825mA   -4.062mA
[Pulldown]
-1.182V   -6.7mA     -4.7mA     -8.1mA
-945.5mV  -13.95mA   -8.3mA     -17.52mA
-827.3mV  -17.19mA   -12.14mA   -17.47mA
-709.1mV  -16.81mA   -15.8mA    -16.7mA
-590.9mV  -15.77mA   -15.93mA   -15.69mA
-354.6mV  -11.64mA   -11.56mA   -11.82mA
590.9mV   16.53mA    15.97mA    17.46mA
945.5mV   22.03mA    21.08mA    23.77mA
1.3V      23.89mA    22.77mA    25.93mA
1.733V    22.02mA    19.52mA    25.76mA
2.009V    18.18mA    8mA        21.28mA
2.364V    5.2mA      2.9mA      15.3mA
[Pullup]
-1.164V   7.3mA      3.962mA    11.85mA
-887.9mV  23.28mA    11.5mA     21.41mA
-730.3mV  24.7mA     20.07mA    22.27mA
-612.1mV  23.69mA    22.22mA    21.83mA
-375.8mV  17.4mA     16.45mA    16.97mA
215.2mV   -7.945mA   -7.529mA   -8.167mA
727.3mV   -18.75mA   -18.09mA   -19.68mA
1.515V    -22.27mA   -20.97mA   -24.11mA
1.791V    -20.54mA   -18.81mA   -23.03mA
1.988V    -19.79mA   -12.79mA   -21.9mA
2.264V    -10.8mA    -7.943mA   -20.48mA
2.382V    -8.6mA     -7.248mA   -14.24mA
[Ramp]
R_load=50.000Ohm
dV/dt_r   411.240mV/115.500ps  390.419mV/145.500ps  443.010mV/98.500ps
dV/dt_f   411.240mV/116.000ps  390.389mV/153.000ps  443.010mV/95.000ps
[Rising waveform]
R_fixture=50.000Ohm
V_fixture=1.200
V_fixture_min=1.140
V_fixture_max=1.300
0s        457.5mV    445.6mV    469.1mV
52ps      453.4mV    443mV      531mV
141ps     452.5mV    437.9mV    1.06V
179ps     493.4mV    437.9mV    1.154V
218ps     631.6mV    444mV      1.194V
269ps     900.7mV    473.9mV    1.214V
320ps     1.055V     572.7mV    1.221V
422ps     1.132V     933.1mV    1.225V
511ps     1.143V     1.059V     1.226V
1.25ns    1.146V     1.098V     1.226V
[Rising waveform]
R_fixture=50.000Ohm
V_fixture=0
0s        900.1uV    877.4uV    -5.978mV
64ps      -175uV     774.4uV    49.85mV
179ps     -1.251mV   -6.028mV   510mV
230ps     96.16mV    -11.4mV    619.9mV
294ps     319.2mV    4.025mV    684.4mV
409ps     584mV      218.6mV    718.8mV
511ps     655.5mV    463mV      725.3mV
613ps     675.5mV    585.6mV    727.4mV
792ps     682.2mV    640.5mV    728.6mV
1.25ns    684mV      651mV      728.8mV
[Falling waveform]
R_fixture=50.000Ohm
V_fixture=1.200
V_fixture_min=1.140
V_fixture_max=1.300
0s        1.145V     1.098V     1.231V
64ps      1.146V     1.098V     1.186V
179ps     1.143V     1.105V     702.8mV
218ps     1.079V     1.11V      602.1mV
294ps     825.8mV    1.088V     516.3mV
409ps     554.8mV    870.7mV    486.6mV
524ps     484mV      623.1mV    480.3mV
613ps     469.2mV    523.1mV    478.6mV
792ps     461.5mV    466.1mV    477.8mV
1.25ns    459.2mV    449.6mV    477.7mV
[Falling waveform]
R_fixture=50.000Ohm
V_fixture=0
0s        683.4mV    650.9mV    740mV
52ps      688.4mV    653.7mV    634.2mV
103ps     699mV      660.5mV    301.7mV
141ps     691mV      666.4mV    134.1mV
205ps     505.4mV    662.1mV    32.62mV
269ps     193.3mV    580.2mV    9.38mV
307ps     92.61mV    469.3mV    4.701mV
396ps     17.39mV    159.6mV    950uV
486ps     4.397mV    36.51mV    193.6uV
1.25ns    1.095uV    19.35uV    0V
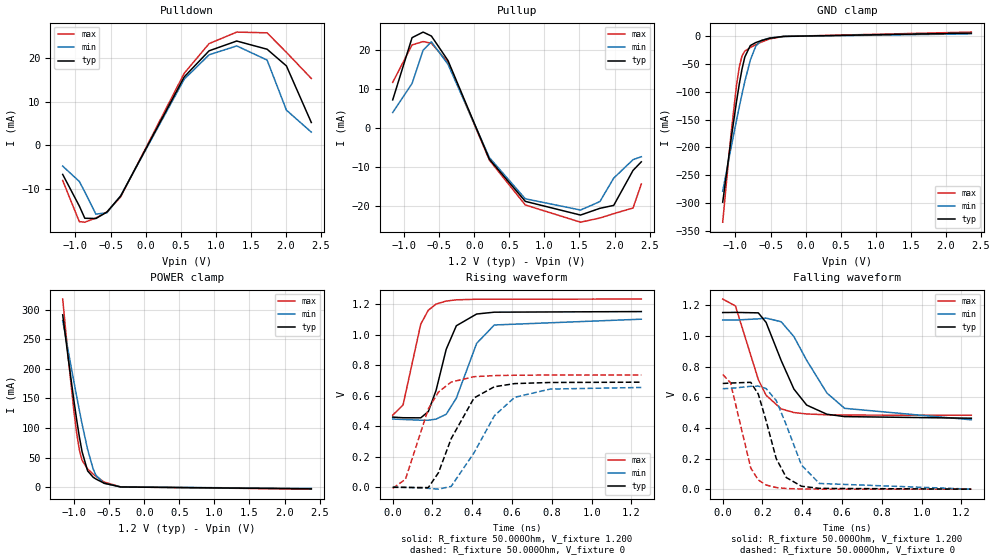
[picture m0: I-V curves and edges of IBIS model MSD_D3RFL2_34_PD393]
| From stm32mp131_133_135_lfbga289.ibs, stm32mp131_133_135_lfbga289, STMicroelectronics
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[Model] MSD_D3RFL2_34_PD393
Model_type   I/O
C_comp 2.371pF   2.287pF   2.495pF
Vinh = 820.000mV
Vinl = 380.000mV
Vmeas = 600.000mV
Vref = 600.000mV
[Model Spec]
Vinh   820.000mV   790.000mV   870.000mV
Vinl   380.000mV   350.000mV   430.000mV
Vmeas   600.000mV   570.000mV   650.000mV
Vref   600.000mV   570.000mV   650.000mV
[Receiver Thresholds]
Vth   =  0.600V
Vth_min  =  0.5880V
Vth_max  =  0.6120V
Vinh_ac  =  0.220V
Vinh_dc  =  0.130V
Vinl_ac  = -0.220V
Vinl_dc  = -0.130V
Tslew_ac =  5.000ns |Not specified, so set to high value
[Temperature Range]   25.000   125.000   -40.000
[Voltage Range]   1.200V   1.140V   1.300V
[GND Clamp Reference]   0.00V   0.00V   0.00V
[Pulldown Reference]   0.00V   0.00V   0.00V
[POWER Clamp Reference]   1.200V   1.140V   1.300V
[Pullup Reference]   1.200V   1.140V   1.300V
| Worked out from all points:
|   slope of the pulldown table from 0 to 0.18 V, typ, clamps not added: 31.3 ohm
|   slope of the pullup table from 0 to 0.18 V, typ, clamps not added: 26.5 ohm
|   GND clamp passes 1 mA (typ) near -0.40 V on its own axis
|   POWER clamp passes 1 mA (typ) near -0.42 V on its own axis
|   rising waveform, R_fixture 50.000Ohm, V_fixture 1.200: 20-80 % time 90ps typ, 116ps min, 76.5ps max; typ from 0.461 V to 1.15 V
|   rising waveform, R_fixture 50.000Ohm, V_fixture 0: 20-80 % time 142ps typ, 174ps min, 122ps max; typ from 0.001 V to 0.69 V
|   falling waveform, R_fixture 50.000Ohm, V_fixture 1.200: 20-80 % time 141ps typ, 187ps min, 116ps max; typ from 1.15 V to 0.463 V
|   falling waveform, R_fixture 50.000Ohm, V_fixture 0: 20-80 % time 92.5ps typ, 119ps min, 78.7ps max; typ from 0.689 V to 0 V
[GND Clamp]
-1.182V   -298.9mA   -279mA     -334.9mA
-1.064V   -186.7mA   -201.4mA   -176.7mA
-984.9mV  -117.4mA   -151.2mA   -87.93mA
-945.5mV  -86.07mA   -127mA     -55.15mA
-906.1mV  -58.69mA   -103.6mA   -35.07mA
-866.7mV  -37.21mA   -81.39mA   -26.69mA
-787.9mV  -16.61mA   -42.71mA   -20.15mA
-709.1mV  -11.16mA   -17.31mA   -15.09mA
-630.3mV  -7.681mA   -7.385mA   -10.44mA
-512.1mV  -3.463mA   -2.956mA   -4.587mA
-315.1mV  -156.4uA   -222.4uA   -144.7uA
2.364V    5.825mA    4.473mA    7.624mA
[Power Clamp]
-1.164V   291.7mA    281.8mA    318.4mA
-1.085V   218mA      230.2mA    219.3mA
-1.006V   147.9mA    179.5mA    130.4mA
-966.7mV  115.4mA    154.7mA    92.71mA
-927.3mV  85.63mA    130.4mA    63.4mA
-887.9mV  59.94mA    106.9mA    45.32mA
-809.1mV  27.44mA    63.95mA    30.69mA
-730.3mV  16.73mA    30.86mA    22.05mA
-690.9mV  13.67mA    20.06mA    18.23mA
-572.7mV  6.475mA    6.385mA    8.584mA
-336.4mV  171uA      329.6uA    200.9uA
2.382V    -2.997mA   -2.472mA   -3.554mA
[Pulldown]
-1.182V   -6.7mA     -4.8mA     -8.1mA
-945.5mV  -13.93mA   -8.3mA     -17.52mA
-866.7mV  -16.75mA   -10.69mA   -17.65mA
-709.1mV  -16.81mA   -15.8mA    -16.7mA
-551.5mV  -15.33mA   -15.49mA   -15.28mA
-354.6mV  -11.64mA   -11.57mA   -11.82mA
551.5mV   15.67mA    15.15mA    16.51mA
906.1mV   21.65mA    20.73mA    23.3mA
1.3V      23.89mA    22.77mA    25.94mA
1.733V    22.01mA    19.53mA    25.77mA
2.009V    18.18mA    8.04mA     21.29mA
2.364V    5.2mA      3mA        15.3mA
[Pullup]
-1.164V   7.3mA      4.062mA    11.8mA
-887.9mV  23.28mA    11.52mA    21.42mA
-730.3mV  24.71mA    20.06mA    22.27mA
-612.1mV  23.69mA    22.22mA    21.84mA
-375.8mV  17.41mA    16.45mA    16.97mA
215.2mV   -7.945mA   -7.528mA   -8.168mA
727.3mV   -18.75mA   -18.09mA   -19.68mA
1.515V    -22.27mA   -20.98mA   -24.1mA
1.791V    -20.54mA   -18.81mA   -23.03mA
1.988V    -19.79mA   -12.79mA   -21.91mA
2.264V    -10.8mA    -8.043mA   -20.45mA
2.382V    -8.6mA     -7.295mA   -14.29mA
[Ramp]
R_load=50.000Ohm
dV/dt_r   413.940mV/116.500ps  392.459mV/146.000ps  446.760mV/98.500ps
dV/dt_f   413.940mV/117.500ps  392.429mV/154.500ps  446.760mV/97.000ps
[Rising waveform]
R_fixture=50.000Ohm
V_fixture=1.200
V_fixture_min=1.140
V_fixture_max=1.300
0s        460.9mV    448.2mV    473.6mV
52ps      456.8mV    445.5mV    540.3mV
141ps     456.1mV    440.5mV    1.071V
179ps     497.3mV    440.7mV    1.162V
218ps     636.2mV    447.7mV    1.202V
269ps     905.8mV    479.8mV    1.222V
320ps     1.06V      585.3mV    1.23V
422ps     1.137V     944.5mV    1.234V
511ps     1.149V     1.065V     1.234V
1.25ns    1.153V     1.103V     1.235V
[Rising waveform]
R_fixture=50.000Ohm
V_fixture=0
0s        901uV      888.1uV    -6.226mV
64ps      -172.1uV   752.3uV    52.92mV
179ps     -1.275mV   -6.372mV   515mV
230ps     96.17mV    -11.61mV   625.3mV
294ps     319.7mV    6.637mV    690.6mV
409ps     586.7mV    227.1mV    726.1mV
511ps     659.9mV    469.6mV    733.2mV
613ps     680.7mV    590.5mV    735.5mV
792ps     688mV      644.9mV    736.8mV
1.25ns    689.9mV    655.4mV    736.9mV
[Falling waveform]
R_fixture=50.000Ohm
V_fixture=1.200
V_fixture_min=1.140
V_fixture_max=1.300
0s        1.152V     1.103V     1.24V
64ps      1.153V     1.103V     1.195V
179ps     1.15V      1.111V     714.7mV
218ps     1.088V     1.116V     612.6mV
294ps     839.1mV    1.092V     523.7mV
358ps     652.9mV    995.2mV    499.8mV
422ps     548.5mV    840.9mV    490.6mV
524ps     488.7mV    627mV      485.1mV
613ps     473.3mV    527.2mV    483.2mV
1.25ns    462.8mV    452.4mV    482.3mV
[Falling waveform]
R_fixture=50.000Ohm
V_fixture=0
0s        689.3mV    655.3mV    748.1mV
39ps      692.2mV    657.3mV    694.7mV
141ps     696.9mV    671mV      138mV
179ps     619.7mV    672.3mV    59.93mV
218ps     447.2mV    656.4mV    27.11mV
269ps     199.6mV    578.6mV    10.51mV
320ps     75.6mV     417.9mV    4.3mV
396ps     19.13mV    157.1mV    1.149mV
486ps     5.112mV    37.16mV    256.1uV
1.25ns    1.634uV    20.53uV    0V
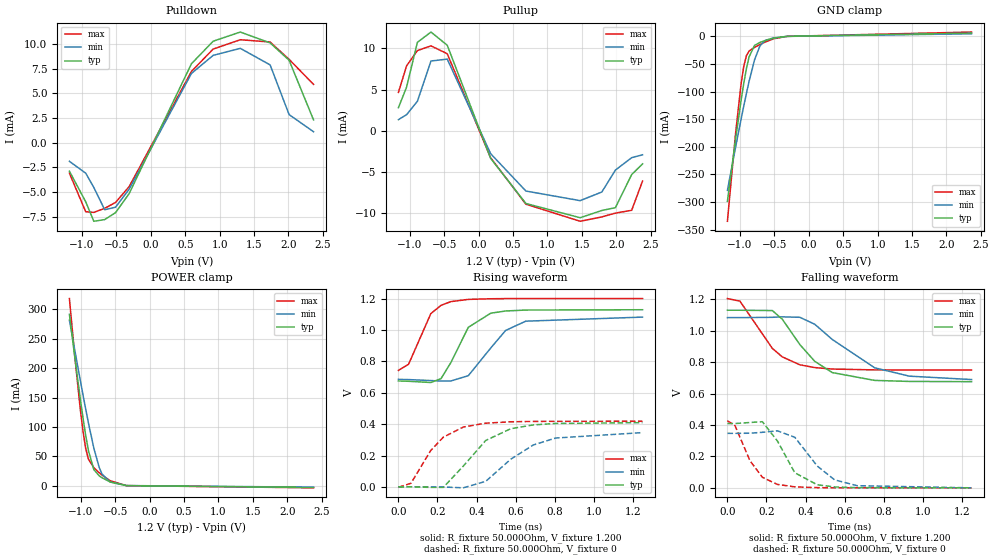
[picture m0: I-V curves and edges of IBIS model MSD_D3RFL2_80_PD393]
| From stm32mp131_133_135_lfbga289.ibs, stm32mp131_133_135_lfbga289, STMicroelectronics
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[Model] MSD_D3RFL2_80_PD393
Model_type   I/O
C_comp 2.371pF   2.287pF   2.495pF
Vinh = 820.000mV
Vinl = 380.000mV
Vmeas = 600.000mV
Vref = 600.000mV
[Model Spec]
Vinh   820.000mV   790.000mV   870.000mV
Vinl   380.000mV   350.000mV   430.000mV
Vmeas   600.000mV   570.000mV   650.000mV
Vref   600.000mV   570.000mV   650.000mV
[Receiver Thresholds]
Vth   =  0.600V
Vth_min  =  0.5880V
Vth_max  =  0.6120V
Vinh_ac  =  0.220V
Vinh_dc  =  0.130V
Vinl_ac  = -0.220V
Vinl_dc  = -0.130V
Tslew_ac =  5.000ns |Not specified, so set to high value
[Temperature Range]   25.000   125.000   -40.000
[Voltage Range]   1.200V   1.140V   1.300V
[GND Clamp Reference]   0.00V   0.00V   0.00V
[Pulldown Reference]   0.00V   0.00V   0.00V
[POWER Clamp Reference]   1.200V   1.140V   1.300V
[Pullup Reference]   1.200V   1.140V   1.300V
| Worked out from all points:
|   slope of the pulldown table from 0 to 0.18 V, typ, clamps not added: 63.6 ohm
|   slope of the pullup table from 0 to 0.18 V, typ, clamps not added: 52.8 ohm
|   GND clamp passes 1 mA (typ) near -0.40 V on its own axis
|   POWER clamp passes 1 mA (typ) near -0.42 V on its own axis
|   rising waveform, R_fixture 50.000Ohm, V_fixture 1.200: 20-80 % time 114ps typ, 149ps min, 98.8ps max; typ from 0.676 V to 1.13 V
|   rising waveform, R_fixture 50.000Ohm, V_fixture 0: 20-80 % time 182ps typ, 229ps min, 154ps max; typ from 0 V to 0.41 V
|   falling waveform, R_fixture 50.000Ohm, V_fixture 1.200: 20-80 % time 187ps typ, 263ps min, 166ps max; typ from 1.13 V to 0.676 V
|   falling waveform, R_fixture 50.000Ohm, V_fixture 0: 20-80 % time 111ps typ, 144ps min, 103ps max; typ from 0.409 V to 0 V
[GND Clamp]
-1.182V   -298.9mA   -279mA     -334.9mA
-1.064V   -186.7mA   -201.4mA   -176.7mA
-984.9mV  -117.4mA   -151.2mA   -87.93mA
-945.5mV  -86.07mA   -127mA     -55.15mA
-906.1mV  -58.69mA   -103.6mA   -35.07mA
-866.7mV  -37.21mA   -81.39mA   -26.69mA
-787.9mV  -16.61mA   -42.71mA   -20.15mA
-709.1mV  -11.16mA   -17.31mA   -15.09mA
-630.3mV  -7.681mA   -7.385mA   -10.44mA
-512.1mV  -3.463mA   -2.956mA   -4.587mA
-315.1mV  -156.4uA   -222.4uA   -144.7uA
2.364V    5.825mA    4.473mA    7.624mA
[Power Clamp]
-1.164V   291.7mA    281.8mA    318.4mA
-1.085V   218mA      230.2mA    219.3mA
-1.006V   147.9mA    179.5mA    130.4mA
-966.7mV  115.4mA    154.7mA    92.71mA
-927.3mV  85.63mA    130.4mA    63.4mA
-887.9mV  59.94mA    106.9mA    45.32mA
-809.1mV  27.44mA    63.95mA    30.69mA
-730.3mV  16.73mA    30.86mA    22.05mA
-690.9mV  13.67mA    20.06mA    18.23mA
-572.7mV  6.475mA    6.385mA    8.584mA
-336.4mV  171uA      329.6uA    200.9uA
2.382V    -2.997mA   -2.472mA   -3.554mA
[Pulldown]
-1.182V   -2.9mA     -1.9mA     -3.1mA
-945.5mV  -6mA       -3.1mA     -7.01mA
-827.3mV  -7.98mA    -4.55mA    -7.08mA
-669.7mV  -7.81mA    -6.81mA    -6.67mA
-512.1mV  -7.109mA   -6.555mA   -6.071mA
-315.1mV  -5.181mA   -4.738mA   -4.478mA
590.9mV   8.001mA    7.016mA    7.22mA
906.1mV   10.28mA    8.845mA    9.483mA
1.3V      11.21mA    9.557mA    10.43mA
1.733V    10.11mA    7.88mA     10.2mA
2.009V    8.35mA     2.84mA     8.44mA
2.364V    2.3mA      1.1mA      5.9mA
[Pullup]
-1.164V   2.8mA      1.352mA    4.654mA
-1.045V   5.3mA      1.957mA    7.869mA
-887.9mV  10.72mA    3.587mA    9.714mA
-690.9mV  11.96mA    8.455mA    10.29mA
-454.5mV  10.36mA    8.683mA    9.332mA
175.8mV   -3.334mA   -2.766mA   -3.264mA
687.9mV   -8.799mA   -7.289mA   -8.88mA
1.476V    -10.52mA   -8.453mA   -10.95mA
1.791V    -9.644mA   -7.404mA   -10.42mA
1.988V    -9.3mA     -4.754mA   -9.962mA
2.224V    -5.3mA     -3.248mA   -9.62mA
2.382V    -4mA       -2.9mA     -6.085mA
[Ramp]
R_load=50.000Ohm
dV/dt_r   259.200mV/148.500ps  223.439mV/191.000ps  260.940mV/127.000ps
dV/dt_f   259.200mV/150.500ps  223.470mV/206.500ps  260.940mV/134.500ps
[Rising waveform]
R_fixture=50.000Ohm
V_fixture=1.200
V_fixture_min=1.140
V_fixture_max=1.300
0s        675.6mV    685.7mV    743.3mV
52ps      673.5mV    684.4mV    781.9mV
166ps     665.8mV    678.1mV    1.105V
218ps     690mV      675mV      1.158V
269ps     793.6mV    675.5mV    1.182V
358ps     1.018V     709.4mV    1.196V
473ps     1.108V     886.2mV    1.2V
549ps     1.122V     997.9mV    1.201V
652ps     1.128V     1.057V     1.201V
1.25ns    1.13V      1.083V     1.201V
[Rising waveform]
R_fixture=50.000Ohm
V_fixture=0
0s        157.1uV    108.3uV    -2.662mV
64ps      580.8uV    378.7uV    22.66mV
166ps     -3.53mV    453.9uV    232.7mV
230ps     -3.43mV    -894uV     317mV
332ps     132.1mV    -6.275mV   381.3mV
447ps     295.9mV    35.03mV    406.2mV
575ps     370.8mV    176.1mV    415.1mV
690ps     395mV      266.9mV    417.4mV
805ps     404.5mV    311.5mV    418.1mV
1.25ns    409.7mV    346.1mV    418.5mV
[Falling waveform]
R_fixture=50.000Ohm
V_fixture=1.200
V_fixture_min=1.140
V_fixture_max=1.300
0s        1.13V      1.083V     1.204V
64ps      1.13V      1.083V     1.188V
230ps     1.128V     1.085V     887.5mV
281ps     1.073V     1.088V     833.1mV
371ps     911.4mV    1.085V     782.8mV
447ps     805.2mV    1.041V     765.2mV
537ps     733.3mV    944mV      755.8mV
754ps     683.5mV    763.7mV    750.4mV
932ps     677mV      710.5mV    749.9mV
1.25ns    675.6mV    689mV      749.8mV
[Falling waveform]
R_fixture=50.000Ohm
V_fixture=0
0s        409.2mV    346.8mV    426.7mV
39ps      409mV      346.6mV    395.8mV
115ps     415.7mV    347.5mV    173.4mV
179ps     420.8mV    353.4mV    67.21mV
256ps     298.2mV    362.7mV    21.69mV
345ps     96.06mV    321.9mV    6.211mV
460ps     19.41mV    138.7mV    1.192mV
549ps     5.658mV    50.64mV    276.1uV
664ps     1.123mV    13.71mV    48.32uV
1.25ns    -3.258uV   5.735uV    2.516uV
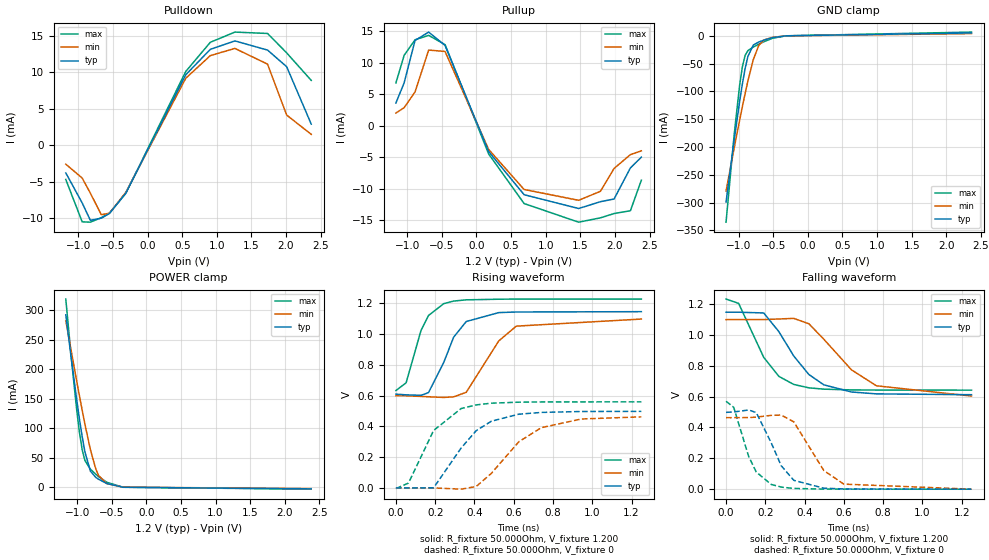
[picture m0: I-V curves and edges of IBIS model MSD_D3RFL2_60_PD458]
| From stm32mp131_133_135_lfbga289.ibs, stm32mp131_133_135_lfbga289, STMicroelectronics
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[Model] MSD_D3RFL2_60_PD458
Model_type   I/O
C_comp 2.402pF   2.316pF   2.526pF
Vinh = 820.000mV
Vinl = 380.000mV
Vmeas = 600.000mV
Vref = 600.000mV
[Model Spec]
Vinh   820.000mV   790.000mV   870.000mV
Vinl   380.000mV   350.000mV   430.000mV
Vmeas   600.000mV   570.000mV   650.000mV
Vref   600.000mV   570.000mV   650.000mV
[Receiver Thresholds]
Vth   =  0.600V
Vth_min  =  0.5880V
Vth_max  =  0.6120V
Vinh_ac  =  0.220V
Vinh_dc  =  0.130V
Vinl_ac  = -0.220V
Vinl_dc  = -0.130V
Tslew_ac =  5.000ns |Not specified, so set to high value
[Temperature Range]   25.000   125.000   -40.000
[Voltage Range]   1.200V   1.140V   1.300V
[GND Clamp Reference]   0.00V   0.00V   0.00V
[Pulldown Reference]   0.00V   0.00V   0.00V
[POWER Clamp Reference]   1.200V   1.140V   1.300V
[Pullup Reference]   1.200V   1.140V   1.300V
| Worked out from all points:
|   slope of the pulldown table from 0 to 0.18 V, typ, clamps not added: 50.1 ohm
|   slope of the pullup table from 0 to 0.18 V, typ, clamps not added: 42.9 ohm
|   GND clamp passes 1 mA (typ) near -0.40 V on its own axis
|   POWER clamp passes 1 mA (typ) near -0.41 V on its own axis
|   rising waveform, R_fixture 50.000Ohm, V_fixture 1.200: 20-80 % time 108ps typ, 139ps min, 90.1ps max; typ from 0.61 V to 1.15 V
|   rising waveform, R_fixture 50.000Ohm, V_fixture 0: 20-80 % time 178ps typ, 220ps min, 148ps max; typ from 0.001 V to 0.498 V
|   falling waveform, R_fixture 50.000Ohm, V_fixture 1.200: 20-80 % time 185ps typ, 235ps min, 145ps max; typ from 1.15 V to 0.612 V
|   falling waveform, R_fixture 50.000Ohm, V_fixture 0: 20-80 % time 109ps typ, 136ps min, 92.8ps max; typ from 0.497 V to 0 V
[GND Clamp]
-1.182V   -299.1mA   -279.3mA   -335.3mA
-1.064V   -187mA     -201.5mA   -177mA
-984.9mV  -117.6mA   -151.3mA   -88.16mA
-945.5mV  -86.22mA   -127.1mA   -55.37mA
-906.1mV  -58.84mA   -103.8mA   -35.26mA
-866.7mV  -37.35mA   -81.5mA    -26.87mA
-787.9mV  -16.73mA   -42.8mA    -20.29mA
-709.1mV  -11.25mA   -17.38mA   -15.2mA
-630.3mV  -7.745mA   -7.438mA   -10.54mA
-512.1mV  -3.498mA   -2.984mA   -4.633mA
-315.1mV  -158.7uA   -224.9uA   -147.6uA
2.364V    4.99mA     3.837mA    6.535mA
[Power Clamp]
-1.164V   292mA      282.1mA    318.7mA
-1.085V   218.3mA    230.5mA    219.6mA
-1.006V   148.1mA    179.7mA    130.7mA
-966.7mV  115.5mA    154.8mA    92.95mA
-927.3mV  85.81mA    130.6mA    63.61mA
-887.9mV  60.1mA     107.1mA    45.52mA
-809.1mV  27.58mA    64.08mA    30.85mA
-730.3mV  16.84mA    30.96mA    22.19mA
-690.9mV  13.77mA    20.14mA    18.34mA
-572.7mV  6.533mA    6.447mA    8.649mA
-336.4mV  178.2uA    339.3uA    207.6uA
2.382V    -2.569mA   -2.119mA   -3.047mA
[Pulldown]
-1.182V   -3.8mA     -2.6mA     -4.7mA
-945.5mV  -7.91mA    -4.5mA     -10.51mA
-827.3mV  -10.3mA    -6.57mA    -10.56mA
-669.7mV  -10.01mA   -9.53mA    -9.94mA
-551.5mV  -9.372mA   -9.334mA   -9.3mA
-315.1mV  -6.567mA   -6.464mA   -6.607mA
551.5mV   9.677mA    9.197mA    10.13mA
906.1mV   13.16mA    12.3mA     14.13mA
1.261V    14.32mA    13.29mA    15.53mA
1.733V    13.06mA    11.13mA    15.34mA
2.009V    10.78mA    4.14mA     12.68mA
2.364V    2.9mA      1.5mA      8.9mA
[Pullup]
-1.164V   3.6mA      2.005mA    6.785mA
-1.045V   6.8mA      2.857mA    11.16mA
-887.9mV  13.51mA    5.344mA    13.62mA
-690.9mV  14.84mA    11.99mA    14.32mA
-454.5mV  12.73mA    11.77mA    12.85mA
175.8mV   -4.108mA   -3.772mA   -4.491mA
687.9mV   -10.95mA   -10.12mA   -12.35mA
1.476V    -13.14mA   -11.84mA   -15.31mA
1.791V    -12.06mA   -10.41mA   -14.62mA
1.988V    -11.63mA   -6.784mA   -13.94mA
2.224V    -6.7mA     -4.595mA   -13.49mA
2.382V    -5mA       -3.995mA   -8.654mA
[Ramp]
R_load=50.000Ohm
dV/dt_r   309.780mV/144.000ps  288.449mV/181.000ps  343.920mV/118.500ps
dV/dt_f   309.750mV/147.000ps  288.359mV/187.500ps  343.920mV/119.500ps
[Rising waveform]
R_fixture=50.000Ohm
V_fixture=1.200
V_fixture_min=1.140
V_fixture_max=1.300
0s        609.6mV    600.2mV    633.2mV
52ps      605.4mV    598.9mV    683.8mV
128ps     602.2mV    595.1mV    1.025V
166ps     619.9mV    592.6mV    1.121V
243ps     814.6mV    588.5mV    1.198V
294ps     980.1mV    592.2mV    1.215V
358ps     1.082V     621.8mV    1.223V
524ps     1.14V      956.2mV    1.227V
613ps     1.144V     1.052V     1.228V
1.25ns    1.146V     1.098V     1.228V
[Rising waveform]
R_fixture=50.000Ohm
V_fixture=0
0s        587.1uV    127.1uV    -3.676mV
64ps      191.8uV    470.4uV    31.75mV
192ps     960.1uV    245.9uV    374.1mV
332ps     259.6mV    -7.831mV   516.2mV
409ps     372.7mV    9.648mV    540mV
486ps     434mV      94.9mV     551.1mV
626ps     479.6mV    300.5mV    557.7mV
741ps     491.1mV    392.2mV    559.1mV
945ps     497.1mV    448.4mV    559.6mV
1.25ns    497.8mV    462.3mV    559.8mV
[Falling waveform]
R_fixture=50.000Ohm
V_fixture=1.200
V_fixture_min=1.140
V_fixture_max=1.300
0s        1.146V     1.098V     1.231V
64ps      1.146V     1.098V     1.203V
192ps     1.141V     1.098V     853.3mV
269ps     1.02V      1.102V     730.4mV
345ps     861.9mV    1.106V     678mV
422ps     742.3mV    1.071V     656.2mV
498ps     675.6mV    970.9mV    647.6mV
639ps     629.2mV    772.4mV    642.8mV
766ps     617mV      669.4mV    641.8mV
1.25ns    611.7mV    602.8mV    641.2mV
[Falling waveform]
R_fixture=50.000Ohm
V_fixture=0
0s        497.4mV    463.1mV    569.4mV
39ps      499.8mV    462.9mV    529.8mV
115ps     512.6mV    463.6mV    212.4mV
154ps     495.9mV    466.6mV    111mV
230ps     300.2mV    478mV      30.66mV
281ps     151.9mV    479.9mV    13.51mV
345ps     57.27mV    436mV      4.714mV
498ps     6.207mV    120.5mV    570.1uV
600ps     1.46mV     32.61mV    153.7uV
1.25ns    -731.6nV   -2.636uV   643.4nV
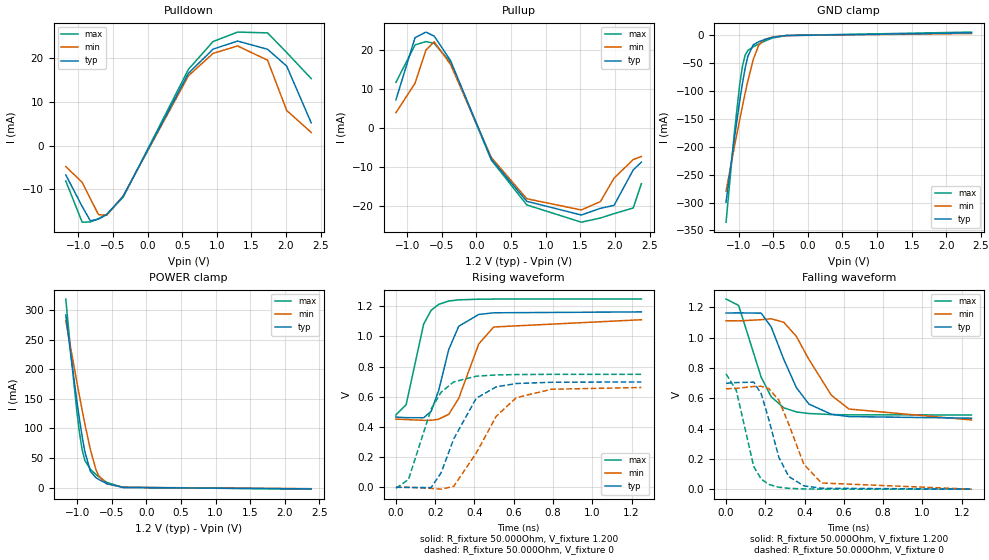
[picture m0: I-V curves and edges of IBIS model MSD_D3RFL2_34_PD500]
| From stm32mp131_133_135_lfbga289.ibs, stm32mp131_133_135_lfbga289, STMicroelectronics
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[Model] MSD_D3RFL2_34_PD500
Model_type   I/O
C_comp 2.418pF   2.333pF   2.542pF
Vinh = 820.000mV
Vinl = 380.000mV
Vmeas = 600.000mV
Vref = 600.000mV
[Model Spec]
Vinh   820.000mV   790.000mV   870.000mV
Vinl   380.000mV   350.000mV   430.000mV
Vmeas   600.000mV   570.000mV   650.000mV
Vref   600.000mV   570.000mV   650.000mV
[Receiver Thresholds]
Vth   =  0.600V
Vth_min  =  0.5880V
Vth_max  =  0.6120V
Vinh_ac  =  0.220V
Vinh_dc  =  0.130V
Vinl_ac  = -0.220V
Vinl_dc  = -0.130V
Tslew_ac =  5.000ns |Not specified, so set to high value
[Temperature Range]   25.000   125.000   -40.000
[Voltage Range]   1.200V   1.140V   1.300V
[GND Clamp Reference]   0.00V   0.00V   0.00V
[Pulldown Reference]   0.00V   0.00V   0.00V
[POWER Clamp Reference]   1.200V   1.140V   1.300V
[Pullup Reference]   1.200V   1.140V   1.300V
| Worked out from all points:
|   slope of the pulldown table from 0 to 0.18 V, typ, clamps not added: 31.3 ohm
|   slope of the pullup table from 0 to 0.18 V, typ, clamps not added: 26.5 ohm
|   GND clamp passes 1 mA (typ) near -0.40 V on its own axis
|   POWER clamp passes 1 mA (typ) near -0.41 V on its own axis
|   rising waveform, R_fixture 50.000Ohm, V_fixture 1.200: 20-80 % time 90.7ps typ, 117ps min, 77.2ps max; typ from 0.466 V to 1.16 V
|   rising waveform, R_fixture 50.000Ohm, V_fixture 0: 20-80 % time 144ps typ, 175ps min, 124ps max; typ from 0.001 V to 0.699 V
|   falling waveform, R_fixture 50.000Ohm, V_fixture 1.200: 20-80 % time 144ps typ, 190ps min, 119ps max; typ from 1.16 V to 0.468 V
|   falling waveform, R_fixture 50.000Ohm, V_fixture 0: 20-80 % time 94.2ps typ, 120ps min, 80.3ps max; typ from 0.698 V to 0 V
[GND Clamp]
-1.182V   -299.2mA   -279.4mA   -335.3mA
-1.064V   -187.1mA   -201.6mA   -177.2mA
-984.9mV  -117.6mA   -151.5mA   -88.27mA
-945.5mV  -86.31mA   -127.1mA   -55.47mA
-906.1mV  -58.92mA   -103.8mA   -35.36mA
-866.7mV  -37.41mA   -81.56mA   -26.95mA
-787.9mV  -16.78mA   -42.84mA   -20.37mA
-709.1mV  -11.29mA   -17.41mA   -15.26mA
-630.3mV  -7.777mA   -7.464mA   -10.57mA
-512.1mV  -3.515mA   -2.998mA   -4.657mA
-315.1mV  -159.9uA   -226.2uA   -149.3uA
2.364V    4.576mA    3.518mA    5.996mA
[Power Clamp]
-1.164V   292.1mA    282.3mA    318.9mA
-1.085V   218.4mA    230.6mA    219.7mA
-1.006V   148.2mA    179.8mA    130.8mA
-966.7mV  115.7mA    154.9mA    93.06mA
-927.3mV  85.9mA     130.7mA    63.72mA
-887.9mV  60.18mA    107.2mA    45.62mA
-809.1mV  27.64mA    64.14mA    30.93mA
-730.3mV  16.89mA    31.01mA    22.25mA
-690.9mV  13.81mA    20.19mA    18.4mA
-572.7mV  6.565mA    6.472mA    8.682mA
-336.4mV  180.4uA    344.1uA    207.9uA
2.382V    -2.355mA   -1.942mA   -2.793mA
[Pulldown]
-1.182V   -6.7mA     -4.8mA     -8.1mA
-945.5mV  -13.91mA   -8.4mA     -17.51mA
-827.3mV  -17.2mA    -12.13mA   -17.46mA
-709.1mV  -16.81mA   -15.8mA    -16.7mA
-590.9mV  -15.77mA   -15.93mA   -15.69mA
-354.6mV  -11.63mA   -11.56mA   -11.83mA
590.9mV   16.53mA    15.97mA    17.45mA
945.5mV   22.04mA    21.07mA    23.78mA
1.3V      23.89mA    22.77mA    25.94mA
1.733V    22.01mA    19.52mA    25.76mA
2.009V    18.18mA    8.04mA     21.28mA
2.364V    5.2mA      3mA        15.3mA
[Pullup]
-1.164V   7.3mA      4.009mA    11.8mA
-887.9mV  23.28mA    11.57mA    21.41mA
-730.3mV  24.71mA    20.07mA    22.27mA
-612.1mV  23.69mA    22.22mA    21.84mA
-375.8mV  17.41mA    16.45mA    16.97mA
215.2mV   -7.945mA   -7.528mA   -8.168mA
727.3mV   -18.75mA   -18.09mA   -19.68mA
1.515V    -22.27mA   -20.97mA   -24.11mA
1.791V    -20.54mA   -18.81mA   -23.03mA
1.988V    -19.79mA   -12.79mA   -21.91mA
2.264V    -10.7mA    -8.043mA   -20.47mA
2.382V    -8.7mA     -7.243mA   -14.23mA
[Ramp]
R_load=50.000Ohm
dV/dt_r   418.020mV/117.500ps  395.459mV/146.500ps  452.550mV/100.500ps
dV/dt_f   418.020mV/120.000ps  395.429mV/156.000ps  452.550mV/99.500ps
[Rising waveform]
R_fixture=50.000Ohm
V_fixture=1.200
V_fixture_min=1.140
V_fixture_max=1.300
0s        466.3mV    452.4mV    480.5mV
52ps      462.1mV    449.6mV    548.1mV
141ps     461.5mV    444.5mV    1.081V
179ps     503.2mV    444.8mV    1.173V
218ps     643.2mV    451.9mV    1.213V
269ps     913.6mV    484.5mV    1.235V
320ps     1.068V     590.8mV    1.243V
422ps     1.146V     950.8mV    1.247V
498ps     1.157V     1.063V     1.248V
1.25ns    1.163V     1.111V     1.248V
[Rising waveform]
R_fixture=50.000Ohm
V_fixture=0
0s        902.3uV    890uV      -6.227mV
64ps      -167.8uV   756.2uV    52.9mV
179ps     -1.311mV   -6.374mV   517.9mV
230ps     96.18mV    -11.62mV   630.8mV
294ps     320.4mV    6.595mV    698.9mV
409ps     590.8mV    227.4mV    737.1mV
511ps     666.5mV    471.5mV    745.1mV
613ps     688.3mV    594.2mV    747.8mV
792ps     696.7mV    650.5mV    749.2mV
1.25ns    698.9mV    662mV      749.4mV
[Falling waveform]
R_fixture=50.000Ohm
V_fixture=1.200
V_fixture_min=1.140
V_fixture_max=1.300
0s        1.162V     1.111V     1.254V
64ps      1.163V     1.11V      1.212V
179ps     1.161V     1.118V     738.2mV
230ps     1.07V      1.124V     609.2mV
294ps     856.4mV    1.101V     536.8mV
358ps     670.2mV    1.008V     509.6mV
422ps     561.2mV    855.9mV    499mV
537ps     493.8mV    618.6mV    492.2mV
626ps     478.8mV    528.4mV    490.3mV
1.25ns    468.1mV    456.7mV    489.3mV
[Falling waveform]
R_fixture=50.000Ohm
V_fixture=0
0s        698.3mV    661.9mV    760.4mV
52ps      703mV      664.9mV    652.6mV
141ps     706mV      677.4mV    148.5mV
179ps     630mV      678.7mV    66.63mV
218ps     458.7mV    663.3mV    31.28mV
269ps     209.8mV    586.6mV    12.69mV
320ps     82.46mV    426.8mV    5.425mV
396ps     21.99mV    164.4mV    1.548mV
486ps     6.143mV    40.67mV    363.7uV
1.25ns    2.338uV    23.94uV    702.1nV
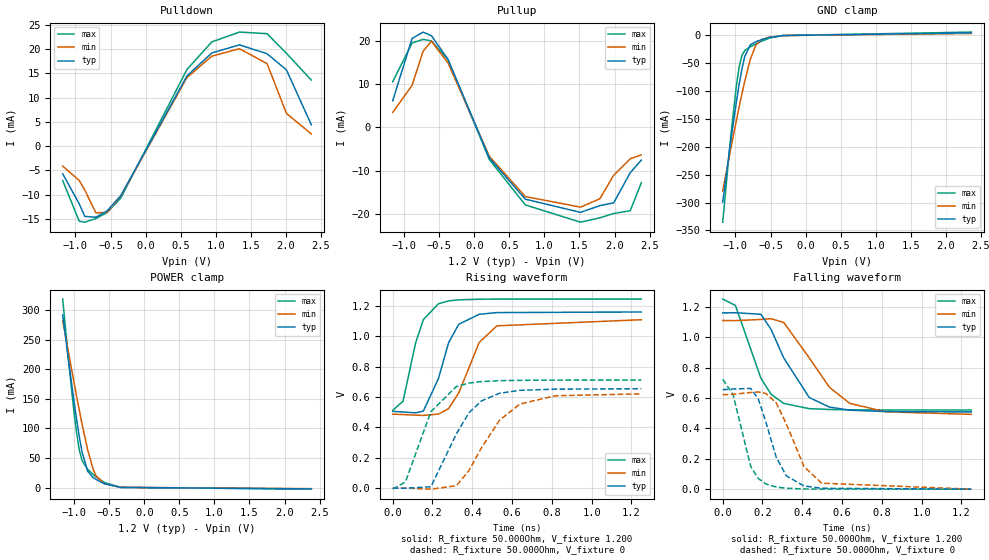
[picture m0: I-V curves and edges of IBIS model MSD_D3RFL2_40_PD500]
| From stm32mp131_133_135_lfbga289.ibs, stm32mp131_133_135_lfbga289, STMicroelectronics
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[Model] MSD_D3RFL2_40_PD500
Model_type   I/O
C_comp 2.418pF   2.333pF   2.542pF
Vinh = 820.000mV
Vinl = 380.000mV
Vmeas = 600.000mV
Vref = 600.000mV
[Model Spec]
Vinh   820.000mV   790.000mV   870.000mV
Vinl   380.000mV   350.000mV   430.000mV
Vmeas   600.000mV   570.000mV   650.000mV
Vref   600.000mV   570.000mV   650.000mV
[Receiver Thresholds]
Vth   =  0.600V
Vth_min  =  0.5880V
Vth_max  =  0.6120V
Vinh_ac  =  0.220V
Vinh_dc  =  0.130V
Vinl_ac  = -0.220V
Vinl_dc  = -0.130V
Tslew_ac =  5.000ns |Not specified, so set to high value
[Temperature Range]   25.000   125.000   -40.000
[Voltage Range]   1.200V   1.140V   1.300V
[GND Clamp Reference]   0.00V   0.00V   0.00V
[Pulldown Reference]   0.00V   0.00V   0.00V
[POWER Clamp Reference]   1.200V   1.140V   1.300V
[Pullup Reference]   1.200V   1.140V   1.300V
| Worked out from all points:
|   slope of the pulldown table from 0 to 0.18 V, typ, clamps not added: 35.6 ohm
|   slope of the pullup table from 0 to 0.18 V, typ, clamps not added: 29.6 ohm
|   GND clamp passes 1 mA (typ) near -0.40 V on its own axis
|   POWER clamp passes 1 mA (typ) near -0.41 V on its own axis
|   rising waveform, R_fixture 50.000Ohm, V_fixture 1.200: 20-80 % time 94.2ps typ, 121ps min, 80.9ps max; typ from 0.506 V to 1.16 V
|   rising waveform, R_fixture 50.000Ohm, V_fixture 0: 20-80 % time 154ps typ, 187ps min, 131ps max; typ from 0.001 V to 0.655 V
|   falling waveform, R_fixture 50.000Ohm, V_fixture 1.200: 20-80 % time 157ps typ, 198ps min, 124ps max; typ from 1.16 V to 0.508 V
|   falling waveform, R_fixture 50.000Ohm, V_fixture 0: 20-80 % time 98.4ps typ, 123ps min, 82.6ps max; typ from 0.654 V to 0 V
[GND Clamp]
-1.182V   -299.2mA   -279.4mA   -335.3mA
-1.064V   -187.1mA   -201.6mA   -177.2mA
-984.9mV  -117.6mA   -151.5mA   -88.27mA
-945.5mV  -86.31mA   -127.1mA   -55.47mA
-906.1mV  -58.92mA   -103.8mA   -35.36mA
-866.7mV  -37.41mA   -81.56mA   -26.95mA
-787.9mV  -16.78mA   -42.84mA   -20.37mA
-709.1mV  -11.29mA   -17.41mA   -15.26mA
-630.3mV  -7.777mA   -7.464mA   -10.57mA
-512.1mV  -3.515mA   -2.998mA   -4.657mA
-315.1mV  -159.9uA   -226.2uA   -149.3uA
2.364V    4.576mA    3.518mA    5.996mA
[Power Clamp]
-1.164V   292.1mA    282.3mA    318.9mA
-1.085V   218.4mA    230.6mA    219.7mA
-1.006V   148.2mA    179.8mA    130.8mA
-966.7mV  115.7mA    154.9mA    93.06mA
-927.3mV  85.9mA     130.7mA    63.72mA
-887.9mV  60.18mA    107.2mA    45.62mA
-809.1mV  27.64mA    64.14mA    30.93mA
-730.3mV  16.89mA    31.01mA    22.25mA
-690.9mV  13.81mA    20.19mA    18.4mA
-572.7mV  6.565mA    6.472mA    8.682mA
-336.4mV  180.4uA    344.1uA    207.9uA
2.382V    -2.355mA   -1.942mA   -2.793mA
[Pulldown]
-1.182V   -5.7mA     -4.1mA     -7.1mA
-945.5mV  -11.91mA   -7.1mA     -15.47mA
-866.7mV  -14.47mA   -9.06mA    -15.66mA
-709.1mV  -14.63mA   -13.73mA   -14.9mA
-551.5mV  -13.37mA   -13.65mA   -13.72mA
-354.6mV  -10.22mA   -10.29mA   -10.71mA
590.9mV   14.46mA    14.13mA    15.79mA
945.5mV   19.18mA    18.52mA    21.45mA
1.339V    20.84mA    20.05mA    23.47mA
1.733V    19.01mA    16.98mA    23.14mA
2.009V    15.7mA     6.74mA     19.1mA
2.364V    4.4mA      2.5mA      13.6mA
[Pullup]
-1.164V   6.1mA      3.409mA    10.51mA
-887.9mV  20.5mA     9.662mA    19.46mA
-730.3mV  21.97mA    17.56mA    20.29mA
-612.1mV  21.14mA    19.84mA    19.93mA
-375.8mV  15.67mA    14.87mA    15.59mA
215.2mV   -7.105mA   -6.742mA   -7.481mA
727.3mV   -16.61mA   -16.01mA   -17.94mA
1.515V    -19.66mA   -18.45mA   -21.93mA
1.791V    -18.11mA   -16.51mA   -20.92mA
1.988V    -17.46mA   -11.08mA   -19.92mA
2.224V    -10.5mA    -7.295mA   -19.28mA
2.382V    -7.6mA     -6.395mA   -12.82mA
[Ramp]
R_load=50.000Ohm
dV/dt_r   392.070mV/124.500ps  372.209mV/155.000ps  431.040mV/106.000ps
dV/dt_f   392.070mV/128.500ps  372.179mV/162.500ps  431.040mV/103.500ps
[Rising waveform]
R_fixture=50.000Ohm
V_fixture=1.200
V_fixture_min=1.140
V_fixture_max=1.300
0s        505.9mV    487.7mV    512mV
52ps      501.7mV    484.8mV    573.1mV
115ps     496.3mV    480.9mV    954.6mV
154ps     507.7mV    479.2mV    1.11V
230ps     722.1mV    487.8mV    1.214V
281ps     957.6mV    524.4mV    1.233V
332ps     1.079V     627.2mV    1.24V
435ps     1.145V     959.6mV    1.244V
524ps     1.156V     1.069V     1.245V
1.25ns    1.16V      1.109V     1.245V
[Rising waveform]
R_fixture=50.000Ohm
V_fixture=0
0s        823.6uV    784.3uV    -5.389mV
64ps      -78.4uV    806uV      41.17mV
192ps     9.531mV    -6.01mV    504.3mV
320ps     357.6mV    16.54mV    669.2mV
383ps     496.3mV    115.7mV    692mV
447ps     575.3mV    267.9mV    702.2mV
537ps     624.9mV    447.7mV    707.7mV
639ps     644.3mV    553.8mV    710mV
817ps     652.3mV    608.7mV    711.5mV
1.25ns    654.6mV    621.2mV    711.9mV
[Falling waveform]
R_fixture=50.000Ohm
V_fixture=1.200
V_fixture_min=1.140
V_fixture_max=1.300
0s        1.159V     1.109V     1.25V
64ps      1.16V      1.108V     1.208V
192ps     1.15V      1.116V     729.6mV
243ps     1.051V     1.121V     624.2mV
307ps     862.3mV    1.096V     563.7mV
435ps     602.6mV    863.5mV    529.5mV
537ps     539.7mV    669.1mV    523.9mV
639ps     519.3mV    564.2mV    521.7mV
817ps     510.7mV    508.9mV    520.6mV
1.25ns    507.8mV    491.9mV    520.5mV
[Falling waveform]
R_fixture=50.000Ohm
V_fixture=0
0s        654.1mV    621.2mV    722.5mV
52ps      658.8mV    623.6mV    622.2mV
141ps     662.3mV    636mV      149.1mV
179ps     592.6mV    639mV      69.86mV
218ps     436.9mV    629mV      33.72mV
269ps     210mV      567mV      13.96mV
320ps     87.59mV    428.9mV    6.034mV
409ps     20.81mV    147.4mV    1.413mV
498ps     6.022mV    39.35mV    353.8uV
1.25ns    2.658uV    24.36uV    811.3nV
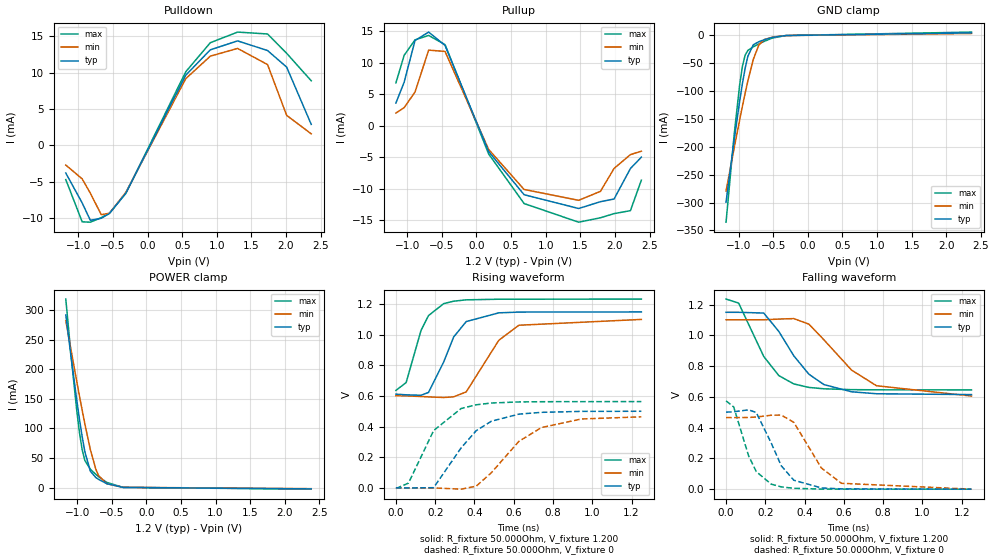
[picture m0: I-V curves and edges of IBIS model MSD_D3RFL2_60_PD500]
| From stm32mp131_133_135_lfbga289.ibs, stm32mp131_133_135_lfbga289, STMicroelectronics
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[Model] MSD_D3RFL2_60_PD500
Model_type   I/O
C_comp 2.418pF   2.333pF   2.542pF
Vinh = 820.000mV
Vinl = 380.000mV
Vmeas = 600.000mV
Vref = 600.000mV
[Model Spec]
Vinh   820.000mV   790.000mV   870.000mV
Vinl   380.000mV   350.000mV   430.000mV
Vmeas   600.000mV   570.000mV   650.000mV
Vref   600.000mV   570.000mV   650.000mV
[Receiver Thresholds]
Vth   =  0.600V
Vth_min  =  0.5880V
Vth_max  =  0.6120V
Vinh_ac  =  0.220V
Vinh_dc  =  0.130V
Vinl_ac  = -0.220V
Vinl_dc  = -0.130V
Tslew_ac =  5.000ns |Not specified, so set to high value
[Temperature Range]   25.000   125.000   -40.000
[Voltage Range]   1.200V   1.140V   1.300V
[GND Clamp Reference]   0.00V   0.00V   0.00V
[Pulldown Reference]   0.00V   0.00V   0.00V
[POWER Clamp Reference]   1.200V   1.140V   1.300V
[Pullup Reference]   1.200V   1.140V   1.300V
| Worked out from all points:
|   slope of the pulldown table from 0 to 0.18 V, typ, clamps not added: 50.1 ohm
|   slope of the pullup table from 0 to 0.18 V, typ, clamps not added: 42.9 ohm
|   GND clamp passes 1 mA (typ) near -0.40 V on its own axis
|   POWER clamp passes 1 mA (typ) near -0.41 V on its own axis
|   rising waveform, R_fixture 50.000Ohm, V_fixture 1.200: 20-80 % time 108ps typ, 138ps min, 90.8ps max; typ from 0.613 V to 1.15 V
|   rising waveform, R_fixture 50.000Ohm, V_fixture 0: 20-80 % time 179ps typ, 221ps min, 149ps max; typ from 0.001 V to 0.501 V
|   falling waveform, R_fixture 50.000Ohm, V_fixture 1.200: 20-80 % time 186ps typ, 237ps min, 147ps max; typ from 1.15 V to 0.615 V
|   falling waveform, R_fixture 50.000Ohm, V_fixture 0: 20-80 % time 110ps typ, 137ps min, 93.6ps max; typ from 0.501 V to 0 V
[GND Clamp]
-1.182V   -299.2mA   -279.4mA   -335.3mA
-1.064V   -187.1mA   -201.6mA   -177.2mA
-984.9mV  -117.6mA   -151.5mA   -88.27mA
-945.5mV  -86.31mA   -127.1mA   -55.47mA
-906.1mV  -58.92mA   -103.8mA   -35.36mA
-866.7mV  -37.41mA   -81.56mA   -26.95mA
-787.9mV  -16.78mA   -42.84mA   -20.37mA
-709.1mV  -11.29mA   -17.41mA   -15.26mA
-630.3mV  -7.777mA   -7.464mA   -10.57mA
-512.1mV  -3.515mA   -2.998mA   -4.657mA
-315.1mV  -159.9uA   -226.2uA   -149.3uA
2.364V    4.576mA    3.518mA    5.996mA
[Power Clamp]
-1.164V   292.1mA    282.3mA    318.9mA
-1.085V   218.4mA    230.6mA    219.7mA
-1.006V   148.2mA    179.8mA    130.8mA
-966.7mV  115.7mA    154.9mA    93.06mA
-927.3mV  85.9mA     130.7mA    63.72mA
-887.9mV  60.18mA    107.2mA    45.62mA
-809.1mV  27.64mA    64.14mA    30.93mA
-730.3mV  16.89mA    31.01mA    22.25mA
-690.9mV  13.81mA    20.19mA    18.4mA
-572.7mV  6.565mA    6.472mA    8.682mA
-336.4mV  180.4uA    344.1uA    207.9uA
2.382V    -2.355mA   -1.942mA   -2.793mA
[Pulldown]
-1.182V   -3.8mA     -2.7mA     -4.7mA
-945.5mV  -7.91mA    -4.6mA     -10.51mA
-827.3mV  -10.3mA    -6.57mA    -10.56mA
-669.7mV  -10.02mA   -9.53mA    -9.94mA
-551.5mV  -9.37mA    -9.334mA   -9.3mA
-315.1mV  -6.567mA   -6.465mA   -6.607mA
551.5mV   9.676mA    9.195mA    10.14mA
906.1mV   13.16mA    12.29mA    14.14mA
1.3V      14.39mA    13.35mA    15.6mA
1.733V    13.06mA    11.13mA    15.34mA
2.009V    10.78mA    4.14mA     12.68mA
2.364V    2.9mA      1.6mA      8.9mA
[Pullup]
-1.164V   3.6mA      2.005mA    6.785mA
-1.045V   6.9mA      2.857mA    11.16mA
-887.9mV  13.51mA    5.344mA    13.61mA
-690.9mV  14.84mA    11.98mA    14.31mA
-454.5mV  12.73mA    11.77mA    12.85mA
175.8mV   -4.108mA   -3.772mA   -4.491mA
687.9mV   -10.95mA   -10.12mA   -12.35mA
1.476V    -13.14mA   -11.84mA   -15.31mA
1.791V    -12.06mA   -10.42mA   -14.61mA
1.988V    -11.63mA   -6.784mA   -13.95mA
2.224V    -6.8mA     -4.595mA   -13.48mA
2.382V    -5mA       -4.048mA   -8.646mA
[Ramp]
R_load=50.000Ohm
dV/dt_r   311.100mV/145.000ps  289.379mV/182.000ps  345.750mV/120.000ps
dV/dt_f   311.070mV/149.000ps  289.348mV/188.500ps  345.750mV/120.500ps
[Rising waveform]
R_fixture=50.000Ohm
V_fixture=1.200
V_fixture_min=1.140
V_fixture_max=1.300
0s        612.7mV    602.7mV    637.3mV
52ps      608.5mV    601.4mV    688.3mV
128ps     605.4mV    597.4mV    1.03V
166ps     624.2mV    594.9mV    1.126V
243ps     822.2mV    590.9mV    1.204V
294ps     986.3mV    595.3mV    1.22V
358ps     1.087V     627.4mV    1.229V
524ps     1.144V     964.7mV    1.233V
626ps     1.149V     1.063V     1.233V
1.25ns    1.15V      1.101V     1.234V
[Rising waveform]
R_fixture=50.000Ohm
V_fixture=0
0s        594.1uV    137uV      -3.676mV
64ps      158.6uV    486.2uV    31.75mV
192ps     1.776mV    180.1uV    374.9mV
332ps     261.7mV    -7.911mV   518.9mV
409ps     374.6mV    11.65mV    543.4mV
486ps     436mV      99.44mV    554.9mV
626ps     482.2mV    304.2mV    561.9mV
741ps     494mV      394.8mV    563.4mV
945ps     500.2mV    450.6mV    564mV
1.25ns    501mV      464.6mV    564.2mV
[Falling waveform]
R_fixture=50.000Ohm
V_fixture=1.200
V_fixture_min=1.140
V_fixture_max=1.300
0s        1.15V      1.101V     1.236V
64ps      1.15V      1.101V     1.21V
192ps     1.145V     1.101V     862.6mV
269ps     1.025V     1.106V     738.1mV
345ps     867.2mV    1.109V     684.2mV
422ps     747.3mV    1.073V     661.5mV
498ps     680.2mV    971.7mV    652.5mV
639ps     633.2mV    774.5mV    647mV
766ps     620.4mV    672.5mV    646mV
1.25ns    614.9mV    605.4mV    645.4mV
[Falling waveform]
R_fixture=50.000Ohm
V_fixture=0
0s        500.6mV    465.5mV    573.8mV
39ps      503.1mV    465.2mV    534.3mV
115ps     515.8mV    466.1mV    216.4mV
154ps     498.1mV    469.2mV    114.1mV
230ps     300.1mV    480.7mV    32.67mV
281ps     152.5mV    481.8mV    14.89mV
345ps     58.26mV    434.7mV    5.602mV
486ps     7.797mV    137.1mV    622.7uV
588ps     1.878mV    38.13mV    109.8uV
1.25ns    14.33uV    46.37uV    1.586uV
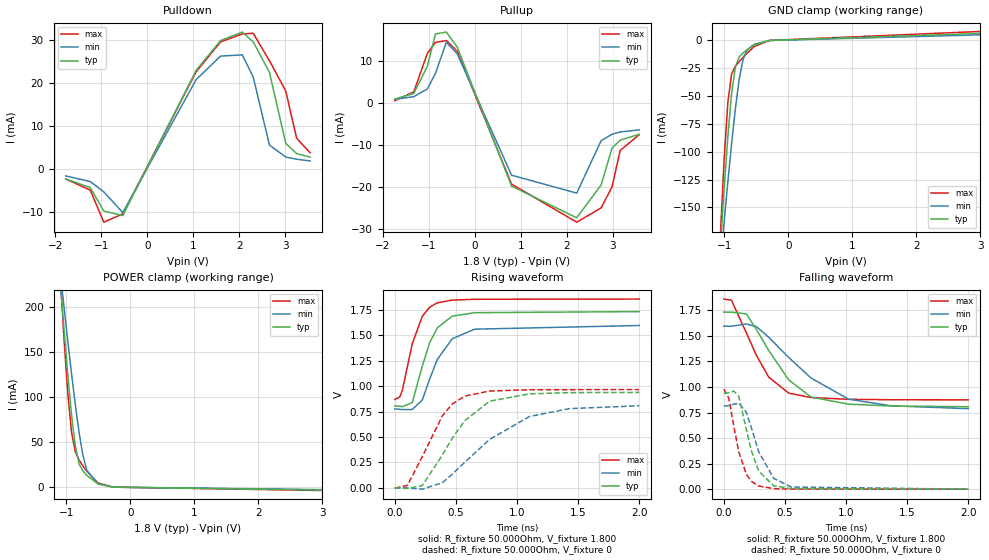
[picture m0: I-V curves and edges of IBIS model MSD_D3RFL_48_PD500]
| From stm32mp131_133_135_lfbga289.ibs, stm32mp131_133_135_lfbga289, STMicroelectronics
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[Model] MSD_D3RFL_48_PD500
Model_type   I/O
C_comp 2.389pF   2.306pF   2.512pF
Vinh = 1.440V
Vinl = 360.000mV
Vmeas = 900.000mV
Vref = 900.000mV
[Model Spec]
Vinh   1.440V   1.365V   1.515V
Vinl   360.000mV   285.000mV   435.000mV
Vmeas   900.000mV   825.000mV   975.000mV
Vref   900.000mV   825.000mV   975.000mV
[Temperature Range]   25.000   125.000   -40.000
[Voltage Range]   1.800V   1.650V   1.950V
[GND Clamp Reference]   0.00V   0.00V   0.00V
[Pulldown Reference]   0.00V   0.00V   0.00V
[POWER Clamp Reference]   1.800V   1.650V   1.950V
[Pullup Reference]   1.800V   1.650V   1.950V
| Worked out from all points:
|   slope of the pulldown table from 0 to 0.27 V, typ, clamps not added: 41 ohm
|   slope of the pullup table from 0 to 0.27 V, typ, clamps not added: 32.3 ohm
|   GND clamp passes 1 mA (typ) near -0.40 V on its own axis
|   POWER clamp passes 1 mA (typ) near -0.41 V on its own axis
|   rising waveform, R_fixture 50.000Ohm, V_fixture 1.800: 20-80 % time 150ps typ, 191ps min, 133ps max; typ from 0.806 V to 1.73 V
|   rising waveform, R_fixture 50.000Ohm, V_fixture 0: 20-80 % time 319ps typ, 496ps min, 247ps max; typ from 0.001 V to 0.938 V
|   falling waveform, R_fixture 50.000Ohm, V_fixture 1.800: 20-80 % time 320ps typ, 470ps min, 245ps max; typ from 1.73 V to 0.807 V
|   falling waveform, R_fixture 50.000Ohm, V_fixture 0: 20-80 % time 125ps typ, 156ps min, 107ps max; typ from 0.938 V to 0 V
[GND Clamp]
-1.773V   -890mA     -681.3mA   -1.193A
-1.064V   -187mA     -201.5mA   -177.1mA
-1.005V   -134.3mA   -163.7mA   -108.2mA
-945.5mV  -86.29mA   -127.1mA   -55.46mA
-886.4mV  -47.27mA   -92.47mA   -30.14mA
-827.3mV  -23.62mA   -60.99mA   -23.17mA
-768.2mV  -14.87mA   -34.94mA   -19.04mA
-709.1mV  -11.28mA   -17.4mA    -15.26mA
-650mV    -8.596mA   -8.946mA   -11.71mA
-531.8mV  -4.128mA   -3.495mA   -5.517mA
-295.4mV  -93.3uA    -148.6uA   -78.79uA
3.545V    7.293mA    5.788mA    9.34mA
[Power Clamp]
-1.745V   859.6mA    674.1mA    1.126A
-1.095V   228.2mA    237.8mA    233mA
-1.036V   174.7mA    199.4mA    164mA
-977.3mV  124.3mA    161.8mA    103.8mA
-918.2mV  79.61mA    125.4mA    60.52mA
-859.1mV  45mA       91.03mA    39.02mA
-800mV    25.73mA    60.16mA    29.96mA
-740.9mV  17.88mA    35.33mA    23.41mA
-681.8mV  13.2mA     18.94mA    17.62mA
-504.5mV  3.545mA    3.647mA    4.652mA
-268.2mV  26.02uA    92.99uA    30.43uA
3.573V    -3.69mA    -3.207mA   -4.307mA
[Pulldown]
-1.773V   -2.4mA     -1.7mA     -2.4mA
-1.241V   -4.4mA     -3mA       -5mA
-945.5mV  -9.88mA    -5.4mA     -12.48mA
-531.8mV  -10.94mA   -10.24mA   -10.54mA
1.064V    22.92mA    20.76mA    22.57mA
1.595V    29.86mA    26.24mA    29.55mA
2.068V    31.84mA    26.53mA    31.41mA
2.305V    29.56mA    21.37mA    31.56mA
2.659V    22.45mA    5.5mA      25.16mA
3.014V    5.9mA      2.7mA      18.1mA
3.25V     3.5mA      2.2mA      7.1mA
3.545V    2.7mA      1.8mA      3.7mA
[Pullup]
-1.745V   1mA        900uA      600uA
-1.332V   2.3mA      1.554mA    2.669mA
-1.036V   8.8mA      3.377mA    11.85mA
-859.1mV  16.48mA    7.109mA    14.47mA
-622.7mV  16.92mA    14.49mA    14.91mA
-386.4mV  13.35mA    11.77mA    12.34mA
795.5mV   -19.73mA   -17.13mA   -19.24mA
2.214V    -27.27mA   -21.4mA    -28.32mA
2.745V    -19.44mA   -8.923mA   -24.91mA
2.982V    -10.7mA    -7.392mA   -19.9mA
3.159V    -8.8mA     -6.846mA   -11.25mA
3.573V    -7.4mA     -6.346mA   -7.508mA
[Ramp]
R_load=50.000Ohm
dV/dt_r   559.680mV/235.000ps  487.739mV/345.000ps  584.280mV/190.000ps
dV/dt_f   559.619mV/223.500ps  486.926mV/314.000ps  584.280mV/176.000ps
[Rising waveform]
R_fixture=50.000Ohm
V_fixture=1.800
V_fixture_min=1.650
V_fixture_max=1.950
0s        805.9mV    776.2mV    868.2mV
41ps      801.4mV    772.1mV    893.5mV
62ps      798.3mV    769.4mV    958.9mV
143ps     837.8mV    770.2mV    1.416V
225ps     1.196V     863.7mV    1.686V
286ps     1.428V     1.071V     1.777V
348ps     1.573V     1.262V     1.819V
470ps     1.688V     1.466V     1.846V
654ps     1.722V     1.56V      1.854V
2ns       1.733V     1.596V     1.856V
[Rising waveform]
R_fixture=50.000Ohm
V_fixture=0
0s        1.031mV    1.187mV    -2.545mV
103ps     -5.661mV   -1.614mV   23.83mV
225ps     22.57mV    -12.76mV   306.3mV
388ps     319.8mV    49.46mV    705.9mV
470ps     487.1mV    133.5mV    824.4mV
572ps     659.7mV    251mV      901.8mV
776ps     852.3mV    476.2mV    952.2mV
1.103ns   924.4mV    702.2mV    964.6mV
1.43ns    936.3mV    779mV      965.9mV
2ns       938.4mV    807.2mV    966mV
[Falling waveform]
R_fixture=50.000Ohm
V_fixture=1.800
V_fixture_min=1.650
V_fixture_max=1.950
0s        1.733V     1.596V     1.861V
62ps      1.733V     1.595V     1.851V
184ps     1.716V     1.617V     1.532V
266ps     1.565V     1.592V     1.312V
368ps     1.357V     1.487V     1.096V
531ps     1.07V      1.289V     940.3mV
715ps     901.3mV    1.087V     896.9mV
1.021ns   832.1mV    881.1mV    879.7mV
1.369ns   813.8mV    816.1mV    875.4mV
2ns       806.9mV    788.3mV    874.4mV
[Falling waveform]
R_fixture=50.000Ohm
V_fixture=0
0s        937.6mV    813.6mV    980.9mV
41ps      943.7mV    818mV      891.3mV
82ps      959.9mV    831.7mV    615mV
123ps     907.5mV    839.8mV    364.8mV
184ps     587mV      754.3mV    146.8mV
225ps     377.7mV    604mV      77.66mV
286ps     175.9mV    365.9mV    30.33mV
409ps     32.47mV    105.2mV    5.162mV
552ps     5.546mV    21.24mV    916.3uV
2ns       14.85uV    86.3uV     0V
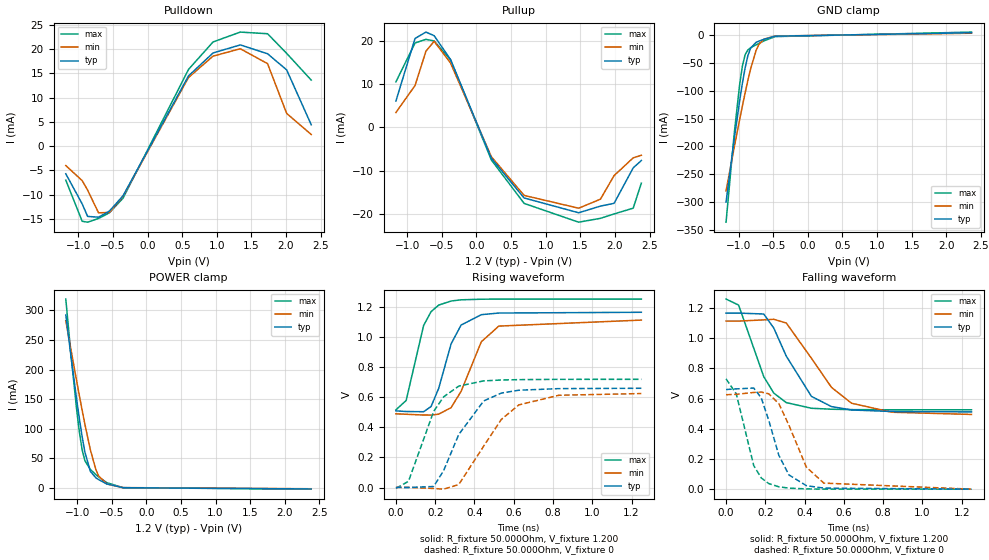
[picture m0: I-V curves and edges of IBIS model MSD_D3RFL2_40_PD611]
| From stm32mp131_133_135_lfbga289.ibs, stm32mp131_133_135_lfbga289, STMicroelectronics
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[Model] MSD_D3RFL2_40_PD611
Model_type   I/O
C_comp 2.448pF   2.362pF   2.573pF
Vinh = 820.000mV
Vinl = 380.000mV
Vmeas = 600.000mV
Vref = 600.000mV
[Model Spec]
Vinh   820.000mV   790.000mV   870.000mV
Vinl   380.000mV   350.000mV   430.000mV
Vmeas   600.000mV   570.000mV   650.000mV
Vref   600.000mV   570.000mV   650.000mV
[Receiver Thresholds]
Vth   =  0.600V
Vth_min  =  0.5880V
Vth_max  =  0.6120V
Vinh_ac  =  0.220V
Vinh_dc  =  0.130V
Vinl_ac  = -0.220V
Vinl_dc  = -0.130V
Tslew_ac =  5.000ns |Not specified, so set to high value
[Temperature Range]   25.000   125.000   -40.000
[Voltage Range]   1.200V   1.140V   1.300V
[GND Clamp Reference]   0.00V   0.00V   0.00V
[Pulldown Reference]   0.00V   0.00V   0.00V
[POWER Clamp Reference]   1.200V   1.140V   1.300V
[Pullup Reference]   1.200V   1.140V   1.300V
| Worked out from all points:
|   slope of the pulldown table from 0 to 0.18 V, typ, clamps not added: 35.6 ohm
|   slope of the pullup table from 0 to 0.18 V, typ, clamps not added: 29.6 ohm
|   GND clamp passes 1 mA (typ) near -0.40 V on its own axis
|   POWER clamp passes 1 mA (typ) near -0.41 V on its own axis
|   rising waveform, R_fixture 50.000Ohm, V_fixture 1.200: 20-80 % time 94.5ps typ, 122ps min, 81.1ps max; typ from 0.51 V to 1.17 V
|   rising waveform, R_fixture 50.000Ohm, V_fixture 0: 20-80 % time 155ps typ, 188ps min, 132ps max; typ from 0.001 V to 0.661 V
|   falling waveform, R_fixture 50.000Ohm, V_fixture 1.200: 20-80 % time 159ps typ, 201ps min, 127ps max; typ from 1.17 V to 0.512 V
|   falling waveform, R_fixture 50.000Ohm, V_fixture 0: 20-80 % time 99.9ps typ, 124ps min, 84ps max; typ from 0.66 V to 0 V
[GND Clamp]
-1.182V   -299.5mA   -279.6mA   -335.7mA
-1.064V   -187.3mA   -201.7mA   -177.4mA
-984.9mV  -117.8mA   -151.5mA   -88.49mA
-945.5mV  -86.46mA   -127.3mA   -55.67mA
-906.1mV  -59.05mA   -103.8mA   -35.55mA
-866.7mV  -37.55mA   -81.66mA   -27.13mA
-827.3mV  -23.74mA   -61.1mA    -23.33mA
-748.5mV  -13.56mA   -28.1mA    -17.89mA
-709.1mV  -11.37mA   -17.48mA   -15.38mA
-630.3mV  -7.842mA   -7.517mA   -10.66mA
-472.7mV  -2.44mA    -2.145mA   -3.165mA
2.364V    3.741mA    2.874mA    4.907mA
[Power Clamp]
-1.164V   292.4mA    282.5mA    319.2mA
-1.085V   218.6mA    230.8mA    220mA
-1.006V   148.4mA    180mA      131.1mA
-966.7mV  115.9mA    155.1mA    93.3mA
-927.3mV  86.08mA    130.8mA    63.93mA
-887.9mV  60.35mA    107.3mA    45.81mA
-809.1mV  27.78mA    64.27mA    31.09mA
-730.3mV  17.01mA    31.11mA    22.38mA
-690.9mV  13.91mA    20.28mA    18.51mA
-572.7mV  6.625mA    6.535mA    8.753mA
-336.4mV  188.6uA    356.2uA    213.6uA
2.382V    -1.927mA   -1.589mA   -2.285mA
[Pulldown]
-1.182V   -5.7mA     -4mA       -7mA
-945.5mV  -11.89mA   -7.1mA     -15.47mA
-866.7mV  -14.47mA   -9.06mA    -15.66mA
-709.1mV  -14.63mA   -13.73mA   -14.89mA
-551.5mV  -13.37mA   -13.66mA   -13.72mA
-354.6mV  -10.22mA   -10.3mA    -10.71mA
590.9mV   14.46mA    14.13mA    15.79mA
945.5mV   19.18mA    18.53mA    21.45mA
1.339V    20.84mA    20.05mA    23.48mA
1.733V    19.02mA    16.98mA    23.14mA
2.009V    15.7mA     6.74mA     19.1mA
2.364V    4.4mA      2.4mA      13.6mA
[Pullup]
-1.164V   6.1mA      3.457mA    10.51mA
-887.9mV  20.5mA     9.662mA    19.46mA
-730.3mV  21.97mA    17.57mA    20.3mA
-612.1mV  21.14mA    19.85mA    19.93mA
-375.8mV  15.68mA    14.87mA    15.59mA
215.2mV   -7.105mA   -6.743mA   -7.481mA
687.9mV   -16.23mA   -15.64mA   -17.48mA
1.476V    -19.64mA   -18.59mA   -21.81mA
1.791V    -18.11mA   -16.51mA   -20.92mA
1.988V    -17.46mA   -11.08mA   -19.91mA
2.264V    -9.3mA     -6.995mA   -18.58mA
2.382V    -7.6mA     -6.395mA   -12.82mA
[Ramp]
R_load=50.000Ohm
dV/dt_r   394.770mV/125.500ps  374.219mV/156.000ps  434.940mV/106.500ps
dV/dt_f   394.770mV/130.000ps  374.219mV/164.500ps  434.940mV/105.500ps
[Rising waveform]
R_fixture=50.000Ohm
V_fixture=1.200
V_fixture_min=1.140
V_fixture_max=1.300
0s        510.4mV    490.8mV    517.4mV
52ps      506.2mV    487.9mV    579.2mV
141ps     504.6mV    482.7mV    1.079V
179ps     539.2mV    482.6mV    1.171V
218ps     660.8mV    488.6mV    1.215V
281ps     956.5mV    531.9mV    1.242V
332ps     1.082V     640.8mV    1.25V
435ps     1.151V     970.7mV    1.254V
524ps     1.162V     1.075V     1.255V
1.25ns    1.167V     1.115V     1.255V
[Rising waveform]
R_fixture=50.000Ohm
V_fixture=0
0s        809.4uV    799uV      -5.389mV
64ps      36.01uV    794.3uV    41.16mV
192ps     6.778mV    -6.334mV   506.5mV
243ps     112.5mV    -11.03mV   604mV
320ps     352.9mV    19.62mV    675.3mV
447ps     576.6mV    275.4mV    710mV
537ps     629mV      453.8mV    716mV
626ps     647.9mV    550.2mV    718.4mV
830ps     658.6mV    614.3mV    720.3mV
1.25ns    660.9mV    625.8mV    720.6mV
[Falling waveform]
R_fixture=50.000Ohm
V_fixture=1.200
V_fixture_min=1.140
V_fixture_max=1.300
0s        1.167V     1.114V     1.26V
64ps      1.167V     1.114V     1.22V
192ps     1.161V     1.122V     745.9mV
243ps     1.068V     1.126V     637mV
307ps     881.3mV    1.101V     573.6mV
435ps     614.9mV    867.3mV    536.2mV
537ps     547.2mV    674.6mV    529.8mV
639ps     524.9mV    569.8mV    527.3mV
843ps     514.8mV    510mV      526.1mV
1.25ns    512.2mV    495.3mV    526mV
[Falling waveform]
R_fixture=50.000Ohm
V_fixture=0
0s        660.4mV    625.9mV    731.1mV
52ps      664.7mV    628.5mV    632mV
141ps     670.1mV    640.9mV    156.3mV
179ps     606mV      643.6mV    74.67mV
218ps     454mV      631.8mV    36.79mV
269ps     224mV      566.7mV    15.6mV
320ps     94.78mV    424.5mV    6.885mV
409ps     23.22mV    146.1mV    1.677mV
498ps     6.9mV      40.09mV    451.5uV
1.25ns    3.354uV    26.25uV    1.109uV
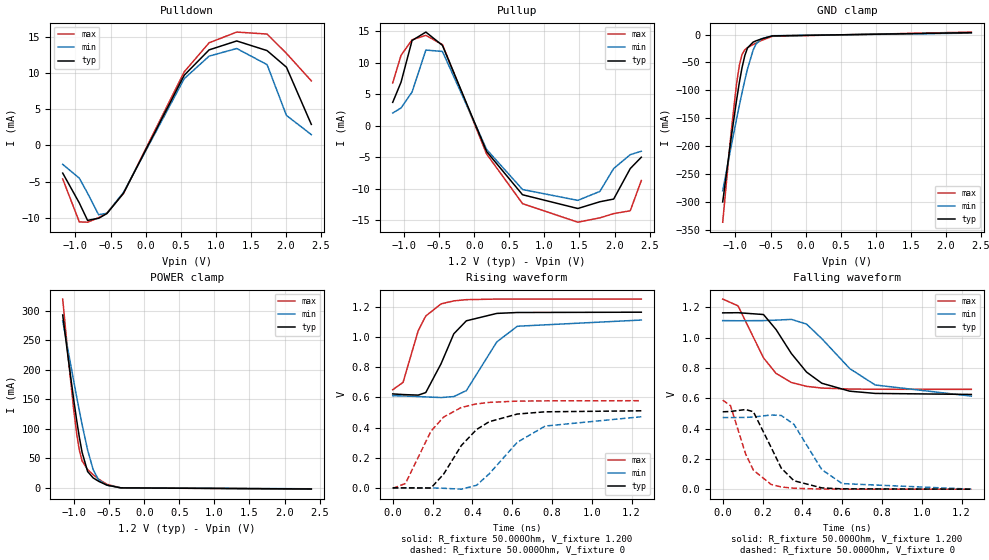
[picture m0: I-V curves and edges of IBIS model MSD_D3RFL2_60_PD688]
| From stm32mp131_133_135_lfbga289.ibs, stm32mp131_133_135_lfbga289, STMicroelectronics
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[Model] MSD_D3RFL2_60_PD688
Model_type   I/O
C_comp 2.461pF   2.375pF   2.586pF
Vinh = 820.000mV
Vinl = 380.000mV
Vmeas = 600.000mV
Vref = 600.000mV
[Model Spec]
Vinh   820.000mV   790.000mV   870.000mV
Vinl   380.000mV   350.000mV   430.000mV
Vmeas   600.000mV   570.000mV   650.000mV
Vref   600.000mV   570.000mV   650.000mV
[Receiver Thresholds]
Vth   =  0.600V
Vth_min  =  0.5880V
Vth_max  =  0.6120V
Vinh_ac  =  0.220V
Vinh_dc  =  0.130V
Vinl_ac  = -0.220V
Vinl_dc  = -0.130V
Tslew_ac =  5.000ns |Not specified, so set to high value
[Temperature Range]   25.000   125.000   -40.000
[Voltage Range]   1.200V   1.140V   1.300V
[GND Clamp Reference]   0.00V   0.00V   0.00V
[Pulldown Reference]   0.00V   0.00V   0.00V
[POWER Clamp Reference]   1.200V   1.140V   1.300V
[Pullup Reference]   1.200V   1.140V   1.300V
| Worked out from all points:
|   slope of the pulldown table from 0 to 0.18 V, typ, clamps not added: 50.1 ohm
|   slope of the pullup table from 0 to 0.18 V, typ, clamps not added: 42.9 ohm
|   GND clamp passes 1 mA (typ) near -0.40 V on its own axis
|   POWER clamp passes 1 mA (typ) near -0.41 V on its own axis
|   rising waveform, R_fixture 50.000Ohm, V_fixture 1.200: 20-80 % time 109ps typ, 140ps min, 91.6ps max; typ from 0.623 V to 1.16 V
|   rising waveform, R_fixture 50.000Ohm, V_fixture 0: 20-80 % time 183ps typ, 224ps min, 153ps max; typ from 0.001 V to 0.511 V
|   falling waveform, R_fixture 50.000Ohm, V_fixture 1.200: 20-80 % time 190ps typ, 242ps min, 153ps max; typ from 1.16 V to 0.625 V
|   falling waveform, R_fixture 50.000Ohm, V_fixture 0: 20-80 % time 113ps typ, 138ps min, 96.4ps max; typ from 0.51 V to 0 V
[GND Clamp]
-1.182V   -299.6mA   -279.7mA   -335.9mA
-1.064V   -187.4mA   -201.8mA   -177.5mA
-984.9mV  -117.9mA   -151.6mA   -88.6mA
-945.5mV  -86.54mA   -127.3mA   -55.77mA
-906.1mV  -59.13mA   -104mA     -35.64mA
-866.7mV  -37.61mA   -81.71mA   -27.22mA
-827.3mV  -23.8mA    -61.15mA   -23.42mA
-748.5mV  -13.62mA   -28.14mA   -17.95mA
-709.1mV  -11.42mA   -17.52mA   -15.44mA
-630.3mV  -7.875mA   -7.542mA   -10.71mA
-472.7mV  -2.454mA   -2.156mA   -3.182mA
2.364V    3.327mA    2.556mA    4.357mA
[Power Clamp]
-1.164V   292.5mA    282.6mA    319.4mA
-1.085V   218.7mA    230.9mA    220.2mA
-1.006V   148.5mA    180.1mA    131.2mA
-966.7mV  115.9mA    155.2mA    93.42mA
-927.3mV  86.16mA    130.9mA    64.04mA
-887.9mV  60.43mA    107.4mA    45.92mA
-809.1mV  27.85mA    64.33mA    31.18mA
-730.3mV  17.06mA    31.16mA    22.45mA
-651.5mV  11.24mA    13.38mA    14.99mA
-533.3mV  4.769mA    4.703mA    6.239mA
-336.4mV  190.8uA    361uA      219.4uA
2.382V    -1.713mA   -1.413mA   -2.032mA
[Pulldown]
-1.182V   -3.8mA     -2.6mA     -4.6mA
-945.5mV  -7.91mA    -4.5mA     -10.52mA
-827.3mV  -10.31mA   -6.57mA    -10.56mA
-669.7mV  -10.02mA   -9.53mA    -9.94mA
-551.5mV  -9.373mA   -9.335mA   -9.299mA
-315.1mV  -6.567mA   -6.465mA   -6.607mA
551.5mV   9.674mA    9.198mA    10.14mA
906.1mV   13.16mA    12.3mA     14.14mA
1.3V      14.39mA    13.35mA    15.61mA
1.733V    13.06mA    11.13mA    15.34mA
2.009V    10.78mA    4.14mA     12.68mA
2.364V    2.9mA      1.5mA      8.9mA
[Pullup]
-1.164V   3.7mA      2.005mA    6.785mA
-1.045V   6.9mA      2.809mA    11.16mA
-887.9mV  13.51mA    5.344mA    13.62mA
-690.9mV  14.84mA    11.99mA    14.32mA
-454.5mV  12.73mA    11.77mA    12.85mA
175.8mV   -4.108mA   -3.772mA   -4.491mA
687.9mV   -10.95mA   -10.12mA   -12.36mA
1.476V    -13.13mA   -11.84mA   -15.3mA
1.791V    -12.06mA   -10.42mA   -14.61mA
1.988V    -11.63mA   -6.784mA   -13.94mA
2.224V    -6.8mA     -4.595mA   -13.49mA
2.382V    -5mA       -4.048mA   -8.7mA
[Ramp]
R_load=50.000Ohm
dV/dt_r   315.030mV/147.500ps  292.319mV/184.000ps  351.210mV/122.500ps
dV/dt_f   315.000mV/152.500ps  292.290mV/192.500ps  351.210mV/124.500ps
[Rising waveform]
R_fixture=50.000Ohm
V_fixture=1.200
V_fixture_min=1.140
V_fixture_max=1.300
0s        622.7mV    610.6mV    650.2mV
52ps      618.5mV    609.3mV    699.2mV
128ps     614.8mV    605.3mV    1.041V
166ps     631.6mV    602.8mV    1.139V
243ps     822.8mV    598.6mV    1.219V
307ps     1.021V     605.2mV    1.239V
370ps     1.107V     644.6mV    1.247V
523ps     1.156V     967.3mV    1.251V
626ps     1.162V     1.071V     1.251V
1.249ns   1.164V     1.112V     1.251V
[Rising waveform]
R_fixture=50.000Ohm
V_fixture=0
0s        574.4uV    127.3uV    -3.509mV
64ps      247.6uV    471.3uV    29.6mV
192ps     -724.5uV   251.1uV    375.7mV
256ps     91.72mV    -2.437mV   469.7mV
345ps     281.3mV    -8.186mV   533.3mV
421ps     386.7mV    17.63mV    556.6mV
485ps     438.8mV    93.5mV     566.6mV
626ps     489.4mV    302.5mV    574.9mV
766ps     504.2mV    409.9mV    576.8mV
1.249ns   510.9mV    471.5mV    577.7mV
[Falling waveform]
R_fixture=50.000Ohm
V_fixture=1.200
V_fixture_min=1.140
V_fixture_max=1.300
0s        1.163V     1.112V     1.254V
77ps      1.164V     1.111V     1.209V
205ps     1.152V     1.112V     865.9mV
268ps     1.053V     1.115V     763.6mV
345ps     894.7mV    1.12V      703.5mV
421ps     772.5mV    1.089V     678.2mV
498ps     698.7mV    992.5mV    666.9mV
638ps     646.4mV    795.6mV    660.4mV
766ps     631.6mV    687.2mV    659.1mV
1.249ns   624.8mV    613.7mV    658.3mV
[Falling waveform]
R_fixture=50.000Ohm
V_fixture=0
0s        510.3mV    472.7mV    587.1mV
39ps      512.5mV    472.4mV    550.9mV
115ps     525.2mV    473.2mV    232.5mV
154ps     510.9mV    476.1mV    125.6mV
243ps     276.1mV    489.2mV    31.31mV
294ps     139.1mV    486.2mV    14.66mV
358ps     55.36mV    427.6mV    5.827mV
498ps     8.363mV    128.7mV    733.7uV
600ps     2.138mV    36.74mV    144uV
1.249ns   -4.24uV    21.19uV    -3.531uV
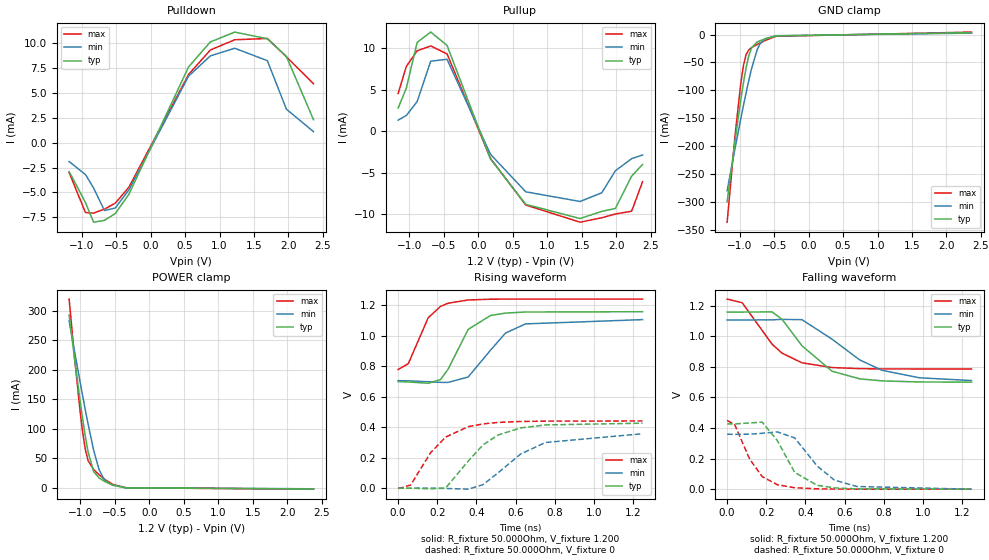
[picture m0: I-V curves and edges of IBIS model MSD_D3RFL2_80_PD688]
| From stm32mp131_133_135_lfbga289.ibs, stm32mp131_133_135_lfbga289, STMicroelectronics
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[Model] MSD_D3RFL2_80_PD688
Model_type   I/O
C_comp 2.461pF   2.375pF   2.586pF
Vinh = 820.000mV
Vinl = 380.000mV
Vmeas = 600.000mV
Vref = 600.000mV
[Model Spec]
Vinh   820.000mV   790.000mV   870.000mV
Vinl   380.000mV   350.000mV   430.000mV
Vmeas   600.000mV   570.000mV   650.000mV
Vref   600.000mV   570.000mV   650.000mV
[Receiver Thresholds]
Vth   =  0.600V
Vth_min  =  0.5880V
Vth_max  =  0.6120V
Vinh_ac  =  0.220V
Vinh_dc  =  0.130V
Vinl_ac  = -0.220V
Vinl_dc  = -0.130V
Tslew_ac =  5.000ns |Not specified, so set to high value
[Temperature Range]   25.000   125.000   -40.000
[Voltage Range]   1.200V   1.140V   1.300V
[GND Clamp Reference]   0.00V   0.00V   0.00V
[Pulldown Reference]   0.00V   0.00V   0.00V
[POWER Clamp Reference]   1.200V   1.140V   1.300V
[Pullup Reference]   1.200V   1.140V   1.300V
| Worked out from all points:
|   slope of the pulldown table from 0 to 0.18 V, typ, clamps not added: 63.6 ohm
|   slope of the pullup table from 0 to 0.18 V, typ, clamps not added: 52.8 ohm
|   GND clamp passes 1 mA (typ) near -0.40 V on its own axis
|   POWER clamp passes 1 mA (typ) near -0.41 V on its own axis
|   rising waveform, R_fixture 50.000Ohm, V_fixture 1.200: 20-80 % time 116ps typ, 151ps min, 102ps max; typ from 0.7 V to 1.16 V
|   rising waveform, R_fixture 50.000Ohm, V_fixture 0: 20-80 % time 191ps typ, 236ps min, 165ps max; typ from 0 V to 0.427 V
|   falling waveform, R_fixture 50.000Ohm, V_fixture 1.200: 20-80 % time 199ps typ, 274ps min, 179ps max; typ from 1.16 V to 0.7 V
|   falling waveform, R_fixture 50.000Ohm, V_fixture 0: 20-80 % time 118ps typ, 150ps min, 110ps max; typ from 0.427 V to 0 V
[GND Clamp]
-1.182V   -299.6mA   -279.7mA   -335.9mA
-1.064V   -187.4mA   -201.8mA   -177.5mA
-984.9mV  -117.9mA   -151.6mA   -88.6mA
-945.5mV  -86.54mA   -127.3mA   -55.77mA
-906.1mV  -59.13mA   -104mA     -35.64mA
-866.7mV  -37.61mA   -81.71mA   -27.22mA
-827.3mV  -23.8mA    -61.15mA   -23.42mA
-748.5mV  -13.62mA   -28.14mA   -17.95mA
-709.1mV  -11.42mA   -17.52mA   -15.44mA
-630.3mV  -7.875mA   -7.542mA   -10.71mA
-472.7mV  -2.454mA   -2.156mA   -3.182mA
2.364V    3.327mA    2.556mA    4.357mA
[Power Clamp]
-1.164V   292.5mA    282.6mA    319.4mA
-1.085V   218.7mA    230.9mA    220.2mA
-1.006V   148.5mA    180.1mA    131.2mA
-966.7mV  115.9mA    155.2mA    93.42mA
-927.3mV  86.16mA    130.9mA    64.04mA
-887.9mV  60.43mA    107.4mA    45.92mA
-809.1mV  27.85mA    64.33mA    31.18mA
-730.3mV  17.06mA    31.16mA    22.45mA
-651.5mV  11.24mA    13.38mA    14.99mA
-533.3mV  4.769mA    4.703mA    6.239mA
-336.4mV  190.8uA    361uA      219.4uA
2.382V    -1.713mA   -1.413mA   -2.032mA
[Pulldown]
-1.182V   -2.9mA     -1.9mA     -3mA
-945.5mV  -6mA       -3.2mA     -7.01mA
-827.3mV  -7.98mA    -4.55mA    -7.07mA
-669.7mV  -7.8mA     -6.81mA    -6.67mA
-512.1mV  -7.111mA   -6.556mA   -6.071mA
-315.1mV  -5.181mA   -4.739mA   -4.478mA
551.5mV   7.6mA      6.678mA    6.842mA
866.7mV   10.1mA     8.7mA      9.293mA
1.221V    11.09mA    9.469mA    10.32mA
1.694V    10.42mA    8.223mA    10.45mA
1.97V     8.65mA     3.36mA     8.62mA
2.364V    2.3mA      1.1mA      5.9mA
[Pullup]
-1.164V   2.8mA      1.352mA    4.554mA
-1.045V   5.2mA      1.905mA    7.823mA
-887.9mV  10.72mA    3.587mA    9.704mA
-690.9mV  11.96mA    8.455mA    10.29mA
-454.5mV  10.36mA    8.682mA    9.331mA
175.8mV   -3.334mA   -2.766mA   -3.264mA
687.9mV   -8.798mA   -7.289mA   -8.88mA
1.476V    -10.51mA   -8.454mA   -10.95mA
1.791V    -9.643mA   -7.404mA   -10.42mA
1.988V    -9.3mA     -4.754mA   -9.962mA
2.224V    -5.4mA     -3.295mA   -9.625mA
2.382V    -4mA       -2.848mA   -6.085mA
[Ramp]
R_load=50.000Ohm
dV/dt_r   266.010mV/154.500ps  228.029mV/195.000ps  269.370mV/134.000ps
dV/dt_f   266.010mV/158.500ps  227.999mV/215.500ps  269.370mV/144.500ps
[Rising waveform]
R_fixture=50.000Ohm
V_fixture=1.200
V_fixture_min=1.140
V_fixture_max=1.300
0s        700.1mV    706.5mV    779.2mV
52ps      697.9mV    705.1mV    817.8mV
154ps     689.2mV    699.3mV    1.12V
217ps     713.8mV    695.3mV    1.194V
256ps     782.8mV    695mV      1.215V
358ps     1.043V     730.4mV    1.236V
472ps     1.134V     906.1mV    1.241V
549ps     1.15V      1.019V     1.242V
651ps     1.157V     1.079V     1.242V
1.249ns   1.159V     1.107V     1.242V
[Rising waveform]
R_fixture=50.000Ohm
V_fixture=0
0s        149.8uV    105.9uV    -2.526mV
64ps      580.6uV    375.6uV    21.13mV
166ps     -3.428mV   469.3uV    233.4mV
243ps     2.018mV    -1.343mV   336mV
358ps     177.7mV    -5.961mV   404.1mV
434ps     285mV      23.75mV    422.6mV
511ps     349.8mV    101.8mV    432.2mV
626ps     396mV      224.8mV    438.4mV
753ps     415.8mV    300.4mV    440.6mV
1.249ns   427.2mV    357.9mV    441.9mV
[Falling waveform]
R_fixture=50.000Ohm
V_fixture=1.200
V_fixture_min=1.140
V_fixture_max=1.300
0s        1.159V     1.107V     1.244V
77ps      1.159V     1.107V     1.22V
230ps     1.16V      1.108V     948.1mV
281ps     1.111V     1.111V     889.7mV
383ps     937.8mV    1.109V     826.7mV
536ps     771.9mV    981.7mV    795.9mV
677ps     722.1mV    846.2mV    788.7mV
791ps     708.5mV    778.1mV    787mV
983ps     701.6mV    728.8mV    786.3mV
1.249ns   700.2mV    710.7mV    786.2mV
[Falling waveform]
R_fixture=50.000Ohm
V_fixture=0
0s        427mV      359.3mV    449.8mV
39ps      426.8mV    359mV      421.3mV
115ps     433.2mV    359.9mV    197mV
179ps     438.7mV    365.6mV    82.75mV
256ps     319.1mV    375mV      29.32mV
345ps     110.4mV    335.6mV    9.438mV
460ps     25.15mV    151.5mV    2.238mV
549ps     8.372mV    58.75mV    684.9uV
664ps     1.951mV    17.28mV    112uV
1.249ns   -7.944uV   19.11uV    5.618uV
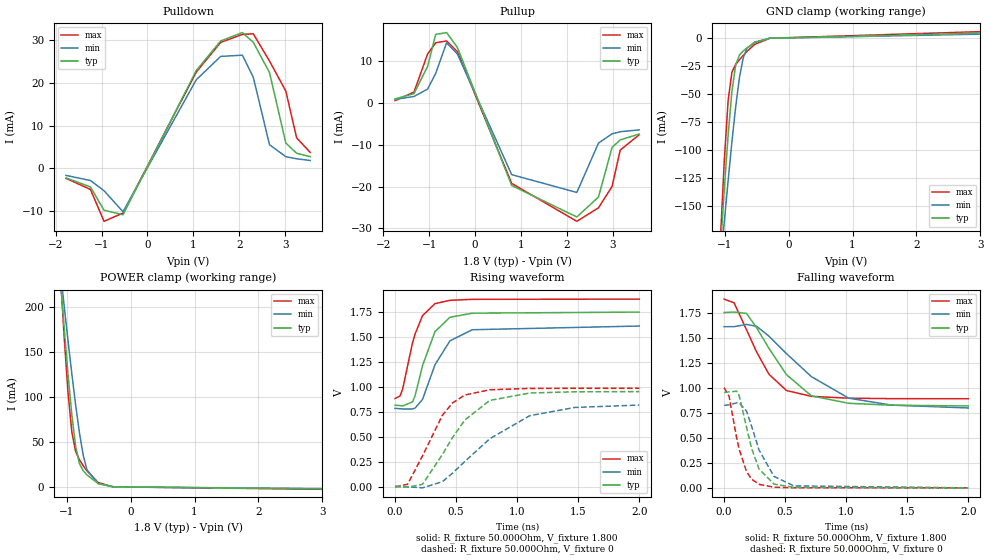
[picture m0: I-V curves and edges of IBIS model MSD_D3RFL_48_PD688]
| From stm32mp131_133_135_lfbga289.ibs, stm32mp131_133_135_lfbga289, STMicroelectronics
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[Model] MSD_D3RFL_48_PD688
Model_type   I/O
C_comp 2.432pF   2.347pF   2.556pF
Vinh = 1.440V
Vinl = 360.000mV
Vmeas = 900.000mV
Vref = 900.000mV
[Model Spec]
Vinh   1.440V   1.365V   1.515V
Vinl   360.000mV   285.000mV   435.000mV
Vmeas   900.000mV   825.000mV   975.000mV
Vref   900.000mV   825.000mV   975.000mV
[Temperature Range]   25.000   125.000   -40.000
[Voltage Range]   1.800V   1.650V   1.950V
[GND Clamp Reference]   0.00V   0.00V   0.00V
[Pulldown Reference]   0.00V   0.00V   0.00V
[POWER Clamp Reference]   1.800V   1.650V   1.950V
[Pullup Reference]   1.800V   1.650V   1.950V
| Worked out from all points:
|   slope of the pulldown table from 0 to 0.27 V, typ, clamps not added: 41 ohm
|   slope of the pullup table from 0 to 0.27 V, typ, clamps not added: 32.3 ohm
|   GND clamp passes 1 mA (typ) near -0.40 V on its own axis
|   POWER clamp passes 1 mA (typ) near -0.41 V on its own axis
|   rising waveform, R_fixture 50.000Ohm, V_fixture 1.800: 20-80 % time 148ps typ, 188ps min, 131ps max; typ from 0.817 V to 1.75 V
|   rising waveform, R_fixture 50.000Ohm, V_fixture 0: 20-80 % time 320ps typ, 496ps min, 248ps max; typ from 0.001 V to 0.953 V
|   falling waveform, R_fixture 50.000Ohm, V_fixture 1.800: 20-80 % time 322ps typ, 470ps min, 250ps max; typ from 1.75 V to 0.818 V
|   falling waveform, R_fixture 50.000Ohm, V_fixture 0: 20-80 % time 128ps typ, 160ps min, 111ps max; typ from 0.952 V to 0 V
[GND Clamp]
-1.773V   -890.7mA   -681.8mA   -1.194A
-1.064V   -187.3mA   -201.8mA   -177.4mA
-1.005V   -134.6mA   -164mA     -108.6mA
-945.5mV  -86.53mA   -127.4mA   -55.77mA
-886.4mV  -47.49mA   -92.64mA   -30.41mA
-827.3mV  -23.8mA    -61.14mA   -23.41mA
-768.2mV  -15.03mA   -35.07mA   -19.25mA
-709.1mV  -11.42mA   -17.51mA   -15.43mA
-650mV    -8.703mA   -9.033mA   -11.85mA
-531.8mV  -4.189mA   -3.545mA   -5.596mA
-295.4mV  -95.88uA   -151.6uA   -81.74uA
3.545V    5.304mA    4.208mA    6.797mA
[Power Clamp]
-1.745V   860.3mA    674.7mA    1.127A
-1.095V   228.6mA    238mA      233.5mA
-1.036V   175mA      199.7mA    164.4mA
-977.3mV  124.5mA    162.1mA    104.1mA
-918.2mV  79.86mA    125.6mA    60.82mA
-859.1mV  45.22mA    91.19mA    39.29mA
-800mV    25.91mA    60.32mA    30.18mA
-740.9mV  18.04mA    35.46mA    23.6mA
-681.8mV  13.33mA    19.05mA    17.78mA
-504.5mV  3.599mA    3.702mA    4.72mA
-268.2mV  28.01uA    97.94uA    31.4uA
3.573V    -2.684mA   -2.333mA   -3.133mA
[Pulldown]
-1.773V   -2.3mA     -1.7mA     -2.4mA
-1.241V   -4.4mA     -2.9mA     -5mA
-945.5mV  -9.88mA    -5.3mA     -12.48mA
-531.8mV  -10.94mA   -10.23mA   -10.54mA
1.064V    22.93mA    20.76mA    22.57mA
1.595V    29.86mA    26.24mA    29.55mA
2.068V    31.84mA    26.53mA    31.41mA
2.305V    29.56mA    21.37mA    31.55mA
2.659V    22.45mA    5.5mA      25.15mA
3.014V    5.9mA      2.7mA      18.1mA
3.25V     3.5mA      2.2mA      7.1mA
3.545V    2.7mA      1.8mA      3.7mA
[Pullup]
-1.745V   1mA        900uA      600uA
-1.332V   2.3mA      1.608mA    2.669mA
-1.036V   8.8mA      3.377mA    11.79mA
-859.1mV  16.48mA    7.15mA     14.48mA
-622.7mV  16.92mA    14.48mA    14.91mA
-386.4mV  13.34mA    11.76mA    12.34mA
795.5mV   -19.73mA   -17.13mA   -19.23mA
2.214V    -27.27mA   -21.4mA    -28.31mA
2.686V    -22.49mA   -9.569mA   -25.08mA
2.982V    -10.6mA    -7.338mA   -19.95mA
3.159V    -8.8mA     -6.846mA   -11.25mA
3.573V    -7.4mA     -6.4mA     -7.554mA
[Ramp]
R_load=50.000Ohm
dV/dt_r   566.190mV/234.500ps  492.569mV/343.000ps  593.250mV/190.000ps
dV/dt_f   566.099mV/226.000ps  491.604mV/315.500ps  593.250mV/180.500ps
[Rising waveform]
R_fixture=50.000Ohm
V_fixture=1.800
V_fixture_min=1.650
V_fixture_max=1.950
0s        817mV      785.3mV    883.7mV
41ps      812.4mV    781mV      909.8mV
62ps      809.3mV    778.3mV    977.5mV
143ps     849.8mV    779.2mV    1.442V
164ps     911.8mV    788.3mV    1.531V
225ps     1.214V     874.6mV    1.715V
327ps     1.555V     1.222V     1.836V
450ps     1.699V     1.463V     1.869V
633ps     1.74V      1.574V     1.879V
2ns       1.751V     1.611V     1.881V
[Rising waveform]
R_fixture=50.000Ohm
V_fixture=0
0s        1.032mV    1.188mV    -2.542mV
103ps     -5.662mV   -1.608mV   23.78mV
225ps     22.51mV    -12.8mV    308.2mV
388ps     321.7mV    49.39mV    716.2mV
470ps     491.5mV    133.9mV    838.7mV
572ps     667.7mV    252.5mV    919mV
776ps     864.8mV    480.2mV    971.6mV
1.103ns   938.8mV    711.2mV    984.9mV
1.471ns   951.4mV    794mV      986.2mV
2ns       953.1mV    817.9mV    986.3mV
[Falling waveform]
R_fixture=50.000Ohm
V_fixture=1.800
V_fixture_min=1.650
V_fixture_max=1.950
0s        1.751V     1.61V      1.885V
82ps      1.756V     1.61V      1.848V
184ps     1.742V     1.632V     1.579V
266ps     1.6V       1.614V     1.358V
368ps     1.393V     1.515V     1.134V
511ps     1.131V     1.341V     972.4mV
715ps     919.6mV    1.111V     914.1mV
1.021ns   844.6mV    895.9mV    895.6mV
1.369ns   825.5mV    826.8mV    891mV
2ns       818mV      797.9mV    890mV
[Falling waveform]
R_fixture=50.000Ohm
V_fixture=0
0s        952.4mV    824.5mV    1.001V
41ps      958.3mV    828.8mV    913.6mV
103ps     965.4mV    849mV      500.2mV
123ps     923.3mV    850.4mV    387.7mV
184ps     605.8mV    766.4mV    161.8mV
225ps     396.1mV    617.4mV    87.67mV
286ps     189.1mV    379.2mV    35.47mV
409ps     37.1mV     114.1mV    6.239mV
572ps     5.283mV    19.59mV    1.049mV
2ns       14.94uV    92.6uV     2.152uV
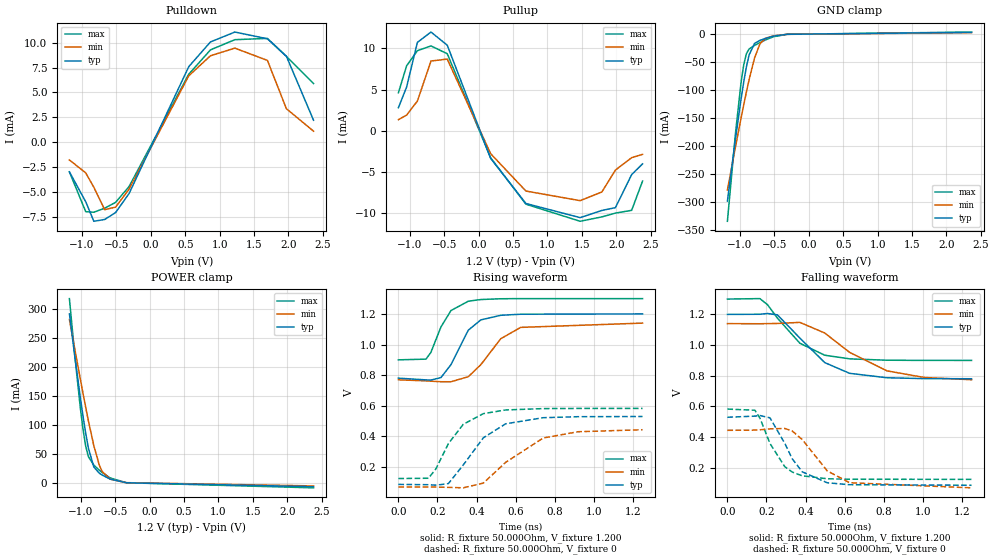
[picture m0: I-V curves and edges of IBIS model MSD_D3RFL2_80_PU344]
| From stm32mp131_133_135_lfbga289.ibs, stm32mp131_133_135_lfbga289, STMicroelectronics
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[Model] MSD_D3RFL2_80_PU344
Model_type   I/O
C_comp 2.348pF   2.261pF   2.473pF
Vinh = 820.000mV
Vinl = 380.000mV
Vmeas = 600.000mV
Vref = 600.000mV
[Model Spec]
Vinh   820.000mV   790.000mV   870.000mV
Vinl   380.000mV   350.000mV   430.000mV
Vmeas   600.000mV   570.000mV   650.000mV
Vref   600.000mV   570.000mV   650.000mV
[Receiver Thresholds]
Vth   =  0.600V
Vth_min  =  0.5880V
Vth_max  =  0.6120V
Vinh_ac  =  0.220V
Vinh_dc  =  0.130V
Vinl_ac  = -0.220V
Vinl_dc  = -0.130V
Tslew_ac =  5.000ns |Not specified, so set to high value
[Temperature Range]   25.000   125.000   -40.000
[Voltage Range]   1.200V   1.140V   1.300V
[GND Clamp Reference]   0.00V   0.00V   0.00V
[Pulldown Reference]   0.00V   0.00V   0.00V
[POWER Clamp Reference]   1.200V   1.140V   1.300V
[Pullup Reference]   1.200V   1.140V   1.300V
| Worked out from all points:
|   slope of the pulldown table from 0 to 0.18 V, typ, clamps not added: 63.6 ohm
|   slope of the pullup table from 0 to 0.18 V, typ, clamps not added: 52.8 ohm
|   GND clamp passes 1 mA (typ) near -0.41 V on its own axis
|   POWER clamp passes 1 mA (typ) near -0.41 V on its own axis
|   rising waveform, R_fixture 50.000Ohm, V_fixture 1.200: 20-80 % time 105ps typ, 142ps min, 90.6ps max; typ from 0.78 V to 1.2 V
|   rising waveform, R_fixture 50.000Ohm, V_fixture 0: 20-80 % time 170ps typ, 216ps min, 141ps max; typ from 0.086 V to 0.53 V
|   falling waveform, R_fixture 50.000Ohm, V_fixture 1.200: 20-80 % time 198ps typ, 271ps min, 177ps max; typ from 1.2 V to 0.78 V
|   falling waveform, R_fixture 50.000Ohm, V_fixture 0: 20-80 % time 118ps typ, 156ps min, 109ps max; typ from 0.53 V to 0.086 V
[GND Clamp]
-1.182V   -298.5mA   -278.7mA   -334.6mA
-1.064V   -186.4mA   -201mA     -176.4mA
-984.9mV  -117.1mA   -150.9mA   -87.65mA
-945.5mV  -85.8mA    -126.7mA   -54.89mA
-906.1mV  -58.45mA   -103.4mA   -34.82mA
-866.7mV  -36.99mA   -81.15mA   -26.46mA
-787.9mV  -16.43mA   -42.51mA   -19.96mA
-709.1mV  -11.02mA   -17.14mA   -14.94mA
-630.3mV  -7.563mA   -7.255mA   -10.33mA
-512.1mV  -3.391mA   -2.874mA   -4.513mA
-315.1mV  -135.6uA   -195uA     -130uA
2.364V    3.306mA    2.793mA    3.888mA
[Power Clamp]
-1.164V   291.7mA    282.1mA    318.2mA
-1.085V   217.9mA    230.5mA    219.1mA
-1.006V   147.8mA    179.6mA    130.3mA
-966.7mV  115.4mA    154.8mA    92.58mA
-927.3mV  85.61mA    130.5mA    63.27mA
-887.9mV  59.92mA    107mA      45.21mA
-809.1mV  27.42mA    64.02mA    30.59mA
-730.3mV  16.72mA    30.92mA    21.98mA
-690.9mV  13.66mA    20.11mA    18.17mA
-572.7mV  6.48mA     6.432mA    8.549mA
-336.4mV  188.5uA    360.2uA    208.2uA
2.382V    -6.618mA   -5.26mA    -8.576mA
[Pulldown]
-1.182V   -3mA       -1.8mA     -3mA
-945.5mV  -6.01mA    -3.1mA     -7.01mA
-827.3mV  -7.98mA    -4.55mA    -7.07mA
-669.7mV  -7.8mA     -6.81mA    -6.66mA
-512.1mV  -7.108mA   -6.559mA   -6.08mA
-315.1mV  -5.18mA    -4.738mA   -4.478mA
551.5mV   7.601mA    6.678mA    6.842mA
866.7mV   10.09mA    8.7mA      9.292mA
1.221V    11.09mA    9.469mA    10.32mA
1.694V    10.41mA    8.231mA    10.45mA
1.97V     8.65mA     3.36mA     8.63mA
2.364V    2.2mA      1.1mA      5.9mA
[Pullup]
-1.164V   2.8mA      1.352mA    4.608mA
-1.045V   5.3mA      1.909mA    7.869mA
-887.9mV  10.71mA    3.609mA    9.704mA
-690.9mV  11.96mA    8.455mA    10.28mA
-454.5mV  10.37mA    8.682mA    9.334mA
175.8mV   -3.334mA   -2.766mA   -3.264mA
687.9mV   -8.798mA   -7.289mA   -8.881mA
1.476V    -10.51mA   -8.455mA   -10.95mA
1.791V    -9.64mA    -7.404mA   -10.42mA
1.988V    -9.3mA     -4.754mA   -9.962mA
2.224V    -5.3mA     -3.248mA   -9.625mA
2.382V    -4mA       -2.848mA   -6.085mA
[Ramp]
R_load=50.000Ohm
dV/dt_r   259.011mV/138.000ps  223.740mV/181.500ps  257.460mV/116.500ps
dV/dt_f   259.011mV/159.500ps  223.650mV/217.000ps  257.460mV/144.000ps
[Rising waveform]
R_fixture=50.000Ohm
V_fixture=1.200
V_fixture_min=1.140
V_fixture_max=1.300
0s        780.4mV    769.6mV    900.1mV
141ps     769.2mV    762.7mV    904.6mV
166ps     767.6mV    760.8mV    948.1mV
218ps     784.3mV    757.1mV    1.115V
269ps     868.5mV    756.9mV    1.222V
358ps     1.094V     790.1mV    1.283V
422ps     1.161V     868.4mV    1.294V
524ps     1.191V     1.038V     1.299V
626ps     1.198V     1.112V     1.3V
1.25ns    1.2V       1.14V      1.3V
[Rising waveform]
R_fixture=50.000Ohm
V_fixture=0
0s        86.41mV    69.47mV    124.8mV
154ps     84.51mV    69.49mV    126.7mV
192ps     81.45mV    69.09mV    188mV
256ps     91.7mV     67.2mV     353mV
332ps     213.4mV    64.07mV    478.9mV
435ps     391.1mV    94.93mV    548.8mV
549ps     482.1mV    230.4mV    572.7mV
741ps     522.1mV    389.3mV    581.6mV
920ps     528.7mV    430.5mV    582.6mV
1.25ns    530mV      443.6mV    582.8mV
[Falling waveform]
R_fixture=50.000Ohm
V_fixture=1.200
V_fixture_min=1.140
V_fixture_max=1.300
0s        1.2V       1.14V      1.3V
166ps     1.201V     1.139V     1.303V
205ps     1.206V     1.14V      1.264V
256ps     1.197V     1.141V     1.176V
371ps     1.046V     1.148V     1.012V
498ps     886.1mV    1.079V     934.2mV
626ps     815.8mV    952.3mV    910.2mV
817ps     787.1mV    832mV      901.4mV
1.009ns   781.3mV    788.7mV    900.2mV
1.25ns    780.5mV    774.2mV    900mV
[Falling waveform]
R_fixture=50.000Ohm
V_fixture=0
0s        529.6mV    444.4mV    582.8mV
141ps     536.9mV    445.8mV    575.3mV
166ps     540.8mV    447.7mV    525.3mV
218ps     525.9mV    453.9mV    358.4mV
294ps     359mV      456.4mV    207.1mV
332ps     258.7mV    439.8mV    172.3mV
383ps     174.1mV    384.3mV    148mV
511ps     102.5mV    180.1mV    128.7mV
626ps     89.78mV    102.7mV    125.5mV
1.25ns    86.32mV    69.47mV    124.7mV
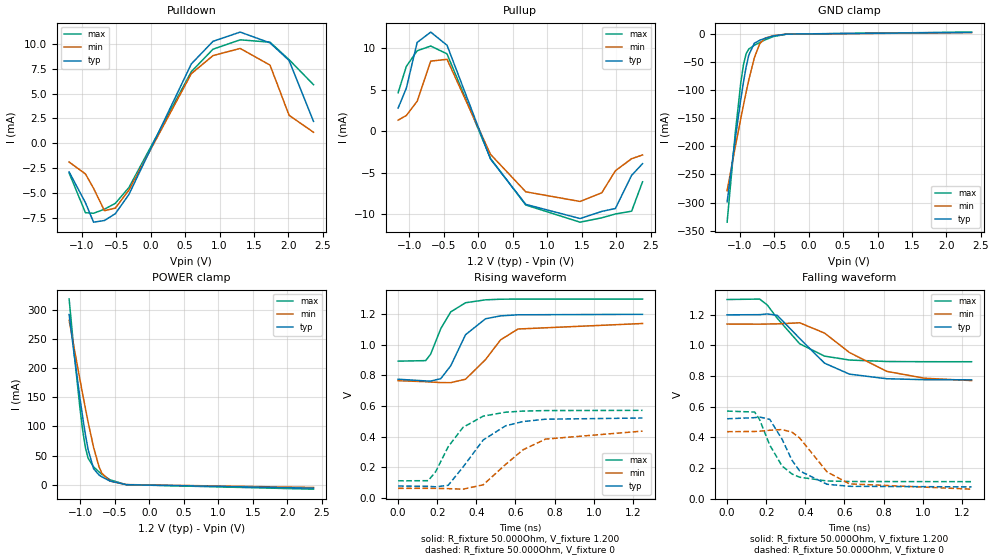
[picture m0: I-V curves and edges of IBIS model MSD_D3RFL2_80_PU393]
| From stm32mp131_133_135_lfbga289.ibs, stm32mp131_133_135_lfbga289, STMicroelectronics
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[Model] MSD_D3RFL2_80_PU393
Model_type   I/O
C_comp 2.377pF   2.291pF   2.503pF
Vinh = 820.000mV
Vinl = 380.000mV
Vmeas = 600.000mV
Vref = 600.000mV
[Model Spec]
Vinh   820.000mV   790.000mV   870.000mV
Vinl   380.000mV   350.000mV   430.000mV
Vmeas   600.000mV   570.000mV   650.000mV
Vref   600.000mV   570.000mV   650.000mV
[Receiver Thresholds]
Vth   =  0.600V
Vth_min  =  0.5880V
Vth_max  =  0.6120V
Vinh_ac  =  0.220V
Vinh_dc  =  0.130V
Vinl_ac  = -0.220V
Vinl_dc  = -0.130V
Tslew_ac =  5.000ns |Not specified, so set to high value
[Temperature Range]   25.000   125.000   -40.000
[Voltage Range]   1.200V   1.140V   1.300V
[GND Clamp Reference]   0.00V   0.00V   0.00V
[Pulldown Reference]   0.00V   0.00V   0.00V
[POWER Clamp Reference]   1.200V   1.140V   1.300V
[Pullup Reference]   1.200V   1.140V   1.300V
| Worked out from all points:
|   slope of the pulldown table from 0 to 0.18 V, typ, clamps not added: 63.6 ohm
|   slope of the pullup table from 0 to 0.18 V, typ, clamps not added: 52.8 ohm
|   GND clamp passes 1 mA (typ) near -0.41 V on its own axis
|   POWER clamp passes 1 mA (typ) near -0.41 V on its own axis
|   rising waveform, R_fixture 50.000Ohm, V_fixture 1.200: 20-80 % time 107ps typ, 144ps min, 92.3ps max; typ from 0.775 V to 1.2 V
|   rising waveform, R_fixture 50.000Ohm, V_fixture 0: 20-80 % time 174ps typ, 220ps min, 145ps max; typ from 0.076 V to 0.522 V
|   falling waveform, R_fixture 50.000Ohm, V_fixture 1.200: 20-80 % time 200ps typ, 272ps min, 180ps max; typ from 1.2 V to 0.775 V
|   falling waveform, R_fixture 50.000Ohm, V_fixture 0: 20-80 % time 119ps typ, 156ps min, 110ps max; typ from 0.521 V to 0.076 V
[GND Clamp]
-1.182V   -298.8mA   -278.8mA   -334.9mA
-1.064V   -186.6mA   -201.1mA   -176.7mA
-984.9mV  -117.3mA   -151.1mA   -87.88mA
-945.5mV  -85.98mA   -126.9mA   -55.1mA
-906.1mV  -58.6mA    -103.4mA   -35.03mA
-866.7mV  -37.14mA   -81.28mA   -26.65mA
-787.9mV  -16.55mA   -42.62mA   -20.11mA
-709.1mV  -11.11mA   -17.23mA   -15.06mA
-630.3mV  -7.64mA    -7.317mA   -10.42mA
-512.1mV  -3.431mA   -2.91mA    -4.569mA
-315.1mV  -140uA     -201.2uA   -134.4uA
2.364V    2.893mA    2.444mA    3.402mA
[Power Clamp]
-1.164V   291.9mA    282.3mA    318.5mA
-1.085V   218.2mA    230.6mA    219.4mA
-1.006V   148mA      179.8mA    130.6mA
-966.7mV  115.5mA    154.9mA    92.81mA
-927.3mV  85.77mA    130.6mA    63.48mA
-887.9mV  60.06mA    107.1mA    45.4mA
-809.1mV  27.54mA    64.12mA    30.75mA
-730.3mV  16.82mA    31mA       22.11mA
-690.9mV  13.74mA    20.18mA    18.27mA
-572.7mV  6.53mA     6.478mA    8.613mA
-336.4mV  191.9uA    365.4uA    212.3uA
2.382V    -5.79mA    -4.601mA   -7.505mA
[Pulldown]
-1.182V   -2.9mA     -1.9mA     -3mA
-945.5mV  -6mA       -3.1mA     -7.01mA
-827.3mV  -7.97mA    -4.55mA    -7.07mA
-669.7mV  -7.8mA     -6.81mA    -6.66mA
-512.1mV  -7.114mA   -6.552mA   -6.07mA
-315.1mV  -5.181mA   -4.739mA   -4.478mA
590.9mV   8.001mA    7.015mA    7.22mA
906.1mV   10.28mA    8.839mA    9.487mA
1.3V      11.21mA    9.56mA     10.43mA
1.733V    10.12mA    7.877mA    10.19mA
2.009V    8.35mA     2.82mA     8.43mA
2.364V    2.2mA      1.1mA      5.9mA
[Pullup]
-1.164V   2.8mA      1.352mA    4.654mA
-1.045V   5.2mA      1.905mA    7.823mA
-887.9mV  10.71mA    3.624mA    9.708mA
-690.9mV  11.96mA    8.46mA     10.28mA
-454.5mV  10.37mA    8.68mA     9.333mA
175.8mV   -3.334mA   -2.766mA   -3.264mA
687.9mV   -8.801mA   -7.289mA   -8.88mA
1.476V    -10.51mA   -8.452mA   -10.95mA
1.791V    -9.65mA    -7.404mA   -10.42mA
1.988V    -9.3mA     -4.754mA   -9.962mA
2.224V    -5.3mA     -3.295mA   -9.62mA
2.382V    -3.9mA     -2.848mA   -6.085mA
[Ramp]
R_load=50.000Ohm
dV/dt_r   261.051mV/141.500ps  225.054mV/183.500ps  260.310mV/119.000ps
dV/dt_f   261.051mV/161.000ps  225.021mV/219.000ps  260.310mV/146.000ps
[Rising waveform]
R_fixture=50.000Ohm
V_fixture=1.200
V_fixture_min=1.140
V_fixture_max=1.300
0s        775.3mV    765.8mV    893.6mV
141ps     764.2mV    759.1mV    897mV
166ps     762.6mV    757.1mV    938.7mV
218ps     779.1mV    753.4mV    1.106V
269ps     863mV      753mV      1.216V
345ps     1.067V     775.4mV    1.276V
447ps     1.171V     903.9mV    1.295V
524ps     1.19V      1.033V     1.299V
613ps     1.197V     1.104V     1.3V
1.25ns    1.2V       1.14V      1.3V
[Rising waveform]
R_fixture=50.000Ohm
V_fixture=0
0s        76.2mV     61.19mV    110.3mV
154ps     74.39mV    61.28mV    111.3mV
192ps     71.27mV    60.91mV    170.3mV
256ps     80.99mV    59.09mV    333.2mV
332ps     200.5mV    55.74mV    460.4mV
435ps     377.6mV    84.23mV    533.6mV
549ps     470.1mV    216.9mV    559.6mV
639ps     498.4mV    313.7mV    566.8mV
754ps     513.7mV    383.4mV    570.1mV
1.25ns    521.5mV    435.8mV    571.5mV
[Falling waveform]
R_fixture=50.000Ohm
V_fixture=1.200
V_fixture_min=1.140
V_fixture_max=1.300
0s        1.2V       1.14V      1.3V
166ps     1.201V     1.139V     1.303V
205ps     1.206V     1.14V      1.265V
256ps     1.197V     1.141V     1.178V
371ps     1.046V     1.148V     1.011V
498ps     884.5mV    1.081V     930.4mV
626ps     812.5mV    953.5mV    904.8mV
817ps     782.6mV    830.7mV    895.1mV
1.009ns   776.4mV    785.9mV    893.8mV
1.25ns    775.4mV    770.7mV    893.7mV
[Falling waveform]
R_fixture=50.000Ohm
V_fixture=0
0s        521.1mV    436.8mV    571.3mV
141ps     528.4mV    438.1mV    564.9mV
166ps     532.5mV    440mV      516.1mV
218ps     517.4mV    446.1mV    349mV
281ps     387.7mV    450.6mV    212.8mV
332ps     249.6mV    433.4mV    160.2mV
371ps     180.6mV    395.5mV    139.3mV
511ps     93.39mV    174.2mV    114.8mV
626ps     79.94mV    95.81mV    111.3mV
1.25ns    76.12mV    61.32mV    110.3mV
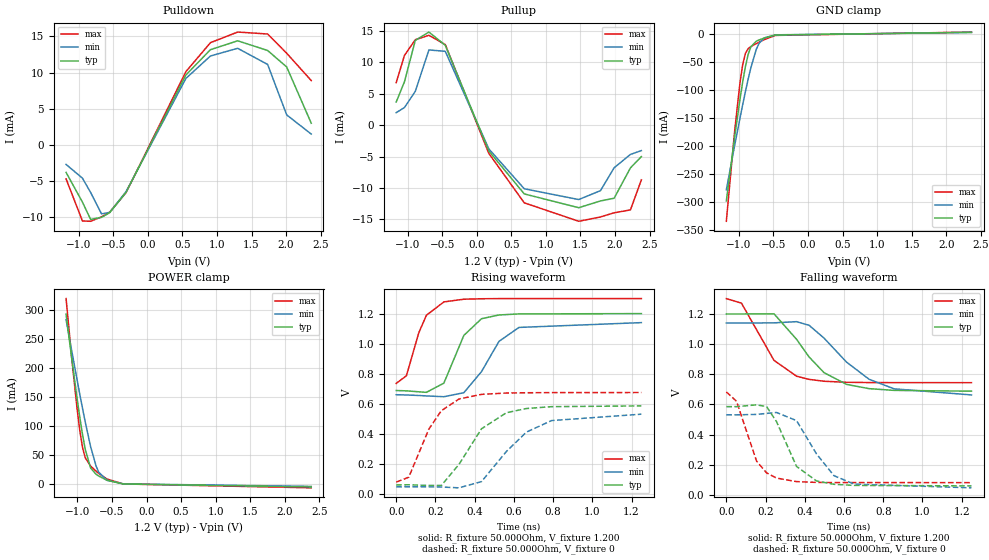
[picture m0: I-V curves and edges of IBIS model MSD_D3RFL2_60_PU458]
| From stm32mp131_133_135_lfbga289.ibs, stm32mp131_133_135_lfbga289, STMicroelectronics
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[Model] MSD_D3RFL2_60_PU458
Model_type   I/O
C_comp 2.406pF   2.319pF   2.532pF
Vinh = 820.000mV
Vinl = 380.000mV
Vmeas = 600.000mV
Vref = 600.000mV
[Model Spec]
Vinh   820.000mV   790.000mV   870.000mV
Vinl   380.000mV   350.000mV   430.000mV
Vmeas   600.000mV   570.000mV   650.000mV
Vref   600.000mV   570.000mV   650.000mV
[Receiver Thresholds]
Vth   =  0.600V
Vth_min  =  0.5880V
Vth_max  =  0.6120V
Vinh_ac  =  0.220V
Vinh_dc  =  0.130V
Vinl_ac  = -0.220V
Vinl_dc  = -0.130V
Tslew_ac =  5.000ns |Not specified, so set to high value
[Temperature Range]   25.000   125.000   -40.000
[Voltage Range]   1.200V   1.140V   1.300V
[GND Clamp Reference]   0.00V   0.00V   0.00V
[Pulldown Reference]   0.00V   0.00V   0.00V
[POWER Clamp Reference]   1.200V   1.140V   1.300V
[Pullup Reference]   1.200V   1.140V   1.300V
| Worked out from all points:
|   slope of the pulldown table from 0 to 0.18 V, typ, clamps not added: 50.1 ohm
|   slope of the pullup table from 0 to 0.18 V, typ, clamps not added: 42.9 ohm
|   GND clamp passes 1 mA (typ) near -0.40 V on its own axis
|   POWER clamp passes 1 mA (typ) near -0.41 V on its own axis
|   rising waveform, R_fixture 50.000Ohm, V_fixture 1.200: 20-80 % time 104ps typ, 135ps min, 84.8ps max; typ from 0.688 V to 1.2 V
|   rising waveform, R_fixture 50.000Ohm, V_fixture 0: 20-80 % time 168ps typ, 209ps min, 137ps max; typ from 0.059 V to 0.585 V
|   falling waveform, R_fixture 50.000Ohm, V_fixture 1.200: 20-80 % time 196ps typ, 246ps min, 157ps max; typ from 1.2 V to 0.688 V
|   falling waveform, R_fixture 50.000Ohm, V_fixture 0: 20-80 % time 116ps typ, 143ps min, 98.2ps max; typ from 0.585 V to 0.059 V
[GND Clamp]
-1.182V   -299mA     -279mA     -335.2mA
-1.064V   -186.9mA   -201.3mA   -176.9mA
-984.9mV  -117.5mA   -151.2mA   -88.11mA
-945.5mV  -86.15mA   -126.9mA   -55.31mA
-906.1mV  -58.77mA   -103.6mA   -35.22mA
-866.7mV  -37.28mA   -81.4mA    -26.82mA
-827.3mV  -23.51mA   -60.86mA   -23.06mA
-748.5mV  -13.37mA   -27.9mA    -17.67mA
-709.1mV  -11.21mA   -17.31mA   -15.18mA
-630.3mV  -7.712mA   -7.374mA   -10.51mA
-472.7mV  -2.381mA   -2.076mA   -3.096mA
2.364V    2.48mA     2.095mA    2.917mA
[Power Clamp]
-1.164V   292.1mA    282.5mA    318.8mA
-1.085V   218.4mA    230.8mA    219.7mA
-1.006V   148.3mA    180mA      130.8mA
-966.7mV  115.6mA    155.1mA    93.04mA
-927.3mV  85.92mA    130.8mA    63.68mA
-887.9mV  60.21mA    107.3mA    45.58mA
-809.1mV  27.67mA    64.23mA    30.9mA
-730.3mV  16.91mA    31.08mA    22.23mA
-690.9mV  13.83mA    20.26mA    18.38mA
-572.7mV  6.582mA    6.523mA    8.677mA
-336.4mV  195.4uA    370.9uA    217.1uA
2.382V    -4.955mA   -3.949mA   -6.434mA
[Pulldown]
-1.182V   -3.8mA     -2.7mA     -4.7mA
-945.5mV  -7.91mA    -4.6mA     -10.52mA
-827.3mV  -10.3mA    -6.57mA    -10.56mA
-669.7mV  -10.02mA   -9.53mA    -9.95mA
-551.5mV  -9.371mA   -9.335mA   -9.3mA
-315.1mV  -6.567mA   -6.465mA   -6.606mA
551.5mV   9.679mA    9.198mA    10.14mA
906.1mV   13.17mA    12.3mA     14.14mA
1.3V      14.4mA     13.36mA    15.61mA
1.733V    13.06mA    11.13mA    15.34mA
2.009V    10.78mA    4.15mA     12.68mA
2.364V    3mA        1.5mA      8.9mA
[Pullup]
-1.164V   3.7mA      2.005mA    6.785mA
-1.045V   6.9mA      2.809mA    11.11mA
-887.9mV  13.51mA    5.397mA    13.62mA
-690.9mV  14.84mA    11.99mA    14.32mA
-454.5mV  12.73mA    11.77mA    12.85mA
175.8mV   -4.107mA   -3.772mA   -4.491mA
687.9mV   -10.94mA   -10.12mA   -12.36mA
1.476V    -13.14mA   -11.84mA   -15.3mA
1.791V    -12.06mA   -10.42mA   -14.61mA
1.988V    -11.63mA   -6.784mA   -13.95mA
2.224V    -6.8mA     -4.648mA   -13.49mA
2.382V    -5mA       -4.048mA   -8.7mA
[Ramp]
R_load=50.000Ohm
dV/dt_r   311.664mV/136.000ps  289.671mV/173.500ps  344.961mV/111.000ps
dV/dt_f   311.694mV/156.500ps  289.668mV/197.000ps  344.961mV/128.500ps
[Rising waveform]
R_fixture=50.000Ohm
V_fixture=1.200
V_fixture_min=1.140
V_fixture_max=1.300
0s        687.6mV    659.5mV    735mV
52ps      685.4mV    658mV      785.9mV
115ps     679.1mV    654.5mV    1.072V
154ps     675.5mV    651.6mV    1.189V
243ps     736.7mV    646.2mV    1.278V
345ps     1.055V     673.2mV    1.296V
435ps     1.166V     813.7mV    1.299V
524ps     1.191V     1.015V     1.3V
626ps     1.198V     1.108V     1.3V
1.25ns    1.2V       1.14V      1.3V
[Rising waveform]
R_fixture=50.000Ohm
V_fixture=0
0s        59.16mV    46.04mV    77.11mV
64ps      59.47mV    46.28mV    110mV
166ps     55.12mV    46.13mV    429.4mV
230ps     54.7mV     44.55mV    553.2mV
320ps     195.4mV    39.2mV     630.9mV
435ps     432.8mV    80.77mV    662mV
562ps     539.7mV    281.8mV    670.9mV
664ps     567.7mV    410.7mV    672.7mV
792ps     580.1mV    487.3mV    673.6mV
1.25ns    585.1mV    530mV      674.4mV
[Falling waveform]
R_fixture=50.000Ohm
V_fixture=1.200
V_fixture_min=1.140
V_fixture_max=1.300
0s        1.2V       1.14V      1.302V
77ps      1.2V       1.14V      1.272V
243ps     1.201V     1.141V     892.1mV
358ps     1.032V     1.149V     787mV
422ps     914.5mV    1.125V     766mV
498ps     810.7mV    1.04V      753.5mV
613ps     732.5mV    880.4mV    746.6mV
728ps     704.4mV    766.5mV    744.8mV
856ps     692.8mV    703mV      744.3mV
1.25ns    687.6mV    662.7mV    744.1mV
[Falling waveform]
R_fixture=50.000Ohm
V_fixture=0
0s        585.1mV    530.7mV    682.6mV
52ps      584.9mV    530.4mV    620.5mV
154ps     596.9mV    533.5mV    224mV
205ps     585.7mV    539.9mV    145.5mV
256ps     485mV      546.3mV    110.8mV
358ps     188.2mV    492.1mV    87.37mV
460ps     91.57mV    270.3mV    82.12mV
549ps     69.59mV    126.5mV    81.14mV
652ps     62.12mV    70.78mV    80.82mV
1.25ns    59.03mV    46.06mV    80.64mV
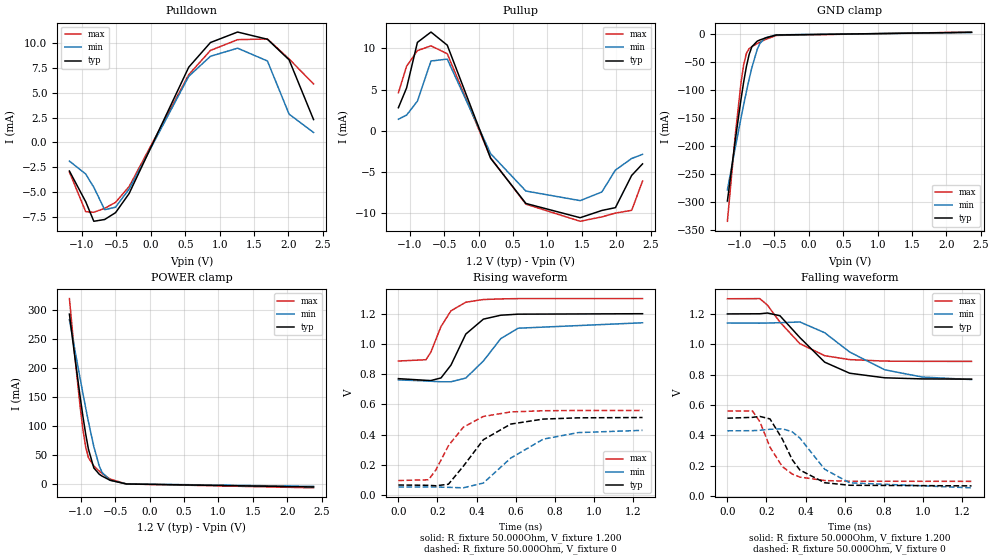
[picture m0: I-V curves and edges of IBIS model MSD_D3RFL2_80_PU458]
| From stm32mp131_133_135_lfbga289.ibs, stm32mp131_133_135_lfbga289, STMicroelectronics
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[Model] MSD_D3RFL2_80_PU458
Model_type   I/O
C_comp 2.406pF   2.319pF   2.532pF
Vinh = 820.000mV
Vinl = 380.000mV
Vmeas = 600.000mV
Vref = 600.000mV
[Model Spec]
Vinh   820.000mV   790.000mV   870.000mV
Vinl   380.000mV   350.000mV   430.000mV
Vmeas   600.000mV   570.000mV   650.000mV
Vref   600.000mV   570.000mV   650.000mV
[Receiver Thresholds]
Vth   =  0.600V
Vth_min  =  0.5880V
Vth_max  =  0.6120V
Vinh_ac  =  0.220V
Vinh_dc  =  0.130V
Vinl_ac  = -0.220V
Vinl_dc  = -0.130V
Tslew_ac =  5.000ns |Not specified, so set to high value
[Temperature Range]   25.000   125.000   -40.000
[Voltage Range]   1.200V   1.140V   1.300V
[GND Clamp Reference]   0.00V   0.00V   0.00V
[Pulldown Reference]   0.00V   0.00V   0.00V
[POWER Clamp Reference]   1.200V   1.140V   1.300V
[Pullup Reference]   1.200V   1.140V   1.300V
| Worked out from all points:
|   slope of the pulldown table from 0 to 0.18 V, typ, clamps not added: 63.6 ohm
|   slope of the pullup table from 0 to 0.18 V, typ, clamps not added: 52.8 ohm
|   GND clamp passes 1 mA (typ) near -0.40 V on its own axis
|   POWER clamp passes 1 mA (typ) near -0.41 V on its own axis
|   rising waveform, R_fixture 50.000Ohm, V_fixture 1.200: 20-80 % time 109ps typ, 147ps min, 94ps max; typ from 0.77 V to 1.2 V
|   rising waveform, R_fixture 50.000Ohm, V_fixture 0: 20-80 % time 178ps typ, 224ps min, 150ps max; typ from 0.066 V to 0.513 V
|   falling waveform, R_fixture 50.000Ohm, V_fixture 1.200: 20-80 % time 203ps typ, 274ps min, 183ps max; typ from 1.2 V to 0.77 V
|   falling waveform, R_fixture 50.000Ohm, V_fixture 0: 20-80 % time 120ps typ, 156ps min, 112ps max; typ from 0.512 V to 0.066 V
[GND Clamp]
-1.182V   -299mA     -279mA     -335.2mA
-1.064V   -186.9mA   -201.3mA   -176.9mA
-984.9mV  -117.5mA   -151.2mA   -88.11mA
-945.5mV  -86.15mA   -126.9mA   -55.31mA
-906.1mV  -58.77mA   -103.6mA   -35.22mA
-866.7mV  -37.28mA   -81.4mA    -26.82mA
-827.3mV  -23.51mA   -60.86mA   -23.06mA
-748.5mV  -13.37mA   -27.9mA    -17.67mA
-709.1mV  -11.21mA   -17.31mA   -15.18mA
-630.3mV  -7.712mA   -7.374mA   -10.51mA
-472.7mV  -2.381mA   -2.076mA   -3.096mA
2.364V    2.48mA     2.095mA    2.917mA
[Power Clamp]
-1.164V   292.1mA    282.5mA    318.8mA
-1.085V   218.4mA    230.8mA    219.7mA
-1.006V   148.3mA    180mA      130.8mA
-966.7mV  115.6mA    155.1mA    93.04mA
-927.3mV  85.92mA    130.8mA    63.68mA
-887.9mV  60.21mA    107.3mA    45.58mA
-809.1mV  27.67mA    64.23mA    30.9mA
-730.3mV  16.91mA    31.08mA    22.23mA
-690.9mV  13.83mA    20.26mA    18.38mA
-572.7mV  6.582mA    6.523mA    8.677mA
-336.4mV  195.4uA    370.9uA    217.1uA
2.382V    -4.955mA   -3.949mA   -6.434mA
[Pulldown]
-1.182V   -2.9mA     -1.9mA     -3mA
-945.5mV  -6mA       -3.2mA     -7.01mA
-827.3mV  -7.98mA    -4.55mA    -7.07mA
-669.7mV  -7.8mA     -6.81mA    -6.67mA
-512.1mV  -7.111mA   -6.556mA   -6.07mA
-315.1mV  -5.18mA    -4.739mA   -4.478mA
551.5mV   7.6mA      6.678mA    6.842mA
866.7mV   10.09mA    8.7mA      9.292mA
1.261V    11.15mA    9.517mA    10.38mA
1.694V    10.42mA    8.224mA    10.45mA
2.009V    8.34mA     2.85mA     8.43mA
2.364V    2.3mA      1mA        5.9mA
[Pullup]
-1.164V   2.8mA      1.405mA    4.608mA
-1.045V   5.2mA      1.905mA    7.823mA
-887.9mV  10.71mA    3.592mA    9.708mA
-690.9mV  11.96mA    8.455mA    10.29mA
-454.5mV  10.37mA    8.683mA    9.333mA
175.8mV   -3.334mA   -2.766mA   -3.264mA
687.9mV   -8.793mA   -7.289mA   -8.879mA
1.476V    -10.52mA   -8.45mA    -10.95mA
1.791V    -9.641mA   -7.404mA   -10.42mA
1.988V    -9.3mA     -4.754mA   -9.962mA
2.224V    -5.4mA     -3.348mA   -9.625mA
2.382V    -4mA       -2.848mA   -6.085mA
[Ramp]
R_load=50.000Ohm
dV/dt_r   263.082mV/144.000ps  226.371mV/187.000ps  263.175mV/122.000ps
dV/dt_f   263.082mV/162.500ps  226.368mV/220.000ps  263.175mV/148.500ps
[Rising waveform]
R_fixture=50.000Ohm
V_fixture=1.200
V_fixture_min=1.140
V_fixture_max=1.300
0s        770.1mV    761.8mV    886.8mV
141ps     759mV      754.9mV    895.3mV
166ps     757.5mV    752.9mV    945mV
218ps     774.7mV    749.3mV    1.115V
269ps     859.5mV    749.3mV    1.219V
345ps     1.065V     774mV      1.276V
435ps     1.164V     886.8mV    1.294V
524ps     1.19V      1.035V     1.298V
613ps     1.197V     1.104V     1.3V
1.25ns    1.2V       1.14V      1.3V
[Rising waveform]
R_fixture=50.000Ohm
V_fixture=0
0s        65.84mV    52.81mV    95.62mV
154ps     64.04mV    52.91mV    100.4mV
192ps     60.85mV    52.53mV    165.9mV
256ps     70.92mV    50.54mV    326mV
332ps     189.6mV    47.18mV    448.4mV
435ps     365.8mV    78.96mV    519.9mV
575ps     469.3mV    243.9mV    549.6mV
741ps     502.3mV    369.3mV    557.7mV
920ps     510.7mV    412.9mV    559.2mV
1.25ns    512.7mV    427.9mV    559.5mV
[Falling waveform]
R_fixture=50.000Ohm
V_fixture=1.200
V_fixture_min=1.140
V_fixture_max=1.300
0s        1.2V       1.14V      1.3V
166ps     1.201V     1.139V     1.301V
205ps     1.206V     1.14V      1.258V
269ps     1.188V     1.142V     1.146V
371ps     1.044V     1.147V     1.004V
498ps     881.9mV    1.076V     924.6mV
626ps     808.8mV    948.6mV    898.6mV
805ps     778.7mV    831.8mV    888.8mV
996ps     771.4mV    783.9mV    887.1mV
1.25ns    769.9mV    766.9mV    887mV
[Falling waveform]
R_fixture=50.000Ohm
V_fixture=0
0s        512.3mV    428.9mV    559.4mV
128ps     517.7mV    429.8mV    560.6mV
166ps     524mV      432.7mV    489.8mV
218ps     507.5mV    439.1mV    321.3mV
281ps     375.4mV    442.4mV    193.1mV
332ps     238.3mV    422.4mV    143.9mV
371ps     170.5mV    381.4mV    123.8mV
498ps     86.63mV    175.5mV    101mV
626ps     69.84mV    85.8mV     96.6mV
1.25ns    65.78mV    52.92mV    95.54mV
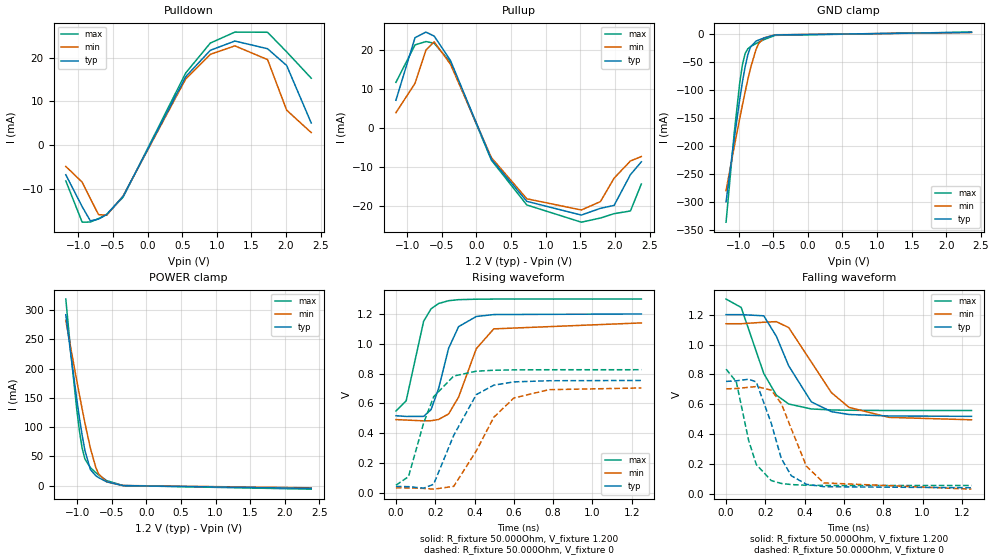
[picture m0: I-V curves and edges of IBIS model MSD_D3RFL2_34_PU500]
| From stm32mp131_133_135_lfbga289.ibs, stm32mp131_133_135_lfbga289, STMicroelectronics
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[Model] MSD_D3RFL2_34_PU500
Model_type   I/O
C_comp 2.422pF   2.336pF   2.548pF
Vinh = 820.000mV
Vinl = 380.000mV
Vmeas = 600.000mV
Vref = 600.000mV
[Model Spec]
Vinh   820.000mV   790.000mV   870.000mV
Vinl   380.000mV   350.000mV   430.000mV
Vmeas   600.000mV   570.000mV   650.000mV
Vref   600.000mV   570.000mV   650.000mV
[Receiver Thresholds]
Vth   =  0.600V
Vth_min  =  0.5880V
Vth_max  =  0.6120V
Vinh_ac  =  0.220V
Vinh_dc  =  0.130V
Vinl_ac  = -0.220V
Vinl_dc  = -0.130V
Tslew_ac =  5.000ns |Not specified, so set to high value
[Temperature Range]   25.000   125.000   -40.000
[Voltage Range]   1.200V   1.140V   1.300V
[GND Clamp Reference]   0.00V   0.00V   0.00V
[Pulldown Reference]   0.00V   0.00V   0.00V
[POWER Clamp Reference]   1.200V   1.140V   1.300V
[Pullup Reference]   1.200V   1.140V   1.300V
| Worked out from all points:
|   slope of the pulldown table from 0 to 0.18 V, typ, clamps not added: 31.3 ohm
|   slope of the pullup table from 0 to 0.18 V, typ, clamps not added: 26.5 ohm
|   GND clamp passes 1 mA (typ) near -0.40 V on its own axis
|   POWER clamp passes 1 mA (typ) near -0.41 V on its own axis
|   rising waveform, R_fixture 50.000Ohm, V_fixture 1.200: 20-80 % time 87.6ps typ, 116ps min, 73.4ps max; typ from 0.517 V to 1.2 V
|   rising waveform, R_fixture 50.000Ohm, V_fixture 0: 20-80 % time 136ps typ, 168ps min, 115ps max; typ from 0.043 V to 0.754 V
|   falling waveform, R_fixture 50.000Ohm, V_fixture 1.200: 20-80 % time 152ps typ, 197ps min, 126ps max; typ from 1.2 V to 0.52 V
|   falling waveform, R_fixture 50.000Ohm, V_fixture 0: 20-80 % time 98.2ps typ, 124ps min, 83.8ps max; typ from 0.753 V to 0.042 V
[GND Clamp]
-1.182V   -299.2mA   -279.2mA   -335.4mA
-1.064V   -187mA     -201.4mA   -177mA
-984.9mV  -117.5mA   -151.3mA   -88.22mA
-945.5mV  -86.23mA   -127mA     -55.43mA
-906.1mV  -58.85mA   -103.7mA   -35.31mA
-866.7mV  -37.36mA   -81.45mA   -26.92mA
-827.3mV  -23.56mA   -60.91mA   -23.14mA
-748.5mV  -13.42mA   -27.95mA   -17.73mA
-709.1mV  -11.25mA   -17.35mA   -15.24mA
-630.3mV  -7.747mA   -7.41mA    -10.55mA
-472.7mV  -2.393mA   -2.09mA    -3.114mA
2.364V    2.273mA    1.921mA    2.674mA
[Power Clamp]
-1.164V   292.3mA    282.6mA    319mA
-1.085V   218.5mA    230.8mA    219.8mA
-1.006V   148.3mA    180mA      130.9mA
-966.7mV  115.8mA    155.2mA    93.11mA
-927.3mV  86mA       130.8mA    63.78mA
-887.9mV  60.28mA    107.3mA    45.68mA
-809.1mV  27.72mA    64.28mA    30.98mA
-730.3mV  16.96mA    31.12mA    22.29mA
-690.9mV  13.87mA    20.29mA    18.43mA
-572.7mV  6.606mA    6.547mA    8.709mA
-336.4mV  197.1uA    373.8uA    219.2uA
2.382V    -4.548mA   -3.619mA   -5.899mA
[Pulldown]
-1.182V   -6.7mA     -4.8mA     -8.1mA
-945.5mV  -13.97mA   -8.4mA     -17.51mA
-827.3mV  -17.2mA    -12.13mA   -17.47mA
-709.1mV  -16.81mA   -15.79mA   -16.7mA
-590.9mV  -15.77mA   -15.93mA   -15.69mA
-354.6mV  -11.63mA   -11.56mA   -11.82mA
551.5mV   15.66mA    15.15mA    16.51mA
906.1mV   21.65mA    20.73mA    23.3mA
1.261V    23.76mA    22.66mA    25.8mA
1.733V    22.01mA    19.53mA    25.76mA
2.009V    18.19mA    8.01mA     21.29mA
2.364V    5.1mA      2.9mA      15.3mA
[Pullup]
-1.164V   7.2mA      4.009mA    11.8mA
-887.9mV  23.28mA    11.55mA    21.42mA
-730.3mV  24.7mA     20.07mA    22.27mA
-612.1mV  23.68mA    22.22mA    21.84mA
-375.8mV  17.4mA     16.45mA    16.97mA
215.2mV   -7.946mA   -7.528mA   -8.168mA
727.3mV   -18.75mA   -18.09mA   -19.68mA
1.515V    -22.27mA   -20.97mA   -24.1mA
1.791V    -20.54mA   -18.81mA   -23.03mA
1.988V    -19.79mA   -12.8mA    -21.91mA
2.224V    -11.9mA    -8.391mA   -21.22mA
2.382V    -8.6mA     -7.248mA   -14.29mA
[Ramp]
R_load=50.000Ohm
dV/dt_r   417.741mV/112.500ps  394.842mV/142.000ps  453.129mV/94.500ps
dV/dt_f   417.741mV/124.500ps  394.839mV/162.000ps  453.129mV/105.000ps
[Rising waveform]
R_fixture=50.000Ohm
V_fixture=1.200
V_fixture_min=1.140
V_fixture_max=1.300
0s        517.3mV    491.4mV    549.1mV
52ps      512.5mV    488.3mV    617.2mV
141ps     512.7mV    483mV      1.151V
179ps     558.5mV    483.9mV    1.235V
217ps     699.3mV    492.3mV    1.27V
268ps     969.3mV    529mV      1.289V
319ps     1.115V     642.5mV    1.296V
409ps     1.183V     967.3mV    1.299V
498ps     1.196V     1.1V       1.3V
1.249ns   1.2V       1.14V      1.3V
[Rising waveform]
R_fixture=50.000Ohm
V_fixture=0
0s        42.76mV    33.24mV    51.13mV
64ps      41.49mV    32.93mV    108.4mV
141ps     31.28mV    29.51mV    468.3mV
192ps     57.35mV    24.57mV    644.9mV
294ps     385.4mV    43.22mV    783.7mV
409ps     658.7mV    281.4mV    816mV
498ps     722.3mV    506.8mV    822.4mV
600ps     744.3mV    636.2mV    825mV
779ps     752.1mV    692.1mV    825.9mV
1.249ns   753.9mV    703.5mV    826mV
[Falling waveform]
R_fixture=50.000Ohm
V_fixture=1.200
V_fixture_min=1.140
V_fixture_max=1.300
0s        1.2V       1.139V     1.304V
77ps      1.2V       1.139V     1.248V
192ps     1.192V     1.149V     806.1mV
256ps     1.055V     1.153V     661.7mV
319ps     856.9mV    1.113V     602.2mV
434ps     616.4mV    882.9mV    569.1mV
536ps     551mV      678.5mV    562.4mV
626ps     532mV      579.4mV    560.3mV
830ps     522mV      512.6mV    558.7mV
1.249ns   519.5mV    496.6mV    558.5mV
[Falling waveform]
R_fixture=50.000Ohm
V_fixture=0
0s        753.3mV    703.3mV    835.6mV
52ps      757.2mV    705.9mV    751.6mV
115ps     768mV      713.8mV    358.3mV
154ps     749.6mV    718.7mV    197.5mV
230ps     473.4mV    695.1mV    89.86mV
281ps     238.2mV    605.3mV    70.98mV
332ps     122.5mV    436.8mV    63.25mV
409ps     65.13mV    185.7mV    58.9mV
498ps     49.02mV    74.39mV    57.52mV
1.249ns   42.04mV    32.61mV    57.08mV
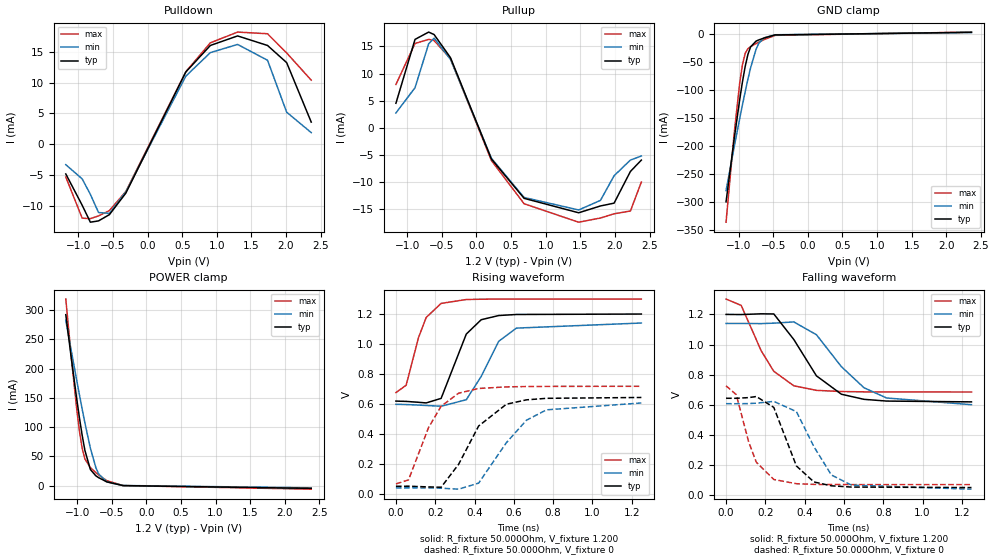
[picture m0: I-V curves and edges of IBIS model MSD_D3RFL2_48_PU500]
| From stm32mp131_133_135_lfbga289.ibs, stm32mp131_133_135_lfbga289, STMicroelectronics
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[Model] MSD_D3RFL2_48_PU500
Model_type   I/O
C_comp 2.422pF   2.336pF   2.548pF
Vinh = 820.000mV
Vinl = 380.000mV
Vmeas = 600.000mV
Vref = 600.000mV
[Model Spec]
Vinh   820.000mV   790.000mV   870.000mV
Vinl   380.000mV   350.000mV   430.000mV
Vmeas   600.000mV   570.000mV   650.000mV
Vref   600.000mV   570.000mV   650.000mV
[Receiver Thresholds]
Vth   =  0.600V
Vth_min  =  0.5880V
Vth_max  =  0.6120V
Vinh_ac  =  0.220V
Vinh_dc  =  0.130V
Vinl_ac  = -0.220V
Vinl_dc  = -0.130V
Tslew_ac =  5.000ns |Not specified, so set to high value
[Temperature Range]   25.000   125.000   -40.000
[Voltage Range]   1.200V   1.140V   1.300V
[GND Clamp Reference]   0.00V   0.00V   0.00V
[Pulldown Reference]   0.00V   0.00V   0.00V
[POWER Clamp Reference]   1.200V   1.140V   1.300V
[Pullup Reference]   1.200V   1.140V   1.300V
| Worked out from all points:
|   slope of the pulldown table from 0 to 0.18 V, typ, clamps not added: 41.6 ohm
|   slope of the pullup table from 0 to 0.18 V, typ, clamps not added: 36.2 ohm
|   GND clamp passes 1 mA (typ) near -0.40 V on its own axis
|   POWER clamp passes 1 mA (typ) near -0.41 V on its own axis
|   rising waveform, R_fixture 50.000Ohm, V_fixture 1.200: 20-80 % time 97.6ps typ, 127ps min, 82.8ps max; typ from 0.618 V to 1.2 V
|   rising waveform, R_fixture 50.000Ohm, V_fixture 0: 20-80 % time 160ps typ, 194ps min, 134ps max; typ from 0.049 V to 0.643 V
|   falling waveform, R_fixture 50.000Ohm, V_fixture 1.200: 20-80 % time 178ps typ, 226ps min, 145ps max; typ from 1.2 V to 0.619 V
|   falling waveform, R_fixture 50.000Ohm, V_fixture 0: 20-80 % time 109ps typ, 135ps min, 92.5ps max; typ from 0.643 V to 0.049 V
[GND Clamp]
-1.182V   -299.2mA   -279.2mA   -335.4mA
-1.064V   -187mA     -201.4mA   -177mA
-984.9mV  -117.5mA   -151.3mA   -88.22mA
-945.5mV  -86.23mA   -127mA     -55.43mA
-906.1mV  -58.85mA   -103.7mA   -35.31mA
-866.7mV  -37.36mA   -81.45mA   -26.92mA
-827.3mV  -23.56mA   -60.91mA   -23.14mA
-748.5mV  -13.42mA   -27.95mA   -17.73mA
-709.1mV  -11.25mA   -17.35mA   -15.24mA
-630.3mV  -7.747mA   -7.41mA    -10.55mA
-472.7mV  -2.393mA   -2.09mA    -3.114mA
2.364V    2.273mA    1.921mA    2.674mA
[Power Clamp]
-1.164V   292.3mA    282.6mA    319mA
-1.085V   218.5mA    230.8mA    219.8mA
-1.006V   148.3mA    180mA      130.9mA
-966.7mV  115.8mA    155.2mA    93.11mA
-927.3mV  86mA       130.8mA    63.78mA
-887.9mV  60.28mA    107.3mA    45.68mA
-809.1mV  27.72mA    64.28mA    30.98mA
-730.3mV  16.96mA    31.12mA    22.29mA
-690.9mV  13.87mA    20.29mA    18.43mA
-572.7mV  6.606mA    6.547mA    8.709mA
-336.4mV  197.1uA    373.8uA    219.2uA
2.382V    -4.548mA   -3.619mA   -5.899mA
[Pulldown]
-1.182V   -4.8mA     -3.3mA     -5.3mA
-945.5mV  -9.87mA    -5.6mA     -11.96mA
-827.3mV  -12.62mA   -8.1mA     -12.05mA
-709.1mV  -12.41mA   -11.05mA   -11.6mA
-551.5mV  -11.39mA   -11.19mA   -10.73mA
-315.1mV  -7.915mA   -7.696mA   -7.648mA
551.5mV   11.72mA    11.04mA    11.75mA
906.1mV   16.02mA    14.86mA    16.45mA
1.3V      17.57mA    16.19mA    18.19mA
1.733V    16.02mA    13.62mA    17.92mA
2.009V    13.24mA    5.21mA     14.81mA
2.364V    3.6mA      1.9mA      10.4mA
[Pullup]
-1.164V   4.5mA      2.705mA    7.977mA
-887.9mV  16.31mA    7.385mA    15.56mA
-690.9mV  17.66mA    15.5mA     16.31mA
-612.1mV  17.2mA     16.54mA    16.09mA
-375.8mV  12.93mA    12.62mA    12.74mA
215.2mV   -5.8mA     -5.653mA   -6.081mA
687.9mV   -13.07mA   -12.91mA   -14.07mA
1.476V    -15.74mA   -15.22mA   -17.48mA
1.791V    -14.48mA   -13.45mA   -16.71mA
1.988V    -13.96mA   -8.899mA   -15.93mA
2.224V    -8.1mA     -5.995mA   -15.41mA
2.382V    -6mA       -5.248mA   -10.06mA
[Ramp]
R_load=50.000Ohm
dV/dt_r   352.665mV/129.500ps  333.381mV/162.000ps  379.242mV/108.000ps
dV/dt_f   352.635mV/144.500ps  333.318mV/182.500ps  379.242mV/118.500ps
[Rising waveform]
R_fixture=50.000Ohm
V_fixture=1.200
V_fixture_min=1.140
V_fixture_max=1.300
0s        618.4mV    597mV      675.3mV
52ps      616.5mV    595.4mV    724.4mV
115ps     610.5mV    591.9mV    1.043V
154ps     606.3mV    589.1mV    1.177V
230ps     636.6mV    584.2mV    1.271V
358ps     1.066V     627.5mV    1.297V
434ps     1.162V     783.4mV    1.299V
523ps     1.19V      1.018V     1.3V
613ps     1.197V     1.106V     1.3V
1.249ns   1.2V       1.14V      1.3V
[Rising waveform]
R_fixture=50.000Ohm
V_fixture=0
0s        49.49mV    38.79mV    65.44mV
64ps      49.91mV    39.09mV    91.87mV
166ps     45.27mV    38.85mV    441.7mV
230ps     42.94mV    36.72mV    584.2mV
319ps     196.3mV    30.22mV    671.1mV
421ps     452.3mV    70.64mV    702.8mV
562ps     597.5mV    340.6mV    713.5mV
664ps     626.8mV    490.5mV    715.6mV
766ps     637mV      560mV      716.7mV
1.249ns   642.7mV    606mV      717.4mV
[Falling waveform]
R_fixture=50.000Ohm
V_fixture=1.200
V_fixture_min=1.140
V_fixture_max=1.300
0s        1.2V       1.14V      1.302V
77ps      1.199V     1.14V      1.26V
179ps     1.204V     1.139V     958mV
243ps     1.203V     1.142V     822mV
345ps     1.033V     1.15V      725.6mV
460ps     791.8mV    1.065V     695.4mV
587ps     669.6mV    852.7mV    687.5mV
702ps     635.7mV    712.7mV    685.4mV
817ps     624.2mV    644.6mV    684.8mV
1.249ns   618.8mV    600.1mV    684.4mV
[Falling waveform]
R_fixture=50.000Ohm
V_fixture=0
0s        642.8mV    606.8mV    725.6mV
52ps      642.5mV    606.5mV    666.7mV
115ps     647.2mV    607.4mV    353.1mV
154ps     654.4mV    610.2mV    217.6mV
243ps     582mV      622mV      103.1mV
358ps     193.1mV    554.2mV    74.98mV
447ps     86.79mV    321.5mV    70.52mV
536ps     60.98mV    133.2mV    69.42mV
638ps     52.78mV    65.58mV    69.11mV
1.249ns   49.36mV    38.74mV    68.96mV
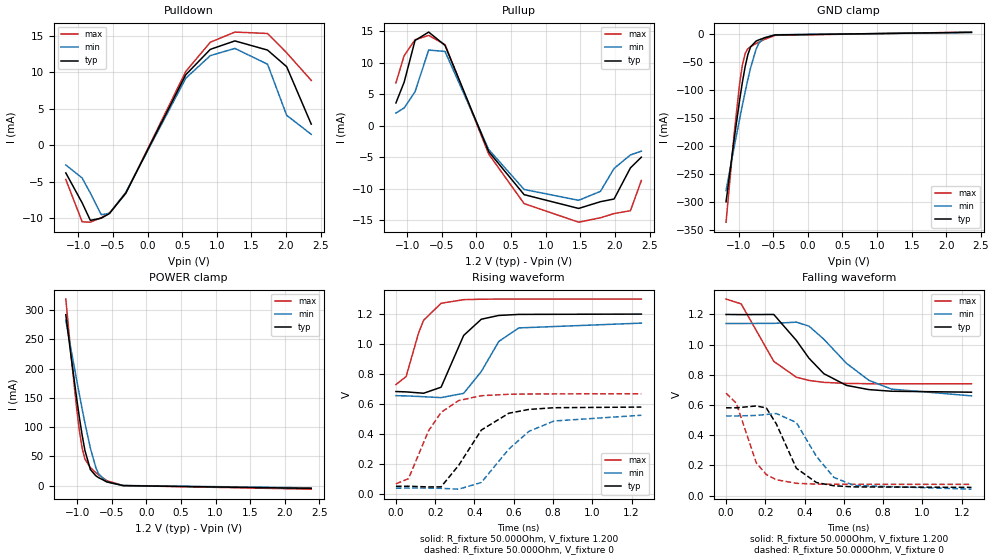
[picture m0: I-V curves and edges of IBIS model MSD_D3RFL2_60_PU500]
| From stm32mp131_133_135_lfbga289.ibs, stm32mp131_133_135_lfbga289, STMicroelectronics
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[Model] MSD_D3RFL2_60_PU500
Model_type   I/O
C_comp 2.422pF   2.336pF   2.548pF
Vinh = 820.000mV
Vinl = 380.000mV
Vmeas = 600.000mV
Vref = 600.000mV
[Model Spec]
Vinh   820.000mV   790.000mV   870.000mV
Vinl   380.000mV   350.000mV   430.000mV
Vmeas   600.000mV   570.000mV   650.000mV
Vref   600.000mV   570.000mV   650.000mV
[Receiver Thresholds]
Vth   =  0.600V
Vth_min  =  0.5880V
Vth_max  =  0.6120V
Vinh_ac  =  0.220V
Vinh_dc  =  0.130V
Vinl_ac  = -0.220V
Vinl_dc  = -0.130V
Tslew_ac =  5.000ns |Not specified, so set to high value
[Temperature Range]   25.000   125.000   -40.000
[Voltage Range]   1.200V   1.140V   1.300V
[GND Clamp Reference]   0.00V   0.00V   0.00V
[Pulldown Reference]   0.00V   0.00V   0.00V
[POWER Clamp Reference]   1.200V   1.140V   1.300V
[Pullup Reference]   1.200V   1.140V   1.300V
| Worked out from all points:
|   slope of the pulldown table from 0 to 0.18 V, typ, clamps not added: 50.1 ohm
|   slope of the pullup table from 0 to 0.18 V, typ, clamps not added: 42.9 ohm
|   GND clamp passes 1 mA (typ) near -0.40 V on its own axis
|   POWER clamp passes 1 mA (typ) near -0.41 V on its own axis
|   rising waveform, R_fixture 50.000Ohm, V_fixture 1.200: 20-80 % time 105ps typ, 136ps min, 85.6ps max; typ from 0.685 V to 1.2 V
|   rising waveform, R_fixture 50.000Ohm, V_fixture 0: 20-80 % time 170ps typ, 211ps min, 139ps max; typ from 0.054 V to 0.582 V
|   falling waveform, R_fixture 50.000Ohm, V_fixture 1.200: 20-80 % time 197ps typ, 247ps min, 158ps max; typ from 1.2 V to 0.685 V
|   falling waveform, R_fixture 50.000Ohm, V_fixture 0: 20-80 % time 116ps typ, 143ps min, 98.7ps max; typ from 0.582 V to 0.054 V
[GND Clamp]
-1.182V   -299.2mA   -279.2mA   -335.4mA
-1.064V   -187mA     -201.4mA   -177mA
-984.9mV  -117.5mA   -151.3mA   -88.22mA
-945.5mV  -86.23mA   -127mA     -55.43mA
-906.1mV  -58.85mA   -103.7mA   -35.31mA
-866.7mV  -37.36mA   -81.45mA   -26.92mA
-827.3mV  -23.56mA   -60.91mA   -23.14mA
-748.5mV  -13.42mA   -27.95mA   -17.73mA
-709.1mV  -11.25mA   -17.35mA   -15.24mA
-630.3mV  -7.747mA   -7.41mA    -10.55mA
-472.7mV  -2.393mA   -2.09mA    -3.114mA
2.364V    2.273mA    1.921mA    2.674mA
[Power Clamp]
-1.164V   292.3mA    282.6mA    319mA
-1.085V   218.5mA    230.8mA    219.8mA
-1.006V   148.3mA    180mA      130.9mA
-966.7mV  115.8mA    155.2mA    93.11mA
-927.3mV  86mA       130.8mA    63.78mA
-887.9mV  60.28mA    107.3mA    45.68mA
-809.1mV  27.72mA    64.28mA    30.98mA
-730.3mV  16.96mA    31.12mA    22.29mA
-690.9mV  13.87mA    20.29mA    18.43mA
-572.7mV  6.606mA    6.547mA    8.709mA
-336.4mV  197.1uA    373.8uA    219.2uA
2.382V    -4.548mA   -3.619mA   -5.899mA
[Pulldown]
-1.182V   -3.8mA     -2.7mA     -4.7mA
-945.5mV  -7.91mA    -4.5mA     -10.51mA
-827.3mV  -10.31mA   -6.57mA    -10.56mA
-669.7mV  -10.01mA   -9.53mA    -9.94mA
-551.5mV  -9.372mA   -9.338mA   -9.3mA
-315.1mV  -6.567mA   -6.465mA   -6.608mA
551.5mV   9.678mA    9.198mA    10.13mA
906.1mV   13.16mA    12.3mA     14.14mA
1.261V    14.32mA    13.29mA    15.53mA
1.733V    13.06mA    11.12mA    15.34mA
2.009V    10.78mA    4.11mA     12.69mA
2.364V    2.9mA      1.5mA      8.9mA
[Pullup]
-1.164V   3.6mA      2.005mA    6.785mA
-1.045V   6.9mA      2.809mA    11.11mA
-887.9mV  13.51mA    5.376mA    13.62mA
-690.9mV  14.84mA    11.99mA    14.32mA
-454.5mV  12.73mA    11.77mA    12.85mA
175.8mV   -4.107mA   -3.772mA   -4.491mA
687.9mV   -10.94mA   -10.12mA   -12.36mA
1.476V    -13.13mA   -11.84mA   -15.31mA
1.791V    -12.06mA   -10.42mA   -14.61mA
1.988V    -11.63mA   -6.784mA   -13.94mA
2.224V    -6.7mA     -4.648mA   -13.49mA
2.382V    -5mA       -4.048mA   -8.7mA
[Ramp]
R_load=50.000Ohm
dV/dt_r   312.813mV/138.000ps  290.544mV/174.500ps  346.668mV/112.500ps
dV/dt_f   312.843mV/157.500ps  290.541mV/197.500ps  346.668mV/129.000ps
[Rising waveform]
R_fixture=50.000Ohm
V_fixture=1.200
V_fixture_min=1.140
V_fixture_max=1.300
0s        684.8mV    657.3mV    731.2mV
52ps      682.5mV    655.8mV    784.7mV
115ps     676.2mV    652.2mV    1.073V
141ps     673.4mV    650.3mV    1.159V
230ps     713.5mV    644.3mV    1.272V
345ps     1.058V     672.9mV    1.296V
435ps     1.166V     818.5mV    1.299V
524ps     1.191V     1.018V     1.3V
626ps     1.198V     1.108V     1.3V
1.25ns    1.2V       1.14V      1.3V
[Rising waveform]
R_fixture=50.000Ohm
V_fixture=0
0s        54.44mV    42.34mV    70.59mV
64ps      54.76mV    42.59mV    105.3mV
166ps     50.22mV    42.43mV    423.2mV
230ps     50.76mV    40.74mV    546.3mV
320ps     194.6mV    35.31mV    624.8mV
435ps     428.6mV    79.84mV    657.1mV
575ps     540.5mV    301.9mV    666.7mV
677ps     565.7mV    419.6mV    668.4mV
805ps     577.2mV    488.8mV    669.2mV
1.25ns    581.5mV    527mV      670mV
[Falling waveform]
R_fixture=50.000Ohm
V_fixture=1.200
V_fixture_min=1.140
V_fixture_max=1.300
0s        1.2V       1.14V      1.302V
77ps      1.199V     1.14V      1.27V
243ps     1.2V       1.141V     889.3mV
358ps     1.028V     1.149V     784.1mV
422ps     910.6mV    1.123V     762.9mV
498ps     807.6mV    1.036V     750.1mV
613ps     730.1mV    876.5mV    743mV
728ps     702mV      763.2mV    741.1mV
843ps     691.2mV    705.2mV    740.5mV
1.25ns    684.8mV    660.6mV    740.3mV
[Falling waveform]
R_fixture=50.000Ohm
V_fixture=0
0s        581.5mV    527.7mV    678.4mV
52ps      581.3mV    527.4mV    612.5mV
154ps     593.7mV    530.9mV    216.7mV
205ps     580.4mV    537.4mV    139.2mV
256ps     474.8mV    543.7mV    104.7mV
358ps     180.9mV    484.1mV    81.2mV
460ps     86.38mV    260.1mV    75.83mV
549ps     64.86mV    120.5mV    74.77mV
652ps     57.41mV    66.53mV    74.42mV
1.25ns    54.3mV     42.34mV    74.24mV
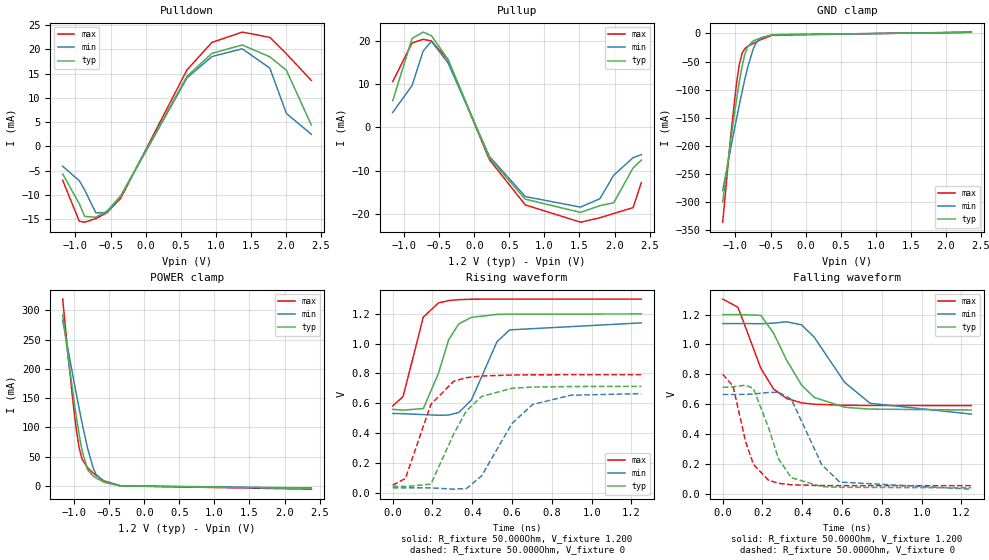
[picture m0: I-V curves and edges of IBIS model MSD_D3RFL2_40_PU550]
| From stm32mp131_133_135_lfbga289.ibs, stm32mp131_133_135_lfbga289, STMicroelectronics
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[Model] MSD_D3RFL2_40_PU550
Model_type   I/O
C_comp 2.435pF   2.348pF   2.561pF
Vinh = 820.000mV
Vinl = 380.000mV
Vmeas = 600.000mV
Vref = 600.000mV
[Model Spec]
Vinh   820.000mV   790.000mV   870.000mV
Vinl   380.000mV   350.000mV   430.000mV
Vmeas   600.000mV   570.000mV   650.000mV
Vref   600.000mV   570.000mV   650.000mV
[Receiver Thresholds]
Vth   =  0.600V
Vth_min  =  0.5880V
Vth_max  =  0.6120V
Vinh_ac  =  0.220V
Vinh_dc  =  0.130V
Vinl_ac  = -0.220V
Vinl_dc  = -0.130V
Tslew_ac =  5.000ns |Not specified, so set to high value
[Temperature Range]   25.000   125.000   -40.000
[Voltage Range]   1.200V   1.140V   1.300V
[GND Clamp Reference]   0.00V   0.00V   0.00V
[Pulldown Reference]   0.00V   0.00V   0.00V
[POWER Clamp Reference]   1.200V   1.140V   1.300V
[Pullup Reference]   1.200V   1.140V   1.300V
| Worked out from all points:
|   slope of the pulldown table from 0 to 0.18 V, typ, clamps not added: 35.6 ohm
|   slope of the pullup table from 0 to 0.18 V, typ, clamps not added: 29.6 ohm
|   GND clamp passes 1 mA (typ) near -0.40 V on its own axis
|   POWER clamp passes 1 mA (typ) near -0.41 V on its own axis
|   rising waveform, R_fixture 50.000Ohm, V_fixture 1.200: 20-80 % time 91.6ps typ, 119ps min, 77.8ps max; typ from 0.559 V to 1.2 V
|   rising waveform, R_fixture 50.000Ohm, V_fixture 0: 20-80 % time 146ps typ, 180ps min, 123ps max; typ from 0.042 V to 0.713 V
|   falling waveform, R_fixture 50.000Ohm, V_fixture 1.200: 20-80 % time 165ps typ, 206ps min, 133ps max; typ from 1.2 V to 0.562 V
|   falling waveform, R_fixture 50.000Ohm, V_fixture 0: 20-80 % time 103ps typ, 128ps min, 86.3ps max; typ from 0.713 V to 0.041 V
[GND Clamp]
-1.182V   -299.3mA   -279.3mA   -335.5mA
-1.064V   -187.1mA   -201.6mA   -177.2mA
-984.9mV  -117.6mA   -151.4mA   -88.33mA
-945.5mV  -86.31mA   -127.1mA   -55.53mA
-906.1mV  -58.92mA   -103.8mA   -35.42mA
-866.7mV  -37.43mA   -81.52mA   -27.01mA
-827.3mV  -23.64mA   -60.97mA   -23.23mA
-748.5mV  -13.47mA   -27.99mA   -17.8mA
-709.1mV  -11.3mA    -17.39mA   -15.29mA
-630.3mV  -7.775mA   -7.441mA   -10.6mA
-472.7mV  -2.409mA   -2.105mA   -3.132mA
2.364V    2.067mA    1.746mA    2.431mA
[Power Clamp]
-1.164V   292.4mA    282.7mA    319.1mA
-1.085V   218.6mA    231mA      220mA
-1.006V   148.4mA    180.1mA    131mA
-966.7mV  115.9mA    155.2mA    93.22mA
-927.3mV  86.08mA    130.9mA    63.88mA
-887.9mV  60.35mA    107.4mA    45.77mA
-809.1mV  27.78mA    64.33mA    31.06mA
-730.3mV  17mA       31.16mA    22.35mA
-690.9mV  13.91mA    20.33mA    18.49mA
-572.7mV  6.632mA    6.569mA    8.741mA
-336.4mV  198.8uA    376.6uA    221.3uA
2.382V    -4.134mA   -3.29mA    -5.363mA
[Pulldown]
-1.182V   -5.7mA     -4.1mA     -7mA
-945.5mV  -11.86mA   -7.1mA     -15.47mA
-866.7mV  -14.47mA   -9.06mA    -15.65mA
-709.1mV  -14.62mA   -13.73mA   -14.9mA
-551.5mV  -13.37mA   -13.65mA   -13.71mA
-354.6mV  -10.22mA   -10.29mA   -10.7mA
590.9mV   14.46mA    14.13mA    15.78mA
945.5mV   19.18mA    18.53mA    21.44mA
1.379V    20.93mA    20.13mA    23.58mA
1.773V    18.47mA    16.13mA    22.49mA
2.009V    15.7mA     6.78mA     19.1mA
2.364V    4.4mA      2.5mA      13.6mA
[Pullup]
-1.164V   6.1mA      3.409mA    10.52mA
-887.9mV  20.5mA     9.631mA    19.46mA
-730.3mV  21.97mA    17.57mA    20.3mA
-612.1mV  21.14mA    19.85mA    19.93mA
-375.8mV  15.68mA    14.87mA    15.59mA
215.2mV   -7.105mA   -6.743mA   -7.481mA
727.3mV   -16.61mA   -16.01mA   -17.94mA
1.515V    -19.67mA   -18.45mA   -21.93mA
1.791V    -18.11mA   -16.51mA   -20.91mA
1.988V    -17.45mA   -11.09mA   -19.92mA
2.264V    -9.4mA     -7.043mA   -18.57mA
2.382V    -7.6mA     -6.348mA   -12.78mA
[Ramp]
R_load=50.000Ohm
dV/dt_r   393.258mV/119.500ps  372.822mV/150.500ps  433.617mV/100.500ps
dV/dt_f   393.258mV/135.000ps  372.732mV/169.000ps  433.617mV/110.000ps
[Rising waveform]
R_fixture=50.000Ohm
V_fixture=1.200
V_fixture_min=1.140
V_fixture_max=1.300
0s        559mV      531.2mV    581.9mV
52ps      554mV      529.8mV    644.4mV
154ps     564.3mV    523.9mV    1.179V
230ps     800.9mV    519.2mV    1.274V
281ps     1.026V     520.9mV    1.29V
332ps     1.133V     537.7mV    1.296V
396ps     1.177V     622.2mV    1.299V
524ps     1.197V     1.013V     1.3V
588ps     1.199V     1.093V     1.3V
1.25ns    1.2V       1.14V      1.3V
[Rising waveform]
R_fixture=50.000Ohm
V_fixture=0
0s        42.02mV    31.93mV    50.03mV
64ps      40.74mV    32.3mV     95.29mV
192ps     56.6mV     31.47mV    592.7mV
307ps     394.4mV    22.92mV    748mV
371ps     549.5mV    27.44mV    771.9mV
447ps     645.4mV    112.3mV    783.2mV
600ps     700.8mV    464.8mV    790.1mV
703ps     708.8mV    591.5mV    791.3mV
894ps     712.4mV    653.7mV    791.7mV
1.25ns    713.4mV    664.9mV    791.7mV
[Falling waveform]
R_fixture=50.000Ohm
V_fixture=1.200
V_fixture_min=1.140
V_fixture_max=1.300
0s        1.2V       1.14V      1.304V
77ps      1.2V       1.14V      1.249V
192ps     1.195V     1.139V     839.5mV
256ps     1.075V     1.143V     701.8mV
320ps     898.6mV    1.152V     639.4mV
396ps     728.9mV    1.132V     609.6mV
460ps     646.2mV    1.049V     600.2mV
613ps     579.9mV    746.7mV    593.4mV
741ps     567.4mV    606.7mV    592.1mV
1.25ns    561.7mV    534.1mV    591.1mV
[Falling waveform]
R_fixture=50.000Ohm
V_fixture=0
0s        712.9mV    665.5mV    801mV
52ps      717.2mV    665.2mV    721.3mV
115ps     727.7mV    666mV      351.2mV
154ps     706.2mV    668.7mV    198.6mV
230ps     445mV      678.8mV    91.78mV
281ps     234mV      680.5mV    71.11mV
345ps     108.4mV    634.3mV    61.03mV
498ps     49.39mV    195.4mV    55.73mV
588ps     44.07mV    79.29mV    55.39mV
1.25ns    41.34mV    31.85mV    55.21mV
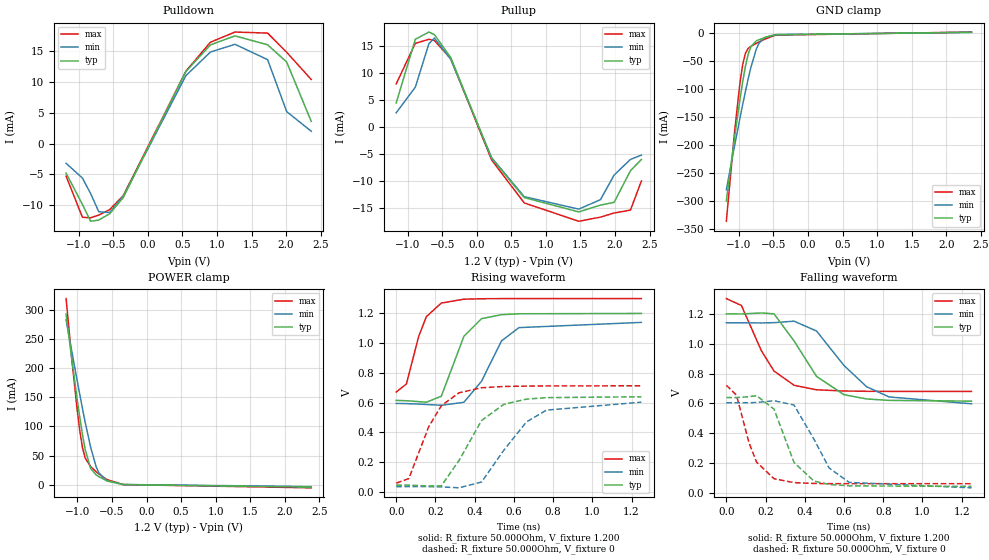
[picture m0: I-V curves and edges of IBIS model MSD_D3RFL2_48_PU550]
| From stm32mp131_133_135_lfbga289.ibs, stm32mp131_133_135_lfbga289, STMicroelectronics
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[Model] MSD_D3RFL2_48_PU550
Model_type   I/O
C_comp 2.435pF   2.348pF   2.561pF
Vinh = 820.000mV
Vinl = 380.000mV
Vmeas = 600.000mV
Vref = 600.000mV
[Model Spec]
Vinh   820.000mV   790.000mV   870.000mV
Vinl   380.000mV   350.000mV   430.000mV
Vmeas   600.000mV   570.000mV   650.000mV
Vref   600.000mV   570.000mV   650.000mV
[Receiver Thresholds]
Vth   =  0.600V
Vth_min  =  0.5880V
Vth_max  =  0.6120V
Vinh_ac  =  0.220V
Vinh_dc  =  0.130V
Vinl_ac  = -0.220V
Vinl_dc  = -0.130V
Tslew_ac =  5.000ns |Not specified, so set to high value
[Temperature Range]   25.000   125.000   -40.000
[Voltage Range]   1.200V   1.140V   1.300V
[GND Clamp Reference]   0.00V   0.00V   0.00V
[Pulldown Reference]   0.00V   0.00V   0.00V
[POWER Clamp Reference]   1.200V   1.140V   1.300V
[Pullup Reference]   1.200V   1.140V   1.300V
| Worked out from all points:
|   slope of the pulldown table from 0 to 0.18 V, typ, clamps not added: 41.6 ohm
|   slope of the pullup table from 0 to 0.18 V, typ, clamps not added: 36.2 ohm
|   GND clamp passes 1 mA (typ) near -0.40 V on its own axis
|   POWER clamp passes 1 mA (typ) near -0.41 V on its own axis
|   rising waveform, R_fixture 50.000Ohm, V_fixture 1.200: 20-80 % time 98.5ps typ, 127ps min, 83.3ps max; typ from 0.616 V to 1.2 V
|   rising waveform, R_fixture 50.000Ohm, V_fixture 0: 20-80 % time 162ps typ, 196ps min, 135ps max; typ from 0.045 V to 0.64 V
|   falling waveform, R_fixture 50.000Ohm, V_fixture 1.200: 20-80 % time 179ps typ, 227ps min, 146ps max; typ from 1.2 V to 0.616 V
|   falling waveform, R_fixture 50.000Ohm, V_fixture 0: 20-80 % time 110ps typ, 135ps min, 92.8ps max; typ from 0.64 V to 0.045 V
[GND Clamp]
-1.182V   -299.3mA   -279.3mA   -335.5mA
-1.064V   -187.1mA   -201.6mA   -177.2mA
-984.9mV  -117.6mA   -151.4mA   -88.33mA
-945.5mV  -86.31mA   -127.1mA   -55.53mA
-906.1mV  -58.92mA   -103.8mA   -35.42mA
-866.7mV  -37.43mA   -81.52mA   -27.01mA
-827.3mV  -23.64mA   -60.97mA   -23.23mA
-748.5mV  -13.47mA   -27.99mA   -17.8mA
-709.1mV  -11.3mA    -17.39mA   -15.29mA
-630.3mV  -7.775mA   -7.441mA   -10.6mA
-472.7mV  -2.409mA   -2.105mA   -3.132mA
2.364V    2.067mA    1.746mA    2.431mA
[Power Clamp]
-1.164V   292.4mA    282.7mA    319.1mA
-1.085V   218.6mA    231mA      220mA
-1.006V   148.4mA    180.1mA    131mA
-966.7mV  115.9mA    155.2mA    93.22mA
-927.3mV  86.08mA    130.9mA    63.88mA
-887.9mV  60.35mA    107.4mA    45.77mA
-809.1mV  27.78mA    64.33mA    31.06mA
-730.3mV  17mA       31.16mA    22.35mA
-690.9mV  13.91mA    20.33mA    18.49mA
-572.7mV  6.632mA    6.569mA    8.741mA
-336.4mV  198.8uA    376.6uA    221.3uA
2.382V    -4.134mA   -3.29mA    -5.363mA
[Pulldown]
-1.182V   -4.8mA     -3.2mA     -5.3mA
-945.5mV  -9.88mA    -5.6mA     -11.96mA
-827.3mV  -12.61mA   -8.1mA     -12.05mA
-709.1mV  -12.41mA   -11.06mA   -11.6mA
-551.5mV  -11.39mA   -11.19mA   -10.72mA
-354.6mV  -8.758mA   -8.523mA   -8.443mA
551.5mV   11.71mA    11.03mA    11.75mA
906.1mV   16.02mA    14.86mA    16.45mA
1.261V    17.48mA    16.11mA    18.1mA
1.733V    16.03mA    13.62mA    17.93mA
2.009V    13.23mA    5.18mA     14.81mA
2.364V    3.6mA      2mA        10.4mA
[Pullup]
-1.164V   4.5mA      2.657mA    8.031mA
-887.9mV  16.31mA    7.422mA    15.56mA
-690.9mV  17.66mA    15.5mA     16.31mA
-612.1mV  17.19mA    16.54mA    16.09mA
-375.8mV  12.93mA    12.62mA    12.73mA
215.2mV   -5.8mA     -5.653mA   -6.081mA
687.9mV   -13.08mA   -12.91mA   -14.07mA
1.476V    -15.74mA   -15.22mA   -17.48mA
1.791V    -14.48mA   -13.46mA   -16.71mA
1.988V    -13.96mA   -8.894mA   -15.94mA
2.224V    -8.1mA     -5.995mA   -15.41mA
2.382V    -6mA       -5.2mA     -10.01mA
[Ramp]
R_load=50.000Ohm
dV/dt_r   353.910mV/130.500ps  334.407mV/162.500ps  381.045mV/110.000ps
dV/dt_f   353.910mV/145.500ps  334.374mV/183.000ps  381.045mV/119.500ps
[Rising waveform]
R_fixture=50.000Ohm
V_fixture=1.200
V_fixture_min=1.140
V_fixture_max=1.300
0s        615.5mV    595.1mV    671.5mV
52ps      613.3mV    593.8mV    725.9mV
115ps     607.1mV    590.7mV    1.048V
154ps     603.3mV    588mV      1.179V
230ps     643.5mV    582.7mV    1.27V
345ps     1.046V     602.8mV    1.296V
435ps     1.165V     744.2mV    1.299V
537ps     1.192V     1.016V     1.3V
626ps     1.198V     1.105V     1.3V
1.25ns    1.2V       1.14V      1.3V
[Rising waveform]
R_fixture=50.000Ohm
V_fixture=0
0s        45.18mV    35.31mV    59.13mV
64ps      45.59mV    35.61mV    89.33mV
166ps     40.23mV    35.61mV    439.1mV
230ps     41.06mV    34.09mV    579.8mV
320ps     210.8mV    27.61mV    666.5mV
435ps     480mV      66.72mV    700.5mV
549ps     589.6mV    280.8mV    709.1mV
664ps     623.9mV    470.7mV    711.7mV
766ps     634.2mV    550mV      712.8mV
1.25ns    639.7mV    603.7mV    713.6mV
[Falling waveform]
R_fixture=50.000Ohm
V_fixture=1.200
V_fixture_min=1.140
V_fixture_max=1.300
0s        1.2V       1.14V      1.302V
77ps      1.199V     1.14V      1.256V
179ps     1.206V     1.139V     951.8mV
243ps     1.2V       1.141V     817.6mV
345ps     1.019V     1.151V     722mV
460ps     781.2mV    1.085V     691.7mV
600ps     658.9mV    854mV      683.4mV
715ps     630.3mV    712.4mV    681.6mV
830ps     620.7mV    643.7mV    681mV
1.25ns    615.8mV    598mV      680.6mV
[Falling waveform]
R_fixture=50.000Ohm
V_fixture=0
0s        639.8mV    604.7mV    722.2mV
52ps      639.6mV    604.3mV    655.3mV
115ps     645.3mV    604.6mV    339.5mV
154ps     652.4mV    606.8mV    207.7mV
243ps     562.3mV    618.3mV    96.8mV
345ps     205.4mV    589.9mV    70.26mV
447ps     80.08mV    360.3mV    64.52mV
524ps     57.89mV    168.4mV    63.48mV
626ps     48.78mV    71.92mV    63.13mV
1.25ns    45.01mV    35.33mV    62.95mV
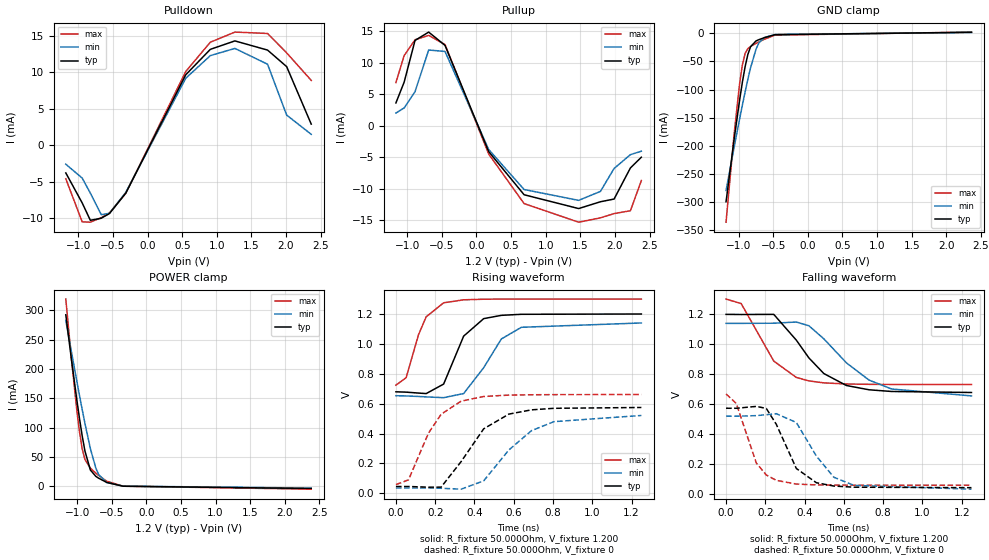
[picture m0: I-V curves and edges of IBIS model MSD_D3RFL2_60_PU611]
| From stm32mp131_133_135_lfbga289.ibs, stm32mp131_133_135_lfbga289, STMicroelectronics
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[Model] MSD_D3RFL2_60_PU611
Model_type   I/O
C_comp 2.451pF   2.364pF   2.578pF
Vinh = 820.000mV
Vinl = 380.000mV
Vmeas = 600.000mV
Vref = 600.000mV
[Model Spec]
Vinh   820.000mV   790.000mV   870.000mV
Vinl   380.000mV   350.000mV   430.000mV
Vmeas   600.000mV   570.000mV   650.000mV
Vref   600.000mV   570.000mV   650.000mV
[Receiver Thresholds]
Vth   =  0.600V
Vth_min  =  0.5880V
Vth_max  =  0.6120V
Vinh_ac  =  0.220V
Vinh_dc  =  0.130V
Vinl_ac  = -0.220V
Vinl_dc  = -0.130V
Tslew_ac =  5.000ns |Not specified, so set to high value
[Temperature Range]   25.000   125.000   -40.000
[Voltage Range]   1.200V   1.140V   1.300V
[GND Clamp Reference]   0.00V   0.00V   0.00V
[Pulldown Reference]   0.00V   0.00V   0.00V
[POWER Clamp Reference]   1.200V   1.140V   1.300V
[Pullup Reference]   1.200V   1.140V   1.300V
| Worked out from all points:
|   slope of the pulldown table from 0 to 0.18 V, typ, clamps not added: 50.1 ohm
|   slope of the pullup table from 0 to 0.18 V, typ, clamps not added: 42.9 ohm
|   GND clamp passes 1 mA (typ) near -0.40 V on its own axis
|   POWER clamp passes 1 mA (typ) near -0.41 V on its own axis
|   rising waveform, R_fixture 50.000Ohm, V_fixture 1.200: 20-80 % time 106ps typ, 137ps min, 86.8ps max; typ from 0.679 V to 1.2 V
|   rising waveform, R_fixture 50.000Ohm, V_fixture 0: 20-80 % time 174ps typ, 215ps min, 144ps max; typ from 0.045 V to 0.574 V
|   falling waveform, R_fixture 50.000Ohm, V_fixture 1.200: 20-80 % time 198ps typ, 249ps min, 160ps max; typ from 1.2 V to 0.679 V
|   falling waveform, R_fixture 50.000Ohm, V_fixture 0: 20-80 % time 116ps typ, 144ps min, 99.8ps max; typ from 0.574 V to 0.045 V
[GND Clamp]
-1.182V   -299.4mA   -279.4mA   -335.7mA
-1.064V   -187.2mA   -201.7mA   -177.3mA
-984.9mV  -117.7mA   -151.5mA   -88.45mA
-945.5mV  -86.41mA   -127.2mA   -55.64mA
-906.1mV  -59.01mA   -103.9mA   -35.52mA
-866.7mV  -37.5mA    -81.58mA   -27.1mA
-827.3mV  -23.7mA    -61.03mA   -23.31mA
-748.5mV  -13.53mA   -28.05mA   -17.87mA
-709.1mV  -11.34mA   -17.43mA   -15.36mA
-630.3mV  -7.814mA   -7.472mA   -10.65mA
-472.7mV  -2.424mA   -2.118mA   -3.155mA
2.364V    1.86mA     1.572mA    2.188mA
[Power Clamp]
-1.164V   292.5mA    282.8mA    319.3mA
-1.085V   218.7mA    231.1mA    220.1mA
-1.006V   148.5mA    180.2mA    131.1mA
-966.7mV  116mA      155.3mA    93.34mA
-927.3mV  86.16mA    131mA      63.99mA
-887.9mV  60.42mA    107.5mA    45.87mA
-809.1mV  27.84mA    64.38mA    31.14mA
-730.3mV  17.05mA    31.2mA     22.42mA
-690.9mV  13.96mA    20.37mA    18.55mA
-572.7mV  6.658mA    6.592mA    8.774mA
-336.4mV  200.5uA    379.1uA    223.4uA
2.382V    -3.72mA    -2.96mA    -4.821mA
[Pulldown]
-1.182V   -3.8mA     -2.6mA     -4.6mA
-945.5mV  -7.91mA    -4.5mA     -10.51mA
-827.3mV  -10.3mA    -6.57mA    -10.56mA
-669.7mV  -10.02mA   -9.53mA    -9.94mA
-551.5mV  -9.372mA   -9.334mA   -9.3mA
-315.1mV  -6.567mA   -6.465mA   -6.602mA
551.5mV   9.678mA    9.199mA    10.13mA
906.1mV   13.16mA    12.3mA     14.14mA
1.261V    14.32mA    13.29mA    15.53mA
1.733V    13.06mA    11.12mA    15.34mA
2.009V    10.79mA    4.14mA     12.68mA
2.364V    2.9mA      1.5mA      8.9mA
[Pullup]
-1.164V   3.6mA      2.005mA    6.838mA
-1.045V   6.9mA      2.809mA    11.11mA
-887.9mV  13.51mA    5.392mA    13.61mA
-690.9mV  14.83mA    11.99mA    14.31mA
-454.5mV  12.72mA    11.76mA    12.85mA
175.8mV   -4.108mA   -3.772mA   -4.491mA
687.9mV   -10.95mA   -10.12mA   -12.35mA
1.476V    -13.14mA   -11.84mA   -15.3mA
1.791V    -12.06mA   -10.42mA   -14.61mA
1.988V    -11.63mA   -6.784mA   -13.94mA
2.224V    -6.7mA     -4.595mA   -13.48mA
2.382V    -5mA       -4.048mA   -8.7mA
[Ramp]
R_load=50.000Ohm
dV/dt_r   315.171mV/141.000ps  292.278mV/177.000ps  350.163mV/115.500ps
dV/dt_f   315.171mV/158.000ps  292.278mV/198.500ps  350.163mV/130.000ps
[Rising waveform]
R_fixture=50.000Ohm
V_fixture=1.200
V_fixture_min=1.140
V_fixture_max=1.300
0s        679.2mV    653mV      723.7mV
52ps      676.9mV    651.5mV    773.6mV
115ps     670.7mV    648mV      1.061V
154ps     667.2mV    645.1mV    1.181V
243ps     730.9mV    639.8mV    1.275V
345ps     1.052V     667.6mV    1.295V
447ps     1.169V     840.7mV    1.299V
537ps     1.191V     1.033V     1.3V
639ps     1.198V     1.111V     1.3V
1.25ns    1.2V       1.14V      1.3V
[Rising waveform]
R_fixture=50.000Ohm
V_fixture=0
0s        44.88mV    34.85mV    57.85mV
64ps      45.23mV    35.12mV    89.72mV
166ps     40.72mV    35.03mV    403.1mV
230ps     40.89mV    33.39mV    528.5mV
332ps     211.7mV    27.38mV    616.6mV
447ps     431.5mV    83.11mV    647.8mV
575ps     529.7mV    289.5mV    657.1mV
690ps     558.3mV    418.8mV    659.3mV
805ps     568.7mV    479.4mV    660.2mV
1.25ns    574.2mV    520.8mV    661mV
[Falling waveform]
R_fixture=50.000Ohm
V_fixture=1.200
V_fixture_min=1.140
V_fixture_max=1.300
0s        1.2V       1.14V      1.302V
77ps      1.199V     1.14V      1.272V
243ps     1.2V       1.141V     888.6mV
358ps     1.028V     1.149V     779.5mV
422ps     909.7mV    1.124V     756.5mV
498ps     805.5mV    1.037V     743.4mV
613ps     725.8mV    876.9mV    735.8mV
728ps     697.3mV    762.1mV    733.6mV
843ps     686mV      702.6mV    733mV
1.25ns    679.2mV    656.5mV    732.7mV
[Falling waveform]
R_fixture=50.000Ohm
V_fixture=0
0s        574.2mV    521.7mV    669.4mV
52ps      574mV      521.4mV    606.2mV
154ps     586.5mV    524.8mV    209.4mV
205ps     573mV      531.4mV    129.1mV
256ps     466.8mV    537.8mV    93.47mV
358ps     172.6mV    479.4mV    68.86mV
460ps     77.68mV    255.3mV    63.07mV
549ps     55.63mV    114.3mV    61.93mV
652ps     47.97mV    59.9mV     61.5mV
1.25ns    44.74mV    34.78mV    61.29mV
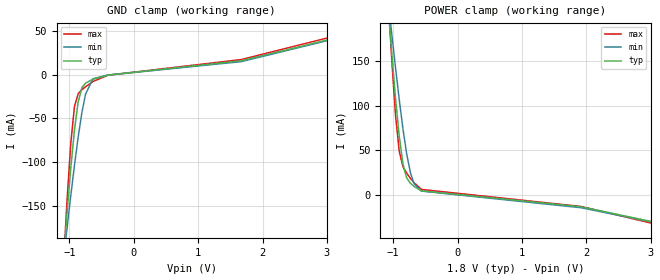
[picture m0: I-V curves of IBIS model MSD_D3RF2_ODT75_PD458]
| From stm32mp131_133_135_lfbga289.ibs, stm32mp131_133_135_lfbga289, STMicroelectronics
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[Model] MSD_D3RF2_ODT75_PD458
Model_type   Input
C_comp 2.303pF   2.238pF   2.368pF
Vinh = 1.150V
Vinl = 650.000mV
[Temperature Range]   25.000   125.000   -40.000
[Voltage Range]   1.800V   1.700V   1.900V
[GND Clamp Reference]   0.00V   0.00V   0.00V
[POWER Clamp Reference]   1.800V   1.700V   1.900V
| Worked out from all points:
|   GND clamp passes 1 mA (typ) near -0.46 V on its own axis
|   POWER clamp passes 1 mA (typ) near -0.38 V on its own axis
[GND Clamp]
-1.785V   -933.5mA   -691.8mA   -1.3A
-1.094V   -212.5mA   -213.1mA   -219.8mA
-1.036V   -157.7mA   -175.4mA   -143mA
-978.8mV  -106.8mA   -138.6mA   -78.88mA
-921.2mV  -63.12mA   -103.6mA   -36.34mA
-863.6mV  -30.93mA   -71.29mA   -21.63mA
-806.1mV  -14.78mA   -43.37mA   -17.11mA
-748.5mV  -9.571mA   -22.17mA   -13.73mA
-633.3mV  -5.086mA   -4.571mA   -7.703mA
-403mV    -396.8uA   -401.8uA   -526.2uA
1.67V     15.95mA    15mA       17.39mA
3.57V     49.8mA     49.2mA     52.5mA
[Power Clamp]
-1.77V    939.7mA    703.5mA    1.301A
-1.079V   212.8mA    218.7mA    223.3mA
-1.021V   158.3mA    180.3mA    150.8mA
-963.6mV  108.6mA    143mA      89.8mA
-906.1mV  66.01mA    107.2mA    48.87mA
-848.5mV  34.73mA    74.38mA    31.63mA
-790.9mV  18.98mA    46.2mA     24.26mA
-733.3mV  12.94mA    25.06mA    18.53mA
-675.8mV  9.342mA    12.49mA    13.56mA
-560.6mV  4.26mA     4.023mA    5.89mA
1.915V    -13.51mA   -14.65mA   -13.26mA
3.585V    -38.96mA   -38.8mA    -41.78mA
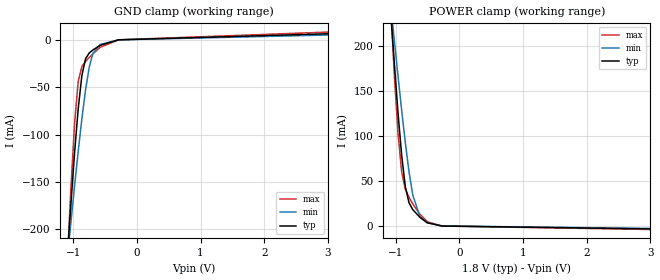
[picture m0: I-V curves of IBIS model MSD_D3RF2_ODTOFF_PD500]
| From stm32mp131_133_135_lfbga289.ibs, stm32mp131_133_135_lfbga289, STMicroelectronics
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[Model] MSD_D3RF2_ODTOFF_PD500
Model_type   Input
C_comp 2.389pF   2.307pF   2.510pF
Vinh = 1.150V
Vinl = 650.000mV
[Temperature Range]   25.000   125.000   -40.000
[Voltage Range]   1.800V   1.700V   1.900V
[GND Clamp Reference]   0.00V   0.00V   0.00V
[POWER Clamp Reference]   1.800V   1.700V   1.900V
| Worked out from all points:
|   GND clamp passes 1 mA (typ) near -0.40 V on its own axis
|   POWER clamp passes 1 mA (typ) near -0.41 V on its own axis
[GND Clamp]
-1.785V   -964mA     -721.6mA   -1.334A
-1.094V   -230.1mA   -231.8mA   -237.5mA
-1.036V   -173.2mA   -192.7mA   -157.1mA
-978.8mV  -119.7mA   -154.5mA   -88.71mA
-921.2mV  -72.74mA   -117.7mA   -43.87mA
-863.6mV  -37.69mA   -83.36mA   -28.18mA
-806.1mV  -20.06mA   -52.89mA   -22.89mA
-748.5mV  -14mA      -28.98mA   -18.77mA
-690.9mV  -10.81mA   -14.38mA   -14.9mA
-575.8mV  -5.825mA   -4.959mA   -7.973mA
-287.9mV  -75.18uA   -125.7uA   -60.5uA
3.57V     7.399mA    5.885mA    9.486mA
[Power Clamp]
-1.77V    980.7mA    743.9mA    1.344A
-1.079V   238mA      245.6mA    244.4mA
-1.021V   179.9mA    205.6mA    167.3mA
-963.6mV  125.6mA    166.3mA    102.9mA
-906.1mV  78.29mA    128.2mA    59.82mA
-848.5mV  43.61mA    92.27mA    40.81mA
-790.9mV  25.85mA    60.2mA     31.89mA
-733.3mV  18.37mA    34.84mA    24.76mA
-618.2mV  9.567mA    10.34mA    13mA
-503mV    3.6mA      3.681mA    4.749mA
-272.7mV  30uA       101.8uA    29.42uA
3.585V    -3.747mA   -3.179mA   -4.514mA
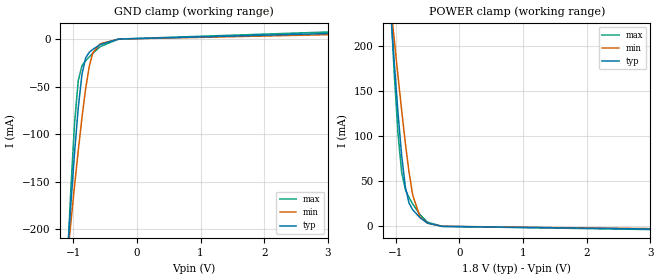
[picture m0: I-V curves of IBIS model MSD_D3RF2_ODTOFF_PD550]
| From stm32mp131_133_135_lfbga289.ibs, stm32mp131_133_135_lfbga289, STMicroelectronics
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[Model] MSD_D3RF2_ODTOFF_PD550
Model_type   Input
C_comp 2.402pF   2.319pF   2.523pF
Vinh = 1.150V
Vinl = 650.000mV
[Temperature Range]   25.000   125.000   -40.000
[Voltage Range]   1.800V   1.700V   1.900V
[GND Clamp Reference]   0.00V   0.00V   0.00V
[POWER Clamp Reference]   1.800V   1.700V   1.900V
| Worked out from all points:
|   GND clamp passes 1 mA (typ) near -0.40 V on its own axis
|   POWER clamp passes 1 mA (typ) near -0.41 V on its own axis
[GND Clamp]
-1.785V   -964.2mA   -721.9mA   -1.334A
-1.094V   -230.2mA   -231.9mA   -237.6mA
-1.036V   -173.3mA   -192.8mA   -157.2mA
-978.8mV  -119.8mA   -154.6mA   -88.82mA
-921.2mV  -72.81mA   -117.8mA   -43.98mA
-863.6mV  -37.75mA   -83.43mA   -28.26mA
-806.1mV  -20.11mA   -52.93mA   -22.97mA
-748.5mV  -14.05mA   -29.01mA   -18.84mA
-690.9mV  -10.85mA   -14.41mA   -14.96mA
-575.8mV  -5.851mA   -4.98mA    -8.007mA
-287.9mV  -75.88uA   -126.6uA   -61.3uA
3.57V     6.726mA    5.349mA    8.62mA
[Power Clamp]
-1.77V    981mA      744.1mA    1.344A
-1.079V   238.1mA    245.8mA    244.5mA
-1.021V   180.1mA    205.7mA    167.4mA
-963.6mV  125.7mA    166.4mA    103mA
-906.1mV  78.37mA    128.3mA    59.92mA
-848.5mV  43.68mA    92.31mA    40.91mA
-790.9mV  25.91mA    60.25mA    31.96mA
-733.3mV  18.42mA    34.88mA    24.82mA
-618.2mV  9.604mA    10.37mA    13.04mA
-503mV    3.618mA    3.698mA    4.772mA
-272.7mV  31uA       103.3uA    30.42uA
3.585V    -3.406mA   -2.89mA    -4.103mA
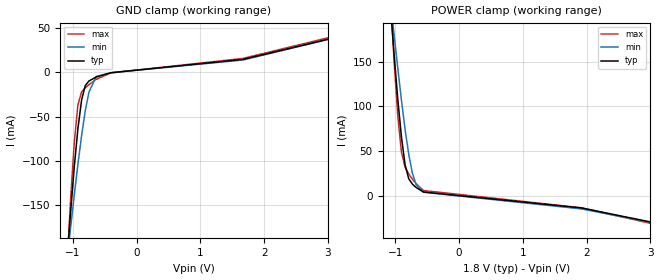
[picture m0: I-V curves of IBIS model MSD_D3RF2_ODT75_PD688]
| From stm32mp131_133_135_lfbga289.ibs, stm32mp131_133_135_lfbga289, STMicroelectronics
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[Model] MSD_D3RF2_ODT75_PD688
Model_type   Input
C_comp 2.362pF   2.296pF   2.428pF
Vinh = 1.150V
Vinl = 650.000mV
[Temperature Range]   25.000   125.000   -40.000
[Voltage Range]   1.800V   1.700V   1.900V
[GND Clamp Reference]   0.00V   0.00V   0.00V
[POWER Clamp Reference]   1.800V   1.700V   1.900V
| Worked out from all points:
|   GND clamp passes 1 mA (typ) near -0.46 V on its own axis
|   POWER clamp passes 1 mA (typ) near -0.38 V on its own axis
[GND Clamp]
-1.785V   -934.4mA   -692.6mA   -1.301A
-1.094V   -212.9mA   -213.5mA   -220.3mA
-1.036V   -157.9mA   -175.6mA   -143.5mA
-978.8mV  -107.2mA   -138.9mA   -79.34mA
-921.2mV  -63.42mA   -103.8mA   -36.73mA
-863.6mV  -31.2mA    -71.51mA   -21.98mA
-806.1mV  -15.02mA   -43.56mA   -17.42mA
-748.5mV  -9.773mA   -22.33mA   -13.99mA
-633.3mV  -5.22mA    -4.681mA   -7.881mA
-403mV    -424.8uA   -429.6uA   -559.6uA
1.67V     14.69mA    13.99mA    15.78mA
3.57V     47.15mA    47.06mA    49.04mA
[Power Clamp]
-1.77V    940.5mA    704.4mA    1.302A
-1.079V   213.3mA    219.1mA    223.8mA
-1.021V   158.6mA    180.7mA    151.3mA
-963.6mV  108.8mA    143.3mA    90.2mA
-906.1mV  66.34mA    107.5mA    49.28mA
-848.5mV  34.99mA    74.62mA    32mA
-790.9mV  19.2mA     46.42mA    24.57mA
-733.3mV  13.12mA    25.25mA    18.8mA
-675.8mV  9.496mA    12.64mA    13.78mA
-560.6mV  4.35mA     4.121mA    6.018mA
1.915V    -13.42mA   -14.52mA   -13.24mA
3.585V    -37.59mA   -37.64mA   -40.13mA
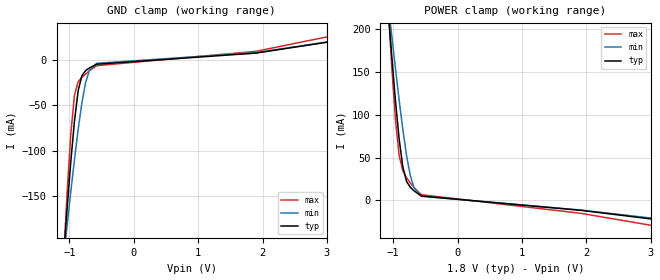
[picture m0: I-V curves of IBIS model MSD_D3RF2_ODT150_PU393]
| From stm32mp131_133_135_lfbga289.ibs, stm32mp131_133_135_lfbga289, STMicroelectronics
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[Model] MSD_D3RF2_ODT150_PU393
Model_type   Input
C_comp 2.301pF   2.234pF   2.366pF
Vinh = 1.150V
Vinl = 650.000mV
[Temperature Range]   25.000   125.000   -40.000
[Voltage Range]   1.800V   1.700V   1.900V
[GND Clamp Reference]   0.00V   0.00V   0.00V
[POWER Clamp Reference]   1.800V   1.700V   1.900V
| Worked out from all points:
|   GND clamp passes 1 mA (typ) near -0.43 V on its own axis
|   POWER clamp passes 1 mA (typ) near -0.41 V on its own axis
[GND Clamp]
-1.785V   -947.8mA   -705.6mA   -1.311A
-1.094V   -220.7mA   -221.8mA   -225.2mA
-1.036V   -164.8mA   -183.3mA   -147.2mA
-978.8mV  -112.6mA   -145.9mA   -81.81mA
-921.2mV  -67.21mA   -110mA     -38.69mA
-863.6mV  -33.79mA   -76.52mA   -23.69mA
-806.1mV  -17.06mA   -47.28mA   -18.93mA
-748.5mV  -11.49mA   -24.79mA   -15.31mA
-690.9mV  -8.675mA   -11.47mA   -11.92mA
-575.8mV  -4.414mA   -3.428mA   -6mA
1.9V      7.913mA    8.461mA    9.858mA
3.57V     26.11mA    26.24mA    34.07mA
[Power Clamp]
-1.77V    959.1mA    722.5mA    1.314A
-1.079V   224.4mA    231.3mA    229.4mA
-1.021V   167.9mA    192.1mA    155.5mA
-963.6mV  115.8mA    153.7mA    93.5mA
-906.1mV  71.13mA    116.7mA    51.98mA
-848.5mV  38.47mA    82.17mA    34.23mA
-790.9mV  21.9mA     51.94mA    26.38mA
-733.3mV  15.23mA    28.79mA    20.24mA
-675.8mV  11.07mA    14.72mA    14.88mA
-560.6mV  4.978mA    4.741mA    6.484mA
1.915V    -11.74mA   -11.37mA   -15.23mA
3.585V    -27.1mA    -25.72mA   -36.64mA
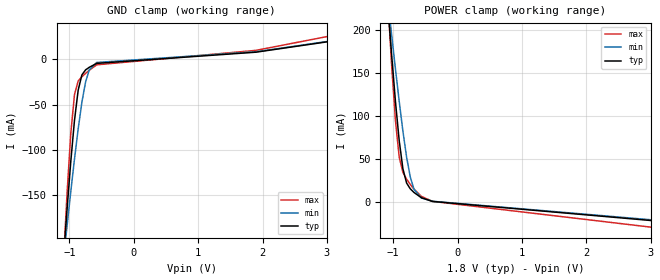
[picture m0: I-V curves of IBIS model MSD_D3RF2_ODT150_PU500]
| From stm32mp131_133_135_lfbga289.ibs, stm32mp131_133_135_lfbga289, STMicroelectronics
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[Model] MSD_D3RF2_ODT150_PU500
Model_type   Input
C_comp 2.347pF   2.280pF   2.413pF
Vinh = 1.150V
Vinl = 650.000mV
[Temperature Range]   25.000   125.000   -40.000
[Voltage Range]   1.800V   1.700V   1.900V
[GND Clamp Reference]   0.00V   0.00V   0.00V
[POWER Clamp Reference]   1.800V   1.700V   1.900V
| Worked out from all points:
|   GND clamp passes 1 mA (typ) near -0.43 V on its own axis
|   POWER clamp passes 1 mA (typ) near -0.40 V on its own axis
[GND Clamp]
-1.785V   -948.5mA   -706.2mA   -1.311A
-1.094V   -221mA     -222mA     -225.5mA
-1.036V   -165.1mA   -183.5mA   -147.5mA
-978.8mV  -112.9mA   -146.1mA   -82.14mA
-921.2mV  -67.44mA   -110.1mA   -38.98mA
-863.6mV  -34mA      -76.7mA    -23.94mA
-806.1mV  -17.25mA   -47.43mA   -19.15mA
-748.5mV  -11.64mA   -24.92mA   -15.5mA
-690.9mV  -8.813mA   -11.57mA   -12.08mA
-575.8mV  -4.497mA   -3.495mA   -6.09mA
1.9V      7.857mA    8.37mA     9.858mA
3.57V     25.12mA    25.39mA    32.88mA
[Power Clamp]
-1.77V    959.8mA    723.1mA    1.315A
-1.079V   224.7mA    231.6mA    229.7mA
-1.021V   168.2mA    192.3mA    155.8mA
-963.6mV  116mA      153.9mA    93.88mA
-906.1mV  71.36mA    116.9mA    52.27mA
-848.5mV  38.66mA    82.35mA    34.48mA
-790.9mV  22.07mA    52.1mA     26.61mA
-733.3mV  15.37mA    28.91mA    20.43mA
-675.8mV  11.19mA    14.82mA    15.03mA
-560.6mV  5.051mA    4.811mA    6.576mA
-387.9mV  776.6uA    1.011mA    882.7uA
3.585V    -25.08mA   -24.11mA   -34.12mA
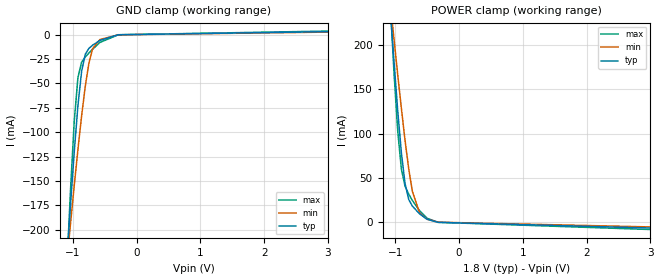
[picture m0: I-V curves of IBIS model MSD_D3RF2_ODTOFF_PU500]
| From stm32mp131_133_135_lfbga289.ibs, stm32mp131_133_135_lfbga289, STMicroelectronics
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[Model] MSD_D3RF2_ODTOFF_PU500
Model_type   Input
C_comp 2.391pF   2.309pF   2.512pF
Vinh = 1.150V
Vinl = 650.000mV
[Temperature Range]   25.000   125.000   -40.000
[Voltage Range]   1.800V   1.700V   1.900V
[GND Clamp Reference]   0.00V   0.00V   0.00V
[POWER Clamp Reference]   1.800V   1.700V   1.900V
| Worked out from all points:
|   GND clamp passes 1 mA (typ) near -0.40 V on its own axis
|   POWER clamp passes 1 mA (typ) near -0.41 V on its own axis
[GND Clamp]
-1.785V   -964mA     -721.5mA   -1.334A
-1.094V   -230.1mA   -231.8mA   -237.4mA
-1.036V   -173.2mA   -192.7mA   -157.1mA
-978.8mV  -119.8mA   -154.5mA   -88.7mA
-921.2mV  -72.72mA   -117.8mA   -43.87mA
-863.6mV  -37.68mA   -83.35mA   -28.17mA
-806.1mV  -20.05mA   -52.87mA   -22.89mA
-748.5mV  -13.99mA   -28.96mA   -18.77mA
-690.9mV  -10.8mA    -14.36mA   -14.9mA
-575.8mV  -5.815mA   -4.949mA   -7.965mA
-287.9mV  -71.99uA   -122uA     -58.99uA
3.57V     3.651mA    3.139mA    4.371mA
[Power Clamp]
-1.77V    980.8mA    744mA      1.344A
-1.079V   238mA      245.7mA    244.4mA
-1.021V   180mA      205.7mA    167.3mA
-963.6mV  125.6mA    166.4mA    102.9mA
-906.1mV  78.32mA    128.3mA    59.84mA
-848.5mV  43.63mA    92.29mA    40.83mA
-790.9mV  25.87mA    60.23mA    31.9mA
-733.3mV  18.39mA    34.86mA    24.76mA
-618.2mV  9.575mA    10.37mA    13mA
-503mV    3.608mA    3.695mA    4.758mA
-330.3mV  166.8uA    347.4uA    195.1uA
3.585V    -7.33mA    -5.931mA   -9.323mA
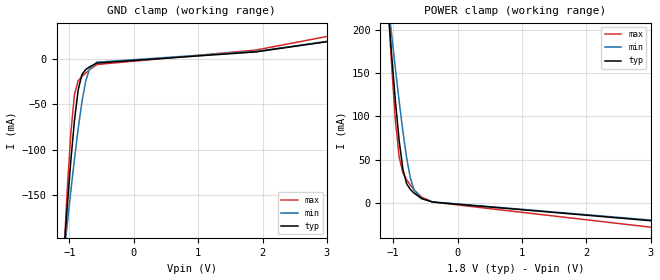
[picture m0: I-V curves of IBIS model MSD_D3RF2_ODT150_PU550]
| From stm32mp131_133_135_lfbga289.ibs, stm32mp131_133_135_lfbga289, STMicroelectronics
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[Model] MSD_D3RF2_ODT150_PU550
Model_type   Input
C_comp 2.359pF   2.292pF   2.426pF
Vinh = 1.150V
Vinl = 650.000mV
[Temperature Range]   25.000   125.000   -40.000
[Voltage Range]   1.800V   1.700V   1.900V
[GND Clamp Reference]   0.00V   0.00V   0.00V
[POWER Clamp Reference]   1.800V   1.700V   1.900V
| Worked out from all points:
|   GND clamp passes 1 mA (typ) near -0.43 V on its own axis
|   POWER clamp passes 1 mA (typ) near -0.40 V on its own axis
[GND Clamp]
-1.785V   -948.8mA   -706.4mA   -1.312A
-1.094V   -221mA     -222.1mA   -225.8mA
-1.036V   -165.1mA   -183.6mA   -147.7mA
-978.8mV  -112.9mA   -146.2mA   -82.24mA
-921.2mV  -67.52mA   -110.2mA   -39.09mA
-863.6mV  -34.06mA   -76.76mA   -24.05mA
-806.1mV  -17.3mA    -47.48mA   -19.24mA
-748.5mV  -11.7mA    -24.97mA   -15.56mA
-690.9mV  -8.855mA   -11.61mA   -12.15mA
-575.8mV  -4.518mA   -3.518mA   -6.134mA
1.9V      7.837mA    8.338mA    9.858mA
3.57V     24.78mA    25.09mA    32.48mA
[Power Clamp]
-1.77V    960mA      723.3mA    1.315A
-1.079V   224.8mA    231.6mA    229.9mA
-1.021V   168.3mA    192.4mA    155.9mA
-963.6mV  116.2mA    154mA      93.93mA
-906.1mV  71.44mA    117mA      52.38mA
-848.5mV  38.74mA    82.41mA    34.57mA
-790.9mV  22.13mA    52.15mA    26.68mA
-733.3mV  15.43mA    28.96mA    20.49mA
-675.8mV  11.24mA    14.86mA    15.08mA
-560.6mV  5.079mA    4.839mA    6.613mA
-387.9mV  791.6uA    1.019mA    888.3uA
3.585V    -24.42mA   -23.57mA   -33.24mA
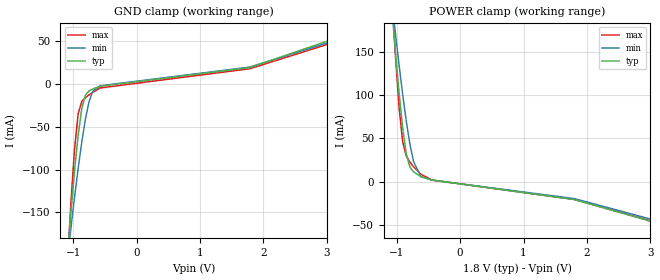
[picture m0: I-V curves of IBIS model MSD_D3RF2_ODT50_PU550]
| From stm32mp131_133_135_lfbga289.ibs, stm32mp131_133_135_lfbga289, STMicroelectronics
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[Model] MSD_D3RF2_ODT50_PU550
Model_type   Input
C_comp 2.312pF   2.273pF   2.341pF
Vinh = 1.150V
Vinl = 650.000mV
[Temperature Range]   25.000   125.000   -40.000
[Voltage Range]   1.800V   1.700V   1.900V
[GND Clamp Reference]   0.00V   0.00V   0.00V
[POWER Clamp Reference]   1.800V   1.700V   1.900V
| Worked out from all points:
|   GND clamp passes 1 mA (typ) near -0.48 V on its own axis
|   POWER clamp passes 1 mA (typ) near -0.32 V on its own axis
[GND Clamp]
-1.785V   -920mA     -680.4mA   -1.29A
-1.094V   -205.1mA   -206.5mA   -215.3mA
-1.036V   -151.4mA   -169.2mA   -139.9mA
-978.8mV  -102.1mA   -133.1mA   -76.92mA
-921.2mV  -59.9mA    -98.98mA   -34.81mA
-863.6mV  -28.56mA   -67.71mA   -20.29mA
-806.1mV  -12.85mA   -40.82mA   -15.94mA
-748.5mV  -7.944mA   -20.46mA   -12.7mA
-690.9mV  -5.726mA   -8.562mA   -9.726mA
-575.8mV  -2.61mA    -2mA       -4.6mA
1.785V    19.34mA    19.86mA    17.92mA
3.57V     64.33mA    61.09mA    59.48mA
[Power Clamp]
-1.77V    921.5mA    689.6mA    1.288A
-1.079V   202.9mA    209.3mA    217.9mA
-1.021V   150.5mA    171.6mA    146.6mA
-963.6mV  103.1mA    135.2mA    86.34mA
-906.1mV  62.14mA    100.7mA    46.04mA
-848.5mV  31.78mA    69.42mA    29.3mA
-790.9mV  16.67mA    42.84mA    22.35mA
-733.3mV  11.18mA    22.96mA    17.02mA
-618.2mV  5.702mA    5.803mA    8.526mA
-445.5mV  1.806mA    1.725mA    1.856mA
1.8V      -20.66mA   -19.55mA   -20.55mA
3.585V    -57.92mA   -54.7mA    -57.15mA
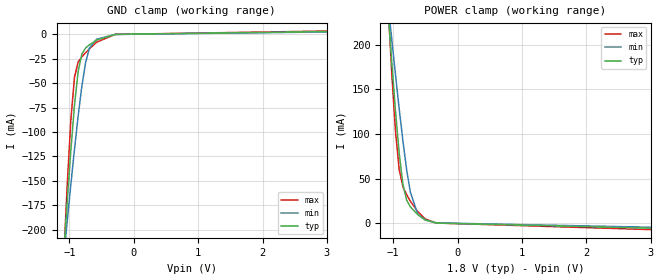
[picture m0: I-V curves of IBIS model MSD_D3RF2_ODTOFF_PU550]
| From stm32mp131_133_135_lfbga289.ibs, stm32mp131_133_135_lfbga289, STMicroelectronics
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[Model] MSD_D3RF2_ODTOFF_PU550
Model_type   Input
C_comp 2.403pF   2.321pF   2.525pF
Vinh = 1.150V
Vinl = 650.000mV
[Temperature Range]   25.000   125.000   -40.000
[Voltage Range]   1.800V   1.700V   1.900V
[GND Clamp Reference]   0.00V   0.00V   0.00V
[POWER Clamp Reference]   1.800V   1.700V   1.900V
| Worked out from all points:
|   GND clamp passes 1 mA (typ) near -0.40 V on its own axis
|   POWER clamp passes 1 mA (typ) near -0.41 V on its own axis
[GND Clamp]
-1.785V   -964.1mA   -721.8mA   -1.334A
-1.094V   -230.1mA   -231.9mA   -237.6mA
-1.036V   -173.3mA   -192.8mA   -157.2mA
-978.8mV  -119.8mA   -154.6mA   -88.81mA
-921.2mV  -72.8mA    -117.8mA   -43.97mA
-863.6mV  -37.75mA   -83.41mA   -28.25mA
-806.1mV  -20.1mA    -52.92mA   -22.97mA
-748.5mV  -14.05mA   -29mA      -18.83mA
-690.9mV  -10.85mA   -14.39mA   -14.95mA
-575.8mV  -5.849mA   -4.971mA   -8.001mA
-287.9mV  -73.99uA   -123uA     -59.99uA
3.57V     3.319mA    2.855mA    3.974mA
[Power Clamp]
-1.77V    981.1mA    744.2mA    1.344A
-1.079V   238.1mA    245.8mA    244.6mA
-1.021V   180.1mA    205.8mA    167.4mA
-963.6mV  125.7mA    166.4mA    103.1mA
-906.1mV  78.39mA    128.3mA    59.94mA
-848.5mV  43.7mA     92.34mA    40.92mA
-790.9mV  25.93mA    60.28mA    31.97mA
-733.3mV  18.43mA    34.9mA     24.83mA
-618.2mV  9.611mA    10.39mA    13.05mA
-503mV    3.625mA    3.711mA    4.78mA
-330.3mV  168.5uA    350.3uA    196.8uA
3.585V    -6.66mA    -5.393mA   -8.475mA
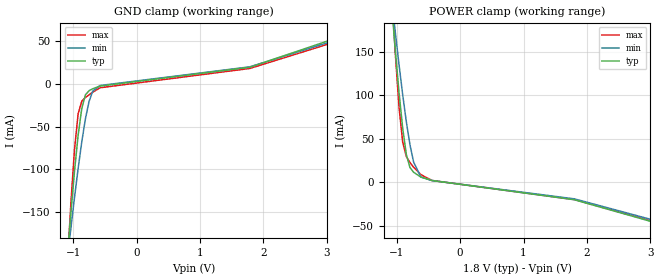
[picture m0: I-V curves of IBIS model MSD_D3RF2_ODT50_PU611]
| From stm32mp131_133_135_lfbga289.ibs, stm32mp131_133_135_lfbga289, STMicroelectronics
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[Model] MSD_D3RF2_ODT50_PU611
Model_type   Input
C_comp 2.329pF   2.290pF   2.358pF
Vinh = 1.150V
Vinl = 650.000mV
[Temperature Range]   25.000   125.000   -40.000
[Voltage Range]   1.800V   1.700V   1.900V
[GND Clamp Reference]   0.00V   0.00V   0.00V
[POWER Clamp Reference]   1.800V   1.700V   1.900V
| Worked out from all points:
|   GND clamp passes 1 mA (typ) near -0.48 V on its own axis
|   POWER clamp passes 1 mA (typ) near -0.31 V on its own axis
[GND Clamp]
-1.785V   -920.2mA   -680.5mA   -1.291A
-1.094V   -205.2mA   -206.4mA   -215.4mA
-1.036V   -151.5mA   -169.3mA   -140.1mA
-978.8mV  -102.3mA   -133.2mA   -77.1mA
-921.2mV  -60mA      -99.02mA   -34.91mA
-863.6mV  -28.65mA   -67.75mA   -20.38mA
-806.1mV  -12.94mA   -40.83mA   -16.02mA
-748.5mV  -8.02mA    -20.47mA   -12.78mA
-690.9mV  -5.79mA    -8.564mA   -9.784mA
-575.8mV  -2.66mA    -1.99mA    -4.64mA
1.785V    19.34mA    19.85mA    17.91mA
3.57V     63.96mA    60.84mA    59.08mA
[Power Clamp]
-1.77V    921.7mA    689.7mA    1.288A
-1.079V   203mA      209.3mA    218.1mA
-1.021V   150.6mA    171.7mA    146.8mA
-963.6mV  103.2mA    135.2mA    86.47mA
-906.1mV  62.23mA    100.8mA    46.14mA
-848.5mV  31.87mA    69.45mA    29.39mA
-790.9mV  16.75mA    42.88mA    22.43mA
-733.3mV  11.24mA    22.98mA    17.09mA
-618.2mV  5.744mA    5.823mA    8.569mA
-445.5mV  1.822mA    1.729mA    1.874mA
1.8V      -20.32mA   -19.29mA   -20.12mA
3.585V    -57.21mA   -54.26mA   -56.29mA
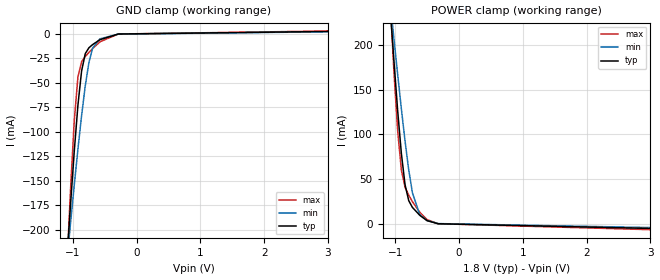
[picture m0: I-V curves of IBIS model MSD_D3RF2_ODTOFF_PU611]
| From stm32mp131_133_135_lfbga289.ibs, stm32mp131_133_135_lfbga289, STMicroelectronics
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[Model] MSD_D3RF2_ODTOFF_PU611
Model_type   Input
C_comp 2.420pF   2.338pF   2.542pF
Vinh = 1.150V
Vinl = 650.000mV
[Temperature Range]   25.000   125.000   -40.000
[Voltage Range]   1.800V   1.700V   1.900V
[GND Clamp Reference]   0.00V   0.00V   0.00V
[POWER Clamp Reference]   1.800V   1.700V   1.900V
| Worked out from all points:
|   GND clamp passes 1 mA (typ) near -0.40 V on its own axis
|   POWER clamp passes 1 mA (typ) near -0.41 V on its own axis
[GND Clamp]
-1.785V   -964.4mA   -722mA     -1.334A
-1.094V   -230.3mA   -231.9mA   -237.7mA
-1.036V   -173.4mA   -192.8mA   -157.3mA
-978.8mV  -120mA     -154.7mA   -88.92mA
-921.2mV  -72.88mA   -117.8mA   -44.07mA
-863.6mV  -37.81mA   -83.46mA   -28.35mA
-806.1mV  -20.17mA   -52.97mA   -23.05mA
-748.5mV  -14.1mA    -29.05mA   -18.89mA
-690.9mV  -10.89mA   -14.44mA   -15mA
-575.8mV  -5.874mA   -4.993mA   -8.037mA
-287.9mV  -76uA      -124uA     -60.99uA
3.57V     2.987mA    2.569mA    3.576mA
[Power Clamp]
-1.77V    981.3mA    744.5mA    1.345A
-1.079V   238.2mA    245.8mA    244.7mA
-1.021V   180.2mA    205.8mA    167.6mA
-963.6mV  125.8mA    166.5mA    103.2mA
-906.1mV  78.47mA    128.4mA    60.04mA
-848.5mV  43.77mA    92.42mA    41.01mA
-790.9mV  25.99mA    60.33mA    32.05mA
-733.3mV  18.48mA    34.95mA    24.89mA
-618.2mV  9.647mA    10.42mA    13.09mA
-503mV    3.643mA    3.728mA    4.801mA
-330.3mV  170.2uA    353.3uA    199.2uA
3.585V    -5.989mA   -4.854mA   -7.627mA
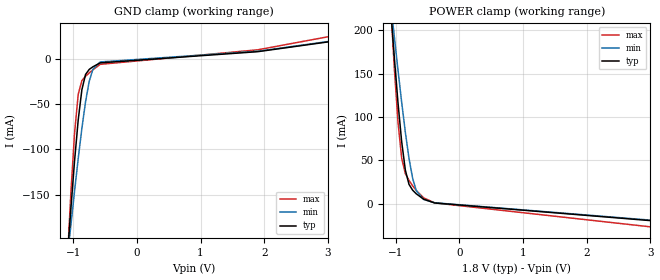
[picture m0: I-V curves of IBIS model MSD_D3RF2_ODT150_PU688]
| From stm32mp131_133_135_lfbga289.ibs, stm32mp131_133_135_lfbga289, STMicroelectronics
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[Model] MSD_D3RF2_ODT150_PU688
Model_type   Input
C_comp 2.389pF   2.320pF   2.456pF
Vinh = 1.150V
Vinl = 650.000mV
[Temperature Range]   25.000   125.000   -40.000
[Voltage Range]   1.800V   1.700V   1.900V
[GND Clamp Reference]   0.00V   0.00V   0.00V
[POWER Clamp Reference]   1.800V   1.700V   1.900V
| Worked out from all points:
|   GND clamp passes 1 mA (typ) near -0.43 V on its own axis
|   POWER clamp passes 1 mA (typ) near -0.40 V on its own axis
[GND Clamp]
-1.785V   -949.2mA   -706.9mA   -1.312A
-1.094V   -221.3mA   -222.3mA   -226mA
-1.036V   -165.4mA   -183.7mA   -147.9mA
-978.8mV  -113.1mA   -146.3mA   -82.5mA
-921.2mV  -67.67mA   -110.3mA   -39.29mA
-863.6mV  -34.21mA   -76.87mA   -24.22mA
-806.1mV  -17.42mA   -47.57mA   -19.39mA
-748.5mV  -11.8mA    -25.05mA   -15.69mA
-690.9mV  -8.933mA   -11.68mA   -12.25mA
-575.8mV  -4.573mA   -3.567mA   -6.204mA
1.9V      7.8mA      8.277mA    9.858mA
3.57V     24.12mA    24.52mA    31.68mA
[Power Clamp]
-1.77V    960.5mA    723.7mA    1.316A
-1.079V   225mA      231.9mA    230.2mA
-1.021V   168.6mA    192.6mA    156.2mA
-963.6mV  116.4mA    154.2mA    94.18mA
-906.1mV  71.59mA    117.1mA    52.57mA
-848.5mV  38.88mA    82.53mA    34.74mA
-790.9mV  22.25mA    52.25mA    26.83mA
-733.3mV  15.52mA    29.05mA    20.62mA
-675.8mV  11.32mA    14.93mA    15.19mA
-560.6mV  5.129mA    4.881mA    6.673mA
-387.9mV  796.8uA    1.028mA    898.2uA
3.585V    -23.09mA   -22.49mA   -31.55mA
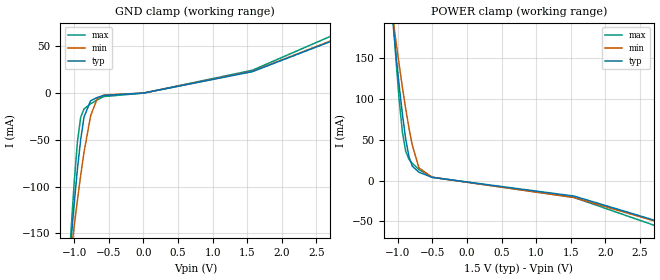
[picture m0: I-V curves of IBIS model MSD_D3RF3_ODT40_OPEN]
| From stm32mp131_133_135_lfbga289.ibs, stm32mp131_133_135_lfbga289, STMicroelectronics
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[Model] MSD_D3RF3_ODT40_OPEN
Model_type   Input
C_comp 2.463pF   2.419pF   2.543pF
Vinh = 925.000mV
Vinl = 575.000mV
[Temperature Range]   25.000   125.000   -40.000
[Voltage Range]   1.500V   1.425V   1.575V
[GND Clamp Reference]   0.00V   0.00V   0.00V
[POWER Clamp Reference]   1.500V   1.425V   1.575V
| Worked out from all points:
|   GND clamp passes 1 mA (typ) near -0.47 V on its own axis
|   POWER clamp passes 1 mA (typ) near -0.21 V on its own axis
[GND Clamp]
-1.48V    -591.4mA   -458.8mA   -790.9mA
-1.05V    -160.4mA   -172.6mA   -150.8mA
-1.002V   -118.9mA   -143mA     -96.23mA
-954.6mV  -81.4mA    -114.6mA   -52.15mA
-906.8mV  -49.42mA   -87.74mA   -25.79mA
-859.1mV  -25.65mA   -63.22mA   -17mA
-763.6mV  -8.136mA   -24.28mA   -11.45mA
-668.2mV  -4.724mA   -5.88mA    -7.236mA
-572.7mV  -2.532mA   -2.05mA    -3.758mA
900nV     12.84nA    11.95nA    14.89nA
1.575V    22.91mA    23.29mA    24.42mA
2.959V    62.35mA    63.02mA    68.85mA
[Power Clamp]
-1.459V   585mA      460.5mA    774.8mA
-1.077V   198.9mA    202.4mA    209.5mA
-1.03V    156.4mA    171.9mA    151.3mA
-981.8mV  117mA      142.4mA    99.49mA
-934.1mV  81.31mA    114.1mA    59.11mA
-886.4mV  50.85mA    87.82mA    35.74mA
-838.6mV  28.9mA     63.97mA    26.07mA
-790.9mV  17.66mA    43.27mA    21.1mA
-695.5mV  10.26mA    15.63mA    13.58mA
-504.6mV  3.93mA     4.045mA    4.174mA
1.548V    -18.93mA   -20.67mA   -20.65mA
2.98V     -55.35mA   -56.07mA   -62.7mA
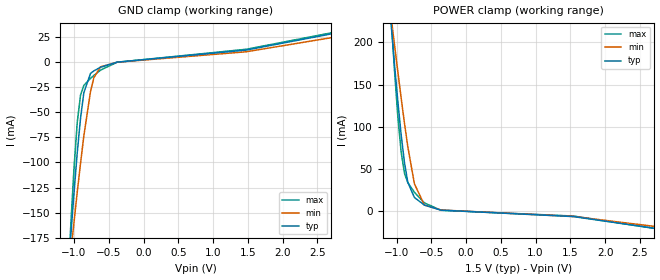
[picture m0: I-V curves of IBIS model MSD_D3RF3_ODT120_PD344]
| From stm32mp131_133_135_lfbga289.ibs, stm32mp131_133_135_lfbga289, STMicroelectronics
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[Model] MSD_D3RF3_ODT120_PD344
Model_type   Input
C_comp 2.266pF   2.199pF   2.368pF
Vinh = 925.000mV
Vinl = 575.000mV
[Temperature Range]   25.000   125.000   -40.000
[Voltage Range]   1.500V   1.425V   1.575V
[GND Clamp Reference]   0.00V   0.00V   0.00V
[POWER Clamp Reference]   1.500V   1.425V   1.575V
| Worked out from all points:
|   GND clamp passes 1 mA (typ) near -0.44 V on its own axis
|   POWER clamp passes 1 mA (typ) near -0.37 V on its own axis
[GND Clamp]
-1.48V    -618.4mA   -487.6mA   -825.2mA
-1.05V    -175.5mA   -191.6mA   -166mA
-1.002V   -131.3mA   -160.2mA   -107.2mA
-954.6mV  -90.76mA   -129.8mA   -60.62mA
-906.8mV  -56.11mA   -100.8mA   -33.05mA
-859.1mV  -30.71mA   -73.6mA    -23.48mA
-763.6mV  -11.68mA   -29.69mA   -16.52mA
-715.9mV  -9.11mA    -15.99mA   -13.63mA
-620.5mV  -5.503mA   -5.094mA   -8.38mA
-381.8mV  -411.2uA   -475uA     -498.6uA
1.48V     11.64mA    9.932mA    12.42mA
2.959V    31.03mA    26.86mA    32.14mA
[Power Clamp]
-1.459V   620.3mA    497.4mA    818.5mA
-1.077V   220.6mA    229.7mA    229.4mA
-1.03V    173.9mA    197.3mA    167.2mA
-981.8mV  130.1mA    165.4mA    112.5mA
-934.1mV  90.58mA    134.2mA    69.99mA
-886.4mV  57.58mA    104.3mA    44.9mA
-838.6mV  34.02mA    76.49mA    33.7mA
-743.2mV  15.91mA    32.17mA    22.08mA
-600mV    6.916mA    6.979mA    9.527mA
-361.4mV  889.7uA    1.066mA    737.9uA
1.548V    -6.778mA   -6.679mA   -6.146mA
2.98V     -23.93mA   -21.14mA   -24.15mA
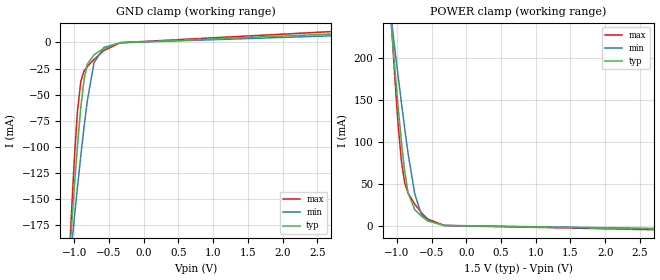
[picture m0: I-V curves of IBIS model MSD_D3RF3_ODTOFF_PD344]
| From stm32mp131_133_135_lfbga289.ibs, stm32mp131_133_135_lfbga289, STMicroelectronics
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[Model] MSD_D3RF3_ODTOFF_PD344
Model_type   Input
C_comp 2.325pF   2.244pF   2.446pF
Vinh = 925.000mV
Vinl = 575.000mV
[Temperature Range]   25.000   125.000   -40.000
[Voltage Range]   1.500V   1.425V   1.575V
[GND Clamp Reference]   0.00V   0.00V   0.00V
[POWER Clamp Reference]   1.500V   1.425V   1.575V
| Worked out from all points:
|   GND clamp passes 1 mA (typ) near -0.40 V on its own axis
|   POWER clamp passes 1 mA (typ) near -0.41 V on its own axis
[GND Clamp]
-1.48V    -634.9mA   -502.1mA   -841.6mA
-1.098V   -233.4mA   -234mA     -242.4mA
-1.05V    -185.9mA   -201.5mA   -174.8mA
-1.002V   -140.6mA   -169.6mA   -113.9mA
-954.6mV  -98.53mA   -138.5mA   -65.63mA
-906.8mV  -62.2mA    -108.6mA   -37.21mA
-859.1mV  -35.31mA   -80.52mA   -27.19mA
-811.4mV  -20.72mA   -55.23mA   -22.91mA
-715.9mV  -11.86mA   -19.33mA   -16.26mA
-572.7mV  -5.584mA   -4.746mA   -7.641mA
-334.1mV  -241.8uA   -309.8uA   -244.5uA
2.959V    8.747mA    6.878mA    11.27mA
[Power Clamp]
-1.459V   641.7mA    516mA      839.2mA
-1.077V   235.9mA    244mA      241.4mA
-1.03V    187.6mA    210.9mA    176.9mA
-981.8mV  141.7mA    178.2mA    120.4mA
-934.1mV  99.69mA    146.1mA    76.68mA
-886.4mV  64.28mA    115.2mA    50.6mA
-838.6mV  39.02mA    86.06mA    38.58mA
-743.2mV  19.08mA    38.21mA    25.56mA
-647.7mV  11.33mA    13.52mA    15.45mA
-552.3mV  5.677mA    5.588mA    7.628mA
-313.6mV  90.62uA    218.3uA    107.7uA
2.98V     -4.452mA   -3.727mA   -5.417mA
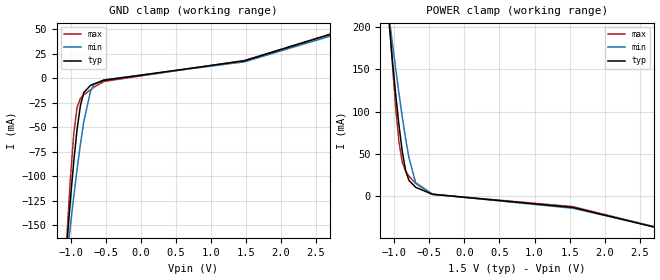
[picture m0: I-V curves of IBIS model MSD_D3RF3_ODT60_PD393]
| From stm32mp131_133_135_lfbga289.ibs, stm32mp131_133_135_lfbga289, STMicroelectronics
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[Model] MSD_D3RF3_ODT60_PD393
Model_type   Input
C_comp 2.287pF   2.241pF   2.345pF
Vinh = 925.000mV
Vinl = 575.000mV
[Temperature Range]   25.000   125.000   -40.000
[Voltage Range]   1.500V   1.425V   1.575V
[GND Clamp Reference]   0.00V   0.00V   0.00V
[POWER Clamp Reference]   1.500V   1.425V   1.575V
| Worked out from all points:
|   GND clamp passes 1 mA (typ) near -0.46 V on its own axis
|   POWER clamp passes 1 mA (typ) near -0.27 V on its own axis
[GND Clamp]
-1.48V    -603.4mA   -471.5mA   -810.1mA
-1.05V    -166.8mA   -180.7mA   -158.6mA
-1.002V   -124mA     -150.2mA   -101.8mA
-954.6mV  -85.02mA   -120.8mA   -56.54mA
-906.8mV  -51.98mA   -92.81mA   -29.57mA
-859.1mV  -27.61mA   -66.96mA   -20.36mA
-811.4mV  -14.45mA   -44.23mA   -16.79mA
-715.9mV  -7.241mA   -13.31mA   -11.49mA
-668.2mV  -5.62mA    -6.572mA   -9.079mA
-525mV    -1.976mA   -1.533mA   -3.166mA
1.48V     17.9mA     16.87mA    18.25mA
2.959V    50.62mA    48.59mA    50.6mA
[Power Clamp]
-1.459V   600.8mA    476.8mA    799.2mA
-1.077V   207.9mA    214.3mA    219.6mA
-1.03V    163.1mA    182.8mA    159.3mA
-981.8mV  121.6mA    151.9mA    106mA
-934.1mV  84.46mA    122.1mA    64.56mA
-886.4mV  53.12mA    93.87mA    40.27mA
-838.6mV  30.58mA    68.06mA    29.78mA
-790.9mV  18.88mA    45.69mA    24.06mA
-695.5mV  10.73mA    16.16mA    15.25mA
-456.8mV  2.46mA     2.691mA    2.436mA
1.548V    -13.07mA   -14.06mA   -12.09mA
2.98V     -41.83mA   -40.78mA   -41.51mA
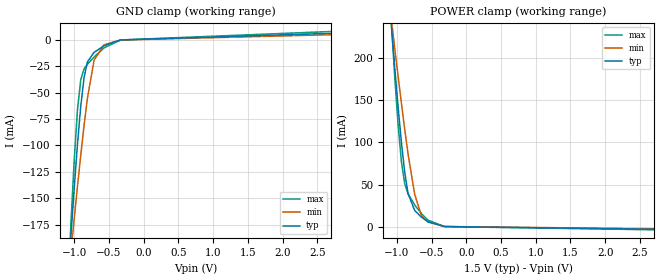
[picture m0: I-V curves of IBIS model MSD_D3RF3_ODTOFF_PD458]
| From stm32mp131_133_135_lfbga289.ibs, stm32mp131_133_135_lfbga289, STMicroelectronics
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[Model] MSD_D3RF3_ODTOFF_PD458
Model_type   Input
C_comp 2.385pF   2.303pF   2.507pF
Vinh = 925.000mV
Vinl = 575.000mV
[Temperature Range]   25.000   125.000   -40.000
[Voltage Range]   1.500V   1.425V   1.575V
[GND Clamp Reference]   0.00V   0.00V   0.00V
[POWER Clamp Reference]   1.500V   1.425V   1.575V
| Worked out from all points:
|   GND clamp passes 1 mA (typ) near -0.40 V on its own axis
|   POWER clamp passes 1 mA (typ) near -0.41 V on its own axis
[GND Clamp]
-1.48V    -635.7mA   -502.6mA   -842.5mA
-1.098V   -233.8mA   -234.3mA   -242.8mA
-1.05V    -186.3mA   -201.8mA   -175.3mA
-1.002V   -140.9mA   -169.9mA   -114.4mA
-954.6mV  -98.85mA   -138.8mA   -66.06mA
-906.8mV  -62.49mA   -108.9mA   -37.6mA
-859.1mV  -35.57mA   -80.75mA   -27.54mA
-811.4mV  -20.95mA   -55.42mA   -23.22mA
-715.9mV  -12.04mA   -19.48mA   -16.49mA
-572.7mV  -5.686mA   -4.83mA    -7.775mA
-334.1mV  -251.1uA   -319.4uA   -255.6uA
2.959V    6.555mA    5.154mA    8.451mA
[Power Clamp]
-1.459V   642.3mA    516.6mA    840.2mA
-1.077V   236.3mA    244.5mA    241.9mA
-1.03V    188.1mA    211.3mA    177.5mA
-981.8mV  142.1mA    178.6mA    120.9mA
-934.1mV  100mA      146.5mA    77.09mA
-886.4mV  64.59mA    115.5mA    50.99mA
-838.6mV  39.3mA     86.34mA    38.92mA
-743.2mV  19.29mA    38.41mA    25.82mA
-647.7mV  11.48mA    13.67mA    15.64mA
-552.3mV  5.78mA     5.687mA    7.751mA
-313.6mV  100uA      232.8uA    115uA
2.98V     -3.339mA   -2.795mA   -4.063mA
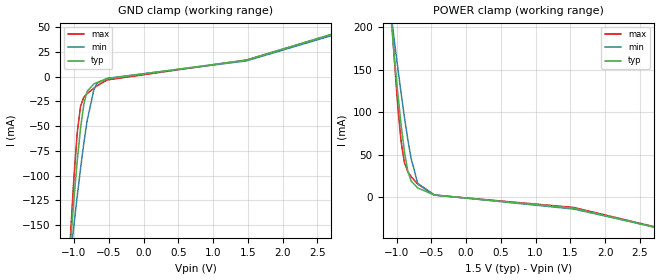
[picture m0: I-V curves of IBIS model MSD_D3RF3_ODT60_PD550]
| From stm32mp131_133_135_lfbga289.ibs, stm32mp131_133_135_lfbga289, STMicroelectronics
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[Model] MSD_D3RF3_ODT60_PD550
Model_type   Input
C_comp 2.346pF   2.300pF   2.406pF
Vinh = 925.000mV
Vinl = 575.000mV
[Model Spec]
Vinh   925.000mV   888.000mV   963.000mV
Vinl   575.000mV   538.000mV   613.000mV
[Temperature Range]   25.000   125.000   -40.000
[Voltage Range]   1.500V   1.425V   1.575V
[GND Clamp Reference]   0.00V   0.00V   0.00V
[POWER Clamp Reference]   1.500V   1.425V   1.575V
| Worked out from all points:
|   GND clamp passes 1 mA (typ) near -0.46 V on its own axis
|   POWER clamp passes 1 mA (typ) near -0.27 V on its own axis
[GND Clamp]
-1.48V    -604.1mA   -472.1mA   -811mA
-1.05V    -167.2mA   -181.1mA   -159.1mA
-1.002V   -124.3mA   -150.5mA   -102.2mA
-954.6mV  -85.33mA   -121.1mA   -56.96mA
-906.8mV  -52.28mA   -93.05mA   -29.95mA
-859.1mV  -27.87mA   -67.17mA   -20.71mA
-811.4mV  -14.69mA   -44.43mA   -17.11mA
-715.9mV  -7.418mA   -13.45mA   -11.73mA
-668.2mV  -5.771mA   -6.692mA   -9.283mA
-525mV    -2.059mA   -1.598mA   -3.262mA
1.48V     16.8mA     16mA       16.84mA
2.959V    48.47mA    46.91mA    47.83mA
[Power Clamp]
-1.459V   601.4mA    477.4mA    800mA
-1.077V   208.3mA    214.6mA    220.2mA
-1.03V    163.5mA    183.1mA    159.9mA
-981.8mV  122mA      152.2mA    106.5mA
-934.1mV  84.84mA    122.4mA    64.94mA
-886.4mV  53.42mA    94.1mA     40.63mA
-838.6mV  30.85mA    68.28mA    30.1mA
-790.9mV  19.1mA     45.9mA     24.35mA
-695.5mV  10.9mA     16.31mA    15.45mA
-456.8mV  2.5mA      2.734mA    2.481mA
1.548V    -13.03mA   -13.99mA   -12.09mA
2.98V     -40.72mA   -39.85mA   -40.16mA
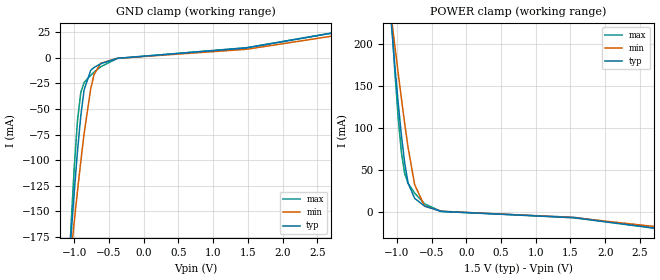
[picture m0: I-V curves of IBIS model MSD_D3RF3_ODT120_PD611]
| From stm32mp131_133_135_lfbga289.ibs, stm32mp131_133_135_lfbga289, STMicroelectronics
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[Model] MSD_D3RF3_ODT120_PD611
Model_type   Input
C_comp 2.373pF   2.329pF   2.477pF
Vinh = 925.000mV
Vinl = 575.000mV
[Temperature Range]   25.000   125.000   -40.000
[Voltage Range]   1.500V   1.425V   1.575V
[GND Clamp Reference]   0.00V   0.00V   0.00V
[POWER Clamp Reference]   1.500V   1.425V   1.575V
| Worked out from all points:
|   GND clamp passes 1 mA (typ) near -0.43 V on its own axis
|   POWER clamp passes 1 mA (typ) near -0.37 V on its own axis
[GND Clamp]
-1.48V    -619.6mA   -488.7mA   -826.8mA
-1.05V    -176.2mA   -192.1mA   -166.8mA
-1.002V   -131.9mA   -160.8mA   -108mA
-954.6mV  -91.32mA   -130.3mA   -61.36mA
-906.8mV  -56.63mA   -101.2mA   -33.73mA
-859.1mV  -31.19mA   -73.98mA   -24.09mA
-763.6mV  -12.04mA   -29.98mA   -17mA
-715.9mV  -9.432mA   -16.24mA   -14.05mA
-620.5mV  -5.72mA    -5.274mA   -8.678mA
-381.8mV  -443.6uA   -507uA     -553.4uA
1.48V     9.716mA    8.412mA    9.955mA
2.959V    27.19mA    23.86mA    27.21mA
[Power Clamp]
-1.459V   621.5mA    498.6mA    820mA
-1.077V   221.3mA    230.4mA    230.4mA
-1.03V    174.7mA    197.9mA    168.1mA
-981.8mV  130.7mA    165.9mA    113.3mA
-934.1mV  91.15mA    134.7mA    70.76mA
-886.4mV  58.15mA    104.8mA    45.59mA
-838.6mV  34.51mA    76.92mA    34.31mA
-743.2mV  16.3mA     32.5mA     22.56mA
-600mV    7.147mA    7.188mA    9.805mA
-361.4mV  922uA      1.106mA    771.8uA
1.548V    -6.715mA   -6.551mA   -6.145mA
2.98V     -21.98mA   -19.51mA   -21.77mA
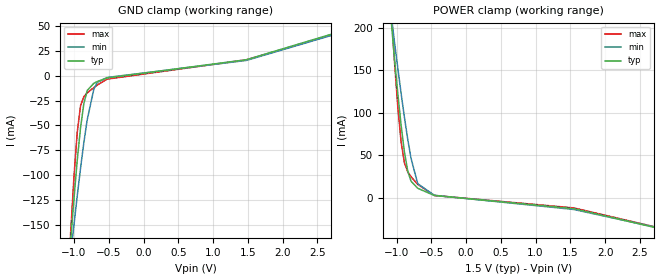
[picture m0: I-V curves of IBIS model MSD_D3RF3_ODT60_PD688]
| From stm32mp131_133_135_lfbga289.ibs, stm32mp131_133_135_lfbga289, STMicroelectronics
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[Model] MSD_D3RF3_ODT60_PD688
Model_type   Input
C_comp 2.376pF   2.329pF   2.437pF
Vinh = 925.000mV
Vinl = 575.000mV
[Temperature Range]   25.000   125.000   -40.000
[Voltage Range]   1.500V   1.425V   1.575V
[GND Clamp Reference]   0.00V   0.00V   0.00V
[POWER Clamp Reference]   1.500V   1.425V   1.575V
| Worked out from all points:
|   GND clamp passes 1 mA (typ) near -0.45 V on its own axis
|   POWER clamp passes 1 mA (typ) near -0.27 V on its own axis
[GND Clamp]
-1.48V    -604.4mA   -472.4mA   -811.4mA
-1.05V    -167.4mA   -181.2mA   -159.4mA
-1.002V   -124.5mA   -150.7mA   -102.5mA
-954.6mV  -85.49mA   -121.2mA   -57.17mA
-906.8mV  -52.42mA   -93.22mA   -30.14mA
-859.1mV  -28mA      -67.29mA   -20.88mA
-811.4mV  -14.81mA   -44.52mA   -17.26mA
-715.9mV  -7.508mA   -13.52mA   -11.84mA
-668.2mV  -5.843mA   -6.761mA   -9.385mA
-525mV    -2.097mA   -1.634mA   -3.315mA
1.48V     16.25mA    15.56mA    16.14mA
2.959V    47.36mA    46.02mA    46.37mA
[Power Clamp]
-1.459V   601.8mA    477.8mA    800.6mA
-1.077V   208.5mA    214.9mA    220.5mA
-1.03V    163.7mA    183.3mA    160.2mA
-981.8mV  122.2mA    152.4mA    106.8mA
-934.1mV  84.95mA    122.5mA    65.24mA
-886.4mV  53.58mA    94.29mA    40.86mA
-838.6mV  30.99mA    68.43mA    30.31mA
-790.9mV  19.24mA    46.02mA    24.53mA
-695.5mV  11mA       16.41mA    15.59mA
-456.8mV  2.53mA     2.765mA    2.53mA
1.548V    -13.02mA   -13.95mA   -12.09mA
2.98V     -40.16mA   -39.38mA   -39.48mA
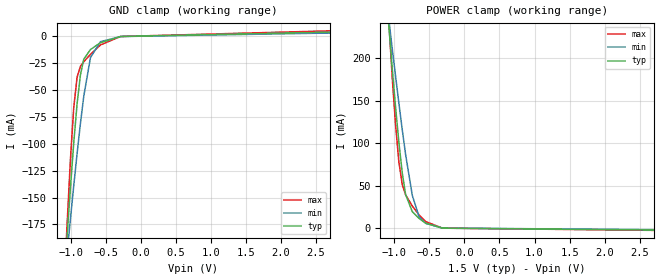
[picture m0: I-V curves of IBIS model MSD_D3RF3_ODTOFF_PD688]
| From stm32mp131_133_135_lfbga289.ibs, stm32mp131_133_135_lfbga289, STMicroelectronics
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[Model] MSD_D3RF3_ODTOFF_PD688
Model_type   Input
C_comp 2.444pF   2.361pF   2.568pF
Vinh = 925.000mV
Vinl = 575.000mV
[Temperature Range]   25.000   125.000   -40.000
[Voltage Range]   1.500V   1.425V   1.575V
[GND Clamp Reference]   0.00V   0.00V   0.00V
[POWER Clamp Reference]   1.500V   1.425V   1.575V
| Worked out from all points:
|   GND clamp passes 1 mA (typ) near -0.40 V on its own axis
|   POWER clamp passes 1 mA (typ) near -0.41 V on its own axis
[GND Clamp]
-1.48V    -636.3mA   -503.2mA   -843.3mA
-1.098V   -234.2mA   -234.7mA   -243.4mA
-1.05V    -186.7mA   -202.1mA   -175.7mA
-1.002V   -141.3mA   -170.2mA   -114.9mA
-954.6mV  -99.16mA   -139.1mA   -66.48mA
-906.8mV  -62.79mA   -109.1mA   -37.98mA
-859.1mV  -35.84mA   -80.96mA   -27.87mA
-811.4mV  -21.19mA   -55.62mA   -23.53mA
-715.9mV  -12.22mA   -19.62mA   -16.73mA
-572.7mV  -5.786mA   -4.913mA   -7.911mA
-286.4mV  -74.29uA   -124.8uA   -59.87uA
2.959V    4.37mA     3.435mA    5.634mA
[Power Clamp]
-1.459V   643.1mA    517.3mA    841.1mA
-1.077V   236.7mA    244.8mA    242.5mA
-1.03V    188.5mA    211.6mA    177.9mA
-981.8mV  142.4mA    178.9mA    121.3mA
-934.1mV  100.4mA    146.8mA    77.52mA
-886.4mV  64.9mA     115.8mA    51.38mA
-838.6mV  39.58mA    86.58mA    39.27mA
-743.2mV  19.5mA     38.6mA     26.09mA
-647.7mV  11.64mA    13.81mA    15.84mA
-552.3mV  5.881mA    5.782mA    7.869mA
-313.6mV  106uA      245.6uA    121.8uA
2.98V     -2.226mA   -1.864mA   -2.709mA
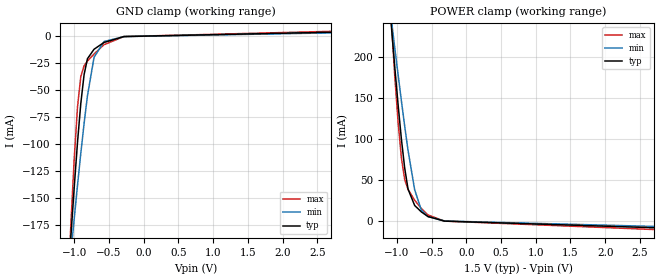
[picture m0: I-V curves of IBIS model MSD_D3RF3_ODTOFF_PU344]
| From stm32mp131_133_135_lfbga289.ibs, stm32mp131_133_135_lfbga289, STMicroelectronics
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[Model] MSD_D3RF3_ODTOFF_PU344
Model_type   Input
C_comp 2.329pF   2.247pF   2.450pF
Vinh = 925.000mV
Vinl = 575.000mV
[Temperature Range]   25.000   125.000   -40.000
[Voltage Range]   1.500V   1.425V   1.575V
[GND Clamp Reference]   0.00V   0.00V   0.00V
[POWER Clamp Reference]   1.500V   1.425V   1.575V
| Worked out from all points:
|   GND clamp passes 1 mA (typ) near -0.40 V on its own axis
|   POWER clamp passes 1 mA (typ) near -0.41 V on its own axis
[GND Clamp]
-1.48V    -634.9mA   -502mA     -841.5mA
-1.098V   -233.3mA   -233.9mA   -242.2mA
-1.05V    -186mA     -201.4mA   -174.7mA
-1.002V   -140.5mA   -169.5mA   -113.9mA
-954.6mV  -98.55mA   -138.4mA   -65.61mA
-906.8mV  -62.17mA   -108.5mA   -37.19mA
-859.1mV  -35.28mA   -80.48mA   -27.16mA
-811.4mV  -20.69mA   -55.19mA   -22.89mA
-715.9mV  -11.84mA   -19.29mA   -16.24mA
-572.7mV  -5.574mA   -4.721mA   -7.632mA
-286.4mV  -63.82uA   -109uA     -50.02uA
2.959V    4.306mA    3.667mA    5.207mA
[Power Clamp]
-1.459V   641.8mA    516.2mA    839.3mA
-1.077V   235.9mA    244.2mA    241.4mA
-1.03V    187.8mA    211mA      176.9mA
-981.8mV  141.7mA    178.3mA    120.4mA
-934.1mV  99.74mA    146.3mA    76.7mA
-886.4mV  64.34mA    115.4mA    50.64mA
-838.6mV  39.08mA    86.18mA    38.61mA
-743.2mV  19.12mA    38.29mA    25.58mA
-647.7mV  11.36mA    13.57mA    15.47mA
-552.3mV  5.707mA    5.631mA    7.646mA
-313.6mV  102.4uA    236.5uA    115uA
2.98V     -8.672mA   -6.979mA   -11.09mA
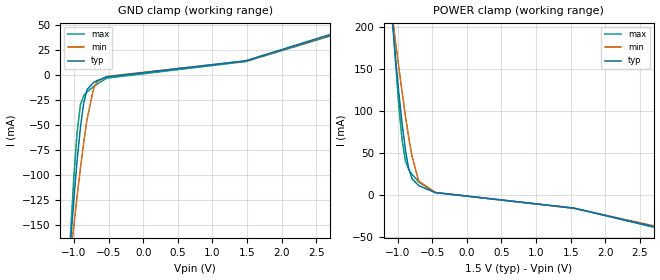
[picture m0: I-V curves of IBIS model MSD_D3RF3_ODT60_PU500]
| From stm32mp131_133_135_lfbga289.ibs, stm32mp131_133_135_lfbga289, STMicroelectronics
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[Model] MSD_D3RF3_ODT60_PU500
Model_type   Input
C_comp 2.336pF   2.289pF   2.396pF
Vinh = 925.000mV
Vinl = 575.000mV
[Temperature Range]   25.000   125.000   -40.000
[Voltage Range]   1.500V   1.425V   1.575V
[GND Clamp Reference]   0.00V   0.00V   0.00V
[POWER Clamp Reference]   1.500V   1.425V   1.575V
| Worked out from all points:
|   GND clamp passes 1 mA (typ) near -0.46 V on its own axis
|   POWER clamp passes 1 mA (typ) near -0.27 V on its own axis
[GND Clamp]
-1.48V    -603.9mA   -471.8mA   -810.7mA
-1.05V    -167.1mA   -180.8mA   -159mA
-1.002V   -124.2mA   -150.4mA   -102.1mA
-954.6mV  -85.26mA   -120.9mA   -56.81mA
-906.8mV  -52.23mA   -92.91mA   -29.81mA
-859.1mV  -27.83mA   -67.05mA   -20.59mA
-811.4mV  -14.66mA   -44.32mA   -16.99mA
-715.9mV  -7.4mA     -13.36mA   -11.63mA
-668.2mV  -5.756mA   -6.613mA   -9.204mA
-525mV    -2.054mA   -1.538mA   -3.216mA
1.48V     14.06mA    13.92mA    13.35mA
2.959V    45.96mA    45.14mA    44.31mA
[Power Clamp]
-1.459V   601.3mA    477.5mA    800mA
-1.077V   208.2mA    214.7mA    220.1mA
-1.03V    163.5mA    183.1mA    159.8mA
-981.8mV  121.9mA    152.2mA    106.4mA
-934.1mV  84.75mA    122.3mA    64.92mA
-886.4mV  53.37mA    94.1mA     40.59mA
-838.6mV  30.81mA    68.27mA    30.07mA
-790.9mV  19.08mA    45.89mA    24.32mA
-695.5mV  10.87mA    16.3mA     15.44mA
-456.8mV  2.498mA    2.732mA    2.497mA
1.548V    -16.05mA   -16.32mA   -16.06mA
2.98V     -43.83mA   -42.38mA   -44.44mA
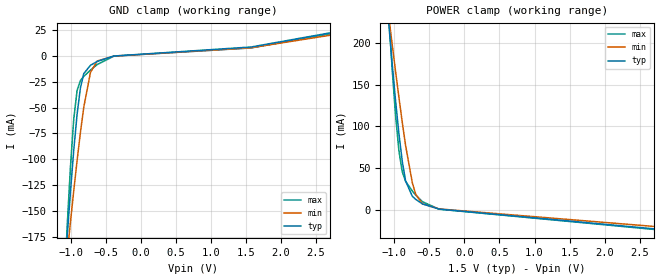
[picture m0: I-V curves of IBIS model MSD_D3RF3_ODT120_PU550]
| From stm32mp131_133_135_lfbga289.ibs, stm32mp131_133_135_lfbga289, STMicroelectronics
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[Model] MSD_D3RF3_ODT120_PU550
Model_type   Input
C_comp 2.358pF   2.313pF   2.462pF
Vinh = 925.000mV
Vinl = 575.000mV
[Temperature Range]   25.000   125.000   -40.000
[Voltage Range]   1.500V   1.425V   1.575V
[GND Clamp Reference]   0.00V   0.00V   0.00V
[POWER Clamp Reference]   1.500V   1.425V   1.575V
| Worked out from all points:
|   GND clamp passes 1 mA (typ) near -0.43 V on its own axis
|   POWER clamp passes 1 mA (typ) near -0.37 V on its own axis
[GND Clamp]
-1.48V    -619.4mA   -488.4mA   -826.5mA
-1.05V    -176mA     -191.9mA   -166.7mA
-1.002V   -131.8mA   -160.6mA   -107.8mA
-954.6mV  -91.16mA   -130.2mA   -61.24mA
-906.8mV  -56.54mA   -101.1mA   -33.62mA
-859.1mV  -31.1mA    -73.89mA   -23.99mA
-811.4mV  -17.36mA   -49.68mA   -20.04mA
-715.9mV  -9.366mA   -16.18mA   -13.99mA
-620.5mV  -5.675mA   -5.236mA   -8.63mA
-381.8mV  -436.8uA   -491uA     -540.4uA
1.575V    8.253mA    7.555mA    7.322mA
2.959V    24.97mA    22.28mA    24.13mA
[Power Clamp]
-1.459V   621.4mA    498.5mA    819.9mA
-1.077V   221.3mA    230.4mA    230.3mA
-1.03V    174.6mA    197.9mA    168mA
-981.8mV  130.7mA    165.9mA    113.2mA
-934.1mV  91.17mA    134.7mA    70.66mA
-886.4mV  58.1mA     104.8mA    45.52mA
-838.6mV  34.47mA    76.91mA    34.25mA
-743.2mV  16.27mA    32.5mA     22.51mA
-695.5mV  12.62mA    18.92mA    17.75mA
-600mV    7.137mA    7.191mA    9.782mA
-361.4mV  918.8uA    1.112mA    772.5uA
2.98V     -24.89mA   -21.78mA   -25.66mA
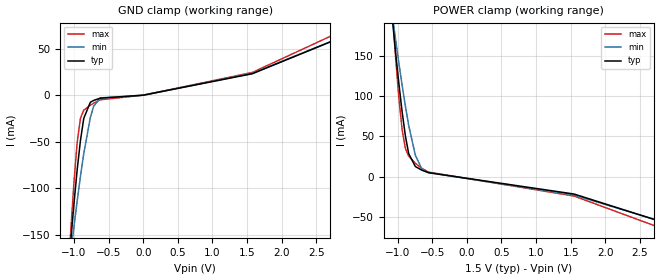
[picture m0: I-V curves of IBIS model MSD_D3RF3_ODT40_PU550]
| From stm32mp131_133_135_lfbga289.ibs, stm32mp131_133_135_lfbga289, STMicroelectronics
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[Model] MSD_D3RF3_ODT40_PU550
Model_type   Input
C_comp 2.316pF   2.274pF   2.393pF
Vinh = 925.000mV
Vinl = 575.000mV
[Temperature Range]   25.000   125.000   -40.000
[Voltage Range]   1.500V   1.425V   1.575V
[GND Clamp Reference]   0.00V   0.00V   0.00V
[POWER Clamp Reference]   1.500V   1.425V   1.575V
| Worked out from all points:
|   GND clamp passes 1 mA (typ) near -0.48 V on its own axis
|   POWER clamp passes 1 mA (typ) near -0.21 V on its own axis
[GND Clamp]
-1.48V    -589.6mA   -457.3mA   -788.7mA
-1.05V    -159.3mA   -171.8mA   -149.6mA
-1.002V   -117.9mA   -142.3mA   -95.1mA
-954.6mV  -80.49mA   -113.9mA   -51.03mA
-906.8mV  -48.63mA   -87.15mA   -24.78mA
-859.1mV  -24.92mA   -62.7mA    -16.1mA
-763.6mV  -7.568mA   -23.85mA   -10.74mA
-715.9mV  -5.62mA    -11.89mA   -8.65mA
-620.5mV  -3.184mA   -2.946mA   -4.936mA
900nV     12.74nA    12.04nA    14.81nA
1.575V    23.05mA    23.5mA     24.42mA
2.959V    65.04mA    65.26mA    72.1mA
[Power Clamp]
-1.459V   583.3mA    459.1mA    772.6mA
-1.077V   197.8mA    201.6mA    208.2mA
-1.03V    155.4mA    171.1mA    150.1mA
-981.8mV  116.1mA    141.6mA    98.34mA
-934.1mV  80.49mA    113.5mA    58.03mA
-886.4mV  50.12mA    87.17mA    34.79mA
-838.6mV  28.25mA    63.4mA     25.23mA
-743.2mV  12.46mA    26.4mA     16.47mA
-647.7mV  7.798mA    9.178mA    10.03mA
-552.3mV  4.784mA    4.825mA    5.462mA
1.548V    -21.77mA   -22.95mA   -24.26mA
2.98V     -60.83mA   -60.39mA   -69.68mA
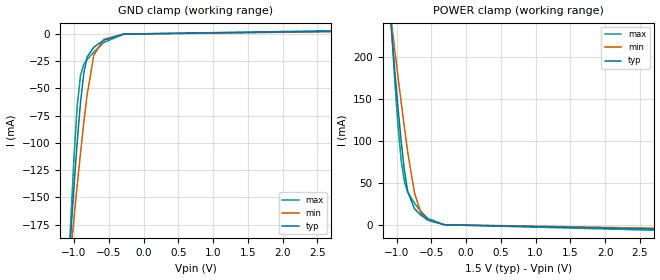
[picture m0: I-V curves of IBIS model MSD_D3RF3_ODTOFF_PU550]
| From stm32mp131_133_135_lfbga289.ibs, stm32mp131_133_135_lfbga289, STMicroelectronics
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[Model] MSD_D3RF3_ODTOFF_PU550
Model_type   Input
C_comp 2.417pF   2.334pF   2.540pF
Vinh = 925.000mV
Vinl = 575.000mV
[Temperature Range]   25.000   125.000   -40.000
[Voltage Range]   1.500V   1.425V   1.575V
[GND Clamp Reference]   0.00V   0.00V   0.00V
[POWER Clamp Reference]   1.500V   1.425V   1.575V
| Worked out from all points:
|   GND clamp passes 1 mA (typ) near -0.40 V on its own axis
|   POWER clamp passes 1 mA (typ) near -0.41 V on its own axis
[GND Clamp]
-1.48V    -635.9mA   -502.9mA   -842.9mA
-1.098V   -234mA     -234.4mA   -243.1mA
-1.05V    -186.6mA   -202mA     -175.5mA
-1.002V   -141mA     -169.9mA   -114.6mA
-954.6mV  -99.03mA   -138.8mA   -66.25mA
-906.8mV  -62.63mA   -109mA     -37.78mA
-859.1mV  -35.7mA    -80.82mA   -27.69mA
-811.4mV  -21.06mA   -55.49mA   -23.36mA
-715.9mV  -12.12mA   -19.53mA   -16.6mA
-572.7mV  -5.729mA   -4.859mA   -7.832mA
-286.4mV  -70.81uA   -119.8uA   -54.21uA
2.959V    2.692mA    2.292mA    3.254mA
[Power Clamp]
-1.459V   642.8mA    517.1mA    840.6mA
-1.077V   236.5mA    244.7mA    242.2mA
-1.03V    188.3mA    211.6mA    177.7mA
-981.8mV  142.3mA    178.7mA    121.1mA
-934.1mV  100.3mA    146.6mA    77.33mA
-886.4mV  64.78mA    115.7mA    51.2mA
-838.6mV  39.47mA    86.53mA    39.12mA
-743.2mV  19.42mA    38.55mA    25.98mA
-647.7mV  11.58mA    13.77mA    15.75mA
-552.3mV  5.846mA    5.759mA    7.822mA
-313.6mV  108.7uA    249.1uA    122.8uA
2.98V     -5.414mA   -4.356mA   -6.939mA
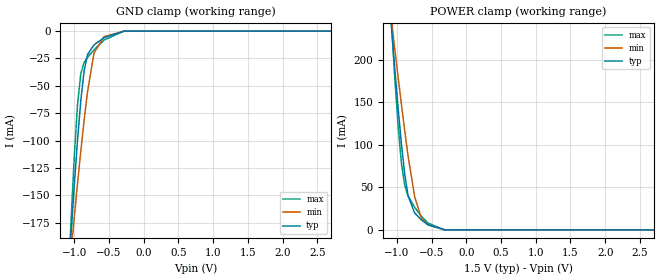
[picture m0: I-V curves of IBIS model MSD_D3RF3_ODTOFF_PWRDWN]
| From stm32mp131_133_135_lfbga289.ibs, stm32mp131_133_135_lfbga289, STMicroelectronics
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[Model] MSD_D3RF3_ODTOFF_PWRDWN
Model_type   Input
C_comp 2.563pF   2.479pF   2.689pF
Vinh = 925.000mV
Vinl = 575.000mV
[Model Spec]
Vinh   925.000mV   888.000mV   963.000mV
Vinl   575.000mV   538.000mV   613.000mV
[Temperature Range]   25.000   125.000   -40.000
[Voltage Range]   1.500V   1.425V   1.575V
[GND Clamp Reference]   0.00V   0.00V   0.00V
[POWER Clamp Reference]   1.500V   1.425V   1.575V
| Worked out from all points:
|   GND clamp passes 1 mA (typ) near -0.40 V on its own axis
|   POWER clamp passes 1 mA (typ) near -0.41 V on its own axis
[GND Clamp]
-1.48V    -637.6mA   -504.4mA   -845.1mA
-1.098V   -235mA     -235.3mA   -244.5mA
-1.05V    -187.5mA   -202.8mA   -176.7mA
-1.002V   -142mA     -170.7mA   -115.8mA
-954.6mV  -99.83mA   -139.6mA   -67.33mA
-906.8mV  -63.38mA   -109.6mA   -38.75mA
-859.1mV  -36.37mA   -81.39mA   -28.57mA
-811.4mV  -21.66mA   -56mA      -24.15mA
-715.9mV  -12.58mA   -19.92mA   -17.2mA
-572.7mV  -5.989mA   -5.081mA   -8.179mA
-286.4mV  -79.48uA   -131.6uA   -65.75uA
2.959V    34.08nA    533.5nA    4.718nA
[Power Clamp]
-1.459V   644.6mA    518.6mA    842.9mA
-1.077V   237.6mA    245.6mA    243.6mA
-1.03V    189.3mA    212.4mA    178.9mA
-981.8mV  143.2mA    179.5mA    122.3mA
-934.1mV  101mA      147.3mA    78.38mA
-886.4mV  65.52mA    116.3mA    52.15mA
-838.6mV  40.13mA    87.09mA    39.97mA
-743.2mV  19.93mA    38.99mA    26.63mA
-647.7mV  11.94mA    14.09mA    16.22mA
-552.3mV  6.078mA    5.973mA    8.115mA
-313.6mV  119.3uA    270uA      135.9uA
2.98V     -53.59nA   -976.4nA   -5.122nA
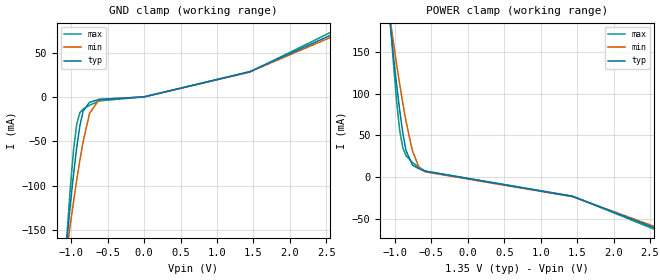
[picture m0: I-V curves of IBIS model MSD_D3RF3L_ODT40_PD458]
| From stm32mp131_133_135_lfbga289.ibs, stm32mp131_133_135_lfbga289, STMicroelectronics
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[Model] MSD_D3RF3L_ODT40_PD458
Model_type   Input
C_comp 2.330pF   2.291pF   2.382pF
Vinh = 810.000mV
Vinl = 540.000mV
[Receiver Thresholds]
Vth   =  0.675V
Vth_min  =  0.6615V
Vth_max  =  0.6885V
Vinh_ac  =  0.160V
Vinh_dc  =  0.090V
Vinl_ac  = -0.160V
Vinl_dc  = -0.090V
Tslew_ac =  5.000ns |Not specified, so set to high value
[Temperature Range]   25.000   125.000   -40.000
[Voltage Range]   1.350V   1.283V   1.450V
[GND Clamp Reference]   0.00V   0.00V   0.00V
[POWER Clamp Reference]   1.350V   1.283V   1.450V
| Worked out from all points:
|   GND clamp passes 1 mA (typ) near -0.47 V on its own axis
|   POWER clamp passes 1 mA (typ) near -0.15 V on its own axis
[GND Clamp]
-1.318V   -415.4mA   -341.4mA   -533.5mA
-1.055V   -159.3mA   -170.5mA   -153.4mA
-1.011V   -121.7mA   -143.7mA   -102.7mA
-966.7mV  -87.2mA    -118mA     -59.85mA
-922.7mV  -56.77mA   -93.49mA   -30.25mA
-878.8mV  -32.1mA    -70.78mA   -17.59mA
-834.9mV  -15.96mA   -50.17mA   -13.63mA
-747mV    -6.03mA    -18.57mA   -9.49mA
-615.1mV  -2.85mA    -2.852mA   -4.52mA
200nV     3.87nA     3.647nA    4.059nA
1.45V     28.54mA    28.18mA    27.96mA
2.68V     73.9mA     71.3mA     77.58mA
[Power Clamp]
-1.33V    440.9mA    363.5mA    565.9mA
-1.067V   185mA      190.2mA    192.4mA
-1.023V   147.7mA    163mA      140.1mA
-978.8mV  112.9mA    136.7mA    93.38mA
-934.9mV  80.78mA    111.7mA    56.6mA
-890.9mV  52.9mA     88.3mA     35.17mA
-847mV    31.77mA    66.79mA    25.86mA
-759.1mV  14.63mA    31.55mA    17.7mA
-671.2mV  10.11mA    12.2mA     11.83mA
-583.3mV  7.179mA    6.41mA     7.369mA
1.438V    -22.9mA    -23.29mA   -22.63mA
2.668V    -64.06mA   -62.26mA   -66.08mA
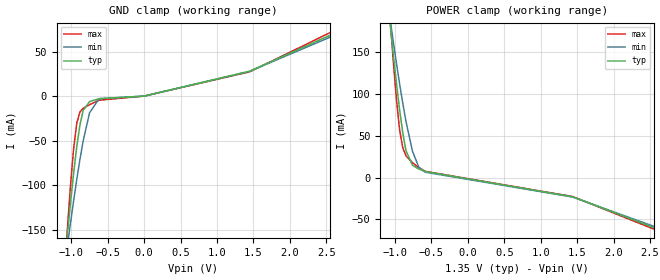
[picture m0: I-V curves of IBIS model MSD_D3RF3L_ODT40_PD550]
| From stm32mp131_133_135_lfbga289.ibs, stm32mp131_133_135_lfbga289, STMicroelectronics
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[Model] MSD_D3RF3L_ODT40_PD550
Model_type   Input
C_comp 2.360pF   2.320pF   2.412pF
Vinh = 810.000mV
Vinl = 540.000mV
[Model Spec]
Vinh   810.000mV   777.000mV   860.000mV
Vinl   540.000mV   507.000mV   590.000mV
[Receiver Thresholds]
Vth   =  0.675V
Vth_min  =  0.6615V
Vth_max  =  0.6885V
Vinh_ac  =  0.160V
Vinh_dc  =  0.090V
Vinl_ac  = -0.160V
Vinl_dc  = -0.090V
Tslew_ac =  5.000ns |Not specified, so set to high value
[Temperature Range]   25.000   125.000   -40.000
[Voltage Range]   1.350V   1.283V   1.450V
[GND Clamp Reference]   0.00V   0.00V   0.00V
[POWER Clamp Reference]   1.350V   1.283V   1.450V
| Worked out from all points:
|   GND clamp passes 1 mA (typ) near -0.46 V on its own axis
|   POWER clamp passes 1 mA (typ) near -0.15 V on its own axis
[GND Clamp]
-1.318V   -415.7mA   -341.7mA   -533.8mA
-1.055V   -159.4mA   -170.7mA   -153.6mA
-1.011V   -121.9mA   -143.9mA   -102.8mA
-966.7mV  -87.35mA   -118.1mA   -60.09mA
-922.7mV  -56.91mA   -93.68mA   -30.42mA
-878.8mV  -32.23mA   -70.86mA   -17.75mA
-834.9mV  -16.08mA   -50.29mA   -13.77mA
-747mV    -6.122mA   -18.66mA   -9.6mA
-615.1mV  -2.914mA   -2.918mA   -4.59mA
200nV     3.811nA    3.57nA     3.964nA
1.45V     28.01mA    27.78mA    27.27mA
2.68V     72.93mA    70.62mA    76.33mA
[Power Clamp]
-1.33V    441.2mA    363.6mA    566.3mA
-1.067V   185.2mA    190.4mA    192.6mA
-1.023V   147.9mA    163.1mA    140.4mA
-978.8mV  113mA      136.8mA    93.61mA
-934.9mV  80.91mA    111.8mA    56.82mA
-890.9mV  53.01mA    88.36mA    35.36mA
-847mV    31.91mA    66.84mA    26.03mA
-759.1mV  14.75mA    31.61mA    17.84mA
-671.2mV  10.2mA     12.24mA    11.93mA
-583.3mV  7.243mA    6.43mA     7.442mA
1.438V    -22.87mA   -23.24mA   -22.63mA
2.668V    -63.58mA   -61.82mA   -65.53mA
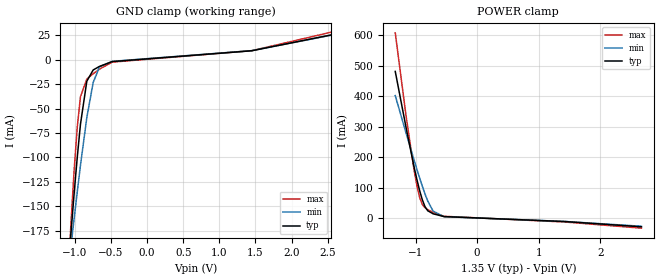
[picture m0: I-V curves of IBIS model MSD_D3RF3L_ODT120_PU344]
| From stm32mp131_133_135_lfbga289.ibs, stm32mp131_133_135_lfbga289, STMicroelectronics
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[Model] MSD_D3RF3L_ODT120_PU344
Model_type   Input
C_comp 2.295pF   2.217pF   2.385pF
Vinh = 810.000mV
Vinl = 540.000mV
[Receiver Thresholds]
Vth   =  0.675V
Vth_min  =  0.6615V
Vth_max  =  0.6885V
Vinh_ac  =  0.160V
Vinh_dc  =  0.090V
Vinl_ac  = -0.160V
Vinl_dc  = -0.090V
Tslew_ac =  5.000ns |Not specified, so set to high value
[Temperature Range]   25.000   125.000   -40.000
[Voltage Range]   1.350V   1.283V   1.450V
[GND Clamp Reference]   0.00V   0.00V   0.00V
[POWER Clamp Reference]   1.350V   1.283V   1.450V
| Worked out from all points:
|   GND clamp passes 1 mA (typ) near -0.43 V on its own axis
|   POWER clamp passes 1 mA (typ) near -0.31 V on its own axis
[GND Clamp]
-1.318V   -445.8mA   -370.8mA   -564.1mA
-1.098V   -220.8mA   -220.7mA   -229.1mA
-1.055V   -178.2mA   -191.5mA   -168.5mA
-1.011V   -137.3mA   -162.9mA   -113.8mA
-966.7mV  -99.42mA   -135mA     -68.62mA
-922.7mV  -65.94mA   -108mA     -37.78mA
-834.9mV  -21.89mA   -59.21mA   -19.67mA
-747mV    -10.36mA   -23.21mA   -14.23mA
-659.1mV  -6.683mA   -7.168mA   -9.487mA
-483.3mV  -1.77mA    -1.488mA   -2.3mA
1.45V     9.36mA     9.466mA    9.417mA
2.68V     27.53mA    27.15mA    30.65mA
[Power Clamp]
-1.33V    481mA      401.6mA    607.4mA
-1.155V   297.4mA    279.1mA    335.7mA
-1.023V   166.2mA    189.3mA    155.8mA
-978.8mV  126.5mA    160.2mA    106.6mA
-934.9mV  90.61mA    131.9mA    67.77mA
-890.9mV  60.17mA    104.6mA    44.6mA
-847mV    37.3mA     79.04mA    33.74mA
-803mV    23.96mA    56.1mA     27.69mA
-715.1mV  13.96mA    22.71mA    18.56mA
-539.4mV  4.811mA    4.522mA    5.696mA
1.438V    -11.64mA   -11.3mA    -13.17mA
2.668V    -28.77mA   -26.98mA   -33.2mA
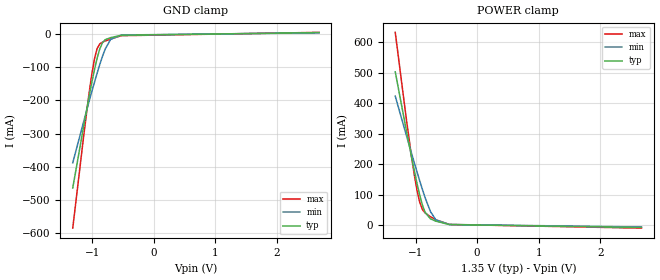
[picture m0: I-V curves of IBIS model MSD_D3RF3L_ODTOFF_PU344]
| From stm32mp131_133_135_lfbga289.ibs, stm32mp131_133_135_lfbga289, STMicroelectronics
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[Model] MSD_D3RF3L_ODTOFF_PU344
Model_type   Input
C_comp 2.337pF   2.253pF   2.460pF
Vinh = 810.000mV
Vinl = 540.000mV
[Receiver Thresholds]
Vth   =  0.675V
Vth_min  =  0.6615V
Vth_max  =  0.6885V
Vinh_ac  =  0.160V
Vinh_dc  =  0.090V
Vinl_ac  = -0.160V
Vinl_dc  = -0.090V
Tslew_ac =  5.000ns |Not specified, so set to high value
[Temperature Range]   25.000   125.000   -40.000
[Voltage Range]   1.350V   1.283V   1.450V
[GND Clamp Reference]   0.00V   0.00V   0.00V
[POWER Clamp Reference]   1.350V   1.283V   1.450V
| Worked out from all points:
|   GND clamp passes 1 mA (typ) near -0.41 V on its own axis
|   POWER clamp passes 1 mA (typ) near -0.41 V on its own axis
[GND Clamp]
-1.318V   -463.1mA   -387.5mA   -584mA
-1.142V   -278.9mA   -264.6mA   -309mA
-1.055V   -190.3mA   -204.4mA   -180.9mA
-1.011V   -148.2mA   -175mA     -123.8mA
-966.7mV  -108.8mA   -146.2mA   -76.27mA
-922.7mV  -73.42mA   -118.3mA   -44.12mA
-878.8mV  -44.95mA   -91.77mA   -29.96mA
-834.9mV  -26.35mA   -67.18mA   -24.76mA
-790.9mV  -17.51mA   -45.54mA   -21.38mA
-703mV    -11.17mA   -16.42mA   -15.39mA
-527.3mV  -3.973mA   -3.331mA   -5.371mA
2.68V     3.876mA    3.288mA    4.595mA
[Power Clamp]
-1.33V    503.4mA    423.6mA    633.1mA
-1.155V   316.4mA    298.6mA    356mA
-1.067V   225.1mA    236.8mA    226.3mA
-1.023V   181mA      206.3mA    168mA
-978.8mV  138.9mA    176.3mA    116.7mA
-934.9mV  100.4mA    146.8mA    76.38mA
-890.9mV  67.34mA    118.2mA    52.01mA
-847mV    42.61mA    91.05mA    40.12mA
-759.1mV  20.88mA    44.79mA    27.48mA
-671.2mV  13.02mA    17.35mA    17.74mA
-451.5mV  1.841mA    2.085mA    2.323mA
2.668V    -7.641mA   -6.116mA   -9.847mA
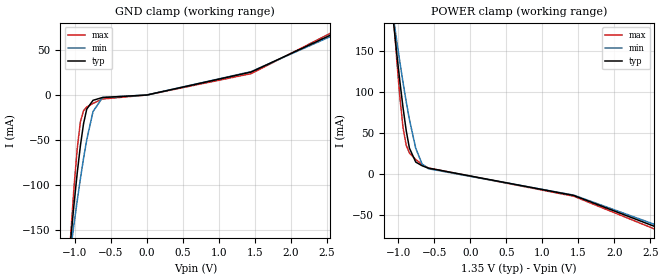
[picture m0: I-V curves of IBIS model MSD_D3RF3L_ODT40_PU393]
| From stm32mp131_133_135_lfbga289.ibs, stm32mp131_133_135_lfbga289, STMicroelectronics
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[Model] MSD_D3RF3L_ODT40_PU393
Model_type   Input
C_comp 2.304pF   2.264pF   2.357pF
Vinh = 810.000mV
Vinl = 540.000mV
[Receiver Thresholds]
Vth   =  0.675V
Vth_min  =  0.6615V
Vth_max  =  0.6885V
Vinh_ac  =  0.160V
Vinh_dc  =  0.090V
Vinl_ac  = -0.160V
Vinl_dc  = -0.090V
Tslew_ac =  5.000ns |Not specified, so set to high value
[Temperature Range]   25.000   125.000   -40.000
[Voltage Range]   1.350V   1.283V   1.450V
[GND Clamp Reference]   0.00V   0.00V   0.00V
[POWER Clamp Reference]   1.350V   1.283V   1.450V
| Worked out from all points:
|   GND clamp passes 1 mA (typ) near -0.47 V on its own axis
|   POWER clamp passes 1 mA (typ) near -0.14 V on its own axis
[GND Clamp]
-1.318V   -415.1mA   -341mA     -533mA
-1.055V   -159mA     -170.3mA   -153mA
-1.011V   -121.4mA   -143.5mA   -102.4mA
-966.7mV  -86.93mA   -117.8mA   -59.6mA
-922.7mV  -56.51mA   -93.28mA   -29.99mA
-878.8mV  -31.9mA    -70.58mA   -17.36mA
-834.9mV  -15.78mA   -49.99mA   -13.42mA
-747mV    -5.886mA   -18.44mA   -9.318mA
-615.1mV  -2.752mA   -2.762mA   -4.406mA
200nV     3.399nA    3.255nA    3.442nA
1.45V     25.61mA    26.04mA    23.83mA
2.68V     71.42mA    69.67mA    74.01mA
[Power Clamp]
-1.33V    440.8mA    363.4mA    565.6mA
-1.067V   184.9mA    190.1mA    192.2mA
-1.023V   147.6mA    162.9mA    140mA
-978.8mV  112.8mA    136.6mA    93.19mA
-934.9mV  80.71mA    111.6mA    56.41mA
-890.9mV  52.84mA    88.24mA    35.02mA
-847mV    31.71mA    66.75mA    25.73mA
-759.1mV  14.59mA    31.52mA    17.6mA
-671.2mV  10.08mA    12.18mA    11.76mA
-583.3mV  7.175mA    6.393mA    7.323mA
1.438V    -26.33mA   -25.92mA   -27.29mA
2.668V    -67.83mA   -65.18mA   -71.22mA
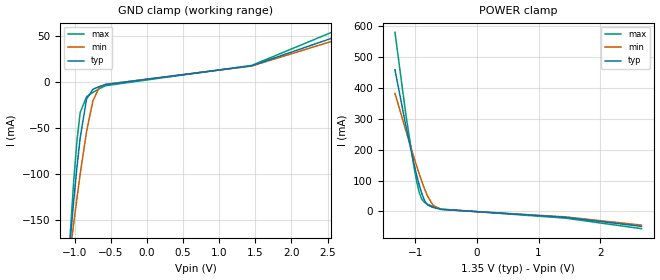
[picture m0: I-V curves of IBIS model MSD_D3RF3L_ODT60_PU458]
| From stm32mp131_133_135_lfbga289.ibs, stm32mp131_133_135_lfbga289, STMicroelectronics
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[Model] MSD_D3RF3L_ODT60_PU458
Model_type   Input
C_comp 2.350pF   2.299pF   2.419pF
Vinh = 810.000mV
Vinl = 540.000mV
[Receiver Thresholds]
Vth   =  0.675V
Vth_min  =  0.6615V
Vth_max  =  0.6885V
Vinh_ac  =  0.160V
Vinh_dc  =  0.090V
Vinl_ac  = -0.160V
Vinl_dc  = -0.090V
Tslew_ac =  5.000ns |Not specified, so set to high value
[Temperature Range]   25.000   125.000   -40.000
[Voltage Range]   1.350V   1.283V   1.450V
[GND Clamp Reference]   0.00V   0.00V   0.00V
[POWER Clamp Reference]   1.350V   1.283V   1.450V
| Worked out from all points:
|   GND clamp passes 1 mA (typ) near -0.46 V on its own axis
|   POWER clamp passes 1 mA (typ) near -0.18 V on its own axis
[GND Clamp]
-1.318V   -429.4mA   -356.4mA   -544.6mA
-1.098V   -208.7mA   -209.3mA   -216.4mA
-1.055V   -167.4mA   -180.9mA   -158.5mA
-1.011V   -128.1mA   -153mA     -106.6mA
-966.7mV  -92.07mA   -126mA     -63.1mA
-922.7mV  -60.5mA    -100.1mA   -33.1mA
-834.9mV  -18.49mA   -53.93mA   -15.9mA
-747mV    -7.842mA   -20.44mA   -11.23mA
-659.1mV  -4.88mA    -5.749mA   -7.25mA
-571.2mV  -2.748mA   -2.372mA   -3.92mA
1.45V     17.79mA    17.5mA     18.18mA
2.68V     51.17mA    47.43mA    58.28mA
[Power Clamp]
-1.33V    458.8mA    382.9mA    580.2mA
-1.155V   279.2mA    262.9mA    316.2mA
-1.023V   154.6mA    175.6mA    145.1mA
-978.8mV  117.8mA    147.6mA    97.64mA
-934.9mV  84.46mA    120.6mA    60.24mA
-890.9mV  55.73mA    95mA       38.23mA
-847mV    33.99mA    71.38mA    28.42mA
-803mV    21.49mA    50.51mA    23.32mA
-715.1mV  12.77mA    20.56mA    15.86mA
-583.3mV  6.889mA    6.158mA    7.594mA
1.438V    -19.25mA   -17.75mA   -21.87mA
2.668V    -48.48mA   -44.39mA   -55.88mA
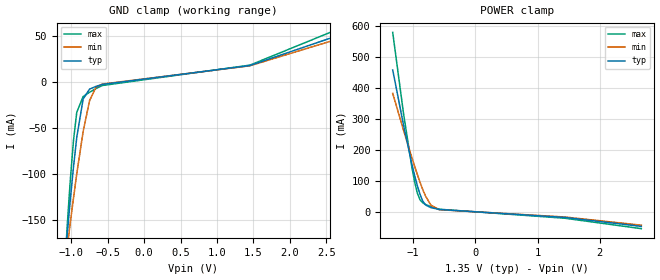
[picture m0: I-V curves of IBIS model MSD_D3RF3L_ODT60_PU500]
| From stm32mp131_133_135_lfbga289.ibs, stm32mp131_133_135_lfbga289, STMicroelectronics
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[Model] MSD_D3RF3L_ODT60_PU500
Model_type   Input
C_comp 2.367pF   2.316pF   2.436pF
Vinh = 810.000mV
Vinl = 540.000mV
[Receiver Thresholds]
Vth   =  0.675V
Vth_min  =  0.6615V
Vth_max  =  0.6885V
Vinh_ac  =  0.160V
Vinh_dc  =  0.090V
Vinl_ac  = -0.160V
Vinl_dc  = -0.090V
Tslew_ac =  5.000ns |Not specified, so set to high value
[Temperature Range]   25.000   125.000   -40.000
[Voltage Range]   1.350V   1.283V   1.450V
[GND Clamp Reference]   0.00V   0.00V   0.00V
[POWER Clamp Reference]   1.350V   1.283V   1.450V
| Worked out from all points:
|   GND clamp passes 1 mA (typ) near -0.46 V on its own axis
|   POWER clamp passes 1 mA (typ) near -0.18 V on its own axis
[GND Clamp]
-1.318V   -429.6mA   -356.5mA   -544.9mA
-1.098V   -208.9mA   -209.4mA   -216.6mA
-1.055V   -167.5mA   -181mA     -158.6mA
-1.011V   -128.3mA   -153.1mA   -106.7mA
-966.7mV  -92.19mA   -126.1mA   -63.25mA
-922.7mV  -60.57mA   -100.2mA   -33.19mA
-834.9mV  -18.56mA   -53.96mA   -15.97mA
-747mV    -7.888mA   -20.47mA   -11.29mA
-659.1mV  -4.92mA    -5.767mA   -7.29mA
-571.2mV  -2.772mA   -2.38mA    -3.95mA
1.45V     17.77mA    17.47mA    18.18mA
2.68V     50.96mA    47.21mA    57.99mA
[Power Clamp]
-1.33V    458.9mA    383mA      580.4mA
-1.155V   279.4mA    263mA      316.3mA
-1.023V   154.6mA    175.8mA    145.3mA
-978.8mV  117.8mA    147.7mA    97.76mA
-934.9mV  84.51mA    120.7mA    60.34mA
-890.9mV  55.78mA    95.04mA    38.33mA
-847mV    34.05mA    71.43mA    28.5mA
-803mV    21.53mA    50.58mA    23.39mA
-715.1mV  12.8mA     20.61mA    15.92mA
-583.3mV  6.9mA      6.19mA     7.624mA
1.438V    -18.99mA   -17.56mA   -21.54mA
2.668V    -48mA      -44.05mA   -55.28mA
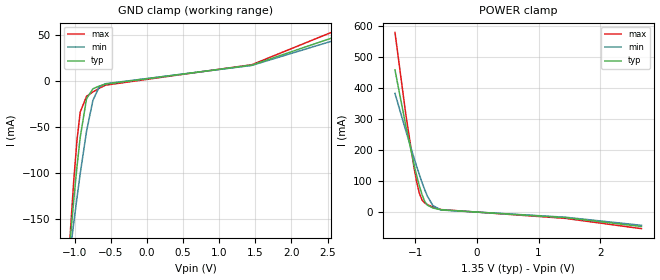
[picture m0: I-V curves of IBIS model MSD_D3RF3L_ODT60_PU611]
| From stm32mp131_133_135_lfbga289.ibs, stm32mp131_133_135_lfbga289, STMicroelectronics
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[Model] MSD_D3RF3L_ODT60_PU611
Model_type   Input
C_comp 2.396pF   2.345pF   2.465pF
Vinh = 810.000mV
Vinl = 540.000mV
[Receiver Thresholds]
Vth   =  0.675V
Vth_min  =  0.6615V
Vth_max  =  0.6885V
Vinh_ac  =  0.160V
Vinh_dc  =  0.090V
Vinl_ac  = -0.160V
Vinl_dc  = -0.090V
Tslew_ac =  5.000ns |Not specified, so set to high value
[Temperature Range]   25.000   125.000   -40.000
[Voltage Range]   1.350V   1.283V   1.450V
[GND Clamp Reference]   0.00V   0.00V   0.00V
[POWER Clamp Reference]   1.350V   1.283V   1.450V
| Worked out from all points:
|   GND clamp passes 1 mA (typ) near -0.45 V on its own axis
|   POWER clamp passes 1 mA (typ) near -0.18 V on its own axis
[GND Clamp]
-1.318V   -429.9mA   -356.8mA   -545.2mA
-1.098V   -209.1mA   -209.7mA   -216.9mA
-1.055V   -167.7mA   -181.2mA   -158.9mA
-1.011V   -128.4mA   -153.3mA   -107mA
-966.7mV  -92.33mA   -126.3mA   -63.46mA
-922.7mV  -60.75mA   -100.4mA   -33.39mA
-834.9mV  -18.7mA    -54.11mA   -16.14mA
-747mV    -8.01mA    -20.59mA   -11.42mA
-659.1mV  -5mA       -5.86mA    -7.39mA
-571.2mV  -2.84mA    -2.454mA   -4.01mA
1.45V     17.74mA    17.41mA    18.18mA
2.68V     50.46mA    46.78mA    57.44mA
[Power Clamp]
-1.33V    459.2mA    383.3mA    580.7mA
-1.155V   279.6mA    263.2mA    316.6mA
-1.023V   154.8mA    175.9mA    145.5mA
-978.8mV  118mA      147.8mA    98.01mA
-934.9mV  84.66mA    120.8mA    60.55mA
-890.9mV  55.93mA    95.21mA    38.51mA
-847mV    34.18mA    71.57mA    28.67mA
-803mV    21.65mA    50.69mA    23.54mA
-715.1mV  12.9mA     20.7mA     16.02mA
-583.3mV  6.966mA    6.246mA    7.69mA
1.438V    -18.47mA   -17.13mA   -20.88mA
2.668V    -47.03mA   -43.22mA   -54.05mA
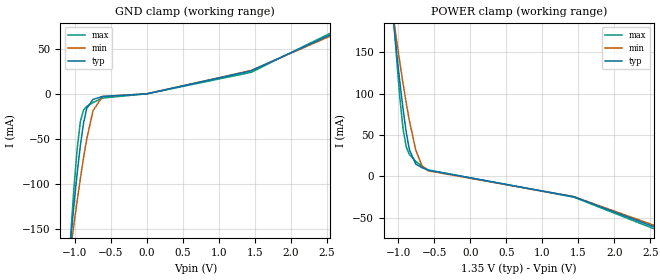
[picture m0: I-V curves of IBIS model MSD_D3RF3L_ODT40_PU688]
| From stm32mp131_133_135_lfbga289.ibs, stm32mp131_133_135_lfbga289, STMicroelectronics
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[Model] MSD_D3RF3L_ODT40_PU688
Model_type   Input
C_comp 2.392pF   2.351pF   2.445pF
Vinh = 810.000mV
Vinl = 540.000mV
[Model Spec]
Vinh   810.000mV   777.000mV   860.000mV
Vinl   540.000mV   507.000mV   590.000mV
[Receiver Thresholds]
Vth   =  0.675V
Vth_min  =  0.6615V
Vth_max  =  0.6885V
Vinh_ac  =  0.160V
Vinh_dc  =  0.090V
Vinl_ac  = -0.160V
Vinl_dc  = -0.090V
Tslew_ac =  5.000ns |Not specified, so set to high value
[Temperature Range]   25.000   125.000   -40.000
[Voltage Range]   1.350V   1.283V   1.450V
[GND Clamp Reference]   0.00V   0.00V   0.00V
[POWER Clamp Reference]   1.350V   1.283V   1.450V
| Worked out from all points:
|   GND clamp passes 1 mA (typ) near -0.46 V on its own axis
|   POWER clamp passes 1 mA (typ) near -0.15 V on its own axis
[GND Clamp]
-1.318V   -415.9mA   -341.8mA   -534.1mA
-1.055V   -159.6mA   -170.7mA   -153.8mA
-1.011V   -122mA     -143.9mA   -103.1mA
-966.7mV  -87.5mA    -118.2mA   -60.23mA
-922.7mV  -57.03mA   -93.64mA   -30.59mA
-878.8mV  -32.32mA   -70.91mA   -17.9mA
-834.9mV  -16.16mA   -50.3mA    -13.91mA
-747mV    -6.178mA   -18.67mA   -9.708mA
-615.1mV  -2.936mA   -2.906mA   -4.646mA
200nV     3.399nA    3.254nA    3.451nA
1.45V     25.51mA    25.9mA     23.83mA
2.68V     70.03mA    68.46mA    72.27mA
[Power Clamp]
-1.33V    441.6mA    364.1mA    566.8mA
-1.067V   185.5mA    190.7mA    193mA
-1.023V   148.2mA    163.4mA    140.7mA
-978.8mV  113.2mA    137.1mA    93.87mA
-934.9mV  81.08mA    112mA      57.1mA
-890.9mV  53.17mA    88.61mA    35.62mA
-847mV    32.07mA    67.08mA    26.25mA
-759.1mV  14.87mA    31.78mA    18.02mA
-671.2mV  10.29mA    12.37mA    12.07mA
-583.3mV  7.299mA    6.53mA     7.534mA
1.438V    -24.78mA   -24.68mA   -25.3mA
2.668V    -64.99mA   -62.93mA   -67.55mA
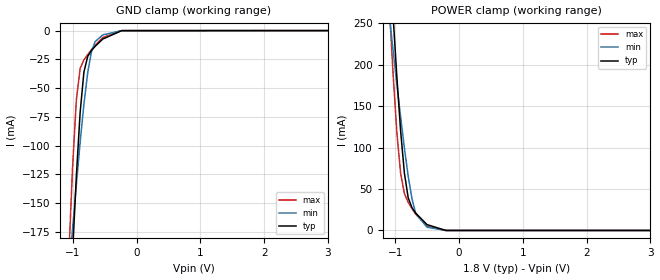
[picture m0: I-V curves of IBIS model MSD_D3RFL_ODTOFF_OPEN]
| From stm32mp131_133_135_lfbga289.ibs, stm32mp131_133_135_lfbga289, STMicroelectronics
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[Model] MSD_D3RFL_ODTOFF_OPEN
Model_type   Input
C_comp 2.528pF   2.464pF   2.678pF
Vinh = 1.440V
Vinl = 360.000mV
[Temperature Range]   25.000   125.000   -40.000
[Voltage Range]   1.800V   1.650V   1.950V
[GND Clamp Reference]   0.00V   0.00V   0.00V
[POWER Clamp Reference]   1.800V   1.650V   1.950V
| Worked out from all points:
|   GND clamp passes 1 mA (typ) near -0.34 V on its own axis
|   POWER clamp passes 1 mA (typ) near -0.34 V on its own axis
[GND Clamp]
-1.773V   -1.218A    -715mA     -1.317A
-1.064V   -265.6mA   -212mA     -195.6mA
-1.005V   -192.9mA   -172.3mA   -118.5mA
-945.5mV  -126.2mA   -133.7mA   -60.14mA
-886.4mV  -71.07mA   -97.22mA   -32.93mA
-827.3mV  -36.1mA    -64.07mA   -25.45mA
-768.2mV  -22.49mA   -36.69mA   -20.9mA
-709.1mV  -17.32mA   -18.33mA   -16.73mA
-650mV    -13.63mA   -9.511mA   -12.81mA
-531.8mV  -7.369mA   -3.752mA   -6.027mA
-236.4mV  -88.96uA   -41.61uA   -9.813uA
3.545V    302.5nA    529.3nA    3.973nA
[Power Clamp]
-1.745V   1.225A     728.3mA    1.308A
-1.095V   335.6mA    258.4mA    270mA
-1.036V   258.6mA    217.1mA    188.3mA
-977.3mV  185.4mA    176.5mA    118.3mA
-918.2mV  120.1mA    137mA      69.03mA
-859.1mV  69.26mA    99.47mA    44.58mA
-800mV    39.67mA    65.74mA    34.04mA
-740.9mV  27.59mA    38.55mA    26.39mA
-681.8mV  20.92mA    20.62mA    19.72mA
-504.5mV  7.056mA    3.951mA    5.114mA
-209.1mV  34.99uA    28.35uA    3.931uA
3.573V    -414.4nA   -641.8nA   -5.534nA
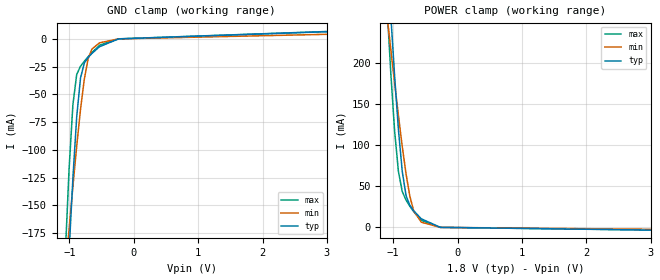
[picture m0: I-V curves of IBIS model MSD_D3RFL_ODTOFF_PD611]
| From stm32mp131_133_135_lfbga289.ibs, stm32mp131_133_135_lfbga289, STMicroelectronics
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[Model] MSD_D3RFL_ODTOFF_PD611
Model_type   Input
C_comp 2.396pF   2.335pF   2.543pF
Vinh = 1.440V
Vinl = 360.000mV
[Temperature Range]   25.000   125.000   -40.000
[Voltage Range]   1.800V   1.650V   1.950V
[GND Clamp Reference]   0.00V   0.00V   0.00V
[POWER Clamp Reference]   1.800V   1.650V   1.950V
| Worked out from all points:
|   GND clamp passes 1 mA (typ) near -0.34 V on its own axis
|   POWER clamp passes 1 mA (typ) near -0.35 V on its own axis
[GND Clamp]
-1.773V   -1.216A    -713.3mA   -1.315A
-1.064V   -264.4mA   -211.3mA   -194.4mA
-1.005V   -191.8mA   -171.6mA   -117.4mA
-945.5mV  -125.3mA   -133.1mA   -59.21mA
-886.4mV  -70.2mA    -96.7mA    -32.11mA
-827.3mV  -35.32mA   -63.62mA   -24.73mA
-768.2mV  -21.82mA   -36.31mA   -20.29mA
-709.1mV  -16.75mA   -18.01mA   -16.22mA
-650mV    -13.16mA   -9.247mA   -12.39mA
-531.8mV  -7.073mA   -3.601mA   -5.786mA
-236.4mV  -81.42uA   -40.03uA   -9.418uA
3.545V    7.542mA    4.762mA    7.716mA
[Power Clamp]
-1.745V   1.222A     726.5mA    1.305A
-1.095V   334.2mA    257.5mA    268.8mA
-1.036V   257.4mA    216.3mA    187.1mA
-977.3mV  184.3mA    175.8mA    117.3mA
-918.2mV  119.1mA    136.3mA    68.11mA
-859.1mV  68.36mA    98.89mA    43.78mA
-800mV    38.89mA    65.24mA    33.34mA
-740.9mV  26.92mA    38.12mA    25.81mA
-681.8mV  20.35mA    20.26mA    19.24mA
-563.6mV  10.55mA    6.424mA    8.702mA
-268.2mV  163uA      96.84uA    32.04uA
3.573V    -3.827mA   -2.641mA   -3.559mA
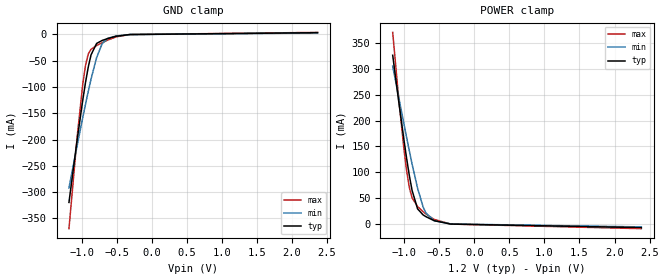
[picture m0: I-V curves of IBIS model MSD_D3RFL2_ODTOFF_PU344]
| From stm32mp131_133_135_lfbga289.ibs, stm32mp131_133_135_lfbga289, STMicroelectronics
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[Model] MSD_D3RFL2_ODTOFF_PU344
Model_type   Input
C_comp 2.348pF   2.261pF   2.473pF
Vinh = 820.000mV
Vinl = 380.000mV
[Temperature Range]   25.000   125.000   -40.000
[Voltage Range]   1.200V   1.140V   1.300V
[GND Clamp Reference]   0.00V   0.00V   0.00V
[POWER Clamp Reference]   1.200V   1.140V   1.300V
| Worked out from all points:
|   GND clamp passes 1 mA (typ) near -0.41 V on its own axis
|   POWER clamp passes 1 mA (typ) near -0.41 V on its own axis
[GND Clamp]
-1.182V   -319.5mA   -291.8mA   -369.4mA
-1.064V   -199.3mA   -210.6mA   -193.4mA
-984.9mV  -124.7mA   -158mA     -94.39mA
-945.5mV  -90.98mA   -132.6mA   -58.42mA
-906.1mV  -61.6mA    -108mA     -36.88mA
-866.7mV  -38.7mA    -84.71mA   -28.08mA
-787.9mV  -17.12mA   -44.15mA   -21.14mA
-709.1mV  -11.46mA   -17.68mA   -15.77mA
-630.3mV  -7.839mA   -7.45mA    -10.84mA
-512.1mV  -3.483mA   -2.928mA   -4.688mA
-315.1mV  -138.2uA   -193.6uA   -129.4uA
2.364V    3.331mA    2.81mA     3.927mA
[Power Clamp]
-1.164V   326mA      304.9mA    370.1mA
-1.085V   243.7mA    249.6mA    252.1mA
-1.006V   164.7mA    194.9mA    147.6mA
-966.7mV  127.9mA    168mA      104.3mA
-927.3mV  94.22mA    141.7mA    71.07mA
-887.9mV  65.34mA    116.2mA    50.69mA
-809.1mV  29.53mA    69.38mA    33.97mA
-730.3mV  17.87mA    33.23mA    24.08mA
-690.9mV  14.52mA    21.47mA    19.76mA
-572.7mV  6.774mA    6.689mA    9.092mA
-336.4mV  189.2uA    362.7uA    209.5uA
2.382V    -6.66mA    -5.295mA   -8.661mA
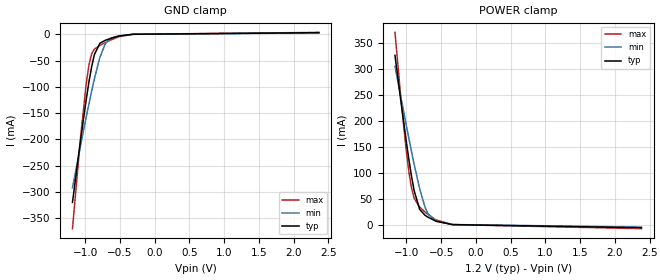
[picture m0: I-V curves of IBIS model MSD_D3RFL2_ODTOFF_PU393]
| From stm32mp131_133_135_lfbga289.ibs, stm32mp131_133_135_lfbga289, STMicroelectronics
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[Model] MSD_D3RFL2_ODTOFF_PU393
Model_type   Input
C_comp 2.377pF   2.291pF   2.503pF
Vinh = 820.000mV
Vinl = 380.000mV
[Temperature Range]   25.000   125.000   -40.000
[Voltage Range]   1.200V   1.140V   1.300V
[GND Clamp Reference]   0.00V   0.00V   0.00V
[POWER Clamp Reference]   1.200V   1.140V   1.300V
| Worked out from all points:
|   GND clamp passes 1 mA (typ) near -0.40 V on its own axis
|   POWER clamp passes 1 mA (typ) near -0.41 V on its own axis
[GND Clamp]
-1.182V   -319.8mA   -292.1mA   -369.7mA
-1.064V   -199.5mA   -210.7mA   -193.7mA
-984.9mV  -124.8mA   -158.2mA   -94.63mA
-945.5mV  -91.15mA   -132.7mA   -58.63mA
-906.1mV  -61.76mA   -108.1mA   -37.09mA
-866.7mV  -38.84mA   -84.83mA   -28.26mA
-787.9mV  -17.24mA   -44.25mA   -21.29mA
-709.1mV  -11.55mA   -17.77mA   -15.89mA
-630.3mV  -7.909mA   -7.517mA   -10.94mA
-512.1mV  -3.522mA   -2.967mA   -4.734mA
-315.1mV  -141.6uA   -201.6uA   -134.6uA
2.364V    2.915mA    2.459mA    3.436mA
[Power Clamp]
-1.164V   326.2mA    305.1mA    370.3mA
-1.085V   244mA      249.7mA    252.3mA
-1.006V   164.9mA    195mA      147.8mA
-966.7mV  128.1mA    168.2mA    104.5mA
-927.3mV  94.38mA    141.9mA    71.27mA
-887.9mV  65.49mA    116.3mA    50.88mA
-809.1mV  29.65mA    69.48mA    34.13mA
-730.3mV  17.96mA    33.31mA    24.2mA
-690.9mV  14.61mA    21.54mA    19.87mA
-572.7mV  6.824mA    6.735mA    9.153mA
-336.4mV  192.5uA    368.2uA    214.2uA
2.382V    -5.83mA    -4.627mA   -7.578mA
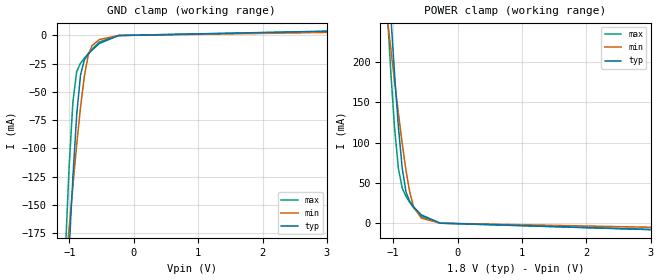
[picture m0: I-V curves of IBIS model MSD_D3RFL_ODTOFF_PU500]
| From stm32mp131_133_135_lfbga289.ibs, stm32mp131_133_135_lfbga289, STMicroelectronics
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[Model] MSD_D3RFL_ODTOFF_PU500
Model_type   Input
C_comp 2.368pF   2.307pF   2.515pF
Vinh = 1.440V
Vinl = 360.000mV
[Temperature Range]   25.000   125.000   -40.000
[Voltage Range]   1.800V   1.650V   1.950V
[GND Clamp Reference]   0.00V   0.00V   0.00V
[POWER Clamp Reference]   1.800V   1.650V   1.950V
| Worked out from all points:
|   GND clamp passes 1 mA (typ) near -0.34 V on its own axis
|   POWER clamp passes 1 mA (typ) near -0.35 V on its own axis
[GND Clamp]
-1.773V   -1.215A    -712.9mA   -1.314A
-1.064V   -264.1mA   -211.1mA   -194.1mA
-1.005V   -191.5mA   -171.4mA   -117.2mA
-945.5mV  -125mA     -133mA     -58.99mA
-886.4mV  -69.98mA   -96.61mA   -31.92mA
-827.3mV  -35.13mA   -63.5mA    -24.56mA
-768.2mV  -21.65mA   -36.19mA   -20.14mA
-709.1mV  -16.61mA   -17.92mA   -16.09mA
-650mV    -13.03mA   -9.167mA   -12.29mA
-531.8mV  -6.996mA   -3.553mA   -5.728mA
-236.4mV  -74.02uA   -35.01uA   -8.021uA
3.545V    4.502mA    3.171mA    4.182mA
[Power Clamp]
-1.745V   1.222A     726.2mA    1.305A
-1.095V   334.1mA    257.4mA    268.5mA
-1.036V   257.1mA    216.2mA    186.9mA
-977.3mV  184mA      175.7mA    117.1mA
-918.2mV  118.9mA    136.2mA    67.92mA
-859.1mV  68.19mA    98.82mA    43.61mA
-800mV    38.75mA    65.17mA    33.19mA
-740.9mV  26.8mA     38.06mA    25.68mA
-681.8mV  20.24mA    20.21mA    19.14mA
-563.6mV  10.49mA    6.395mA    8.646mA
-268.2mV  163.2uA    100.7uA    32.43uA
3.573V    -9.122mA   -5.892mA   -9.308mA
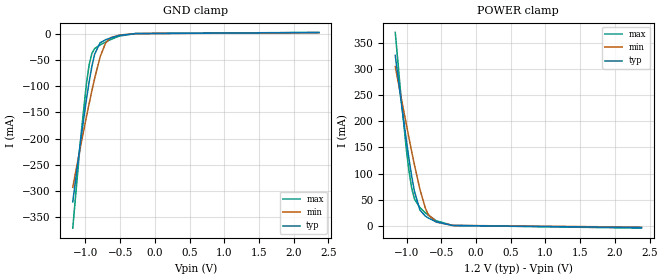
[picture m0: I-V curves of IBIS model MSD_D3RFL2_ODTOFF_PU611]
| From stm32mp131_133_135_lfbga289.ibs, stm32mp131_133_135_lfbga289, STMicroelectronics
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[Model] MSD_D3RFL2_ODTOFF_PU611
Model_type   Input
C_comp 2.451pF   2.364pF   2.578pF
Vinh = 820.000mV
Vinl = 380.000mV
[Temperature Range]   25.000   125.000   -40.000
[Voltage Range]   1.200V   1.140V   1.300V
[GND Clamp Reference]   0.00V   0.00V   0.00V
[POWER Clamp Reference]   1.200V   1.140V   1.300V
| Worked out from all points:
|   GND clamp passes 1 mA (typ) near -0.40 V on its own axis
|   POWER clamp passes 1 mA (typ) near -0.41 V on its own axis
[GND Clamp]
-1.182V   -320.5mA   -292.7mA   -370.4mA
-1.064V   -199.9mA   -211.2mA   -194.4mA
-984.9mV  -125.3mA   -158.5mA   -95.22mA
-945.5mV  -91.58mA   -133.1mA   -59.17mA
-906.1mV  -62.15mA   -108.5mA   -37.58mA
-866.7mV  -39.22mA   -85.14mA   -28.71mA
-787.9mV  -17.54mA   -44.51mA   -21.67mA
-709.1mV  -11.79mA   -17.96mA   -16.19mA
-630.3mV  -8.084mA   -7.664mA   -11.16mA
-512.1mV  -3.621mA   -3.051mA   -4.858mA
-275.8mV  -48.79uA   -87.59uA   -34.39uA
2.364V    1.873mA    1.581mA    2.209mA
[Power Clamp]
-1.164V   326.8mA    305.6mA    371.1mA
-1.085V   244.5mA    250.1mA    253mA
-1.006V   165.4mA    195.4mA    148.4mA
-966.7mV  128.5mA    168.6mA    105.1mA
-927.3mV  94.78mA    142.2mA    71.78mA
-887.9mV  65.85mA    116.7mA    51.35mA
-809.1mV  29.96mA    69.74mA    34.52mA
-730.3mV  18.2mA     33.52mA    24.52mA
-690.9mV  14.82mA    21.72mA    20.14mA
-572.7mV  6.952mA    6.849mA    9.318mA
-336.4mV  201.5uA    381.6uA    224.7uA
2.382V    -3.745mA   -2.981mA   -4.875mA
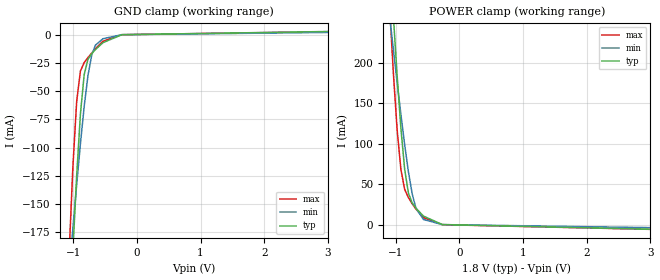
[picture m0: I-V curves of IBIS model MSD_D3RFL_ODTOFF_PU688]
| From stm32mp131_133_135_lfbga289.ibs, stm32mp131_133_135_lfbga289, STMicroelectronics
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[Model] MSD_D3RFL_ODTOFF_PU688
Model_type   Input
C_comp 2.410pF   2.348pF   2.557pF
Vinh = 1.440V
Vinl = 360.000mV
[Temperature Range]   25.000   125.000   -40.000
[Voltage Range]   1.800V   1.650V   1.950V
[GND Clamp Reference]   0.00V   0.00V   0.00V
[POWER Clamp Reference]   1.800V   1.650V   1.950V
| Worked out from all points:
|   GND clamp passes 1 mA (typ) near -0.34 V on its own axis
|   POWER clamp passes 1 mA (typ) near -0.34 V on its own axis
[GND Clamp]
-1.773V   -1.216A    -713.4mA   -1.315A
-1.064V   -264.5mA   -211.3mA   -194.5mA
-1.005V   -191.9mA   -171.6mA   -117.5mA
-945.5mV  -125.3mA   -133.2mA   -59.31mA
-886.4mV  -70.28mA   -96.74mA   -32.19mA
-827.3mV  -35.4mA    -63.65mA   -24.79mA
-768.2mV  -21.89mA   -36.32mA   -20.34mA
-709.1mV  -16.8mA    -18.03mA   -16.27mA
-650mV    -13.2mA    -9.264mA   -12.43mA
-531.8mV  -7.095mA   -3.607mA   -5.812mA
-236.4mV  -80.01uA   -36.01uA   -8.015uA
3.545V    3.274mA    2.306mA    3.042mA
[Power Clamp]
-1.745V   1.223A     726.8mA    1.305A
-1.095V   334.4mA    257.6mA    268.9mA
-1.036V   257.5mA    216.4mA    187.2mA
-977.3mV  184.4mA    175.9mA    117.4mA
-918.2mV  119.3mA    136.4mA    68.23mA
-859.1mV  68.49mA    99.01mA    43.88mA
-800mV    39mA       65.33mA    33.43mA
-740.9mV  27.01mA    38.19mA    25.88mA
-681.8mV  20.43mA    20.32mA    19.3mA
-563.6mV  10.6mA     6.463mA    8.743mA
-268.2mV  168.6uA    103.5uA    33.52uA
3.573V    -6.628mA   -4.287mA   -6.772mA
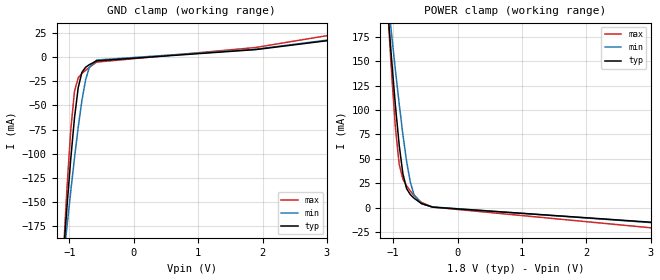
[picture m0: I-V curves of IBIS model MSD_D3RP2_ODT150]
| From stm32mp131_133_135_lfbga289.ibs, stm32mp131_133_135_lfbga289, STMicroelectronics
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[Model] MSD_D3RP2_ODT150
Model_type   Input
C_comp 2.177pF   2.112pF   2.238pF
Vinh = 1.150V
Vinl = 650.000mV
[Temperature Range]   25.000   125.000   -40.000
[Voltage Range]   1.800V   1.700V   1.900V
[GND Clamp Reference]   0.00V   0.00V   0.00V
[POWER Clamp Reference]   1.800V   1.700V   1.900V
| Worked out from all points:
|   GND clamp passes 1 mA (typ) near -0.44 V on its own axis
|   POWER clamp passes 1 mA (typ) near -0.42 V on its own axis
[GND Clamp]
-1.785V   -884.4mA   -672.6mA   -1.185A
-1.094V   -205.2mA   -210.9mA   -203.2mA
-1.036V   -153.4mA   -174.3mA   -133.9mA
-978.8mV  -105.2mA   -138.7mA   -75.34mA
-921.2mV  -63.16mA   -104.5mA   -35.71mA
-863.6mV  -31.93mA   -72.87mA   -21.6mA
-806.1mV  -16.02mA   -45.1mA    -17.19mA
-748.5mV  -10.71mA   -23.7mA    -13.87mA
-690.9mV  -8.061mA   -10.93mA   -10.77mA
-575.8mV  -4.07mA    -3.201mA   -5.347mA
1.9V      7.59mA     7.978mA    9.749mA
3.57V     21.4mA     22.17mA    28.23mA
[Power Clamp]
-1.77V    855.8mA    665.8mA    1.119A
-1.079V   198.5mA    211.6mA    197.3mA
-1.021V   149.1mA    175.5mA    134.5mA
-963.6mV  103.5mA    140.1mA    80.78mA
-906.1mV  64.07mA    106.2mA    44.48mA
-848.5mV  34.65mA    74.79mA    29.1mA
-790.9mV  19.55mA    47.33mA    22.46mA
-733.3mV  13.52mA    26.26mA    17.26mA
-675.8mV  9.818mA    13.39mA    12.67mA
-560.6mV  4.37mA     4.255mA    5.446mA
-387.9mV  648.6uA    874.3uA    716.4uA
3.585V    -17.41mA   -17.91mA   -24.1mA
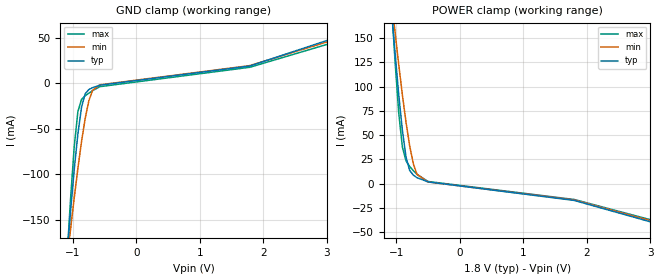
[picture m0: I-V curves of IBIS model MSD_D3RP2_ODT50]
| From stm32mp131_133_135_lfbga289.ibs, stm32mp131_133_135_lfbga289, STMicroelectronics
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[Model] MSD_D3RP2_ODT50
Model_type   Input
C_comp 2.129pF   2.093pF   2.153pF
Vinh = 1.150V
Vinl = 650.000mV
[Model Spec]
Vinh   1.150V   1.100V   1.200V
Vinl   650.000mV   600.000mV   700.000mV
[Temperature Range]   25.000   125.000   -40.000
[Voltage Range]   1.800V   1.700V   1.900V
[GND Clamp Reference]   0.00V   0.00V   0.00V
[POWER Clamp Reference]   1.800V   1.700V   1.900V
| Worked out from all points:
|   GND clamp passes 1 mA (typ) near -0.50 V on its own axis
|   POWER clamp passes 1 mA (typ) near -0.36 V on its own axis
[GND Clamp]
-1.785V   -856.4mA   -647.2mA   -1.164A
-1.094V   -189.8mA   -195.6mA   -193.8mA
-1.036V   -140.4mA   -160.3mA   -126.9mA
-978.8mV  -95.05mA   -126.1mA   -70.04mA
-921.2mV  -55.84mA   -93.73mA   -31.26mA
-863.6mV  -26.4mA    -64.17mA   -17.71mA
-806.1mV  -11.5mA    -38.71mA   -13.75mA
-748.5mV  -6.872mA   -19.32mA   -10.86mA
-690.9mV  -4.858mA   -7.903mA   -8.204mA
-575.8mV  -2.1mA     -1.674mA   -3.7mA
1.785V    18.98mA    19.43mA    17.58mA
3.57V     60.15mA    57.63mA    54.49mA
[Power Clamp]
-1.77V    818.7mA    633mA      1.093A
-1.079V   179.6mA    190.4mA    186.8mA
-1.021V   133.9mA    155.9mA    125.4mA
-963.6mV  91.82mA    122.6mA    72.91mA
-906.1mV  54.95mA    91.39mA    37.83mA
-848.5mV  27.33mA    63.06mA    23.51mA
-790.9mV  13.67mA    38.85mA    17.79mA
-733.3mV  8.878mA    20.55mA    13.44mA
-675.8mV  6.292mA    9.654mA    9.681mA
-503mV    1.974mA    1.886mA    2.383mA
1.8V      -17.1mA    -16.61mA   -16.13mA
3.585V    -49.84mA   -48.25mA   -47.06mA
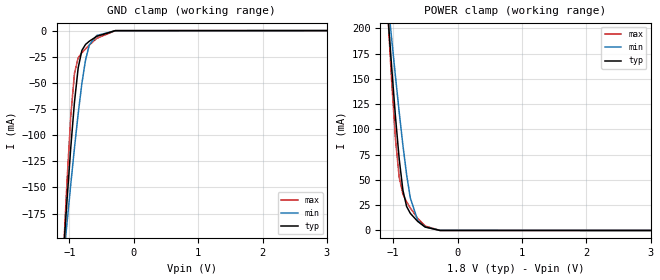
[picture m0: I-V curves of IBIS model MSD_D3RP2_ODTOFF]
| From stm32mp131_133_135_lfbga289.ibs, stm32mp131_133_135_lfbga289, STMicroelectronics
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[Model] MSD_D3RP2_ODTOFF
Model_type   Input
C_comp 2.221pF   2.142pF   2.337pF
Vinh = 1.150V
Vinl = 650.000mV
[Model Spec]
Vinh   1.150V   1.100V   1.200V
Vinl   650.000mV   600.000mV   700.000mV
[Temperature Range]   25.000   125.000   -40.000
[Voltage Range]   1.800V   1.700V   1.900V
[GND Clamp Reference]   0.00V   0.00V   0.00V
[POWER Clamp Reference]   1.800V   1.700V   1.900V
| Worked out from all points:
|   GND clamp passes 1 mA (typ) near -0.41 V on its own axis
|   POWER clamp passes 1 mA (typ) near -0.41 V on its own axis
[GND Clamp]
-1.785V   -899.6mA   -687.8mA   -1.207A
-1.094V   -214.3mA   -220.6mA   -214.7mA
-1.036V   -161.5mA   -183.4mA   -143mA
-978.8mV  -112mA     -147.1mA   -81.84mA
-921.2mV  -68.38mA   -112.2mA   -40.88mA
-863.6mV  -35.68mA   -79.52mA   -26.12mA
-806.1mV  -18.97mA   -50.56mA   -21.22mA
-748.5mV  -13.2mA    -27.77mA   -17.43mA
-690.9mV  -10.2mA    -13.79mA   -13.86mA
-575.8mV  -5.517mA   -4.735mA   -7.461mA
-287.9mV  -70.53uA   -119uA     -55.71uA
3.57V     33.93nA    572.8nA    3.709nA
[Power Clamp]
-1.77V    876.4mA    686.4mA    1.147A
-1.079V   211mA      225.3mA    210.2mA
-1.021V   159.9mA    188.4mA    145.5mA
-963.6mV  112.3mA    152.2mA    90.31mA
-906.1mV  70.8mA     117.2mA    52.68mA
-848.5mV  39.88mA    84.39mA    36.1mA
-790.9mV  23.74mA    55.21mA    28.44mA
-733.3mV  16.95mA    32.12mA    22.28mA
-618.2mV  8.937mA    9.714mA    11.91mA
-503mV    3.408mA    3.506mA    4.439mA
-272.7mV  29.94uA    100.2uA    29.64uA
3.585V    -51.59nA   -928.6nA   -5.522nA
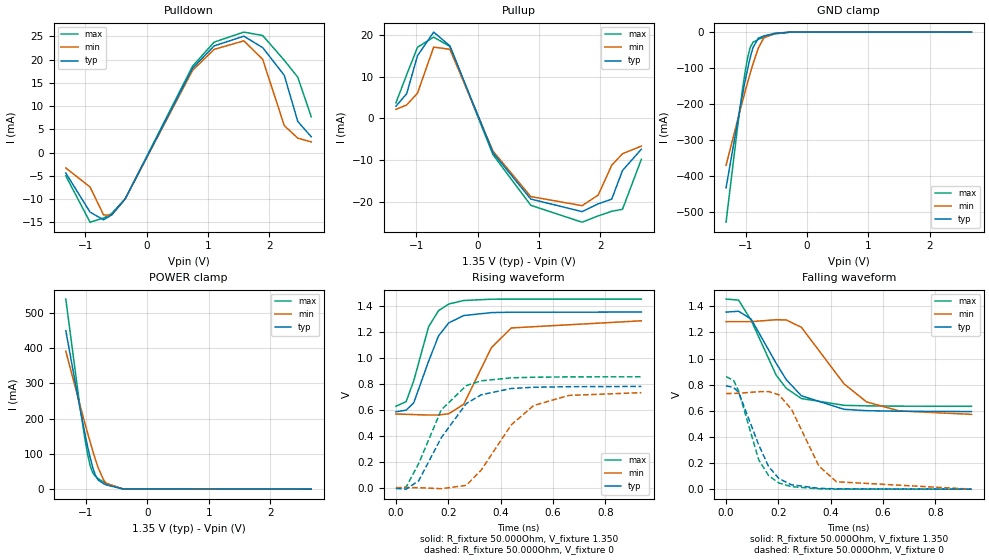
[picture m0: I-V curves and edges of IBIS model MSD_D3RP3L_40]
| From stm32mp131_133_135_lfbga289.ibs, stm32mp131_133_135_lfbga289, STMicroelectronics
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[Model] MSD_D3RP3L_40
Model_type   I/O
C_comp 2.240pF   2.158pF   2.357pF
Vinh = 810.000mV
Vinl = 540.000mV
Vmeas = 675.000mV
Vref = 675.000mV
[Model Spec]
Vinh   810.000mV   777.000mV   860.000mV
Vinl   540.000mV   507.000mV   590.000mV
Vmeas   675.000mV   642.000mV   725.000mV
Vref   675.000mV   642.000mV   725.000mV
[Receiver Thresholds]
Vth   =  0.675V
Vth_min  =  0.6615V
Vth_max  =  0.6885V
Vinh_ac  =  0.160V
Vinh_dc  =  0.090V
Vinl_ac  = -0.160V
Vinl_dc  = -0.090V
Tslew_ac =  5.000ns |Not specified, so set to high value
Threshold_sensitivity = 0.50
Reference_supply Pullup_ref
[Temperature Range]   25.000   125.000   -40.000
[Voltage Range]   1.350V   1.283V   1.450V
[GND Clamp Reference]   0.00V   0.00V   0.00V
[Pulldown Reference]   0.00V   0.00V   0.00V
[POWER Clamp Reference]   1.350V   1.283V   1.450V
[Pullup Reference]   1.350V   1.283V   1.450V
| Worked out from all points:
|   slope of the pulldown table from 0 to 0.203 V, typ, clamps not added: 35.7 ohm
|   slope of the pullup table from 0 to 0.203 V, typ, clamps not added: 29.7 ohm
|   GND clamp passes 1 mA (typ) near -0.41 V on its own axis
|   POWER clamp passes 1 mA (typ) near -0.41 V on its own axis
|   rising waveform, R_fixture 50.000Ohm, V_fixture 1.350: 20-80 % time 84.5ps typ, 105ps min, 72.5ps max; typ from 0.584 V to 1.35 V
|   rising waveform, R_fixture 50.000Ohm, V_fixture 0: 20-80 % time 138ps typ, 162ps min, 119ps max; typ from -0.006 V to 0.778 V
|   falling waveform, R_fixture 50.000Ohm, V_fixture 1.350: 20-80 % time 142ps typ, 169ps min, 122ps max; typ from 1.35 V to 0.594 V
|   falling waveform, R_fixture 50.000Ohm, V_fixture 0: 20-80 % time 92.8ps typ, 109ps min, 80.6ps max; typ from 0.792 V to 0 V
[GND Clamp]
-1.318V   -432mA     -369.8mA   -527.4mA
-1.142V   -260.2mA   -252.4mA   -279.5mA
-1.055V   -177.9mA   -195mA     -164.8mA
-1.011V   -138.8mA   -167mA     -113.9mA
-966.7mV  -102.2mA   -139.6mA   -71.13mA
-922.7mV  -69.41mA   -113.1mA   -41.59mA
-878.8mV  -42.86mA   -87.83mA   -28.26mA
-790.9mV  -16.84mA   -43.84mA   -20.19mA
-703mV    -10.77mA   -15.97mA   -14.59mA
-527.3mV  -3.881mA   -3.286mA   -5.179mA
-263.6mV  -34.33uA   -68.91uA   -22.73uA
2.68V     23.23nA    650.7nA    2.895nA
[Power Clamp]
-1.33V    448.9mA    390.9mA    538.4mA
-1.111V   240.1mA    246mA      248.4mA
-1.023V   161.2mA    189.4mA    146.7mA
-978.8mV  124.3mA    161.6mA    102.6mA
-934.9mV  90.54mA    134.5mA    67.58mA
-890.9mV  61.4mA     108.3mA    46.23mA
-847mV    39.26mA    83.52mA    35.86mA
-803mV    26.02mA    60.85mA    29.84mA
-715.1mV  15.45mA    26.31mA    20.45mA
-671.2mV  12.26mA    16.27mA    16.34mA
-407.6mV  879.8uA    1.157mA    1.067mA
2.668V    -39.9nA    -766.6nA   -3.595nA
[Pulldown]
-1.318V   -4.4mA     -3.3mA     -5mA
-922.7mV  -12.8mA    -7.4mA     -14.96mA
-703mV    -14.45mA   -13.4mA    -14.07mA
-571.2mV  -13.38mA   -13.44mA   -13.08mA
-351.5mV  -9.983mA   -9.961mA   -9.947mA
747mV     18.13mA    17.68mA    18.58mA
1.098V    22.93mA    22.18mA    23.74mA
1.582V    25.02mA    24.02mA    25.9mA
1.889V    22.57mA    20.05mA    25.16mA
2.241V    16.61mA    5.8mA      19.84mA
2.461V    6.7mA      3.1mA      16.2mA
2.68V     3.4mA      2.3mA      7.7mA
[Pullup]
-1.33V    2.9mA      2.152mA    3.707mA
-1.155V   5.9mA      3.21mA     10.44mA
-978.8mV  15mA       6.025mA    17.04mA
-715.1mV  20.67mA    17.07mA    19.46mA
-451.5mV  17.37mA    16.55mA    17.24mA
251.5mV   -8.247mA   -7.867mA   -8.716mA
866.7mV   -19.34mA   -18.75mA   -20.84mA
1.702V    -22.36mA   -20.93mA   -24.89mA
1.965V    -20.49mA   -18.4mA    -23.38mA
2.185V    -19.37mA   -11.25mA   -22.28mA
2.361V    -12.5mA    -8.49mA    -21.79mA
2.668V    -7.4mA     -6.648mA   -9.821mA
[Ramp]
R_load=50.000Ohm
dV/dt_r   460.500mV/111.500ps  434.099mV/135.000ps  500.460mV/96.000ps
dV/dt_f   460.470mV/117.000ps  434.099mV/141.000ps  500.460mV/101.500ps
[Rising waveform]
R_fixture=50.000Ohm
V_fixture=1.350
V_fixture_min=1.283
V_fixture_max=1.450
0s        583.5mV    566.3mV    626.1mV
39ps      595.6mV    564.1mV    661.2mV
68ps      652.3mV    562.1mV    821.4mV
125ps     972.5mV    558.5mV    1.238V
163ps     1.167V     558.9mV    1.361V
202ps     1.267V     568.4mV    1.412V
259ps     1.323V     641.2mV    1.439V
365ps     1.346V     1.077V     1.449V
441ps     1.349V     1.228V     1.45V
938ps     1.35V      1.283V     1.45V
[Rising waveform]
R_fixture=50.000Ohm
V_fixture=0
0s        -5.651mV   803uV      -5.529mV
39ps      -11.28mV   976.9uV    4.736mV
87ps      53.14mV    316.1uV    185.5mV
173ps     383.3mV    -7.78mV    597.2mV
269ps     647.1mV    18.17mV    784.8mV
326ps     714.1mV    135.7mV    821.5mV
441ps     762.7mV    483.7mV    844.6mV
527ps     772.1mV    632.5mV    849.3mV
662ps     776.5mV    709.5mV    851.9mV
938ps     778.4mV    730.5mV    852.5mV
[Falling waveform]
R_fixture=50.000Ohm
V_fixture=1.350
V_fixture_min=1.283
V_fixture_max=1.450
0s        1.355V     1.282V     1.455V
48ps      1.362V     1.282V     1.447V
96ps      1.301V     1.282V     1.292V
192ps     961.7mV    1.297V     870.9mV
230ps     838.6mV    1.295V     772.5mV
288ps     714.6mV    1.239V     693.8mV
451ps     611.1mV    805.9mV    641.7mV
537ps     600.9mV    667.7mV    637.6mV
662ps     596.5mV    599mV      635.4mV
938ps     594mV      572.5mV    634.3mV
[Falling waveform]
R_fixture=50.000Ohm
V_fixture=0
0s        791.6mV    731.9mV    861.8mV
29ps      777.8mV    732.8mV    831.7mV
48ps      741mV      734.3mV    751.5mV
125ps     338.4mV    745.9mV    223.9mV
163ps     171.7mV    747.1mV    102.9mV
202ps     81.67mV    722.3mV    47.35mV
250ps     33.52mV    612mV      19.25mV
355ps     6.299mV    176.4mV    2.907mV
422ps     2.404mV    56.6mV     861.4uV
938ps     4.695uV    122uV      3.321uV
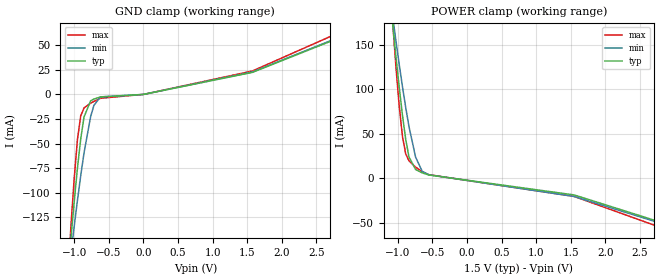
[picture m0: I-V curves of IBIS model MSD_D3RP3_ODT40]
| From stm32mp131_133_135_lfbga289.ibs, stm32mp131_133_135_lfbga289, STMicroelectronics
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[Model] MSD_D3RP3_ODT40
Model_type   Input
C_comp 2.131pF   2.093pF   2.203pF
Vinh = 925.000mV
Vinl = 575.000mV
[Temperature Range]   25.000   125.000   -40.000
[Voltage Range]   1.500V   1.425V   1.575V
[GND Clamp Reference]   0.00V   0.00V   0.00V
[POWER Clamp Reference]   1.500V   1.425V   1.575V
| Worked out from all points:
|   GND clamp passes 1 mA (typ) near -0.51 V on its own axis
|   POWER clamp passes 1 mA (typ) near -0.24 V on its own axis
[GND Clamp]
-1.48V    -547.8mA   -434.4mA   -709mA
-1.05V    -147.8mA   -162.7mA   -135.6mA
-1.002V   -109.8mA   -134.7mA   -86.38mA
-954.6mV  -75.15mA   -108mA     -46.12mA
-906.8mV  -45.3mA    -82.71mA   -21.8mA
-859.1mV  -22.96mA   -59.5mA    -13.72mA
-763.6mV  -6.5mA     -22.55mA   -8.924mA
-715.9mV  -4.73mA    -11.08mA   -7.09mA
-620.5mV  -2.58mA    -2.506mA   -3.882mA
900nV     12.29nA    11.53nA    14.04nA
1.575V    22.43mA    22.84mA    23.82mA
2.959V    61.11mA    61.81mA    66.92mA
[Power Clamp]
-1.459V   516.6mA    420.7mA    652.4mA
-1.077V   175.8mA    183.6mA    178.4mA
-1.03V    138.7mA    155.9mA    127.9mA
-981.8mV  103.6mA    129.1mA    82.75mA
-934.1mV  71.46mA    103.6mA    47.66mA
-886.4mV  43.89mA    79.79mA    27.61mA
-838.6mV  24.03mA    58.05mA    19.61mA
-743.2mV  9.987mA    23.83mA    12.6mA
-647.7mV  6.164mA    7.876mA    7.545mA
-552.3mV  3.822mA    4.028mA    4.133mA
1.548V    -18.62mA   -20.33mA   -20.29mA
2.98V     -53.72mA   -54.77mA   -60.26mA
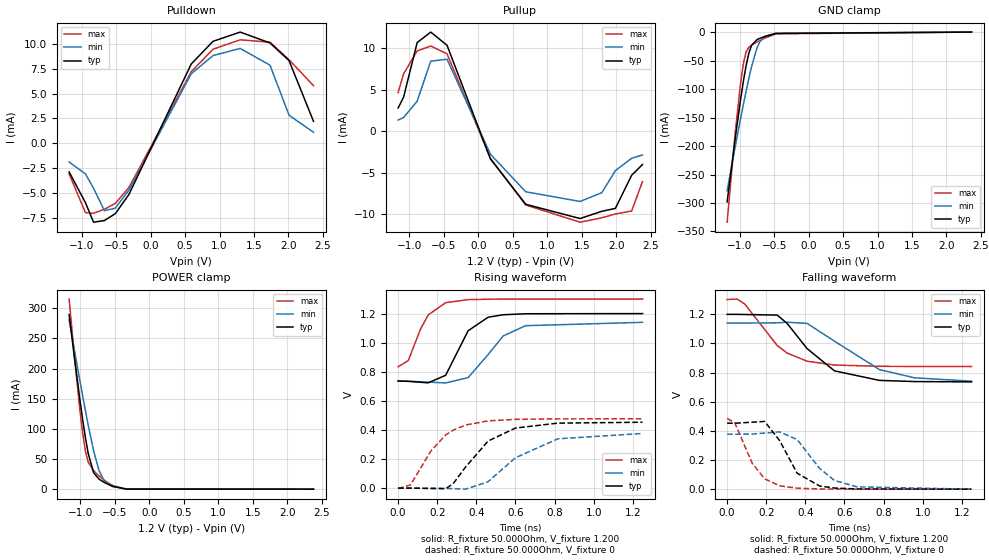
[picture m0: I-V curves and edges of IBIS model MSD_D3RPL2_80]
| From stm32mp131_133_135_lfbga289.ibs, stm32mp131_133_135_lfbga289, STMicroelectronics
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[Model] MSD_D3RPL2_80
Model_type   I/O
C_comp 2.247pF   2.165pF   2.365pF
Vinh = 820.000mV
Vinl = 380.000mV
Vmeas = 600.000mV
Vref = 600.000mV
[Model Spec]
Vinh   820.000mV   790.000mV   870.000mV
Vinl   380.000mV   350.000mV   430.000mV
Vmeas   600.000mV   570.000mV   650.000mV
Vref   600.000mV   570.000mV   650.000mV
[Receiver Thresholds]
Vth   =  0.600V
Vth_min  =  0.5880V
Vth_max  =  0.6120V
Vinh_ac  =  0.220V
Vinh_dc  =  0.130V
Vinl_ac  = -0.220V
Vinl_dc  = -0.130V
Tslew_ac =  5.000ns |Not specified, so set to high value
[Temperature Range]   25.000   125.000   -40.000
[Voltage Range]   1.200V   1.140V   1.300V
[GND Clamp Reference]   0.00V   0.00V   0.00V
[Pulldown Reference]   0.00V   0.00V   0.00V
[POWER Clamp Reference]   1.200V   1.140V   1.300V
[Pullup Reference]   1.200V   1.140V   1.300V
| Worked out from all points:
|   slope of the pulldown table from 0 to 0.18 V, typ, clamps not added: 63.6 ohm
|   slope of the pullup table from 0 to 0.18 V, typ, clamps not added: 52.8 ohm
|   GND clamp passes 1 mA (typ) near -0.41 V on its own axis
|   POWER clamp passes 1 mA (typ) near -0.41 V on its own axis
|   rising waveform, R_fixture 50.000Ohm, V_fixture 1.200: 20-80 % time 108ps typ, 144ps min, 94.7ps max; typ from 0.736 V to 1.2 V
|   rising waveform, R_fixture 50.000Ohm, V_fixture 0: 20-80 % time 186ps typ, 230ps min, 161ps max; typ from 0 V to 0.453 V
|   falling waveform, R_fixture 50.000Ohm, V_fixture 1.200: 20-80 % time 201ps typ, 270ps min, 182ps max; typ from 1.2 V to 0.736 V
|   falling waveform, R_fixture 50.000Ohm, V_fixture 0: 20-80 % time 113ps typ, 145ps min, 106ps max; typ from 0.453 V to 0 V
[GND Clamp]
-1.182V   -298.1mA   -278.5mA   -333.7mA
-1.064V   -186.2mA   -200.9mA   -176mA
-984.9mV  -117mA     -150.8mA   -87.54mA
-945.5mV  -85.76mA   -126.7mA   -54.85mA
-906.1mV  -58.45mA   -103.3mA   -34.84mA
-866.7mV  -37.02mA   -81.16mA   -26.5mA
-827.3mV  -23.29mA   -60.66mA   -22.76mA
-748.5mV  -13.2mA    -27.78mA   -17.43mA
-709.1mV  -11.06mA   -17.2mA    -14.96mA
-630.3mV  -7.603mA   -7.31mA    -10.35mA
-472.7mV  -2.342mA   -2.056mA   -3.036mA
2.364V    24.05nA    406.6nA    2.608nA
[Power Clamp]
-1.164V   289.6mA    280.7mA    315.2mA
-1.085V   216.5mA    229.3mA    217.2mA
-1.006V   146.9mA    178.8mA    129.3mA
-966.7mV  114.6mA    154.1mA    91.94mA
-927.3mV  85.12mA    129.9mA    62.94mA
-887.9mV  59.62mA    106.5mA    45.07mA
-809.1mV  27.34mA    63.75mA    30.55mA
-730.3mV  16.69mA    30.8mA     21.95mA
-651.5mV  10.97mA    13.15mA    14.62mA
-533.3mV  4.62mA     4.579mA    6.036mA
-336.4mV  182.5uA    350.8uA    204.6uA
2.382V    -20.25nA   -432nA     -2.133nA
[Pulldown]
-1.182V   -2.9mA     -1.9mA     -3.1mA
-945.5mV  -6mA       -3.1mA     -7mA
-827.3mV  -7.97mA    -4.55mA    -7.07mA
-669.7mV  -7.805mA   -6.81mA    -6.66mA
-512.1mV  -7.111mA   -6.555mA   -6.076mA
-315.1mV  -5.18mA    -4.739mA   -4.478mA
590.9mV   8.001mA    7.015mA    7.22mA
906.1mV   10.28mA    8.84mA     9.487mA
1.3V      11.21mA    9.561mA    10.43mA
1.733V    10.11mA    7.867mA    10.19mA
2.009V    8.33mA     2.82mA     8.42mA
2.364V    2.2mA      1.1mA      5.8mA
[Pullup]
-1.164V   2.8mA      1.352mA    4.662mA
-1.085V   4.1mA      1.657mA    6.916mA
-887.9mV  10.68mA    3.619mA    9.683mA
-690.9mV  11.95mA    8.445mA    10.27mA
-454.5mV  10.36mA    8.676mA    9.332mA
175.8mV   -3.334mA   -2.766mA   -3.263mA
687.9mV   -8.798mA   -7.289mA   -8.879mA
1.476V    -10.51mA   -8.453mA   -10.95mA
1.791V    -9.638mA   -7.398mA   -10.42mA
1.988V    -9.29mA    -4.744mA   -9.962mA
2.224V    -5.3mA     -3.248mA   -9.605mA
2.382V    -4mA       -2.848mA   -6.038mA
[Ramp]
R_load=50.000Ohm
dV/dt_r   275.100mV/148.500ps  234.149mV/189.500ps  280.380mV/128.500ps
dV/dt_f   275.100mV/158.000ps  234.090mV/212.000ps  280.380mV/144.500ps
[Rising waveform]
R_fixture=50.000Ohm
V_fixture=1.200
V_fixture_min=1.140
V_fixture_max=1.300
0s        736.5mV    736.8mV    834mV
52ps      734.4mV    735.3mV    877.5mV
115ps     728mV      731.7mV    1.095V
154ps     724.1mV    728.8mV    1.191V
243ps     775.9mV    723.4mV    1.275V
358ps     1.082V     759.8mV    1.296V
460ps     1.175V     918mV      1.299V
537ps     1.192V     1.046V     1.3V
652ps     1.199V     1.117V     1.3V
1.25ns    1.2V       1.14V      1.3V
[Rising waveform]
R_fixture=50.000Ohm
V_fixture=0
0s        90.54uV    101.7uV    -2.695mV
64ps      570.1uV    382.9uV    22.69mV
166ps     -2.598mV   514.2uV    252.6mV
243ps     -3.814mV   -1.272mV   365.6mV
281ps     29.85mV    -3.374mV   398.5mV
345ps     145.4mV    -6.876mV   434.1mV
460ps     323.8mV    44.29mV    462.5mV
600ps     413.3mV    209.1mV    473mV
817ps     447.1mV    339.2mV    476.4mV
1.25ns    453.3mV    376mV      476.8mV
[Falling waveform]
R_fixture=50.000Ohm
V_fixture=1.200
V_fixture_min=1.140
V_fixture_max=1.300
0s        1.2V       1.14V      1.302V
52ps      1.2V       1.14V      1.305V
90ps      1.199V     1.14V      1.271V
256ps     1.195V     1.142V     986.3mV
307ps     1.138V     1.146V     934.3mV
409ps     964.7mV    1.138V     878.3mV
549ps     812.2mV    1.016V     852.2mV
779ps     746.7mV    820.9mV    843.3mV
958ps     738.7mV    764.3mV    842.3mV
1.25ns    736.4mV    741.2mV    842.2mV
[Falling waveform]
R_fixture=50.000Ohm
V_fixture=0
0s        453mV      377.1mV    485.3mV
39ps      452.6mV    376.9mV    456.6mV
128ps     459.6mV    378.2mV    178.5mV
192ps     465.1mV    384.9mV    70.86mV
269ps     332.6mV    393.4mV    23.07mV
358ps     109.7mV    340.5mV    6.423mV
473ps     21.66mV    142.5mV    1.324mV
549ps     7.755mV    59.73mV    385.8uV
664ps     1.537mV    15.71mV    -21.98uV
1.25ns    8.085uV    10.59uV    -7.464uV
